###############################################################
#  Generated by:      Cadence Innovus 22.16-s082_1
#  OS:                Linux x86_64(Host ID localhost.localdomain)
#  Generated on:      Fri Apr 10 17:59:03 2026
#  Design:            veer_wrapper
#  Command:           write_lef_abstract -extractBlockObs -cutObsMinSpacing -specifyTopLayer TopMetal2 -5.8 -extractBlockPGPinLayers {TopMetal1 TopMetal2} output/06_postRoute/veer_wrapper.lef
###############################################################

VERSION 5.8 ;

BUSBITCHARS "[]" ;
DIVIDERCHAR "/" ;

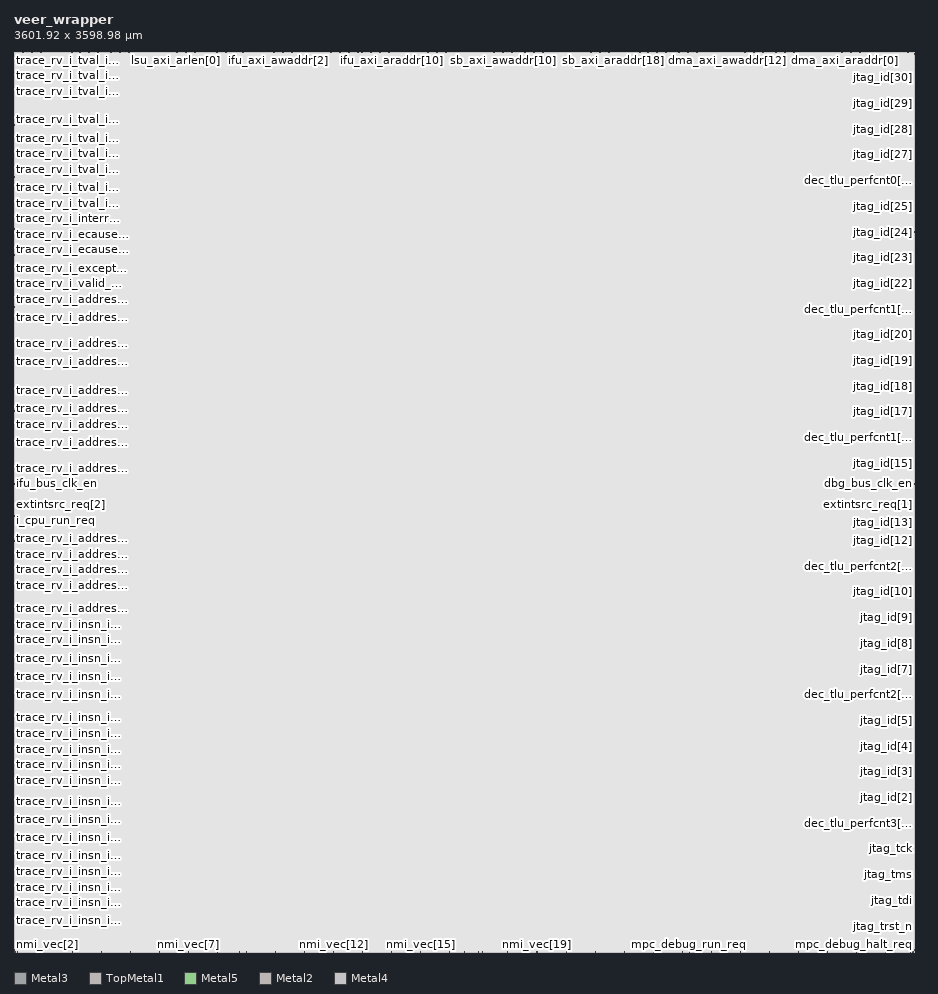
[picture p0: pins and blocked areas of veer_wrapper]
MACRO veer_wrapper
  CLASS BLOCK ;
  SIZE 3601.920000 BY 3598.980000 ;
  FOREIGN veer_wrapper 0.000000 0.000000 ;
  ORIGIN 0 0 ;
  SYMMETRY X Y R90 ;
  PIN clk
    DIRECTION INPUT ;
    USE SIGNAL ;
    PORT
      LAYER Metal3 ;
        RECT 3103.580000 3598.260000 3103.780000 3598.980000 ;
    END
  END clk
  PIN rst_l
    DIRECTION INPUT ;
    USE SIGNAL ;
    PORT
      LAYER Metal3 ;
        RECT 3591.740000 0.000000 3591.940000 0.720000 ;
    END
  END rst_l
  PIN dbg_rst_l
    DIRECTION INPUT ;
    USE SIGNAL ;
    PORT
      LAYER TopMetal1 ;
        RECT 0.000000 1742.600000 1.640000 1744.240000 ;
    END
  END dbg_rst_l
  PIN rst_vec[31]
    DIRECTION INPUT ;
    USE SIGNAL ;
    PORT
      LAYER Metal3 ;
        RECT 3485.180000 0.000000 3485.380000 0.720000 ;
    END
  END rst_vec[31]
  PIN rst_vec[30]
    DIRECTION INPUT ;
    USE SIGNAL ;
    PORT
      LAYER Metal3 ;
        RECT 3369.020000 0.000000 3369.220000 0.720000 ;
    END
  END rst_vec[30]
  PIN rst_vec[29]
    DIRECTION INPUT ;
    USE SIGNAL ;
    PORT
      LAYER Metal3 ;
        RECT 3252.860000 0.000000 3253.060000 0.720000 ;
    END
  END rst_vec[29]
  PIN rst_vec[28]
    DIRECTION INPUT ;
    USE SIGNAL ;
    PORT
      LAYER Metal3 ;
        RECT 3136.700000 0.000000 3136.900000 0.720000 ;
    END
  END rst_vec[28]
  PIN rst_vec[27]
    DIRECTION INPUT ;
    USE SIGNAL ;
    PORT
      LAYER Metal3 ;
        RECT 3020.540000 0.000000 3020.740000 0.720000 ;
    END
  END rst_vec[27]
  PIN rst_vec[26]
    DIRECTION INPUT ;
    USE SIGNAL ;
    PORT
      LAYER Metal3 ;
        RECT 2904.380000 0.000000 2904.580000 0.720000 ;
    END
  END rst_vec[26]
  PIN rst_vec[25]
    DIRECTION INPUT ;
    USE SIGNAL ;
    PORT
      LAYER Metal3 ;
        RECT 2788.220000 0.000000 2788.420000 0.720000 ;
    END
  END rst_vec[25]
  PIN rst_vec[24]
    DIRECTION INPUT ;
    USE SIGNAL ;
    PORT
      LAYER Metal3 ;
        RECT 2672.060000 0.000000 2672.260000 0.720000 ;
    END
  END rst_vec[24]
  PIN rst_vec[23]
    DIRECTION INPUT ;
    USE SIGNAL ;
    PORT
      LAYER Metal3 ;
        RECT 2555.900000 0.000000 2556.100000 0.720000 ;
    END
  END rst_vec[23]
  PIN rst_vec[22]
    DIRECTION INPUT ;
    USE SIGNAL ;
    PORT
      LAYER Metal3 ;
        RECT 2439.740000 0.000000 2439.940000 0.720000 ;
    END
  END rst_vec[22]
  PIN rst_vec[21]
    DIRECTION INPUT ;
    USE SIGNAL ;
    PORT
      LAYER Metal3 ;
        RECT 2323.580000 0.000000 2323.780000 0.720000 ;
    END
  END rst_vec[21]
  PIN rst_vec[20]
    DIRECTION INPUT ;
    USE SIGNAL ;
    PORT
      LAYER Metal3 ;
        RECT 2207.420000 0.000000 2207.620000 0.720000 ;
    END
  END rst_vec[20]
  PIN rst_vec[19]
    DIRECTION INPUT ;
    USE SIGNAL ;
    PORT
      LAYER Metal3 ;
        RECT 2091.260000 0.000000 2091.460000 0.720000 ;
    END
  END rst_vec[19]
  PIN rst_vec[18]
    DIRECTION INPUT ;
    USE SIGNAL ;
    PORT
      LAYER Metal3 ;
        RECT 1975.100000 0.000000 1975.300000 0.720000 ;
    END
  END rst_vec[18]
  PIN rst_vec[17]
    DIRECTION INPUT ;
    USE SIGNAL ;
    PORT
      LAYER Metal3 ;
        RECT 1858.940000 0.000000 1859.140000 0.720000 ;
    END
  END rst_vec[17]
  PIN rst_vec[16]
    DIRECTION INPUT ;
    USE SIGNAL ;
    PORT
      LAYER Metal3 ;
        RECT 1742.780000 0.000000 1742.980000 0.720000 ;
    END
  END rst_vec[16]
  PIN rst_vec[15]
    DIRECTION INPUT ;
    USE SIGNAL ;
    PORT
      LAYER Metal3 ;
        RECT 1626.620000 0.000000 1626.820000 0.720000 ;
    END
  END rst_vec[15]
  PIN rst_vec[14]
    DIRECTION INPUT ;
    USE SIGNAL ;
    PORT
      LAYER Metal3 ;
        RECT 1510.460000 0.000000 1510.660000 0.720000 ;
    END
  END rst_vec[14]
  PIN rst_vec[13]
    DIRECTION INPUT ;
    USE SIGNAL ;
    PORT
      LAYER Metal3 ;
        RECT 1394.300000 0.000000 1394.500000 0.720000 ;
    END
  END rst_vec[13]
  PIN rst_vec[12]
    DIRECTION INPUT ;
    USE SIGNAL ;
    PORT
      LAYER Metal3 ;
        RECT 1278.140000 0.000000 1278.340000 0.720000 ;
    END
  END rst_vec[12]
  PIN rst_vec[11]
    DIRECTION INPUT ;
    USE SIGNAL ;
    PORT
      LAYER Metal3 ;
        RECT 1161.980000 0.000000 1162.180000 0.720000 ;
    END
  END rst_vec[11]
  PIN rst_vec[10]
    DIRECTION INPUT ;
    USE SIGNAL ;
    PORT
      LAYER Metal3 ;
        RECT 1045.820000 0.000000 1046.020000 0.720000 ;
    END
  END rst_vec[10]
  PIN rst_vec[9]
    DIRECTION INPUT ;
    USE SIGNAL ;
    PORT
      LAYER Metal3 ;
        RECT 929.660000 0.000000 929.860000 0.720000 ;
    END
  END rst_vec[9]
  PIN rst_vec[8]
    DIRECTION INPUT ;
    USE SIGNAL ;
    PORT
      LAYER Metal3 ;
        RECT 813.500000 0.000000 813.700000 0.720000 ;
    END
  END rst_vec[8]
  PIN rst_vec[7]
    DIRECTION INPUT ;
    USE SIGNAL ;
    PORT
      LAYER Metal3 ;
        RECT 697.340000 0.000000 697.540000 0.720000 ;
    END
  END rst_vec[7]
  PIN rst_vec[6]
    DIRECTION INPUT ;
    USE SIGNAL ;
    PORT
      LAYER Metal3 ;
        RECT 581.180000 0.000000 581.380000 0.720000 ;
    END
  END rst_vec[6]
  PIN rst_vec[5]
    DIRECTION INPUT ;
    USE SIGNAL ;
    PORT
      LAYER Metal3 ;
        RECT 465.020000 0.000000 465.220000 0.720000 ;
    END
  END rst_vec[5]
  PIN rst_vec[4]
    DIRECTION INPUT ;
    USE SIGNAL ;
    PORT
      LAYER Metal3 ;
        RECT 348.860000 0.000000 349.060000 0.720000 ;
    END
  END rst_vec[4]
  PIN rst_vec[3]
    DIRECTION INPUT ;
    USE SIGNAL ;
    PORT
      LAYER Metal3 ;
        RECT 232.700000 0.000000 232.900000 0.720000 ;
    END
  END rst_vec[3]
  PIN rst_vec[2]
    DIRECTION INPUT ;
    USE SIGNAL ;
    PORT
      LAYER Metal3 ;
        RECT 116.540000 0.000000 116.740000 0.720000 ;
    END
  END rst_vec[2]
  PIN rst_vec[1]
    DIRECTION INPUT ;
    USE SIGNAL ;
    PORT
      LAYER Metal3 ;
        RECT 7.100000 0.000000 7.300000 0.720000 ;
    END
  END rst_vec[1]
  PIN nmi_int
    DIRECTION INPUT ;
    USE SIGNAL ;
    PORT
      LAYER Metal5 ;
        RECT 3597.500000 0.000000 3597.700000 0.720000 ;
    END
  END nmi_int
  PIN nmi_vec[31]
    DIRECTION INPUT ;
    USE SIGNAL ;
    PORT
      LAYER Metal5 ;
        RECT 3485.180000 0.000000 3485.380000 0.720000 ;
    END
  END nmi_vec[31]
  PIN nmi_vec[30]
    DIRECTION INPUT ;
    USE SIGNAL ;
    PORT
      LAYER Metal5 ;
        RECT 3369.020000 0.000000 3369.220000 0.720000 ;
    END
  END nmi_vec[30]
  PIN nmi_vec[29]
    DIRECTION INPUT ;
    USE SIGNAL ;
    PORT
      LAYER Metal5 ;
        RECT 3252.860000 0.000000 3253.060000 0.720000 ;
    END
  END nmi_vec[29]
  PIN nmi_vec[28]
    DIRECTION INPUT ;
    USE SIGNAL ;
    PORT
      LAYER Metal5 ;
        RECT 3136.700000 0.000000 3136.900000 0.720000 ;
    END
  END nmi_vec[28]
  PIN nmi_vec[27]
    DIRECTION INPUT ;
    USE SIGNAL ;
    PORT
      LAYER Metal5 ;
        RECT 3020.540000 0.000000 3020.740000 0.720000 ;
    END
  END nmi_vec[27]
  PIN nmi_vec[26]
    DIRECTION INPUT ;
    USE SIGNAL ;
    PORT
      LAYER Metal5 ;
        RECT 2904.380000 0.000000 2904.580000 0.720000 ;
    END
  END nmi_vec[26]
  PIN nmi_vec[25]
    DIRECTION INPUT ;
    USE SIGNAL ;
    PORT
      LAYER Metal5 ;
        RECT 2788.220000 0.000000 2788.420000 0.720000 ;
    END
  END nmi_vec[25]
  PIN nmi_vec[24]
    DIRECTION INPUT ;
    USE SIGNAL ;
    PORT
      LAYER Metal5 ;
        RECT 2672.060000 0.000000 2672.260000 0.720000 ;
    END
  END nmi_vec[24]
  PIN nmi_vec[23]
    DIRECTION INPUT ;
    USE SIGNAL ;
    PORT
      LAYER Metal5 ;
        RECT 2555.900000 0.000000 2556.100000 0.720000 ;
    END
  END nmi_vec[23]
  PIN nmi_vec[22]
    DIRECTION INPUT ;
    USE SIGNAL ;
    PORT
      LAYER Metal5 ;
        RECT 2439.740000 0.000000 2439.940000 0.720000 ;
    END
  END nmi_vec[22]
  PIN nmi_vec[21]
    DIRECTION INPUT ;
    USE SIGNAL ;
    PORT
      LAYER Metal5 ;
        RECT 2323.580000 0.000000 2323.780000 0.720000 ;
    END
  END nmi_vec[21]
  PIN nmi_vec[20]
    DIRECTION INPUT ;
    USE SIGNAL ;
    PORT
      LAYER Metal5 ;
        RECT 2207.420000 0.000000 2207.620000 0.720000 ;
    END
  END nmi_vec[20]
  PIN nmi_vec[19]
    DIRECTION INPUT ;
    USE SIGNAL ;
    PORT
      LAYER Metal5 ;
        RECT 2091.260000 0.000000 2091.460000 0.720000 ;
    END
  END nmi_vec[19]
  PIN nmi_vec[18]
    DIRECTION INPUT ;
    USE SIGNAL ;
    PORT
      LAYER Metal5 ;
        RECT 1975.100000 0.000000 1975.300000 0.720000 ;
    END
  END nmi_vec[18]
  PIN nmi_vec[17]
    DIRECTION INPUT ;
    USE SIGNAL ;
    PORT
      LAYER Metal5 ;
        RECT 1858.940000 0.000000 1859.140000 0.720000 ;
    END
  END nmi_vec[17]
  PIN nmi_vec[16]
    DIRECTION INPUT ;
    USE SIGNAL ;
    PORT
      LAYER Metal5 ;
        RECT 1742.780000 0.000000 1742.980000 0.720000 ;
    END
  END nmi_vec[16]
  PIN nmi_vec[15]
    DIRECTION INPUT ;
    USE SIGNAL ;
    PORT
      LAYER Metal5 ;
        RECT 1626.620000 0.000000 1626.820000 0.720000 ;
    END
  END nmi_vec[15]
  PIN nmi_vec[14]
    DIRECTION INPUT ;
    USE SIGNAL ;
    PORT
      LAYER Metal5 ;
        RECT 1510.460000 0.000000 1510.660000 0.720000 ;
    END
  END nmi_vec[14]
  PIN nmi_vec[13]
    DIRECTION INPUT ;
    USE SIGNAL ;
    PORT
      LAYER Metal5 ;
        RECT 1394.300000 0.000000 1394.500000 0.720000 ;
    END
  END nmi_vec[13]
  PIN nmi_vec[12]
    DIRECTION INPUT ;
    USE SIGNAL ;
    PORT
      LAYER Metal5 ;
        RECT 1278.140000 0.000000 1278.340000 0.720000 ;
    END
  END nmi_vec[12]
  PIN nmi_vec[11]
    DIRECTION INPUT ;
    USE SIGNAL ;
    PORT
      LAYER Metal5 ;
        RECT 1161.980000 0.000000 1162.180000 0.720000 ;
    END
  END nmi_vec[11]
  PIN nmi_vec[10]
    DIRECTION INPUT ;
    USE SIGNAL ;
    PORT
      LAYER Metal5 ;
        RECT 1045.820000 0.000000 1046.020000 0.720000 ;
    END
  END nmi_vec[10]
  PIN nmi_vec[9]
    DIRECTION INPUT ;
    USE SIGNAL ;
    PORT
      LAYER Metal5 ;
        RECT 929.660000 0.000000 929.860000 0.720000 ;
    END
  END nmi_vec[9]
  PIN nmi_vec[8]
    DIRECTION INPUT ;
    USE SIGNAL ;
    PORT
      LAYER Metal5 ;
        RECT 813.500000 0.000000 813.700000 0.720000 ;
    END
  END nmi_vec[8]
  PIN nmi_vec[7]
    DIRECTION INPUT ;
    USE SIGNAL ;
    PORT
      LAYER Metal5 ;
        RECT 697.340000 0.000000 697.540000 0.720000 ;
    END
  END nmi_vec[7]
  PIN nmi_vec[6]
    DIRECTION INPUT ;
    USE SIGNAL ;
    PORT
      LAYER Metal5 ;
        RECT 581.180000 0.000000 581.380000 0.720000 ;
    END
  END nmi_vec[6]
  PIN nmi_vec[5]
    DIRECTION INPUT ;
    USE SIGNAL ;
    PORT
      LAYER Metal5 ;
        RECT 465.020000 0.000000 465.220000 0.720000 ;
    END
  END nmi_vec[5]
  PIN nmi_vec[4]
    DIRECTION INPUT ;
    USE SIGNAL ;
    PORT
      LAYER Metal5 ;
        RECT 348.860000 0.000000 349.060000 0.720000 ;
    END
  END nmi_vec[4]
  PIN nmi_vec[3]
    DIRECTION INPUT ;
    USE SIGNAL ;
    PORT
      LAYER Metal5 ;
        RECT 232.700000 0.000000 232.900000 0.720000 ;
    END
  END nmi_vec[3]
  PIN nmi_vec[2]
    DIRECTION INPUT ;
    USE SIGNAL ;
    PORT
      LAYER Metal5 ;
        RECT 116.540000 0.000000 116.740000 0.720000 ;
    END
  END nmi_vec[2]
  PIN nmi_vec[1]
    DIRECTION INPUT ;
    USE SIGNAL ;
    PORT
      LAYER Metal5 ;
        RECT 3.740000 0.000000 3.940000 0.720000 ;
    END
  END nmi_vec[1]
  PIN jtag_id[31]
    DIRECTION INPUT ;
    USE SIGNAL ;
    PORT
      LAYER Metal2 ;
        RECT 3601.200000 3590.900000 3601.920000 3591.100000 ;
    END
  END jtag_id[31]
  PIN jtag_id[30]
    DIRECTION INPUT ;
    USE SIGNAL ;
    PORT
      LAYER Metal2 ;
        RECT 3601.200000 3495.980000 3601.920000 3496.180000 ;
    END
  END jtag_id[30]
  PIN jtag_id[29]
    DIRECTION INPUT ;
    USE SIGNAL ;
    PORT
      LAYER Metal2 ;
        RECT 3601.200000 3393.080000 3601.920000 3393.280000 ;
    END
  END jtag_id[29]
  PIN jtag_id[28]
    DIRECTION INPUT ;
    USE SIGNAL ;
    PORT
      LAYER Metal2 ;
        RECT 3601.200000 3290.180000 3601.920000 3290.380000 ;
    END
  END jtag_id[28]
  PIN jtag_id[27]
    DIRECTION INPUT ;
    USE SIGNAL ;
    PORT
      LAYER Metal2 ;
        RECT 3601.200000 3187.280000 3601.920000 3187.480000 ;
    END
  END jtag_id[27]
  PIN jtag_id[26]
    DIRECTION INPUT ;
    USE SIGNAL ;
    PORT
      LAYER Metal2 ;
        RECT 3601.200000 3084.800000 3601.920000 3085.000000 ;
    END
  END jtag_id[26]
  PIN jtag_id[25]
    DIRECTION INPUT ;
    USE SIGNAL ;
    PORT
      LAYER Metal2 ;
        RECT 3601.200000 2981.900000 3601.920000 2982.100000 ;
    END
  END jtag_id[25]
  PIN jtag_id[24]
    DIRECTION INPUT ;
    USE SIGNAL ;
    PORT
      LAYER Metal2 ;
        RECT 3601.200000 2879.000000 3601.920000 2879.200000 ;
    END
  END jtag_id[24]
  PIN jtag_id[23]
    DIRECTION INPUT ;
    USE SIGNAL ;
    PORT
      LAYER Metal2 ;
        RECT 3601.200000 2776.100000 3601.920000 2776.300000 ;
    END
  END jtag_id[23]
  PIN jtag_id[22]
    DIRECTION INPUT ;
    USE SIGNAL ;
    PORT
      LAYER Metal2 ;
        RECT 3601.200000 2673.620000 3601.920000 2673.820000 ;
    END
  END jtag_id[22]
  PIN jtag_id[21]
    DIRECTION INPUT ;
    USE SIGNAL ;
    PORT
      LAYER Metal2 ;
        RECT 3601.200000 2570.720000 3601.920000 2570.920000 ;
    END
  END jtag_id[21]
  PIN jtag_id[20]
    DIRECTION INPUT ;
    USE SIGNAL ;
    PORT
      LAYER Metal2 ;
        RECT 3601.200000 2467.820000 3601.920000 2468.020000 ;
    END
  END jtag_id[20]
  PIN jtag_id[19]
    DIRECTION INPUT ;
    USE SIGNAL ;
    PORT
      LAYER Metal2 ;
        RECT 3601.200000 2364.920000 3601.920000 2365.120000 ;
    END
  END jtag_id[19]
  PIN jtag_id[18]
    DIRECTION INPUT ;
    USE SIGNAL ;
    PORT
      LAYER Metal2 ;
        RECT 3601.200000 2262.020000 3601.920000 2262.220000 ;
    END
  END jtag_id[18]
  PIN jtag_id[17]
    DIRECTION INPUT ;
    USE SIGNAL ;
    PORT
      LAYER Metal2 ;
        RECT 3601.200000 2159.540000 3601.920000 2159.740000 ;
    END
  END jtag_id[17]
  PIN jtag_id[16]
    DIRECTION INPUT ;
    USE SIGNAL ;
    PORT
      LAYER Metal2 ;
        RECT 3601.200000 2056.640000 3601.920000 2056.840000 ;
    END
  END jtag_id[16]
  PIN jtag_id[15]
    DIRECTION INPUT ;
    USE SIGNAL ;
    PORT
      LAYER Metal2 ;
        RECT 3601.200000 1953.740000 3601.920000 1953.940000 ;
    END
  END jtag_id[15]
  PIN jtag_id[14]
    DIRECTION INPUT ;
    USE SIGNAL ;
    PORT
      LAYER Metal2 ;
        RECT 3601.200000 1850.840000 3601.920000 1851.040000 ;
    END
  END jtag_id[14]
  PIN jtag_id[13]
    DIRECTION INPUT ;
    USE SIGNAL ;
    PORT
      LAYER Metal2 ;
        RECT 3601.200000 1748.360000 3601.920000 1748.560000 ;
    END
  END jtag_id[13]
  PIN jtag_id[12]
    DIRECTION INPUT ;
    USE SIGNAL ;
    PORT
      LAYER Metal2 ;
        RECT 3601.200000 1645.460000 3601.920000 1645.660000 ;
    END
  END jtag_id[12]
  PIN jtag_id[11]
    DIRECTION INPUT ;
    USE SIGNAL ;
    PORT
      LAYER Metal2 ;
        RECT 3601.200000 1542.560000 3601.920000 1542.760000 ;
    END
  END jtag_id[11]
  PIN jtag_id[10]
    DIRECTION INPUT ;
    USE SIGNAL ;
    PORT
      LAYER Metal2 ;
        RECT 3601.200000 1439.660000 3601.920000 1439.860000 ;
    END
  END jtag_id[10]
  PIN jtag_id[9]
    DIRECTION INPUT ;
    USE SIGNAL ;
    PORT
      LAYER Metal2 ;
        RECT 3601.200000 1337.180000 3601.920000 1337.380000 ;
    END
  END jtag_id[9]
  PIN jtag_id[8]
    DIRECTION INPUT ;
    USE SIGNAL ;
    PORT
      LAYER Metal2 ;
        RECT 3601.200000 1234.280000 3601.920000 1234.480000 ;
    END
  END jtag_id[8]
  PIN jtag_id[7]
    DIRECTION INPUT ;
    USE SIGNAL ;
    PORT
      LAYER Metal2 ;
        RECT 3601.200000 1131.380000 3601.920000 1131.580000 ;
    END
  END jtag_id[7]
  PIN jtag_id[6]
    DIRECTION INPUT ;
    USE SIGNAL ;
    PORT
      LAYER Metal2 ;
        RECT 3601.200000 1028.480000 3601.920000 1028.680000 ;
    END
  END jtag_id[6]
  PIN jtag_id[5]
    DIRECTION INPUT ;
    USE SIGNAL ;
    PORT
      LAYER Metal2 ;
        RECT 3601.200000 925.580000 3601.920000 925.780000 ;
    END
  END jtag_id[5]
  PIN jtag_id[4]
    DIRECTION INPUT ;
    USE SIGNAL ;
    PORT
      LAYER Metal2 ;
        RECT 3601.200000 823.100000 3601.920000 823.300000 ;
    END
  END jtag_id[4]
  PIN jtag_id[3]
    DIRECTION INPUT ;
    USE SIGNAL ;
    PORT
      LAYER Metal2 ;
        RECT 3601.200000 720.200000 3601.920000 720.400000 ;
    END
  END jtag_id[3]
  PIN jtag_id[2]
    DIRECTION INPUT ;
    USE SIGNAL ;
    PORT
      LAYER Metal2 ;
        RECT 3601.200000 617.300000 3601.920000 617.500000 ;
    END
  END jtag_id[2]
  PIN jtag_id[1]
    DIRECTION INPUT ;
    USE SIGNAL ;
    PORT
      LAYER Metal2 ;
        RECT 3601.200000 514.400000 3601.920000 514.600000 ;
    END
  END jtag_id[1]
  PIN trace_rv_i_insn_ip[63]
    DIRECTION OUTPUT ;
    USE SIGNAL ;
    PORT
      LAYER Metal4 ;
        RECT 0.000000 7.880000 0.720000 8.080000 ;
    END
  END trace_rv_i_insn_ip[63]
  PIN trace_rv_i_insn_ip[62]
    DIRECTION OUTPUT ;
    USE SIGNAL ;
    PORT
      LAYER Metal4 ;
        RECT 0.000000 20.900000 0.720000 21.100000 ;
    END
  END trace_rv_i_insn_ip[62]
  PIN trace_rv_i_insn_ip[61]
    DIRECTION OUTPUT ;
    USE SIGNAL ;
    PORT
      LAYER Metal4 ;
        RECT 0.000000 41.900000 0.720000 42.100000 ;
    END
  END trace_rv_i_insn_ip[61]
  PIN trace_rv_i_insn_ip[60]
    DIRECTION OUTPUT ;
    USE SIGNAL ;
    PORT
      LAYER Metal4 ;
        RECT 0.000000 62.480000 0.720000 62.680000 ;
    END
  END trace_rv_i_insn_ip[60]
  PIN trace_rv_i_insn_ip[59]
    DIRECTION OUTPUT ;
    USE SIGNAL ;
    PORT
      LAYER Metal4 ;
        RECT 0.000000 83.480000 0.720000 83.680000 ;
    END
  END trace_rv_i_insn_ip[59]
  PIN trace_rv_i_insn_ip[58]
    DIRECTION OUTPUT ;
    USE SIGNAL ;
    PORT
      LAYER Metal4 ;
        RECT 0.000000 104.060000 0.720000 104.260000 ;
    END
  END trace_rv_i_insn_ip[58]
  PIN trace_rv_i_insn_ip[57]
    DIRECTION OUTPUT ;
    USE SIGNAL ;
    PORT
      LAYER Metal4 ;
        RECT 0.000000 125.060000 0.720000 125.260000 ;
    END
  END trace_rv_i_insn_ip[57]
  PIN trace_rv_i_insn_ip[56]
    DIRECTION OUTPUT ;
    USE SIGNAL ;
    PORT
      LAYER Metal4 ;
        RECT 0.000000 145.640000 0.720000 145.840000 ;
    END
  END trace_rv_i_insn_ip[56]
  PIN trace_rv_i_insn_ip[55]
    DIRECTION OUTPUT ;
    USE SIGNAL ;
    PORT
      LAYER Metal4 ;
        RECT 0.000000 166.640000 0.720000 166.840000 ;
    END
  END trace_rv_i_insn_ip[55]
  PIN trace_rv_i_insn_ip[54]
    DIRECTION OUTPUT ;
    USE SIGNAL ;
    PORT
      LAYER Metal4 ;
        RECT 0.000000 187.220000 0.720000 187.420000 ;
    END
  END trace_rv_i_insn_ip[54]
  PIN trace_rv_i_insn_ip[53]
    DIRECTION OUTPUT ;
    USE SIGNAL ;
    PORT
      LAYER Metal4 ;
        RECT 0.000000 208.220000 0.720000 208.420000 ;
    END
  END trace_rv_i_insn_ip[53]
  PIN trace_rv_i_insn_ip[52]
    DIRECTION OUTPUT ;
    USE SIGNAL ;
    PORT
      LAYER Metal4 ;
        RECT 0.000000 228.800000 0.720000 229.000000 ;
    END
  END trace_rv_i_insn_ip[52]
  PIN trace_rv_i_insn_ip[51]
    DIRECTION OUTPUT ;
    USE SIGNAL ;
    PORT
      LAYER Metal4 ;
        RECT 0.000000 249.800000 0.720000 250.000000 ;
    END
  END trace_rv_i_insn_ip[51]
  PIN trace_rv_i_insn_ip[50]
    DIRECTION OUTPUT ;
    USE SIGNAL ;
    PORT
      LAYER Metal4 ;
        RECT 0.000000 270.380000 0.720000 270.580000 ;
    END
  END trace_rv_i_insn_ip[50]
  PIN trace_rv_i_insn_ip[49]
    DIRECTION OUTPUT ;
    USE SIGNAL ;
    PORT
      LAYER Metal4 ;
        RECT 0.000000 291.380000 0.720000 291.580000 ;
    END
  END trace_rv_i_insn_ip[49]
  PIN trace_rv_i_insn_ip[48]
    DIRECTION OUTPUT ;
    USE SIGNAL ;
    PORT
      LAYER Metal4 ;
        RECT 0.000000 311.960000 0.720000 312.160000 ;
    END
  END trace_rv_i_insn_ip[48]
  PIN trace_rv_i_insn_ip[47]
    DIRECTION OUTPUT ;
    USE SIGNAL ;
    PORT
      LAYER Metal4 ;
        RECT 0.000000 332.960000 0.720000 333.160000 ;
    END
  END trace_rv_i_insn_ip[47]
  PIN trace_rv_i_insn_ip[46]
    DIRECTION OUTPUT ;
    USE SIGNAL ;
    PORT
      LAYER Metal4 ;
        RECT 0.000000 353.540000 0.720000 353.740000 ;
    END
  END trace_rv_i_insn_ip[46]
  PIN trace_rv_i_insn_ip[45]
    DIRECTION OUTPUT ;
    USE SIGNAL ;
    PORT
      LAYER Metal4 ;
        RECT 0.000000 374.540000 0.720000 374.740000 ;
    END
  END trace_rv_i_insn_ip[45]
  PIN trace_rv_i_insn_ip[44]
    DIRECTION OUTPUT ;
    USE SIGNAL ;
    PORT
      LAYER Metal4 ;
        RECT 0.000000 395.120000 0.720000 395.320000 ;
    END
  END trace_rv_i_insn_ip[44]
  PIN trace_rv_i_insn_ip[43]
    DIRECTION OUTPUT ;
    USE SIGNAL ;
    PORT
      LAYER Metal4 ;
        RECT 0.000000 416.120000 0.720000 416.320000 ;
    END
  END trace_rv_i_insn_ip[43]
  PIN trace_rv_i_insn_ip[42]
    DIRECTION OUTPUT ;
    USE SIGNAL ;
    PORT
      LAYER Metal4 ;
        RECT 0.000000 436.700000 0.720000 436.900000 ;
    END
  END trace_rv_i_insn_ip[42]
  PIN trace_rv_i_insn_ip[41]
    DIRECTION OUTPUT ;
    USE SIGNAL ;
    PORT
      LAYER Metal4 ;
        RECT 0.000000 457.700000 0.720000 457.900000 ;
    END
  END trace_rv_i_insn_ip[41]
  PIN trace_rv_i_insn_ip[40]
    DIRECTION OUTPUT ;
    USE SIGNAL ;
    PORT
      LAYER Metal4 ;
        RECT 0.000000 478.280000 0.720000 478.480000 ;
    END
  END trace_rv_i_insn_ip[40]
  PIN trace_rv_i_insn_ip[39]
    DIRECTION OUTPUT ;
    USE SIGNAL ;
    PORT
      LAYER Metal4 ;
        RECT 0.000000 499.280000 0.720000 499.480000 ;
    END
  END trace_rv_i_insn_ip[39]
  PIN trace_rv_i_insn_ip[38]
    DIRECTION OUTPUT ;
    USE SIGNAL ;
    PORT
      LAYER Metal4 ;
        RECT 0.000000 520.280000 0.720000 520.480000 ;
    END
  END trace_rv_i_insn_ip[38]
  PIN trace_rv_i_insn_ip[37]
    DIRECTION OUTPUT ;
    USE SIGNAL ;
    PORT
      LAYER Metal4 ;
        RECT 0.000000 540.860000 0.720000 541.060000 ;
    END
  END trace_rv_i_insn_ip[37]
  PIN trace_rv_i_insn_ip[36]
    DIRECTION OUTPUT ;
    USE SIGNAL ;
    PORT
      LAYER Metal4 ;
        RECT 0.000000 561.860000 0.720000 562.060000 ;
    END
  END trace_rv_i_insn_ip[36]
  PIN trace_rv_i_insn_ip[35]
    DIRECTION OUTPUT ;
    USE SIGNAL ;
    PORT
      LAYER Metal4 ;
        RECT 0.000000 582.440000 0.720000 582.640000 ;
    END
  END trace_rv_i_insn_ip[35]
  PIN trace_rv_i_insn_ip[34]
    DIRECTION OUTPUT ;
    USE SIGNAL ;
    PORT
      LAYER Metal4 ;
        RECT 0.000000 603.440000 0.720000 603.640000 ;
    END
  END trace_rv_i_insn_ip[34]
  PIN trace_rv_i_insn_ip[33]
    DIRECTION OUTPUT ;
    USE SIGNAL ;
    PORT
      LAYER Metal4 ;
        RECT 0.000000 624.020000 0.720000 624.220000 ;
    END
  END trace_rv_i_insn_ip[33]
  PIN trace_rv_i_insn_ip[32]
    DIRECTION OUTPUT ;
    USE SIGNAL ;
    PORT
      LAYER Metal4 ;
        RECT 0.000000 645.020000 0.720000 645.220000 ;
    END
  END trace_rv_i_insn_ip[32]
  PIN trace_rv_i_insn_ip[31]
    DIRECTION OUTPUT ;
    USE SIGNAL ;
    PORT
      LAYER Metal4 ;
        RECT 0.000000 665.600000 0.720000 665.800000 ;
    END
  END trace_rv_i_insn_ip[31]
  PIN trace_rv_i_insn_ip[30]
    DIRECTION OUTPUT ;
    USE SIGNAL ;
    PORT
      LAYER Metal4 ;
        RECT 0.000000 686.600000 0.720000 686.800000 ;
    END
  END trace_rv_i_insn_ip[30]
  PIN trace_rv_i_insn_ip[29]
    DIRECTION OUTPUT ;
    USE SIGNAL ;
    PORT
      LAYER Metal4 ;
        RECT 0.000000 707.180000 0.720000 707.380000 ;
    END
  END trace_rv_i_insn_ip[29]
  PIN trace_rv_i_insn_ip[28]
    DIRECTION OUTPUT ;
    USE SIGNAL ;
    PORT
      LAYER Metal4 ;
        RECT 0.000000 728.180000 0.720000 728.380000 ;
    END
  END trace_rv_i_insn_ip[28]
  PIN trace_rv_i_insn_ip[27]
    DIRECTION OUTPUT ;
    USE SIGNAL ;
    PORT
      LAYER Metal4 ;
        RECT 0.000000 748.760000 0.720000 748.960000 ;
    END
  END trace_rv_i_insn_ip[27]
  PIN trace_rv_i_insn_ip[26]
    DIRECTION OUTPUT ;
    USE SIGNAL ;
    PORT
      LAYER Metal4 ;
        RECT 0.000000 769.760000 0.720000 769.960000 ;
    END
  END trace_rv_i_insn_ip[26]
  PIN trace_rv_i_insn_ip[25]
    DIRECTION OUTPUT ;
    USE SIGNAL ;
    PORT
      LAYER Metal4 ;
        RECT 0.000000 790.340000 0.720000 790.540000 ;
    END
  END trace_rv_i_insn_ip[25]
  PIN trace_rv_i_insn_ip[24]
    DIRECTION OUTPUT ;
    USE SIGNAL ;
    PORT
      LAYER Metal4 ;
        RECT 0.000000 811.340000 0.720000 811.540000 ;
    END
  END trace_rv_i_insn_ip[24]
  PIN trace_rv_i_insn_ip[23]
    DIRECTION OUTPUT ;
    USE SIGNAL ;
    PORT
      LAYER Metal4 ;
        RECT 0.000000 831.920000 0.720000 832.120000 ;
    END
  END trace_rv_i_insn_ip[23]
  PIN trace_rv_i_insn_ip[22]
    DIRECTION OUTPUT ;
    USE SIGNAL ;
    PORT
      LAYER Metal4 ;
        RECT 0.000000 852.920000 0.720000 853.120000 ;
    END
  END trace_rv_i_insn_ip[22]
  PIN trace_rv_i_insn_ip[21]
    DIRECTION OUTPUT ;
    USE SIGNAL ;
    PORT
      LAYER Metal4 ;
        RECT 0.000000 873.500000 0.720000 873.700000 ;
    END
  END trace_rv_i_insn_ip[21]
  PIN trace_rv_i_insn_ip[20]
    DIRECTION OUTPUT ;
    USE SIGNAL ;
    PORT
      LAYER Metal4 ;
        RECT 0.000000 894.500000 0.720000 894.700000 ;
    END
  END trace_rv_i_insn_ip[20]
  PIN trace_rv_i_insn_ip[19]
    DIRECTION OUTPUT ;
    USE SIGNAL ;
    PORT
      LAYER Metal4 ;
        RECT 0.000000 915.080000 0.720000 915.280000 ;
    END
  END trace_rv_i_insn_ip[19]
  PIN trace_rv_i_insn_ip[18]
    DIRECTION OUTPUT ;
    USE SIGNAL ;
    PORT
      LAYER Metal4 ;
        RECT 0.000000 936.080000 0.720000 936.280000 ;
    END
  END trace_rv_i_insn_ip[18]
  PIN trace_rv_i_insn_ip[17]
    DIRECTION OUTPUT ;
    USE SIGNAL ;
    PORT
      LAYER Metal4 ;
        RECT 0.000000 956.660000 0.720000 956.860000 ;
    END
  END trace_rv_i_insn_ip[17]
  PIN trace_rv_i_insn_ip[16]
    DIRECTION OUTPUT ;
    USE SIGNAL ;
    PORT
      LAYER Metal4 ;
        RECT 0.000000 977.660000 0.720000 977.860000 ;
    END
  END trace_rv_i_insn_ip[16]
  PIN trace_rv_i_insn_ip[15]
    DIRECTION OUTPUT ;
    USE SIGNAL ;
    PORT
      LAYER Metal4 ;
        RECT 0.000000 998.240000 0.720000 998.440000 ;
    END
  END trace_rv_i_insn_ip[15]
  PIN trace_rv_i_insn_ip[14]
    DIRECTION OUTPUT ;
    USE SIGNAL ;
    PORT
      LAYER Metal4 ;
        RECT 0.000000 1019.240000 0.720000 1019.440000 ;
    END
  END trace_rv_i_insn_ip[14]
  PIN trace_rv_i_insn_ip[13]
    DIRECTION OUTPUT ;
    USE SIGNAL ;
    PORT
      LAYER Metal4 ;
        RECT 0.000000 1040.240000 0.720000 1040.440000 ;
    END
  END trace_rv_i_insn_ip[13]
  PIN trace_rv_i_insn_ip[12]
    DIRECTION OUTPUT ;
    USE SIGNAL ;
    PORT
      LAYER Metal4 ;
        RECT 0.000000 1060.820000 0.720000 1061.020000 ;
    END
  END trace_rv_i_insn_ip[12]
  PIN trace_rv_i_insn_ip[11]
    DIRECTION OUTPUT ;
    USE SIGNAL ;
    PORT
      LAYER Metal4 ;
        RECT 0.000000 1081.820000 0.720000 1082.020000 ;
    END
  END trace_rv_i_insn_ip[11]
  PIN trace_rv_i_insn_ip[10]
    DIRECTION OUTPUT ;
    USE SIGNAL ;
    PORT
      LAYER Metal4 ;
        RECT 0.000000 1102.400000 0.720000 1102.600000 ;
    END
  END trace_rv_i_insn_ip[10]
  PIN trace_rv_i_insn_ip[9]
    DIRECTION OUTPUT ;
    USE SIGNAL ;
    PORT
      LAYER Metal4 ;
        RECT 0.000000 1123.400000 0.720000 1123.600000 ;
    END
  END trace_rv_i_insn_ip[9]
  PIN trace_rv_i_insn_ip[8]
    DIRECTION OUTPUT ;
    USE SIGNAL ;
    PORT
      LAYER Metal4 ;
        RECT 0.000000 1143.980000 0.720000 1144.180000 ;
    END
  END trace_rv_i_insn_ip[8]
  PIN trace_rv_i_insn_ip[7]
    DIRECTION OUTPUT ;
    USE SIGNAL ;
    PORT
      LAYER Metal4 ;
        RECT 0.000000 1164.980000 0.720000 1165.180000 ;
    END
  END trace_rv_i_insn_ip[7]
  PIN trace_rv_i_insn_ip[6]
    DIRECTION OUTPUT ;
    USE SIGNAL ;
    PORT
      LAYER Metal4 ;
        RECT 0.000000 1185.560000 0.720000 1185.760000 ;
    END
  END trace_rv_i_insn_ip[6]
  PIN trace_rv_i_insn_ip[5]
    DIRECTION OUTPUT ;
    USE SIGNAL ;
    PORT
      LAYER Metal4 ;
        RECT 0.000000 1206.560000 0.720000 1206.760000 ;
    END
  END trace_rv_i_insn_ip[5]
  PIN trace_rv_i_insn_ip[4]
    DIRECTION OUTPUT ;
    USE SIGNAL ;
    PORT
      LAYER Metal4 ;
        RECT 0.000000 1227.140000 0.720000 1227.340000 ;
    END
  END trace_rv_i_insn_ip[4]
  PIN trace_rv_i_insn_ip[3]
    DIRECTION OUTPUT ;
    USE SIGNAL ;
    PORT
      LAYER Metal4 ;
        RECT 0.000000 1248.140000 0.720000 1248.340000 ;
    END
  END trace_rv_i_insn_ip[3]
  PIN trace_rv_i_insn_ip[2]
    DIRECTION OUTPUT ;
    USE SIGNAL ;
    PORT
      LAYER Metal4 ;
        RECT 0.000000 1268.720000 0.720000 1268.920000 ;
    END
  END trace_rv_i_insn_ip[2]
  PIN trace_rv_i_insn_ip[1]
    DIRECTION OUTPUT ;
    USE SIGNAL ;
    PORT
      LAYER Metal4 ;
        RECT 0.000000 1289.720000 0.720000 1289.920000 ;
    END
  END trace_rv_i_insn_ip[1]
  PIN trace_rv_i_insn_ip[0]
    DIRECTION OUTPUT ;
    USE SIGNAL ;
    PORT
      LAYER Metal4 ;
        RECT 0.000000 1310.300000 0.720000 1310.500000 ;
    END
  END trace_rv_i_insn_ip[0]
  PIN trace_rv_i_address_ip[63]
    DIRECTION OUTPUT ;
    USE SIGNAL ;
    PORT
      LAYER Metal4 ;
        RECT 0.000000 1331.300000 0.720000 1331.500000 ;
    END
  END trace_rv_i_address_ip[63]
  PIN trace_rv_i_address_ip[62]
    DIRECTION OUTPUT ;
    USE SIGNAL ;
    PORT
      LAYER Metal4 ;
        RECT 0.000000 1351.880000 0.720000 1352.080000 ;
    END
  END trace_rv_i_address_ip[62]
  PIN trace_rv_i_address_ip[61]
    DIRECTION OUTPUT ;
    USE SIGNAL ;
    PORT
      LAYER Metal4 ;
        RECT 0.000000 1372.880000 0.720000 1373.080000 ;
    END
  END trace_rv_i_address_ip[61]
  PIN trace_rv_i_address_ip[60]
    DIRECTION OUTPUT ;
    USE SIGNAL ;
    PORT
      LAYER Metal4 ;
        RECT 0.000000 1393.460000 0.720000 1393.660000 ;
    END
  END trace_rv_i_address_ip[60]
  PIN trace_rv_i_address_ip[59]
    DIRECTION OUTPUT ;
    USE SIGNAL ;
    PORT
      LAYER Metal4 ;
        RECT 0.000000 1414.460000 0.720000 1414.660000 ;
    END
  END trace_rv_i_address_ip[59]
  PIN trace_rv_i_address_ip[58]
    DIRECTION OUTPUT ;
    USE SIGNAL ;
    PORT
      LAYER Metal4 ;
        RECT 0.000000 1435.040000 0.720000 1435.240000 ;
    END
  END trace_rv_i_address_ip[58]
  PIN trace_rv_i_address_ip[57]
    DIRECTION OUTPUT ;
    USE SIGNAL ;
    PORT
      LAYER Metal4 ;
        RECT 0.000000 1456.040000 0.720000 1456.240000 ;
    END
  END trace_rv_i_address_ip[57]
  PIN trace_rv_i_address_ip[56]
    DIRECTION OUTPUT ;
    USE SIGNAL ;
    PORT
      LAYER Metal4 ;
        RECT 0.000000 1476.620000 0.720000 1476.820000 ;
    END
  END trace_rv_i_address_ip[56]
  PIN trace_rv_i_address_ip[55]
    DIRECTION OUTPUT ;
    USE SIGNAL ;
    PORT
      LAYER Metal4 ;
        RECT 0.000000 1497.620000 0.720000 1497.820000 ;
    END
  END trace_rv_i_address_ip[55]
  PIN trace_rv_i_address_ip[54]
    DIRECTION OUTPUT ;
    USE SIGNAL ;
    PORT
      LAYER Metal4 ;
        RECT 0.000000 1518.200000 0.720000 1518.400000 ;
    END
  END trace_rv_i_address_ip[54]
  PIN trace_rv_i_address_ip[53]
    DIRECTION OUTPUT ;
    USE SIGNAL ;
    PORT
      LAYER Metal4 ;
        RECT 0.000000 1539.200000 0.720000 1539.400000 ;
    END
  END trace_rv_i_address_ip[53]
  PIN trace_rv_i_address_ip[52]
    DIRECTION OUTPUT ;
    USE SIGNAL ;
    PORT
      LAYER Metal4 ;
        RECT 0.000000 1560.200000 0.720000 1560.400000 ;
    END
  END trace_rv_i_address_ip[52]
  PIN trace_rv_i_address_ip[51]
    DIRECTION OUTPUT ;
    USE SIGNAL ;
    PORT
      LAYER Metal4 ;
        RECT 0.000000 1580.780000 0.720000 1580.980000 ;
    END
  END trace_rv_i_address_ip[51]
  PIN trace_rv_i_address_ip[50]
    DIRECTION OUTPUT ;
    USE SIGNAL ;
    PORT
      LAYER Metal4 ;
        RECT 0.000000 1601.780000 0.720000 1601.980000 ;
    END
  END trace_rv_i_address_ip[50]
  PIN trace_rv_i_address_ip[49]
    DIRECTION OUTPUT ;
    USE SIGNAL ;
    PORT
      LAYER Metal4 ;
        RECT 0.000000 1622.360000 0.720000 1622.560000 ;
    END
  END trace_rv_i_address_ip[49]
  PIN trace_rv_i_address_ip[48]
    DIRECTION OUTPUT ;
    USE SIGNAL ;
    PORT
      LAYER Metal4 ;
        RECT 0.000000 1643.360000 0.720000 1643.560000 ;
    END
  END trace_rv_i_address_ip[48]
  PIN trace_rv_i_address_ip[47]
    DIRECTION OUTPUT ;
    USE SIGNAL ;
    PORT
      LAYER Metal4 ;
        RECT 0.000000 1663.940000 0.720000 1664.140000 ;
    END
  END trace_rv_i_address_ip[47]
  PIN trace_rv_i_address_ip[46]
    DIRECTION OUTPUT ;
    USE SIGNAL ;
    PORT
      LAYER Metal4 ;
        RECT 0.000000 1684.940000 0.720000 1685.140000 ;
    END
  END trace_rv_i_address_ip[46]
  PIN trace_rv_i_address_ip[45]
    DIRECTION OUTPUT ;
    USE SIGNAL ;
    PORT
      LAYER Metal4 ;
        RECT 0.000000 1705.520000 0.720000 1705.720000 ;
    END
  END trace_rv_i_address_ip[45]
  PIN trace_rv_i_address_ip[44]
    DIRECTION OUTPUT ;
    USE SIGNAL ;
    PORT
      LAYER Metal4 ;
        RECT 0.000000 1727.780000 0.720000 1727.980000 ;
    END
  END trace_rv_i_address_ip[44]
  PIN trace_rv_i_address_ip[43]
    DIRECTION OUTPUT ;
    USE SIGNAL ;
    PORT
      LAYER Metal4 ;
        RECT 0.000000 1747.100000 0.720000 1747.300000 ;
    END
  END trace_rv_i_address_ip[43]
  PIN trace_rv_i_address_ip[42]
    DIRECTION OUTPUT ;
    USE SIGNAL ;
    PORT
      LAYER Metal4 ;
        RECT 0.000000 1768.100000 0.720000 1768.300000 ;
    END
  END trace_rv_i_address_ip[42]
  PIN trace_rv_i_address_ip[41]
    DIRECTION OUTPUT ;
    USE SIGNAL ;
    PORT
      LAYER Metal4 ;
        RECT 0.000000 1788.680000 0.720000 1788.880000 ;
    END
  END trace_rv_i_address_ip[41]
  PIN trace_rv_i_address_ip[40]
    DIRECTION OUTPUT ;
    USE SIGNAL ;
    PORT
      LAYER Metal4 ;
        RECT 0.000000 1809.680000 0.720000 1809.880000 ;
    END
  END trace_rv_i_address_ip[40]
  PIN trace_rv_i_address_ip[39]
    DIRECTION OUTPUT ;
    USE SIGNAL ;
    PORT
      LAYER Metal4 ;
        RECT 0.000000 1830.260000 0.720000 1830.460000 ;
    END
  END trace_rv_i_address_ip[39]
  PIN trace_rv_i_address_ip[38]
    DIRECTION OUTPUT ;
    USE SIGNAL ;
    PORT
      LAYER Metal4 ;
        RECT 0.000000 1851.260000 0.720000 1851.460000 ;
    END
  END trace_rv_i_address_ip[38]
  PIN trace_rv_i_address_ip[37]
    DIRECTION OUTPUT ;
    USE SIGNAL ;
    PORT
      LAYER Metal4 ;
        RECT 0.000000 1870.580000 0.720000 1870.780000 ;
    END
  END trace_rv_i_address_ip[37]
  PIN trace_rv_i_address_ip[36]
    DIRECTION OUTPUT ;
    USE SIGNAL ;
    PORT
      LAYER Metal4 ;
        RECT 0.000000 1892.840000 0.720000 1893.040000 ;
    END
  END trace_rv_i_address_ip[36]
  PIN trace_rv_i_address_ip[35]
    DIRECTION OUTPUT ;
    USE SIGNAL ;
    PORT
      LAYER Metal4 ;
        RECT 0.000000 1913.420000 0.720000 1913.620000 ;
    END
  END trace_rv_i_address_ip[35]
  PIN trace_rv_i_address_ip[34]
    DIRECTION OUTPUT ;
    USE SIGNAL ;
    PORT
      LAYER Metal4 ;
        RECT 0.000000 1934.420000 0.720000 1934.620000 ;
    END
  END trace_rv_i_address_ip[34]
  PIN trace_rv_i_address_ip[33]
    DIRECTION OUTPUT ;
    USE SIGNAL ;
    PORT
      LAYER Metal4 ;
        RECT 0.000000 1955.000000 0.720000 1955.200000 ;
    END
  END trace_rv_i_address_ip[33]
  PIN trace_rv_i_address_ip[32]
    DIRECTION OUTPUT ;
    USE SIGNAL ;
    PORT
      LAYER Metal4 ;
        RECT 0.000000 1976.000000 0.720000 1976.200000 ;
    END
  END trace_rv_i_address_ip[32]
  PIN trace_rv_i_address_ip[31]
    DIRECTION OUTPUT ;
    USE SIGNAL ;
    PORT
      LAYER Metal4 ;
        RECT 0.000000 1996.580000 0.720000 1996.780000 ;
    END
  END trace_rv_i_address_ip[31]
  PIN trace_rv_i_address_ip[30]
    DIRECTION OUTPUT ;
    USE SIGNAL ;
    PORT
      LAYER Metal4 ;
        RECT 0.000000 2017.580000 0.720000 2017.780000 ;
    END
  END trace_rv_i_address_ip[30]
  PIN trace_rv_i_address_ip[29]
    DIRECTION OUTPUT ;
    USE SIGNAL ;
    PORT
      LAYER Metal4 ;
        RECT 0.000000 2038.160000 0.720000 2038.360000 ;
    END
  END trace_rv_i_address_ip[29]
  PIN trace_rv_i_address_ip[28]
    DIRECTION OUTPUT ;
    USE SIGNAL ;
    PORT
      LAYER Metal4 ;
        RECT 0.000000 2059.160000 0.720000 2059.360000 ;
    END
  END trace_rv_i_address_ip[28]
  PIN trace_rv_i_address_ip[27]
    DIRECTION OUTPUT ;
    USE SIGNAL ;
    PORT
      LAYER Metal4 ;
        RECT 0.000000 2080.160000 0.720000 2080.360000 ;
    END
  END trace_rv_i_address_ip[27]
  PIN trace_rv_i_address_ip[26]
    DIRECTION OUTPUT ;
    USE SIGNAL ;
    PORT
      LAYER Metal4 ;
        RECT 0.000000 2100.740000 0.720000 2100.940000 ;
    END
  END trace_rv_i_address_ip[26]
  PIN trace_rv_i_address_ip[25]
    DIRECTION OUTPUT ;
    USE SIGNAL ;
    PORT
      LAYER Metal4 ;
        RECT 0.000000 2121.740000 0.720000 2121.940000 ;
    END
  END trace_rv_i_address_ip[25]
  PIN trace_rv_i_address_ip[24]
    DIRECTION OUTPUT ;
    USE SIGNAL ;
    PORT
      LAYER Metal4 ;
        RECT 0.000000 2142.320000 0.720000 2142.520000 ;
    END
  END trace_rv_i_address_ip[24]
  PIN trace_rv_i_address_ip[23]
    DIRECTION OUTPUT ;
    USE SIGNAL ;
    PORT
      LAYER Metal4 ;
        RECT 0.000000 2163.320000 0.720000 2163.520000 ;
    END
  END trace_rv_i_address_ip[23]
  PIN trace_rv_i_address_ip[22]
    DIRECTION OUTPUT ;
    USE SIGNAL ;
    PORT
      LAYER Metal4 ;
        RECT 0.000000 2183.900000 0.720000 2184.100000 ;
    END
  END trace_rv_i_address_ip[22]
  PIN trace_rv_i_address_ip[21]
    DIRECTION OUTPUT ;
    USE SIGNAL ;
    PORT
      LAYER Metal4 ;
        RECT 0.000000 2204.900000 0.720000 2205.100000 ;
    END
  END trace_rv_i_address_ip[21]
  PIN trace_rv_i_address_ip[20]
    DIRECTION OUTPUT ;
    USE SIGNAL ;
    PORT
      LAYER Metal4 ;
        RECT 0.000000 2225.480000 0.720000 2225.680000 ;
    END
  END trace_rv_i_address_ip[20]
  PIN trace_rv_i_address_ip[19]
    DIRECTION OUTPUT ;
    USE SIGNAL ;
    PORT
      LAYER Metal4 ;
        RECT 0.000000 2246.480000 0.720000 2246.680000 ;
    END
  END trace_rv_i_address_ip[19]
  PIN trace_rv_i_address_ip[18]
    DIRECTION OUTPUT ;
    USE SIGNAL ;
    PORT
      LAYER Metal4 ;
        RECT 0.000000 2267.060000 0.720000 2267.260000 ;
    END
  END trace_rv_i_address_ip[18]
  PIN trace_rv_i_address_ip[17]
    DIRECTION OUTPUT ;
    USE SIGNAL ;
    PORT
      LAYER Metal4 ;
        RECT 0.000000 2288.060000 0.720000 2288.260000 ;
    END
  END trace_rv_i_address_ip[17]
  PIN trace_rv_i_address_ip[16]
    DIRECTION OUTPUT ;
    USE SIGNAL ;
    PORT
      LAYER Metal4 ;
        RECT 0.000000 2308.640000 0.720000 2308.840000 ;
    END
  END trace_rv_i_address_ip[16]
  PIN trace_rv_i_address_ip[15]
    DIRECTION OUTPUT ;
    USE SIGNAL ;
    PORT
      LAYER Metal4 ;
        RECT 0.000000 2329.640000 0.720000 2329.840000 ;
    END
  END trace_rv_i_address_ip[15]
  PIN trace_rv_i_address_ip[14]
    DIRECTION OUTPUT ;
    USE SIGNAL ;
    PORT
      LAYER Metal4 ;
        RECT 0.000000 2350.220000 0.720000 2350.420000 ;
    END
  END trace_rv_i_address_ip[14]
  PIN trace_rv_i_address_ip[13]
    DIRECTION OUTPUT ;
    USE SIGNAL ;
    PORT
      LAYER Metal4 ;
        RECT 0.000000 2371.220000 0.720000 2371.420000 ;
    END
  END trace_rv_i_address_ip[13]
  PIN trace_rv_i_address_ip[12]
    DIRECTION OUTPUT ;
    USE SIGNAL ;
    PORT
      LAYER Metal4 ;
        RECT 0.000000 2391.800000 0.720000 2392.000000 ;
    END
  END trace_rv_i_address_ip[12]
  PIN trace_rv_i_address_ip[11]
    DIRECTION OUTPUT ;
    USE SIGNAL ;
    PORT
      LAYER Metal4 ;
        RECT 0.000000 2412.800000 0.720000 2413.000000 ;
    END
  END trace_rv_i_address_ip[11]
  PIN trace_rv_i_address_ip[10]
    DIRECTION OUTPUT ;
    USE SIGNAL ;
    PORT
      LAYER Metal4 ;
        RECT 0.000000 2433.380000 0.720000 2433.580000 ;
    END
  END trace_rv_i_address_ip[10]
  PIN trace_rv_i_address_ip[9]
    DIRECTION OUTPUT ;
    USE SIGNAL ;
    PORT
      LAYER Metal4 ;
        RECT 0.000000 2454.380000 0.720000 2454.580000 ;
    END
  END trace_rv_i_address_ip[9]
  PIN trace_rv_i_address_ip[8]
    DIRECTION OUTPUT ;
    USE SIGNAL ;
    PORT
      LAYER Metal4 ;
        RECT 0.000000 2474.960000 0.720000 2475.160000 ;
    END
  END trace_rv_i_address_ip[8]
  PIN trace_rv_i_address_ip[7]
    DIRECTION OUTPUT ;
    USE SIGNAL ;
    PORT
      LAYER Metal4 ;
        RECT 0.000000 2495.960000 0.720000 2496.160000 ;
    END
  END trace_rv_i_address_ip[7]
  PIN trace_rv_i_address_ip[6]
    DIRECTION OUTPUT ;
    USE SIGNAL ;
    PORT
      LAYER Metal4 ;
        RECT 0.000000 2516.540000 0.720000 2516.740000 ;
    END
  END trace_rv_i_address_ip[6]
  PIN trace_rv_i_address_ip[5]
    DIRECTION OUTPUT ;
    USE SIGNAL ;
    PORT
      LAYER Metal4 ;
        RECT 0.000000 2537.540000 0.720000 2537.740000 ;
    END
  END trace_rv_i_address_ip[5]
  PIN trace_rv_i_address_ip[4]
    DIRECTION OUTPUT ;
    USE SIGNAL ;
    PORT
      LAYER Metal4 ;
        RECT 0.000000 2558.120000 0.720000 2558.320000 ;
    END
  END trace_rv_i_address_ip[4]
  PIN trace_rv_i_address_ip[3]
    DIRECTION OUTPUT ;
    USE SIGNAL ;
    PORT
      LAYER Metal4 ;
        RECT 0.000000 2579.120000 0.720000 2579.320000 ;
    END
  END trace_rv_i_address_ip[3]
  PIN trace_rv_i_address_ip[2]
    DIRECTION OUTPUT ;
    USE SIGNAL ;
    PORT
      LAYER Metal4 ;
        RECT 0.000000 2600.120000 0.720000 2600.320000 ;
    END
  END trace_rv_i_address_ip[2]
  PIN trace_rv_i_address_ip[1]
    DIRECTION OUTPUT ;
    USE SIGNAL ;
    PORT
      LAYER Metal4 ;
        RECT 0.000000 2620.700000 0.720000 2620.900000 ;
    END
  END trace_rv_i_address_ip[1]
  PIN trace_rv_i_address_ip[0]
    DIRECTION OUTPUT ;
    USE SIGNAL ;
    PORT
      LAYER Metal4 ;
        RECT 0.000000 2641.700000 0.720000 2641.900000 ;
    END
  END trace_rv_i_address_ip[0]
  PIN trace_rv_i_valid_ip[2]
    DIRECTION OUTPUT ;
    USE SIGNAL ;
    PORT
      LAYER Metal4 ;
        RECT 0.000000 2662.280000 0.720000 2662.480000 ;
    END
  END trace_rv_i_valid_ip[2]
  PIN trace_rv_i_valid_ip[1]
    DIRECTION OUTPUT ;
    USE SIGNAL ;
    PORT
      LAYER Metal4 ;
        RECT 0.000000 2683.280000 0.720000 2683.480000 ;
    END
  END trace_rv_i_valid_ip[1]
  PIN trace_rv_i_valid_ip[0]
    DIRECTION OUTPUT ;
    USE SIGNAL ;
    PORT
      LAYER Metal4 ;
        RECT 0.000000 2703.860000 0.720000 2704.060000 ;
    END
  END trace_rv_i_valid_ip[0]
  PIN trace_rv_i_exception_ip[2]
    DIRECTION OUTPUT ;
    USE SIGNAL ;
    PORT
      LAYER Metal4 ;
        RECT 0.000000 2724.860000 0.720000 2725.060000 ;
    END
  END trace_rv_i_exception_ip[2]
  PIN trace_rv_i_exception_ip[1]
    DIRECTION OUTPUT ;
    USE SIGNAL ;
    PORT
      LAYER Metal4 ;
        RECT 0.000000 2745.440000 0.720000 2745.640000 ;
    END
  END trace_rv_i_exception_ip[1]
  PIN trace_rv_i_exception_ip[0]
    DIRECTION OUTPUT ;
    USE SIGNAL ;
    PORT
      LAYER Metal4 ;
        RECT 0.000000 2766.440000 0.720000 2766.640000 ;
    END
  END trace_rv_i_exception_ip[0]
  PIN trace_rv_i_ecause_ip[4]
    DIRECTION OUTPUT ;
    USE SIGNAL ;
    PORT
      LAYER Metal4 ;
        RECT 0.000000 2787.020000 0.720000 2787.220000 ;
    END
  END trace_rv_i_ecause_ip[4]
  PIN trace_rv_i_ecause_ip[3]
    DIRECTION OUTPUT ;
    USE SIGNAL ;
    PORT
      LAYER Metal4 ;
        RECT 0.000000 2808.020000 0.720000 2808.220000 ;
    END
  END trace_rv_i_ecause_ip[3]
  PIN trace_rv_i_ecause_ip[2]
    DIRECTION OUTPUT ;
    USE SIGNAL ;
    PORT
      LAYER Metal4 ;
        RECT 0.000000 2828.600000 0.720000 2828.800000 ;
    END
  END trace_rv_i_ecause_ip[2]
  PIN trace_rv_i_ecause_ip[1]
    DIRECTION OUTPUT ;
    USE SIGNAL ;
    PORT
      LAYER Metal4 ;
        RECT 0.000000 2849.600000 0.720000 2849.800000 ;
    END
  END trace_rv_i_ecause_ip[1]
  PIN trace_rv_i_ecause_ip[0]
    DIRECTION OUTPUT ;
    USE SIGNAL ;
    PORT
      LAYER Metal4 ;
        RECT 0.000000 2870.180000 0.720000 2870.380000 ;
    END
  END trace_rv_i_ecause_ip[0]
  PIN trace_rv_i_interrupt_ip[2]
    DIRECTION OUTPUT ;
    USE SIGNAL ;
    PORT
      LAYER Metal4 ;
        RECT 0.000000 2891.180000 0.720000 2891.380000 ;
    END
  END trace_rv_i_interrupt_ip[2]
  PIN trace_rv_i_interrupt_ip[1]
    DIRECTION OUTPUT ;
    USE SIGNAL ;
    PORT
      LAYER Metal4 ;
        RECT 0.000000 2911.760000 0.720000 2911.960000 ;
    END
  END trace_rv_i_interrupt_ip[1]
  PIN trace_rv_i_interrupt_ip[0]
    DIRECTION OUTPUT ;
    USE SIGNAL ;
    PORT
      LAYER Metal4 ;
        RECT 0.000000 2932.760000 0.720000 2932.960000 ;
    END
  END trace_rv_i_interrupt_ip[0]
  PIN trace_rv_i_tval_ip[31]
    DIRECTION OUTPUT ;
    USE SIGNAL ;
    PORT
      LAYER Metal4 ;
        RECT 0.000000 2953.340000 0.720000 2953.540000 ;
    END
  END trace_rv_i_tval_ip[31]
  PIN trace_rv_i_tval_ip[30]
    DIRECTION OUTPUT ;
    USE SIGNAL ;
    PORT
      LAYER Metal4 ;
        RECT 0.000000 2974.340000 0.720000 2974.540000 ;
    END
  END trace_rv_i_tval_ip[30]
  PIN trace_rv_i_tval_ip[29]
    DIRECTION OUTPUT ;
    USE SIGNAL ;
    PORT
      LAYER Metal4 ;
        RECT 0.000000 2994.920000 0.720000 2995.120000 ;
    END
  END trace_rv_i_tval_ip[29]
  PIN trace_rv_i_tval_ip[28]
    DIRECTION OUTPUT ;
    USE SIGNAL ;
    PORT
      LAYER Metal4 ;
        RECT 0.000000 3015.920000 0.720000 3016.120000 ;
    END
  END trace_rv_i_tval_ip[28]
  PIN trace_rv_i_tval_ip[27]
    DIRECTION OUTPUT ;
    USE SIGNAL ;
    PORT
      LAYER Metal4 ;
        RECT 0.000000 3036.500000 0.720000 3036.700000 ;
    END
  END trace_rv_i_tval_ip[27]
  PIN trace_rv_i_tval_ip[26]
    DIRECTION OUTPUT ;
    USE SIGNAL ;
    PORT
      LAYER Metal4 ;
        RECT 0.000000 3057.500000 0.720000 3057.700000 ;
    END
  END trace_rv_i_tval_ip[26]
  PIN trace_rv_i_tval_ip[25]
    DIRECTION OUTPUT ;
    USE SIGNAL ;
    PORT
      LAYER Metal4 ;
        RECT 0.000000 3078.080000 0.720000 3078.280000 ;
    END
  END trace_rv_i_tval_ip[25]
  PIN trace_rv_i_tval_ip[24]
    DIRECTION OUTPUT ;
    USE SIGNAL ;
    PORT
      LAYER Metal4 ;
        RECT 0.000000 3099.080000 0.720000 3099.280000 ;
    END
  END trace_rv_i_tval_ip[24]
  PIN trace_rv_i_tval_ip[23]
    DIRECTION OUTPUT ;
    USE SIGNAL ;
    PORT
      LAYER Metal4 ;
        RECT 0.000000 3120.080000 0.720000 3120.280000 ;
    END
  END trace_rv_i_tval_ip[23]
  PIN trace_rv_i_tval_ip[22]
    DIRECTION OUTPUT ;
    USE SIGNAL ;
    PORT
      LAYER Metal4 ;
        RECT 0.000000 3140.660000 0.720000 3140.860000 ;
    END
  END trace_rv_i_tval_ip[22]
  PIN trace_rv_i_tval_ip[21]
    DIRECTION OUTPUT ;
    USE SIGNAL ;
    PORT
      LAYER Metal4 ;
        RECT 0.000000 3161.660000 0.720000 3161.860000 ;
    END
  END trace_rv_i_tval_ip[21]
  PIN trace_rv_i_tval_ip[20]
    DIRECTION OUTPUT ;
    USE SIGNAL ;
    PORT
      LAYER Metal4 ;
        RECT 0.000000 3182.240000 0.720000 3182.440000 ;
    END
  END trace_rv_i_tval_ip[20]
  PIN trace_rv_i_tval_ip[19]
    DIRECTION OUTPUT ;
    USE SIGNAL ;
    PORT
      LAYER Metal4 ;
        RECT 0.000000 3203.240000 0.720000 3203.440000 ;
    END
  END trace_rv_i_tval_ip[19]
  PIN trace_rv_i_tval_ip[18]
    DIRECTION OUTPUT ;
    USE SIGNAL ;
    PORT
      LAYER Metal4 ;
        RECT 0.000000 3223.820000 0.720000 3224.020000 ;
    END
  END trace_rv_i_tval_ip[18]
  PIN trace_rv_i_tval_ip[17]
    DIRECTION OUTPUT ;
    USE SIGNAL ;
    PORT
      LAYER Metal4 ;
        RECT 0.000000 3244.820000 0.720000 3245.020000 ;
    END
  END trace_rv_i_tval_ip[17]
  PIN trace_rv_i_tval_ip[16]
    DIRECTION OUTPUT ;
    USE SIGNAL ;
    PORT
      LAYER Metal4 ;
        RECT 0.000000 3265.400000 0.720000 3265.600000 ;
    END
  END trace_rv_i_tval_ip[16]
  PIN trace_rv_i_tval_ip[15]
    DIRECTION OUTPUT ;
    USE SIGNAL ;
    PORT
      LAYER Metal4 ;
        RECT 0.000000 3286.400000 0.720000 3286.600000 ;
    END
  END trace_rv_i_tval_ip[15]
  PIN trace_rv_i_tval_ip[14]
    DIRECTION OUTPUT ;
    USE SIGNAL ;
    PORT
      LAYER Metal4 ;
        RECT 0.000000 3306.980000 0.720000 3307.180000 ;
    END
  END trace_rv_i_tval_ip[14]
  PIN trace_rv_i_tval_ip[13]
    DIRECTION OUTPUT ;
    USE SIGNAL ;
    PORT
      LAYER Metal4 ;
        RECT 0.000000 3327.980000 0.720000 3328.180000 ;
    END
  END trace_rv_i_tval_ip[13]
  PIN trace_rv_i_tval_ip[12]
    DIRECTION OUTPUT ;
    USE SIGNAL ;
    PORT
      LAYER Metal4 ;
        RECT 0.000000 3348.560000 0.720000 3348.760000 ;
    END
  END trace_rv_i_tval_ip[12]
  PIN trace_rv_i_tval_ip[11]
    DIRECTION OUTPUT ;
    USE SIGNAL ;
    PORT
      LAYER Metal4 ;
        RECT 0.000000 3369.560000 0.720000 3369.760000 ;
    END
  END trace_rv_i_tval_ip[11]
  PIN trace_rv_i_tval_ip[10]
    DIRECTION OUTPUT ;
    USE SIGNAL ;
    PORT
      LAYER Metal4 ;
        RECT 0.000000 3390.140000 0.720000 3390.340000 ;
    END
  END trace_rv_i_tval_ip[10]
  PIN trace_rv_i_tval_ip[9]
    DIRECTION OUTPUT ;
    USE SIGNAL ;
    PORT
      LAYER Metal4 ;
        RECT 0.000000 3411.140000 0.720000 3411.340000 ;
    END
  END trace_rv_i_tval_ip[9]
  PIN trace_rv_i_tval_ip[8]
    DIRECTION OUTPUT ;
    USE SIGNAL ;
    PORT
      LAYER Metal4 ;
        RECT 0.000000 3431.720000 0.720000 3431.920000 ;
    END
  END trace_rv_i_tval_ip[8]
  PIN trace_rv_i_tval_ip[7]
    DIRECTION OUTPUT ;
    USE SIGNAL ;
    PORT
      LAYER Metal4 ;
        RECT 0.000000 3452.720000 0.720000 3452.920000 ;
    END
  END trace_rv_i_tval_ip[7]
  PIN trace_rv_i_tval_ip[6]
    DIRECTION OUTPUT ;
    USE SIGNAL ;
    PORT
      LAYER Metal4 ;
        RECT 0.000000 3473.300000 0.720000 3473.500000 ;
    END
  END trace_rv_i_tval_ip[6]
  PIN trace_rv_i_tval_ip[5]
    DIRECTION OUTPUT ;
    USE SIGNAL ;
    PORT
      LAYER Metal4 ;
        RECT 0.000000 3494.300000 0.720000 3494.500000 ;
    END
  END trace_rv_i_tval_ip[5]
  PIN trace_rv_i_tval_ip[4]
    DIRECTION OUTPUT ;
    USE SIGNAL ;
    PORT
      LAYER Metal4 ;
        RECT 0.000000 3514.880000 0.720000 3515.080000 ;
    END
  END trace_rv_i_tval_ip[4]
  PIN trace_rv_i_tval_ip[3]
    DIRECTION OUTPUT ;
    USE SIGNAL ;
    PORT
      LAYER Metal4 ;
        RECT 0.000000 3535.880000 0.720000 3536.080000 ;
    END
  END trace_rv_i_tval_ip[3]
  PIN trace_rv_i_tval_ip[2]
    DIRECTION OUTPUT ;
    USE SIGNAL ;
    PORT
      LAYER Metal4 ;
        RECT 0.000000 3556.460000 0.720000 3556.660000 ;
    END
  END trace_rv_i_tval_ip[2]
  PIN trace_rv_i_tval_ip[1]
    DIRECTION OUTPUT ;
    USE SIGNAL ;
    PORT
      LAYER Metal4 ;
        RECT 0.000000 3577.460000 0.720000 3577.660000 ;
    END
  END trace_rv_i_tval_ip[1]
  PIN trace_rv_i_tval_ip[0]
    DIRECTION OUTPUT ;
    USE SIGNAL ;
    PORT
      LAYER Metal4 ;
        RECT 0.000000 3591.740000 0.720000 3591.940000 ;
    END
  END trace_rv_i_tval_ip[0]
  PIN lsu_axi_awvalid
    DIRECTION OUTPUT ;
    USE SIGNAL ;
    PORT
      LAYER Metal3 ;
        RECT 3.740000 3598.260000 3.940000 3598.980000 ;
    END
  END lsu_axi_awvalid
  PIN lsu_axi_awready
    DIRECTION INPUT ;
    USE SIGNAL ;
    PORT
      LAYER Metal3 ;
        RECT 6.620000 3598.260000 6.820000 3598.980000 ;
    END
  END lsu_axi_awready
  PIN lsu_axi_awid[3]
    DIRECTION OUTPUT ;
    USE SIGNAL ;
    PORT
      LAYER Metal3 ;
        RECT 9.500000 3598.260000 9.700000 3598.980000 ;
    END
  END lsu_axi_awid[3]
  PIN lsu_axi_awid[2]
    DIRECTION OUTPUT ;
    USE SIGNAL ;
    PORT
      LAYER Metal3 ;
        RECT 12.380000 3598.260000 12.580000 3598.980000 ;
    END
  END lsu_axi_awid[2]
  PIN lsu_axi_awid[1]
    DIRECTION OUTPUT ;
    USE SIGNAL ;
    PORT
      LAYER Metal3 ;
        RECT 14.300000 3598.260000 14.500000 3598.980000 ;
    END
  END lsu_axi_awid[1]
  PIN lsu_axi_awid[0]
    DIRECTION OUTPUT ;
    USE SIGNAL ;
    PORT
      LAYER Metal3 ;
        RECT 17.660000 3598.260000 17.860000 3598.980000 ;
    END
  END lsu_axi_awid[0]
  PIN lsu_axi_awaddr[31]
    DIRECTION OUTPUT ;
    USE SIGNAL ;
    PORT
      LAYER Metal3 ;
        RECT 19.580000 3598.260000 19.780000 3598.980000 ;
    END
  END lsu_axi_awaddr[31]
  PIN lsu_axi_awaddr[30]
    DIRECTION OUTPUT ;
    USE SIGNAL ;
    PORT
      LAYER Metal3 ;
        RECT 22.940000 3598.260000 23.140000 3598.980000 ;
    END
  END lsu_axi_awaddr[30]
  PIN lsu_axi_awaddr[29]
    DIRECTION OUTPUT ;
    USE SIGNAL ;
    PORT
      LAYER Metal3 ;
        RECT 26.300000 3598.260000 26.500000 3598.980000 ;
    END
  END lsu_axi_awaddr[29]
  PIN lsu_axi_awaddr[28]
    DIRECTION OUTPUT ;
    USE SIGNAL ;
    PORT
      LAYER Metal3 ;
        RECT 29.660000 3598.260000 29.860000 3598.980000 ;
    END
  END lsu_axi_awaddr[28]
  PIN lsu_axi_awaddr[27]
    DIRECTION OUTPUT ;
    USE SIGNAL ;
    PORT
      LAYER Metal3 ;
        RECT 32.540000 3598.260000 32.740000 3598.980000 ;
    END
  END lsu_axi_awaddr[27]
  PIN lsu_axi_awaddr[26]
    DIRECTION OUTPUT ;
    USE SIGNAL ;
    PORT
      LAYER Metal3 ;
        RECT 35.900000 3598.260000 36.100000 3598.980000 ;
    END
  END lsu_axi_awaddr[26]
  PIN lsu_axi_awaddr[25]
    DIRECTION OUTPUT ;
    USE SIGNAL ;
    PORT
      LAYER Metal3 ;
        RECT 39.260000 3598.260000 39.460000 3598.980000 ;
    END
  END lsu_axi_awaddr[25]
  PIN lsu_axi_awaddr[24]
    DIRECTION OUTPUT ;
    USE SIGNAL ;
    PORT
      LAYER Metal3 ;
        RECT 42.620000 3598.260000 42.820000 3598.980000 ;
    END
  END lsu_axi_awaddr[24]
  PIN lsu_axi_awaddr[23]
    DIRECTION OUTPUT ;
    USE SIGNAL ;
    PORT
      LAYER Metal3 ;
        RECT 45.980000 3598.260000 46.180000 3598.980000 ;
    END
  END lsu_axi_awaddr[23]
  PIN lsu_axi_awaddr[22]
    DIRECTION OUTPUT ;
    USE SIGNAL ;
    PORT
      LAYER Metal3 ;
        RECT 48.860000 3598.260000 49.060000 3598.980000 ;
    END
  END lsu_axi_awaddr[22]
  PIN lsu_axi_awaddr[21]
    DIRECTION OUTPUT ;
    USE SIGNAL ;
    PORT
      LAYER Metal3 ;
        RECT 52.220000 3598.260000 52.420000 3598.980000 ;
    END
  END lsu_axi_awaddr[21]
  PIN lsu_axi_awaddr[20]
    DIRECTION OUTPUT ;
    USE SIGNAL ;
    PORT
      LAYER Metal3 ;
        RECT 55.580000 3598.260000 55.780000 3598.980000 ;
    END
  END lsu_axi_awaddr[20]
  PIN lsu_axi_awaddr[19]
    DIRECTION OUTPUT ;
    USE SIGNAL ;
    PORT
      LAYER Metal3 ;
        RECT 58.940000 3598.260000 59.140000 3598.980000 ;
    END
  END lsu_axi_awaddr[19]
  PIN lsu_axi_awaddr[18]
    DIRECTION OUTPUT ;
    USE SIGNAL ;
    PORT
      LAYER Metal3 ;
        RECT 61.820000 3598.260000 62.020000 3598.980000 ;
    END
  END lsu_axi_awaddr[18]
  PIN lsu_axi_awaddr[17]
    DIRECTION OUTPUT ;
    USE SIGNAL ;
    PORT
      LAYER Metal3 ;
        RECT 65.180000 3598.260000 65.380000 3598.980000 ;
    END
  END lsu_axi_awaddr[17]
  PIN lsu_axi_awaddr[16]
    DIRECTION OUTPUT ;
    USE SIGNAL ;
    PORT
      LAYER Metal3 ;
        RECT 68.540000 3598.260000 68.740000 3598.980000 ;
    END
  END lsu_axi_awaddr[16]
  PIN lsu_axi_awaddr[15]
    DIRECTION OUTPUT ;
    USE SIGNAL ;
    PORT
      LAYER Metal3 ;
        RECT 71.900000 3598.260000 72.100000 3598.980000 ;
    END
  END lsu_axi_awaddr[15]
  PIN lsu_axi_awaddr[14]
    DIRECTION OUTPUT ;
    USE SIGNAL ;
    PORT
      LAYER Metal3 ;
        RECT 75.260000 3598.260000 75.460000 3598.980000 ;
    END
  END lsu_axi_awaddr[14]
  PIN lsu_axi_awaddr[13]
    DIRECTION OUTPUT ;
    USE SIGNAL ;
    PORT
      LAYER Metal3 ;
        RECT 78.140000 3598.260000 78.340000 3598.980000 ;
    END
  END lsu_axi_awaddr[13]
  PIN lsu_axi_awaddr[12]
    DIRECTION OUTPUT ;
    USE SIGNAL ;
    PORT
      LAYER Metal3 ;
        RECT 81.500000 3598.260000 81.700000 3598.980000 ;
    END
  END lsu_axi_awaddr[12]
  PIN lsu_axi_awaddr[11]
    DIRECTION OUTPUT ;
    USE SIGNAL ;
    PORT
      LAYER Metal3 ;
        RECT 84.860000 3598.260000 85.060000 3598.980000 ;
    END
  END lsu_axi_awaddr[11]
  PIN lsu_axi_awaddr[10]
    DIRECTION OUTPUT ;
    USE SIGNAL ;
    PORT
      LAYER Metal3 ;
        RECT 88.220000 3598.260000 88.420000 3598.980000 ;
    END
  END lsu_axi_awaddr[10]
  PIN lsu_axi_awaddr[9]
    DIRECTION OUTPUT ;
    USE SIGNAL ;
    PORT
      LAYER Metal3 ;
        RECT 91.580000 3598.260000 91.780000 3598.980000 ;
    END
  END lsu_axi_awaddr[9]
  PIN lsu_axi_awaddr[8]
    DIRECTION OUTPUT ;
    USE SIGNAL ;
    PORT
      LAYER Metal3 ;
        RECT 94.460000 3598.260000 94.660000 3598.980000 ;
    END
  END lsu_axi_awaddr[8]
  PIN lsu_axi_awaddr[7]
    DIRECTION OUTPUT ;
    USE SIGNAL ;
    PORT
      LAYER Metal3 ;
        RECT 97.820000 3598.260000 98.020000 3598.980000 ;
    END
  END lsu_axi_awaddr[7]
  PIN lsu_axi_awaddr[6]
    DIRECTION OUTPUT ;
    USE SIGNAL ;
    PORT
      LAYER Metal3 ;
        RECT 101.180000 3598.260000 101.380000 3598.980000 ;
    END
  END lsu_axi_awaddr[6]
  PIN lsu_axi_awaddr[5]
    DIRECTION OUTPUT ;
    USE SIGNAL ;
    PORT
      LAYER Metal3 ;
        RECT 104.540000 3598.260000 104.740000 3598.980000 ;
    END
  END lsu_axi_awaddr[5]
  PIN lsu_axi_awaddr[4]
    DIRECTION OUTPUT ;
    USE SIGNAL ;
    PORT
      LAYER Metal3 ;
        RECT 107.900000 3598.260000 108.100000 3598.980000 ;
    END
  END lsu_axi_awaddr[4]
  PIN lsu_axi_awaddr[3]
    DIRECTION OUTPUT ;
    USE SIGNAL ;
    PORT
      LAYER Metal3 ;
        RECT 110.780000 3598.260000 110.980000 3598.980000 ;
    END
  END lsu_axi_awaddr[3]
  PIN lsu_axi_awaddr[2]
    DIRECTION OUTPUT ;
    USE SIGNAL ;
    PORT
      LAYER Metal3 ;
        RECT 114.140000 3598.260000 114.340000 3598.980000 ;
    END
  END lsu_axi_awaddr[2]
  PIN lsu_axi_awaddr[1]
    DIRECTION OUTPUT ;
    USE SIGNAL ;
    PORT
      LAYER Metal3 ;
        RECT 117.500000 3598.260000 117.700000 3598.980000 ;
    END
  END lsu_axi_awaddr[1]
  PIN lsu_axi_awaddr[0]
    DIRECTION OUTPUT ;
    USE SIGNAL ;
    PORT
      LAYER Metal3 ;
        RECT 120.860000 3598.260000 121.060000 3598.980000 ;
    END
  END lsu_axi_awaddr[0]
  PIN lsu_axi_awregion[3]
    DIRECTION OUTPUT ;
    USE SIGNAL ;
    PORT
      LAYER Metal3 ;
        RECT 123.740000 3598.260000 123.940000 3598.980000 ;
    END
  END lsu_axi_awregion[3]
  PIN lsu_axi_awregion[2]
    DIRECTION OUTPUT ;
    USE SIGNAL ;
    PORT
      LAYER Metal3 ;
        RECT 127.100000 3598.260000 127.300000 3598.980000 ;
    END
  END lsu_axi_awregion[2]
  PIN lsu_axi_awregion[1]
    DIRECTION OUTPUT ;
    USE SIGNAL ;
    PORT
      LAYER Metal3 ;
        RECT 130.460000 3598.260000 130.660000 3598.980000 ;
    END
  END lsu_axi_awregion[1]
  PIN lsu_axi_awregion[0]
    DIRECTION OUTPUT ;
    USE SIGNAL ;
    PORT
      LAYER Metal3 ;
        RECT 133.820000 3598.260000 134.020000 3598.980000 ;
    END
  END lsu_axi_awregion[0]
  PIN lsu_axi_awlen[7]
    DIRECTION OUTPUT ;
    USE SIGNAL ;
    PORT
      LAYER Metal3 ;
        RECT 137.180000 3598.260000 137.380000 3598.980000 ;
    END
  END lsu_axi_awlen[7]
  PIN lsu_axi_awlen[6]
    DIRECTION OUTPUT ;
    USE SIGNAL ;
    PORT
      LAYER Metal3 ;
        RECT 140.060000 3598.260000 140.260000 3598.980000 ;
    END
  END lsu_axi_awlen[6]
  PIN lsu_axi_awlen[5]
    DIRECTION OUTPUT ;
    USE SIGNAL ;
    PORT
      LAYER Metal3 ;
        RECT 143.420000 3598.260000 143.620000 3598.980000 ;
    END
  END lsu_axi_awlen[5]
  PIN lsu_axi_awlen[4]
    DIRECTION OUTPUT ;
    USE SIGNAL ;
    PORT
      LAYER Metal3 ;
        RECT 146.780000 3598.260000 146.980000 3598.980000 ;
    END
  END lsu_axi_awlen[4]
  PIN lsu_axi_awlen[3]
    DIRECTION OUTPUT ;
    USE SIGNAL ;
    PORT
      LAYER Metal3 ;
        RECT 150.140000 3598.260000 150.340000 3598.980000 ;
    END
  END lsu_axi_awlen[3]
  PIN lsu_axi_awlen[2]
    DIRECTION OUTPUT ;
    USE SIGNAL ;
    PORT
      LAYER Metal3 ;
        RECT 153.500000 3598.260000 153.700000 3598.980000 ;
    END
  END lsu_axi_awlen[2]
  PIN lsu_axi_awlen[1]
    DIRECTION OUTPUT ;
    USE SIGNAL ;
    PORT
      LAYER Metal3 ;
        RECT 156.380000 3598.260000 156.580000 3598.980000 ;
    END
  END lsu_axi_awlen[1]
  PIN lsu_axi_awlen[0]
    DIRECTION OUTPUT ;
    USE SIGNAL ;
    PORT
      LAYER Metal3 ;
        RECT 159.740000 3598.260000 159.940000 3598.980000 ;
    END
  END lsu_axi_awlen[0]
  PIN lsu_axi_awsize[2]
    DIRECTION OUTPUT ;
    USE SIGNAL ;
    PORT
      LAYER Metal3 ;
        RECT 163.100000 3598.260000 163.300000 3598.980000 ;
    END
  END lsu_axi_awsize[2]
  PIN lsu_axi_awsize[1]
    DIRECTION OUTPUT ;
    USE SIGNAL ;
    PORT
      LAYER Metal3 ;
        RECT 166.460000 3598.260000 166.660000 3598.980000 ;
    END
  END lsu_axi_awsize[1]
  PIN lsu_axi_awsize[0]
    DIRECTION OUTPUT ;
    USE SIGNAL ;
    PORT
      LAYER Metal3 ;
        RECT 169.820000 3598.260000 170.020000 3598.980000 ;
    END
  END lsu_axi_awsize[0]
  PIN lsu_axi_awburst[1]
    DIRECTION OUTPUT ;
    USE SIGNAL ;
    PORT
      LAYER Metal3 ;
        RECT 172.700000 3598.260000 172.900000 3598.980000 ;
    END
  END lsu_axi_awburst[1]
  PIN lsu_axi_awburst[0]
    DIRECTION OUTPUT ;
    USE SIGNAL ;
    PORT
      LAYER Metal3 ;
        RECT 176.060000 3598.260000 176.260000 3598.980000 ;
    END
  END lsu_axi_awburst[0]
  PIN lsu_axi_awlock
    DIRECTION OUTPUT ;
    USE SIGNAL ;
    PORT
      LAYER Metal3 ;
        RECT 179.420000 3598.260000 179.620000 3598.980000 ;
    END
  END lsu_axi_awlock
  PIN lsu_axi_awcache[3]
    DIRECTION OUTPUT ;
    USE SIGNAL ;
    PORT
      LAYER Metal3 ;
        RECT 182.780000 3598.260000 182.980000 3598.980000 ;
    END
  END lsu_axi_awcache[3]
  PIN lsu_axi_awcache[2]
    DIRECTION OUTPUT ;
    USE SIGNAL ;
    PORT
      LAYER Metal3 ;
        RECT 185.660000 3598.260000 185.860000 3598.980000 ;
    END
  END lsu_axi_awcache[2]
  PIN lsu_axi_awcache[1]
    DIRECTION OUTPUT ;
    USE SIGNAL ;
    PORT
      LAYER Metal3 ;
        RECT 189.020000 3598.260000 189.220000 3598.980000 ;
    END
  END lsu_axi_awcache[1]
  PIN lsu_axi_awcache[0]
    DIRECTION OUTPUT ;
    USE SIGNAL ;
    PORT
      LAYER Metal3 ;
        RECT 192.380000 3598.260000 192.580000 3598.980000 ;
    END
  END lsu_axi_awcache[0]
  PIN lsu_axi_awprot[2]
    DIRECTION OUTPUT ;
    USE SIGNAL ;
    PORT
      LAYER Metal3 ;
        RECT 195.740000 3598.260000 195.940000 3598.980000 ;
    END
  END lsu_axi_awprot[2]
  PIN lsu_axi_awprot[1]
    DIRECTION OUTPUT ;
    USE SIGNAL ;
    PORT
      LAYER Metal3 ;
        RECT 199.100000 3598.260000 199.300000 3598.980000 ;
    END
  END lsu_axi_awprot[1]
  PIN lsu_axi_awprot[0]
    DIRECTION OUTPUT ;
    USE SIGNAL ;
    PORT
      LAYER Metal3 ;
        RECT 201.980000 3598.260000 202.180000 3598.980000 ;
    END
  END lsu_axi_awprot[0]
  PIN lsu_axi_awqos[3]
    DIRECTION OUTPUT ;
    USE SIGNAL ;
    PORT
      LAYER Metal3 ;
        RECT 205.340000 3598.260000 205.540000 3598.980000 ;
    END
  END lsu_axi_awqos[3]
  PIN lsu_axi_awqos[2]
    DIRECTION OUTPUT ;
    USE SIGNAL ;
    PORT
      LAYER Metal3 ;
        RECT 208.700000 3598.260000 208.900000 3598.980000 ;
    END
  END lsu_axi_awqos[2]
  PIN lsu_axi_awqos[1]
    DIRECTION OUTPUT ;
    USE SIGNAL ;
    PORT
      LAYER Metal3 ;
        RECT 212.060000 3598.260000 212.260000 3598.980000 ;
    END
  END lsu_axi_awqos[1]
  PIN lsu_axi_awqos[0]
    DIRECTION OUTPUT ;
    USE SIGNAL ;
    PORT
      LAYER Metal3 ;
        RECT 215.420000 3598.260000 215.620000 3598.980000 ;
    END
  END lsu_axi_awqos[0]
  PIN lsu_axi_wvalid
    DIRECTION OUTPUT ;
    USE SIGNAL ;
    PORT
      LAYER Metal3 ;
        RECT 218.300000 3598.260000 218.500000 3598.980000 ;
    END
  END lsu_axi_wvalid
  PIN lsu_axi_wready
    DIRECTION INPUT ;
    USE SIGNAL ;
    PORT
      LAYER Metal3 ;
        RECT 221.660000 3598.260000 221.860000 3598.980000 ;
    END
  END lsu_axi_wready
  PIN lsu_axi_wdata[63]
    DIRECTION OUTPUT ;
    USE SIGNAL ;
    PORT
      LAYER Metal3 ;
        RECT 225.020000 3598.260000 225.220000 3598.980000 ;
    END
  END lsu_axi_wdata[63]
  PIN lsu_axi_wdata[62]
    DIRECTION OUTPUT ;
    USE SIGNAL ;
    PORT
      LAYER Metal3 ;
        RECT 228.380000 3598.260000 228.580000 3598.980000 ;
    END
  END lsu_axi_wdata[62]
  PIN lsu_axi_wdata[61]
    DIRECTION OUTPUT ;
    USE SIGNAL ;
    PORT
      LAYER Metal3 ;
        RECT 231.740000 3598.260000 231.940000 3598.980000 ;
    END
  END lsu_axi_wdata[61]
  PIN lsu_axi_wdata[60]
    DIRECTION OUTPUT ;
    USE SIGNAL ;
    PORT
      LAYER Metal3 ;
        RECT 234.620000 3598.260000 234.820000 3598.980000 ;
    END
  END lsu_axi_wdata[60]
  PIN lsu_axi_wdata[59]
    DIRECTION OUTPUT ;
    USE SIGNAL ;
    PORT
      LAYER Metal3 ;
        RECT 237.980000 3598.260000 238.180000 3598.980000 ;
    END
  END lsu_axi_wdata[59]
  PIN lsu_axi_wdata[58]
    DIRECTION OUTPUT ;
    USE SIGNAL ;
    PORT
      LAYER Metal3 ;
        RECT 241.340000 3598.260000 241.540000 3598.980000 ;
    END
  END lsu_axi_wdata[58]
  PIN lsu_axi_wdata[57]
    DIRECTION OUTPUT ;
    USE SIGNAL ;
    PORT
      LAYER Metal3 ;
        RECT 244.700000 3598.260000 244.900000 3598.980000 ;
    END
  END lsu_axi_wdata[57]
  PIN lsu_axi_wdata[56]
    DIRECTION OUTPUT ;
    USE SIGNAL ;
    PORT
      LAYER Metal3 ;
        RECT 247.580000 3598.260000 247.780000 3598.980000 ;
    END
  END lsu_axi_wdata[56]
  PIN lsu_axi_wdata[55]
    DIRECTION OUTPUT ;
    USE SIGNAL ;
    PORT
      LAYER Metal3 ;
        RECT 250.940000 3598.260000 251.140000 3598.980000 ;
    END
  END lsu_axi_wdata[55]
  PIN lsu_axi_wdata[54]
    DIRECTION OUTPUT ;
    USE SIGNAL ;
    PORT
      LAYER Metal3 ;
        RECT 254.300000 3598.260000 254.500000 3598.980000 ;
    END
  END lsu_axi_wdata[54]
  PIN lsu_axi_wdata[53]
    DIRECTION OUTPUT ;
    USE SIGNAL ;
    PORT
      LAYER Metal3 ;
        RECT 257.660000 3598.260000 257.860000 3598.980000 ;
    END
  END lsu_axi_wdata[53]
  PIN lsu_axi_wdata[52]
    DIRECTION OUTPUT ;
    USE SIGNAL ;
    PORT
      LAYER Metal3 ;
        RECT 261.020000 3598.260000 261.220000 3598.980000 ;
    END
  END lsu_axi_wdata[52]
  PIN lsu_axi_wdata[51]
    DIRECTION OUTPUT ;
    USE SIGNAL ;
    PORT
      LAYER Metal3 ;
        RECT 263.900000 3598.260000 264.100000 3598.980000 ;
    END
  END lsu_axi_wdata[51]
  PIN lsu_axi_wdata[50]
    DIRECTION OUTPUT ;
    USE SIGNAL ;
    PORT
      LAYER Metal3 ;
        RECT 267.260000 3598.260000 267.460000 3598.980000 ;
    END
  END lsu_axi_wdata[50]
  PIN lsu_axi_wdata[49]
    DIRECTION OUTPUT ;
    USE SIGNAL ;
    PORT
      LAYER Metal3 ;
        RECT 270.620000 3598.260000 270.820000 3598.980000 ;
    END
  END lsu_axi_wdata[49]
  PIN lsu_axi_wdata[48]
    DIRECTION OUTPUT ;
    USE SIGNAL ;
    PORT
      LAYER Metal3 ;
        RECT 273.980000 3598.260000 274.180000 3598.980000 ;
    END
  END lsu_axi_wdata[48]
  PIN lsu_axi_wdata[47]
    DIRECTION OUTPUT ;
    USE SIGNAL ;
    PORT
      LAYER Metal3 ;
        RECT 277.340000 3598.260000 277.540000 3598.980000 ;
    END
  END lsu_axi_wdata[47]
  PIN lsu_axi_wdata[46]
    DIRECTION OUTPUT ;
    USE SIGNAL ;
    PORT
      LAYER Metal3 ;
        RECT 280.220000 3598.260000 280.420000 3598.980000 ;
    END
  END lsu_axi_wdata[46]
  PIN lsu_axi_wdata[45]
    DIRECTION OUTPUT ;
    USE SIGNAL ;
    PORT
      LAYER Metal3 ;
        RECT 283.580000 3598.260000 283.780000 3598.980000 ;
    END
  END lsu_axi_wdata[45]
  PIN lsu_axi_wdata[44]
    DIRECTION OUTPUT ;
    USE SIGNAL ;
    PORT
      LAYER Metal3 ;
        RECT 286.940000 3598.260000 287.140000 3598.980000 ;
    END
  END lsu_axi_wdata[44]
  PIN lsu_axi_wdata[43]
    DIRECTION OUTPUT ;
    USE SIGNAL ;
    PORT
      LAYER Metal3 ;
        RECT 290.300000 3598.260000 290.500000 3598.980000 ;
    END
  END lsu_axi_wdata[43]
  PIN lsu_axi_wdata[42]
    DIRECTION OUTPUT ;
    USE SIGNAL ;
    PORT
      LAYER Metal3 ;
        RECT 293.660000 3598.260000 293.860000 3598.980000 ;
    END
  END lsu_axi_wdata[42]
  PIN lsu_axi_wdata[41]
    DIRECTION OUTPUT ;
    USE SIGNAL ;
    PORT
      LAYER Metal3 ;
        RECT 296.540000 3598.260000 296.740000 3598.980000 ;
    END
  END lsu_axi_wdata[41]
  PIN lsu_axi_wdata[40]
    DIRECTION OUTPUT ;
    USE SIGNAL ;
    PORT
      LAYER Metal3 ;
        RECT 299.900000 3598.260000 300.100000 3598.980000 ;
    END
  END lsu_axi_wdata[40]
  PIN lsu_axi_wdata[39]
    DIRECTION OUTPUT ;
    USE SIGNAL ;
    PORT
      LAYER Metal3 ;
        RECT 303.260000 3598.260000 303.460000 3598.980000 ;
    END
  END lsu_axi_wdata[39]
  PIN lsu_axi_wdata[38]
    DIRECTION OUTPUT ;
    USE SIGNAL ;
    PORT
      LAYER Metal3 ;
        RECT 306.620000 3598.260000 306.820000 3598.980000 ;
    END
  END lsu_axi_wdata[38]
  PIN lsu_axi_wdata[37]
    DIRECTION OUTPUT ;
    USE SIGNAL ;
    PORT
      LAYER Metal3 ;
        RECT 309.500000 3598.260000 309.700000 3598.980000 ;
    END
  END lsu_axi_wdata[37]
  PIN lsu_axi_wdata[36]
    DIRECTION OUTPUT ;
    USE SIGNAL ;
    PORT
      LAYER Metal3 ;
        RECT 312.860000 3598.260000 313.060000 3598.980000 ;
    END
  END lsu_axi_wdata[36]
  PIN lsu_axi_wdata[35]
    DIRECTION OUTPUT ;
    USE SIGNAL ;
    PORT
      LAYER Metal3 ;
        RECT 316.220000 3598.260000 316.420000 3598.980000 ;
    END
  END lsu_axi_wdata[35]
  PIN lsu_axi_wdata[34]
    DIRECTION OUTPUT ;
    USE SIGNAL ;
    PORT
      LAYER Metal3 ;
        RECT 319.580000 3598.260000 319.780000 3598.980000 ;
    END
  END lsu_axi_wdata[34]
  PIN lsu_axi_wdata[33]
    DIRECTION OUTPUT ;
    USE SIGNAL ;
    PORT
      LAYER Metal3 ;
        RECT 322.940000 3598.260000 323.140000 3598.980000 ;
    END
  END lsu_axi_wdata[33]
  PIN lsu_axi_wdata[32]
    DIRECTION OUTPUT ;
    USE SIGNAL ;
    PORT
      LAYER Metal3 ;
        RECT 325.820000 3598.260000 326.020000 3598.980000 ;
    END
  END lsu_axi_wdata[32]
  PIN lsu_axi_wdata[31]
    DIRECTION OUTPUT ;
    USE SIGNAL ;
    PORT
      LAYER Metal3 ;
        RECT 329.180000 3598.260000 329.380000 3598.980000 ;
    END
  END lsu_axi_wdata[31]
  PIN lsu_axi_wdata[30]
    DIRECTION OUTPUT ;
    USE SIGNAL ;
    PORT
      LAYER Metal3 ;
        RECT 332.540000 3598.260000 332.740000 3598.980000 ;
    END
  END lsu_axi_wdata[30]
  PIN lsu_axi_wdata[29]
    DIRECTION OUTPUT ;
    USE SIGNAL ;
    PORT
      LAYER Metal3 ;
        RECT 335.900000 3598.260000 336.100000 3598.980000 ;
    END
  END lsu_axi_wdata[29]
  PIN lsu_axi_wdata[28]
    DIRECTION OUTPUT ;
    USE SIGNAL ;
    PORT
      LAYER Metal3 ;
        RECT 339.260000 3598.260000 339.460000 3598.980000 ;
    END
  END lsu_axi_wdata[28]
  PIN lsu_axi_wdata[27]
    DIRECTION OUTPUT ;
    USE SIGNAL ;
    PORT
      LAYER Metal3 ;
        RECT 342.140000 3598.260000 342.340000 3598.980000 ;
    END
  END lsu_axi_wdata[27]
  PIN lsu_axi_wdata[26]
    DIRECTION OUTPUT ;
    USE SIGNAL ;
    PORT
      LAYER Metal3 ;
        RECT 345.500000 3598.260000 345.700000 3598.980000 ;
    END
  END lsu_axi_wdata[26]
  PIN lsu_axi_wdata[25]
    DIRECTION OUTPUT ;
    USE SIGNAL ;
    PORT
      LAYER Metal3 ;
        RECT 348.860000 3598.260000 349.060000 3598.980000 ;
    END
  END lsu_axi_wdata[25]
  PIN lsu_axi_wdata[24]
    DIRECTION OUTPUT ;
    USE SIGNAL ;
    PORT
      LAYER Metal3 ;
        RECT 352.220000 3598.260000 352.420000 3598.980000 ;
    END
  END lsu_axi_wdata[24]
  PIN lsu_axi_wdata[23]
    DIRECTION OUTPUT ;
    USE SIGNAL ;
    PORT
      LAYER Metal3 ;
        RECT 355.580000 3598.260000 355.780000 3598.980000 ;
    END
  END lsu_axi_wdata[23]
  PIN lsu_axi_wdata[22]
    DIRECTION OUTPUT ;
    USE SIGNAL ;
    PORT
      LAYER Metal3 ;
        RECT 358.460000 3598.260000 358.660000 3598.980000 ;
    END
  END lsu_axi_wdata[22]
  PIN lsu_axi_wdata[21]
    DIRECTION OUTPUT ;
    USE SIGNAL ;
    PORT
      LAYER Metal3 ;
        RECT 361.820000 3598.260000 362.020000 3598.980000 ;
    END
  END lsu_axi_wdata[21]
  PIN lsu_axi_wdata[20]
    DIRECTION OUTPUT ;
    USE SIGNAL ;
    PORT
      LAYER Metal3 ;
        RECT 365.180000 3598.260000 365.380000 3598.980000 ;
    END
  END lsu_axi_wdata[20]
  PIN lsu_axi_wdata[19]
    DIRECTION OUTPUT ;
    USE SIGNAL ;
    PORT
      LAYER Metal3 ;
        RECT 368.540000 3598.260000 368.740000 3598.980000 ;
    END
  END lsu_axi_wdata[19]
  PIN lsu_axi_wdata[18]
    DIRECTION OUTPUT ;
    USE SIGNAL ;
    PORT
      LAYER Metal3 ;
        RECT 371.420000 3598.260000 371.620000 3598.980000 ;
    END
  END lsu_axi_wdata[18]
  PIN lsu_axi_wdata[17]
    DIRECTION OUTPUT ;
    USE SIGNAL ;
    PORT
      LAYER Metal3 ;
        RECT 374.780000 3598.260000 374.980000 3598.980000 ;
    END
  END lsu_axi_wdata[17]
  PIN lsu_axi_wdata[16]
    DIRECTION OUTPUT ;
    USE SIGNAL ;
    PORT
      LAYER Metal3 ;
        RECT 378.140000 3598.260000 378.340000 3598.980000 ;
    END
  END lsu_axi_wdata[16]
  PIN lsu_axi_wdata[15]
    DIRECTION OUTPUT ;
    USE SIGNAL ;
    PORT
      LAYER Metal3 ;
        RECT 381.500000 3598.260000 381.700000 3598.980000 ;
    END
  END lsu_axi_wdata[15]
  PIN lsu_axi_wdata[14]
    DIRECTION OUTPUT ;
    USE SIGNAL ;
    PORT
      LAYER Metal3 ;
        RECT 384.860000 3598.260000 385.060000 3598.980000 ;
    END
  END lsu_axi_wdata[14]
  PIN lsu_axi_wdata[13]
    DIRECTION OUTPUT ;
    USE SIGNAL ;
    PORT
      LAYER Metal3 ;
        RECT 387.740000 3598.260000 387.940000 3598.980000 ;
    END
  END lsu_axi_wdata[13]
  PIN lsu_axi_wdata[12]
    DIRECTION OUTPUT ;
    USE SIGNAL ;
    PORT
      LAYER Metal3 ;
        RECT 391.100000 3598.260000 391.300000 3598.980000 ;
    END
  END lsu_axi_wdata[12]
  PIN lsu_axi_wdata[11]
    DIRECTION OUTPUT ;
    USE SIGNAL ;
    PORT
      LAYER Metal3 ;
        RECT 394.460000 3598.260000 394.660000 3598.980000 ;
    END
  END lsu_axi_wdata[11]
  PIN lsu_axi_wdata[10]
    DIRECTION OUTPUT ;
    USE SIGNAL ;
    PORT
      LAYER Metal3 ;
        RECT 397.820000 3598.260000 398.020000 3598.980000 ;
    END
  END lsu_axi_wdata[10]
  PIN lsu_axi_wdata[9]
    DIRECTION OUTPUT ;
    USE SIGNAL ;
    PORT
      LAYER Metal3 ;
        RECT 401.180000 3598.260000 401.380000 3598.980000 ;
    END
  END lsu_axi_wdata[9]
  PIN lsu_axi_wdata[8]
    DIRECTION OUTPUT ;
    USE SIGNAL ;
    PORT
      LAYER Metal3 ;
        RECT 404.060000 3598.260000 404.260000 3598.980000 ;
    END
  END lsu_axi_wdata[8]
  PIN lsu_axi_wdata[7]
    DIRECTION OUTPUT ;
    USE SIGNAL ;
    PORT
      LAYER Metal3 ;
        RECT 407.420000 3598.260000 407.620000 3598.980000 ;
    END
  END lsu_axi_wdata[7]
  PIN lsu_axi_wdata[6]
    DIRECTION OUTPUT ;
    USE SIGNAL ;
    PORT
      LAYER Metal3 ;
        RECT 410.780000 3598.260000 410.980000 3598.980000 ;
    END
  END lsu_axi_wdata[6]
  PIN lsu_axi_wdata[5]
    DIRECTION OUTPUT ;
    USE SIGNAL ;
    PORT
      LAYER Metal3 ;
        RECT 414.140000 3598.260000 414.340000 3598.980000 ;
    END
  END lsu_axi_wdata[5]
  PIN lsu_axi_wdata[4]
    DIRECTION OUTPUT ;
    USE SIGNAL ;
    PORT
      LAYER Metal3 ;
        RECT 417.500000 3598.260000 417.700000 3598.980000 ;
    END
  END lsu_axi_wdata[4]
  PIN lsu_axi_wdata[3]
    DIRECTION OUTPUT ;
    USE SIGNAL ;
    PORT
      LAYER Metal3 ;
        RECT 420.380000 3598.260000 420.580000 3598.980000 ;
    END
  END lsu_axi_wdata[3]
  PIN lsu_axi_wdata[2]
    DIRECTION OUTPUT ;
    USE SIGNAL ;
    PORT
      LAYER Metal3 ;
        RECT 423.740000 3598.260000 423.940000 3598.980000 ;
    END
  END lsu_axi_wdata[2]
  PIN lsu_axi_wdata[1]
    DIRECTION OUTPUT ;
    USE SIGNAL ;
    PORT
      LAYER Metal3 ;
        RECT 427.100000 3598.260000 427.300000 3598.980000 ;
    END
  END lsu_axi_wdata[1]
  PIN lsu_axi_wdata[0]
    DIRECTION OUTPUT ;
    USE SIGNAL ;
    PORT
      LAYER Metal3 ;
        RECT 430.460000 3598.260000 430.660000 3598.980000 ;
    END
  END lsu_axi_wdata[0]
  PIN lsu_axi_wstrb[7]
    DIRECTION OUTPUT ;
    USE SIGNAL ;
    PORT
      LAYER Metal3 ;
        RECT 433.340000 3598.260000 433.540000 3598.980000 ;
    END
  END lsu_axi_wstrb[7]
  PIN lsu_axi_wstrb[6]
    DIRECTION OUTPUT ;
    USE SIGNAL ;
    PORT
      LAYER Metal3 ;
        RECT 436.700000 3598.260000 436.900000 3598.980000 ;
    END
  END lsu_axi_wstrb[6]
  PIN lsu_axi_wstrb[5]
    DIRECTION OUTPUT ;
    USE SIGNAL ;
    PORT
      LAYER Metal3 ;
        RECT 440.060000 3598.260000 440.260000 3598.980000 ;
    END
  END lsu_axi_wstrb[5]
  PIN lsu_axi_wstrb[4]
    DIRECTION OUTPUT ;
    USE SIGNAL ;
    PORT
      LAYER Metal3 ;
        RECT 443.420000 3598.260000 443.620000 3598.980000 ;
    END
  END lsu_axi_wstrb[4]
  PIN lsu_axi_wstrb[3]
    DIRECTION OUTPUT ;
    USE SIGNAL ;
    PORT
      LAYER Metal3 ;
        RECT 446.780000 3598.260000 446.980000 3598.980000 ;
    END
  END lsu_axi_wstrb[3]
  PIN lsu_axi_wstrb[2]
    DIRECTION OUTPUT ;
    USE SIGNAL ;
    PORT
      LAYER Metal3 ;
        RECT 449.660000 3598.260000 449.860000 3598.980000 ;
    END
  END lsu_axi_wstrb[2]
  PIN lsu_axi_wstrb[1]
    DIRECTION OUTPUT ;
    USE SIGNAL ;
    PORT
      LAYER Metal3 ;
        RECT 453.020000 3598.260000 453.220000 3598.980000 ;
    END
  END lsu_axi_wstrb[1]
  PIN lsu_axi_wstrb[0]
    DIRECTION OUTPUT ;
    USE SIGNAL ;
    PORT
      LAYER Metal3 ;
        RECT 456.380000 3598.260000 456.580000 3598.980000 ;
    END
  END lsu_axi_wstrb[0]
  PIN lsu_axi_wlast
    DIRECTION OUTPUT ;
    USE SIGNAL ;
    PORT
      LAYER Metal3 ;
        RECT 459.740000 3598.260000 459.940000 3598.980000 ;
    END
  END lsu_axi_wlast
  PIN lsu_axi_bvalid
    DIRECTION INPUT ;
    USE SIGNAL ;
    PORT
      LAYER Metal3 ;
        RECT 463.100000 3598.260000 463.300000 3598.980000 ;
    END
  END lsu_axi_bvalid
  PIN lsu_axi_bready
    DIRECTION OUTPUT ;
    USE SIGNAL ;
    PORT
      LAYER Metal3 ;
        RECT 465.980000 3598.260000 466.180000 3598.980000 ;
    END
  END lsu_axi_bready
  PIN lsu_axi_bresp[1]
    DIRECTION INPUT ;
    USE SIGNAL ;
    PORT
      LAYER Metal3 ;
        RECT 469.340000 3598.260000 469.540000 3598.980000 ;
    END
  END lsu_axi_bresp[1]
  PIN lsu_axi_bresp[0]
    DIRECTION INPUT ;
    USE SIGNAL ;
    PORT
      LAYER Metal3 ;
        RECT 472.700000 3598.260000 472.900000 3598.980000 ;
    END
  END lsu_axi_bresp[0]
  PIN lsu_axi_bid[3]
    DIRECTION INPUT ;
    USE SIGNAL ;
    PORT
      LAYER Metal3 ;
        RECT 476.060000 3598.260000 476.260000 3598.980000 ;
    END
  END lsu_axi_bid[3]
  PIN lsu_axi_bid[2]
    DIRECTION INPUT ;
    USE SIGNAL ;
    PORT
      LAYER Metal3 ;
        RECT 479.420000 3598.260000 479.620000 3598.980000 ;
    END
  END lsu_axi_bid[2]
  PIN lsu_axi_bid[1]
    DIRECTION INPUT ;
    USE SIGNAL ;
    PORT
      LAYER Metal3 ;
        RECT 482.300000 3598.260000 482.500000 3598.980000 ;
    END
  END lsu_axi_bid[1]
  PIN lsu_axi_bid[0]
    DIRECTION INPUT ;
    USE SIGNAL ;
    PORT
      LAYER Metal3 ;
        RECT 485.660000 3598.260000 485.860000 3598.980000 ;
    END
  END lsu_axi_bid[0]
  PIN lsu_axi_arvalid
    DIRECTION OUTPUT ;
    USE SIGNAL ;
    PORT
      LAYER Metal3 ;
        RECT 489.020000 3598.260000 489.220000 3598.980000 ;
    END
  END lsu_axi_arvalid
  PIN lsu_axi_arready
    DIRECTION INPUT ;
    USE SIGNAL ;
    PORT
      LAYER Metal3 ;
        RECT 492.380000 3598.260000 492.580000 3598.980000 ;
    END
  END lsu_axi_arready
  PIN lsu_axi_arid[3]
    DIRECTION OUTPUT ;
    USE SIGNAL ;
    PORT
      LAYER Metal3 ;
        RECT 495.260000 3598.260000 495.460000 3598.980000 ;
    END
  END lsu_axi_arid[3]
  PIN lsu_axi_arid[2]
    DIRECTION OUTPUT ;
    USE SIGNAL ;
    PORT
      LAYER Metal3 ;
        RECT 498.620000 3598.260000 498.820000 3598.980000 ;
    END
  END lsu_axi_arid[2]
  PIN lsu_axi_arid[1]
    DIRECTION OUTPUT ;
    USE SIGNAL ;
    PORT
      LAYER Metal3 ;
        RECT 501.980000 3598.260000 502.180000 3598.980000 ;
    END
  END lsu_axi_arid[1]
  PIN lsu_axi_arid[0]
    DIRECTION OUTPUT ;
    USE SIGNAL ;
    PORT
      LAYER Metal3 ;
        RECT 505.340000 3598.260000 505.540000 3598.980000 ;
    END
  END lsu_axi_arid[0]
  PIN lsu_axi_araddr[31]
    DIRECTION OUTPUT ;
    USE SIGNAL ;
    PORT
      LAYER Metal3 ;
        RECT 508.700000 3598.260000 508.900000 3598.980000 ;
    END
  END lsu_axi_araddr[31]
  PIN lsu_axi_araddr[30]
    DIRECTION OUTPUT ;
    USE SIGNAL ;
    PORT
      LAYER Metal3 ;
        RECT 511.580000 3598.260000 511.780000 3598.980000 ;
    END
  END lsu_axi_araddr[30]
  PIN lsu_axi_araddr[29]
    DIRECTION OUTPUT ;
    USE SIGNAL ;
    PORT
      LAYER Metal3 ;
        RECT 514.940000 3598.260000 515.140000 3598.980000 ;
    END
  END lsu_axi_araddr[29]
  PIN lsu_axi_araddr[28]
    DIRECTION OUTPUT ;
    USE SIGNAL ;
    PORT
      LAYER Metal3 ;
        RECT 518.300000 3598.260000 518.500000 3598.980000 ;
    END
  END lsu_axi_araddr[28]
  PIN lsu_axi_araddr[27]
    DIRECTION OUTPUT ;
    USE SIGNAL ;
    PORT
      LAYER Metal3 ;
        RECT 521.660000 3598.260000 521.860000 3598.980000 ;
    END
  END lsu_axi_araddr[27]
  PIN lsu_axi_araddr[26]
    DIRECTION OUTPUT ;
    USE SIGNAL ;
    PORT
      LAYER Metal3 ;
        RECT 525.020000 3598.260000 525.220000 3598.980000 ;
    END
  END lsu_axi_araddr[26]
  PIN lsu_axi_araddr[25]
    DIRECTION OUTPUT ;
    USE SIGNAL ;
    PORT
      LAYER Metal3 ;
        RECT 527.900000 3598.260000 528.100000 3598.980000 ;
    END
  END lsu_axi_araddr[25]
  PIN lsu_axi_araddr[24]
    DIRECTION OUTPUT ;
    USE SIGNAL ;
    PORT
      LAYER Metal3 ;
        RECT 531.260000 3598.260000 531.460000 3598.980000 ;
    END
  END lsu_axi_araddr[24]
  PIN lsu_axi_araddr[23]
    DIRECTION OUTPUT ;
    USE SIGNAL ;
    PORT
      LAYER Metal3 ;
        RECT 534.620000 3598.260000 534.820000 3598.980000 ;
    END
  END lsu_axi_araddr[23]
  PIN lsu_axi_araddr[22]
    DIRECTION OUTPUT ;
    USE SIGNAL ;
    PORT
      LAYER Metal3 ;
        RECT 537.980000 3598.260000 538.180000 3598.980000 ;
    END
  END lsu_axi_araddr[22]
  PIN lsu_axi_araddr[21]
    DIRECTION OUTPUT ;
    USE SIGNAL ;
    PORT
      LAYER Metal3 ;
        RECT 540.860000 3598.260000 541.060000 3598.980000 ;
    END
  END lsu_axi_araddr[21]
  PIN lsu_axi_araddr[20]
    DIRECTION OUTPUT ;
    USE SIGNAL ;
    PORT
      LAYER Metal3 ;
        RECT 544.220000 3598.260000 544.420000 3598.980000 ;
    END
  END lsu_axi_araddr[20]
  PIN lsu_axi_araddr[19]
    DIRECTION OUTPUT ;
    USE SIGNAL ;
    PORT
      LAYER Metal3 ;
        RECT 547.580000 3598.260000 547.780000 3598.980000 ;
    END
  END lsu_axi_araddr[19]
  PIN lsu_axi_araddr[18]
    DIRECTION OUTPUT ;
    USE SIGNAL ;
    PORT
      LAYER Metal3 ;
        RECT 550.940000 3598.260000 551.140000 3598.980000 ;
    END
  END lsu_axi_araddr[18]
  PIN lsu_axi_araddr[17]
    DIRECTION OUTPUT ;
    USE SIGNAL ;
    PORT
      LAYER Metal3 ;
        RECT 554.300000 3598.260000 554.500000 3598.980000 ;
    END
  END lsu_axi_araddr[17]
  PIN lsu_axi_araddr[16]
    DIRECTION OUTPUT ;
    USE SIGNAL ;
    PORT
      LAYER Metal3 ;
        RECT 557.180000 3598.260000 557.380000 3598.980000 ;
    END
  END lsu_axi_araddr[16]
  PIN lsu_axi_araddr[15]
    DIRECTION OUTPUT ;
    USE SIGNAL ;
    PORT
      LAYER Metal3 ;
        RECT 560.540000 3598.260000 560.740000 3598.980000 ;
    END
  END lsu_axi_araddr[15]
  PIN lsu_axi_araddr[14]
    DIRECTION OUTPUT ;
    USE SIGNAL ;
    PORT
      LAYER Metal3 ;
        RECT 563.900000 3598.260000 564.100000 3598.980000 ;
    END
  END lsu_axi_araddr[14]
  PIN lsu_axi_araddr[13]
    DIRECTION OUTPUT ;
    USE SIGNAL ;
    PORT
      LAYER Metal3 ;
        RECT 567.260000 3598.260000 567.460000 3598.980000 ;
    END
  END lsu_axi_araddr[13]
  PIN lsu_axi_araddr[12]
    DIRECTION OUTPUT ;
    USE SIGNAL ;
    PORT
      LAYER Metal3 ;
        RECT 570.620000 3598.260000 570.820000 3598.980000 ;
    END
  END lsu_axi_araddr[12]
  PIN lsu_axi_araddr[11]
    DIRECTION OUTPUT ;
    USE SIGNAL ;
    PORT
      LAYER Metal3 ;
        RECT 573.500000 3598.260000 573.700000 3598.980000 ;
    END
  END lsu_axi_araddr[11]
  PIN lsu_axi_araddr[10]
    DIRECTION OUTPUT ;
    USE SIGNAL ;
    PORT
      LAYER Metal3 ;
        RECT 576.860000 3598.260000 577.060000 3598.980000 ;
    END
  END lsu_axi_araddr[10]
  PIN lsu_axi_araddr[9]
    DIRECTION OUTPUT ;
    USE SIGNAL ;
    PORT
      LAYER Metal3 ;
        RECT 580.220000 3598.260000 580.420000 3598.980000 ;
    END
  END lsu_axi_araddr[9]
  PIN lsu_axi_araddr[8]
    DIRECTION OUTPUT ;
    USE SIGNAL ;
    PORT
      LAYER Metal3 ;
        RECT 583.580000 3598.260000 583.780000 3598.980000 ;
    END
  END lsu_axi_araddr[8]
  PIN lsu_axi_araddr[7]
    DIRECTION OUTPUT ;
    USE SIGNAL ;
    PORT
      LAYER Metal3 ;
        RECT 586.940000 3598.260000 587.140000 3598.980000 ;
    END
  END lsu_axi_araddr[7]
  PIN lsu_axi_araddr[6]
    DIRECTION OUTPUT ;
    USE SIGNAL ;
    PORT
      LAYER Metal3 ;
        RECT 589.820000 3598.260000 590.020000 3598.980000 ;
    END
  END lsu_axi_araddr[6]
  PIN lsu_axi_araddr[5]
    DIRECTION OUTPUT ;
    USE SIGNAL ;
    PORT
      LAYER Metal3 ;
        RECT 593.180000 3598.260000 593.380000 3598.980000 ;
    END
  END lsu_axi_araddr[5]
  PIN lsu_axi_araddr[4]
    DIRECTION OUTPUT ;
    USE SIGNAL ;
    PORT
      LAYER Metal3 ;
        RECT 596.540000 3598.260000 596.740000 3598.980000 ;
    END
  END lsu_axi_araddr[4]
  PIN lsu_axi_araddr[3]
    DIRECTION OUTPUT ;
    USE SIGNAL ;
    PORT
      LAYER Metal3 ;
        RECT 599.900000 3598.260000 600.100000 3598.980000 ;
    END
  END lsu_axi_araddr[3]
  PIN lsu_axi_araddr[2]
    DIRECTION OUTPUT ;
    USE SIGNAL ;
    PORT
      LAYER Metal3 ;
        RECT 602.780000 3598.260000 602.980000 3598.980000 ;
    END
  END lsu_axi_araddr[2]
  PIN lsu_axi_araddr[1]
    DIRECTION OUTPUT ;
    USE SIGNAL ;
    PORT
      LAYER Metal3 ;
        RECT 606.140000 3598.260000 606.340000 3598.980000 ;
    END
  END lsu_axi_araddr[1]
  PIN lsu_axi_araddr[0]
    DIRECTION OUTPUT ;
    USE SIGNAL ;
    PORT
      LAYER Metal3 ;
        RECT 609.500000 3598.260000 609.700000 3598.980000 ;
    END
  END lsu_axi_araddr[0]
  PIN lsu_axi_arregion[3]
    DIRECTION OUTPUT ;
    USE SIGNAL ;
    PORT
      LAYER Metal3 ;
        RECT 612.860000 3598.260000 613.060000 3598.980000 ;
    END
  END lsu_axi_arregion[3]
  PIN lsu_axi_arregion[2]
    DIRECTION OUTPUT ;
    USE SIGNAL ;
    PORT
      LAYER Metal3 ;
        RECT 616.220000 3598.260000 616.420000 3598.980000 ;
    END
  END lsu_axi_arregion[2]
  PIN lsu_axi_arregion[1]
    DIRECTION OUTPUT ;
    USE SIGNAL ;
    PORT
      LAYER Metal3 ;
        RECT 619.100000 3598.260000 619.300000 3598.980000 ;
    END
  END lsu_axi_arregion[1]
  PIN lsu_axi_arregion[0]
    DIRECTION OUTPUT ;
    USE SIGNAL ;
    PORT
      LAYER Metal3 ;
        RECT 622.460000 3598.260000 622.660000 3598.980000 ;
    END
  END lsu_axi_arregion[0]
  PIN lsu_axi_arlen[7]
    DIRECTION OUTPUT ;
    USE SIGNAL ;
    PORT
      LAYER Metal3 ;
        RECT 625.820000 3598.260000 626.020000 3598.980000 ;
    END
  END lsu_axi_arlen[7]
  PIN lsu_axi_arlen[6]
    DIRECTION OUTPUT ;
    USE SIGNAL ;
    PORT
      LAYER Metal3 ;
        RECT 629.180000 3598.260000 629.380000 3598.980000 ;
    END
  END lsu_axi_arlen[6]
  PIN lsu_axi_arlen[5]
    DIRECTION OUTPUT ;
    USE SIGNAL ;
    PORT
      LAYER Metal3 ;
        RECT 632.540000 3598.260000 632.740000 3598.980000 ;
    END
  END lsu_axi_arlen[5]
  PIN lsu_axi_arlen[4]
    DIRECTION OUTPUT ;
    USE SIGNAL ;
    PORT
      LAYER Metal3 ;
        RECT 635.420000 3598.260000 635.620000 3598.980000 ;
    END
  END lsu_axi_arlen[4]
  PIN lsu_axi_arlen[3]
    DIRECTION OUTPUT ;
    USE SIGNAL ;
    PORT
      LAYER Metal3 ;
        RECT 638.780000 3598.260000 638.980000 3598.980000 ;
    END
  END lsu_axi_arlen[3]
  PIN lsu_axi_arlen[2]
    DIRECTION OUTPUT ;
    USE SIGNAL ;
    PORT
      LAYER Metal3 ;
        RECT 642.140000 3598.260000 642.340000 3598.980000 ;
    END
  END lsu_axi_arlen[2]
  PIN lsu_axi_arlen[1]
    DIRECTION OUTPUT ;
    USE SIGNAL ;
    PORT
      LAYER Metal3 ;
        RECT 645.500000 3598.260000 645.700000 3598.980000 ;
    END
  END lsu_axi_arlen[1]
  PIN lsu_axi_arlen[0]
    DIRECTION OUTPUT ;
    USE SIGNAL ;
    PORT
      LAYER Metal3 ;
        RECT 648.860000 3598.260000 649.060000 3598.980000 ;
    END
  END lsu_axi_arlen[0]
  PIN lsu_axi_arsize[2]
    DIRECTION OUTPUT ;
    USE SIGNAL ;
    PORT
      LAYER Metal3 ;
        RECT 651.740000 3598.260000 651.940000 3598.980000 ;
    END
  END lsu_axi_arsize[2]
  PIN lsu_axi_arsize[1]
    DIRECTION OUTPUT ;
    USE SIGNAL ;
    PORT
      LAYER Metal3 ;
        RECT 655.100000 3598.260000 655.300000 3598.980000 ;
    END
  END lsu_axi_arsize[1]
  PIN lsu_axi_arsize[0]
    DIRECTION OUTPUT ;
    USE SIGNAL ;
    PORT
      LAYER Metal3 ;
        RECT 658.460000 3598.260000 658.660000 3598.980000 ;
    END
  END lsu_axi_arsize[0]
  PIN lsu_axi_arburst[1]
    DIRECTION OUTPUT ;
    USE SIGNAL ;
    PORT
      LAYER Metal3 ;
        RECT 661.820000 3598.260000 662.020000 3598.980000 ;
    END
  END lsu_axi_arburst[1]
  PIN lsu_axi_arburst[0]
    DIRECTION OUTPUT ;
    USE SIGNAL ;
    PORT
      LAYER Metal3 ;
        RECT 664.700000 3598.260000 664.900000 3598.980000 ;
    END
  END lsu_axi_arburst[0]
  PIN lsu_axi_arlock
    DIRECTION OUTPUT ;
    USE SIGNAL ;
    PORT
      LAYER Metal3 ;
        RECT 668.060000 3598.260000 668.260000 3598.980000 ;
    END
  END lsu_axi_arlock
  PIN lsu_axi_arcache[3]
    DIRECTION OUTPUT ;
    USE SIGNAL ;
    PORT
      LAYER Metal3 ;
        RECT 671.420000 3598.260000 671.620000 3598.980000 ;
    END
  END lsu_axi_arcache[3]
  PIN lsu_axi_arcache[2]
    DIRECTION OUTPUT ;
    USE SIGNAL ;
    PORT
      LAYER Metal3 ;
        RECT 674.780000 3598.260000 674.980000 3598.980000 ;
    END
  END lsu_axi_arcache[2]
  PIN lsu_axi_arcache[1]
    DIRECTION OUTPUT ;
    USE SIGNAL ;
    PORT
      LAYER Metal3 ;
        RECT 678.140000 3598.260000 678.340000 3598.980000 ;
    END
  END lsu_axi_arcache[1]
  PIN lsu_axi_arcache[0]
    DIRECTION OUTPUT ;
    USE SIGNAL ;
    PORT
      LAYER Metal3 ;
        RECT 681.020000 3598.260000 681.220000 3598.980000 ;
    END
  END lsu_axi_arcache[0]
  PIN lsu_axi_arprot[2]
    DIRECTION OUTPUT ;
    USE SIGNAL ;
    PORT
      LAYER Metal3 ;
        RECT 684.380000 3598.260000 684.580000 3598.980000 ;
    END
  END lsu_axi_arprot[2]
  PIN lsu_axi_arprot[1]
    DIRECTION OUTPUT ;
    USE SIGNAL ;
    PORT
      LAYER Metal3 ;
        RECT 687.740000 3598.260000 687.940000 3598.980000 ;
    END
  END lsu_axi_arprot[1]
  PIN lsu_axi_arprot[0]
    DIRECTION OUTPUT ;
    USE SIGNAL ;
    PORT
      LAYER Metal3 ;
        RECT 691.100000 3598.260000 691.300000 3598.980000 ;
    END
  END lsu_axi_arprot[0]
  PIN lsu_axi_arqos[3]
    DIRECTION OUTPUT ;
    USE SIGNAL ;
    PORT
      LAYER Metal3 ;
        RECT 694.460000 3598.260000 694.660000 3598.980000 ;
    END
  END lsu_axi_arqos[3]
  PIN lsu_axi_arqos[2]
    DIRECTION OUTPUT ;
    USE SIGNAL ;
    PORT
      LAYER Metal3 ;
        RECT 697.340000 3598.260000 697.540000 3598.980000 ;
    END
  END lsu_axi_arqos[2]
  PIN lsu_axi_arqos[1]
    DIRECTION OUTPUT ;
    USE SIGNAL ;
    PORT
      LAYER Metal3 ;
        RECT 700.700000 3598.260000 700.900000 3598.980000 ;
    END
  END lsu_axi_arqos[1]
  PIN lsu_axi_arqos[0]
    DIRECTION OUTPUT ;
    USE SIGNAL ;
    PORT
      LAYER Metal3 ;
        RECT 704.060000 3598.260000 704.260000 3598.980000 ;
    END
  END lsu_axi_arqos[0]
  PIN lsu_axi_rvalid
    DIRECTION INPUT ;
    USE SIGNAL ;
    PORT
      LAYER Metal3 ;
        RECT 707.420000 3598.260000 707.620000 3598.980000 ;
    END
  END lsu_axi_rvalid
  PIN lsu_axi_rready
    DIRECTION OUTPUT ;
    USE SIGNAL ;
    PORT
      LAYER Metal3 ;
        RECT 710.780000 3598.260000 710.980000 3598.980000 ;
    END
  END lsu_axi_rready
  PIN lsu_axi_rid[3]
    DIRECTION INPUT ;
    USE SIGNAL ;
    PORT
      LAYER Metal3 ;
        RECT 713.660000 3598.260000 713.860000 3598.980000 ;
    END
  END lsu_axi_rid[3]
  PIN lsu_axi_rid[2]
    DIRECTION INPUT ;
    USE SIGNAL ;
    PORT
      LAYER Metal3 ;
        RECT 717.020000 3598.260000 717.220000 3598.980000 ;
    END
  END lsu_axi_rid[2]
  PIN lsu_axi_rid[1]
    DIRECTION INPUT ;
    USE SIGNAL ;
    PORT
      LAYER Metal3 ;
        RECT 720.380000 3598.260000 720.580000 3598.980000 ;
    END
  END lsu_axi_rid[1]
  PIN lsu_axi_rid[0]
    DIRECTION INPUT ;
    USE SIGNAL ;
    PORT
      LAYER Metal3 ;
        RECT 723.740000 3598.260000 723.940000 3598.980000 ;
    END
  END lsu_axi_rid[0]
  PIN lsu_axi_rdata[63]
    DIRECTION INPUT ;
    USE SIGNAL ;
    PORT
      LAYER Metal3 ;
        RECT 726.620000 3598.260000 726.820000 3598.980000 ;
    END
  END lsu_axi_rdata[63]
  PIN lsu_axi_rdata[62]
    DIRECTION INPUT ;
    USE SIGNAL ;
    PORT
      LAYER Metal3 ;
        RECT 729.980000 3598.260000 730.180000 3598.980000 ;
    END
  END lsu_axi_rdata[62]
  PIN lsu_axi_rdata[61]
    DIRECTION INPUT ;
    USE SIGNAL ;
    PORT
      LAYER Metal3 ;
        RECT 733.340000 3598.260000 733.540000 3598.980000 ;
    END
  END lsu_axi_rdata[61]
  PIN lsu_axi_rdata[60]
    DIRECTION INPUT ;
    USE SIGNAL ;
    PORT
      LAYER Metal3 ;
        RECT 736.700000 3598.260000 736.900000 3598.980000 ;
    END
  END lsu_axi_rdata[60]
  PIN lsu_axi_rdata[59]
    DIRECTION INPUT ;
    USE SIGNAL ;
    PORT
      LAYER Metal3 ;
        RECT 740.060000 3598.260000 740.260000 3598.980000 ;
    END
  END lsu_axi_rdata[59]
  PIN lsu_axi_rdata[58]
    DIRECTION INPUT ;
    USE SIGNAL ;
    PORT
      LAYER Metal3 ;
        RECT 742.940000 3598.260000 743.140000 3598.980000 ;
    END
  END lsu_axi_rdata[58]
  PIN lsu_axi_rdata[57]
    DIRECTION INPUT ;
    USE SIGNAL ;
    PORT
      LAYER Metal3 ;
        RECT 746.300000 3598.260000 746.500000 3598.980000 ;
    END
  END lsu_axi_rdata[57]
  PIN lsu_axi_rdata[56]
    DIRECTION INPUT ;
    USE SIGNAL ;
    PORT
      LAYER Metal3 ;
        RECT 749.660000 3598.260000 749.860000 3598.980000 ;
    END
  END lsu_axi_rdata[56]
  PIN lsu_axi_rdata[55]
    DIRECTION INPUT ;
    USE SIGNAL ;
    PORT
      LAYER Metal3 ;
        RECT 753.020000 3598.260000 753.220000 3598.980000 ;
    END
  END lsu_axi_rdata[55]
  PIN lsu_axi_rdata[54]
    DIRECTION INPUT ;
    USE SIGNAL ;
    PORT
      LAYER Metal3 ;
        RECT 756.380000 3598.260000 756.580000 3598.980000 ;
    END
  END lsu_axi_rdata[54]
  PIN lsu_axi_rdata[53]
    DIRECTION INPUT ;
    USE SIGNAL ;
    PORT
      LAYER Metal3 ;
        RECT 759.260000 3598.260000 759.460000 3598.980000 ;
    END
  END lsu_axi_rdata[53]
  PIN lsu_axi_rdata[52]
    DIRECTION INPUT ;
    USE SIGNAL ;
    PORT
      LAYER Metal3 ;
        RECT 762.620000 3598.260000 762.820000 3598.980000 ;
    END
  END lsu_axi_rdata[52]
  PIN lsu_axi_rdata[51]
    DIRECTION INPUT ;
    USE SIGNAL ;
    PORT
      LAYER Metal3 ;
        RECT 765.980000 3598.260000 766.180000 3598.980000 ;
    END
  END lsu_axi_rdata[51]
  PIN lsu_axi_rdata[50]
    DIRECTION INPUT ;
    USE SIGNAL ;
    PORT
      LAYER Metal3 ;
        RECT 769.340000 3598.260000 769.540000 3598.980000 ;
    END
  END lsu_axi_rdata[50]
  PIN lsu_axi_rdata[49]
    DIRECTION INPUT ;
    USE SIGNAL ;
    PORT
      LAYER Metal3 ;
        RECT 772.700000 3598.260000 772.900000 3598.980000 ;
    END
  END lsu_axi_rdata[49]
  PIN lsu_axi_rdata[48]
    DIRECTION INPUT ;
    USE SIGNAL ;
    PORT
      LAYER Metal3 ;
        RECT 775.580000 3598.260000 775.780000 3598.980000 ;
    END
  END lsu_axi_rdata[48]
  PIN lsu_axi_rdata[47]
    DIRECTION INPUT ;
    USE SIGNAL ;
    PORT
      LAYER Metal3 ;
        RECT 778.940000 3598.260000 779.140000 3598.980000 ;
    END
  END lsu_axi_rdata[47]
  PIN lsu_axi_rdata[46]
    DIRECTION INPUT ;
    USE SIGNAL ;
    PORT
      LAYER Metal3 ;
        RECT 782.300000 3598.260000 782.500000 3598.980000 ;
    END
  END lsu_axi_rdata[46]
  PIN lsu_axi_rdata[45]
    DIRECTION INPUT ;
    USE SIGNAL ;
    PORT
      LAYER Metal3 ;
        RECT 785.660000 3598.260000 785.860000 3598.980000 ;
    END
  END lsu_axi_rdata[45]
  PIN lsu_axi_rdata[44]
    DIRECTION INPUT ;
    USE SIGNAL ;
    PORT
      LAYER Metal3 ;
        RECT 788.540000 3598.260000 788.740000 3598.980000 ;
    END
  END lsu_axi_rdata[44]
  PIN lsu_axi_rdata[43]
    DIRECTION INPUT ;
    USE SIGNAL ;
    PORT
      LAYER Metal3 ;
        RECT 791.900000 3598.260000 792.100000 3598.980000 ;
    END
  END lsu_axi_rdata[43]
  PIN lsu_axi_rdata[42]
    DIRECTION INPUT ;
    USE SIGNAL ;
    PORT
      LAYER Metal3 ;
        RECT 795.260000 3598.260000 795.460000 3598.980000 ;
    END
  END lsu_axi_rdata[42]
  PIN lsu_axi_rdata[41]
    DIRECTION INPUT ;
    USE SIGNAL ;
    PORT
      LAYER Metal3 ;
        RECT 798.620000 3598.260000 798.820000 3598.980000 ;
    END
  END lsu_axi_rdata[41]
  PIN lsu_axi_rdata[40]
    DIRECTION INPUT ;
    USE SIGNAL ;
    PORT
      LAYER Metal3 ;
        RECT 801.980000 3598.260000 802.180000 3598.980000 ;
    END
  END lsu_axi_rdata[40]
  PIN lsu_axi_rdata[39]
    DIRECTION INPUT ;
    USE SIGNAL ;
    PORT
      LAYER Metal3 ;
        RECT 804.860000 3598.260000 805.060000 3598.980000 ;
    END
  END lsu_axi_rdata[39]
  PIN lsu_axi_rdata[38]
    DIRECTION INPUT ;
    USE SIGNAL ;
    PORT
      LAYER Metal3 ;
        RECT 808.220000 3598.260000 808.420000 3598.980000 ;
    END
  END lsu_axi_rdata[38]
  PIN lsu_axi_rdata[37]
    DIRECTION INPUT ;
    USE SIGNAL ;
    PORT
      LAYER Metal3 ;
        RECT 811.580000 3598.260000 811.780000 3598.980000 ;
    END
  END lsu_axi_rdata[37]
  PIN lsu_axi_rdata[36]
    DIRECTION INPUT ;
    USE SIGNAL ;
    PORT
      LAYER Metal3 ;
        RECT 814.940000 3598.260000 815.140000 3598.980000 ;
    END
  END lsu_axi_rdata[36]
  PIN lsu_axi_rdata[35]
    DIRECTION INPUT ;
    USE SIGNAL ;
    PORT
      LAYER Metal3 ;
        RECT 818.300000 3598.260000 818.500000 3598.980000 ;
    END
  END lsu_axi_rdata[35]
  PIN lsu_axi_rdata[34]
    DIRECTION INPUT ;
    USE SIGNAL ;
    PORT
      LAYER Metal3 ;
        RECT 821.180000 3598.260000 821.380000 3598.980000 ;
    END
  END lsu_axi_rdata[34]
  PIN lsu_axi_rdata[33]
    DIRECTION INPUT ;
    USE SIGNAL ;
    PORT
      LAYER Metal3 ;
        RECT 824.540000 3598.260000 824.740000 3598.980000 ;
    END
  END lsu_axi_rdata[33]
  PIN lsu_axi_rdata[32]
    DIRECTION INPUT ;
    USE SIGNAL ;
    PORT
      LAYER Metal3 ;
        RECT 827.900000 3598.260000 828.100000 3598.980000 ;
    END
  END lsu_axi_rdata[32]
  PIN lsu_axi_rdata[31]
    DIRECTION INPUT ;
    USE SIGNAL ;
    PORT
      LAYER Metal3 ;
        RECT 831.260000 3598.260000 831.460000 3598.980000 ;
    END
  END lsu_axi_rdata[31]
  PIN lsu_axi_rdata[30]
    DIRECTION INPUT ;
    USE SIGNAL ;
    PORT
      LAYER Metal3 ;
        RECT 834.620000 3598.260000 834.820000 3598.980000 ;
    END
  END lsu_axi_rdata[30]
  PIN lsu_axi_rdata[29]
    DIRECTION INPUT ;
    USE SIGNAL ;
    PORT
      LAYER Metal3 ;
        RECT 837.500000 3598.260000 837.700000 3598.980000 ;
    END
  END lsu_axi_rdata[29]
  PIN lsu_axi_rdata[28]
    DIRECTION INPUT ;
    USE SIGNAL ;
    PORT
      LAYER Metal3 ;
        RECT 840.860000 3598.260000 841.060000 3598.980000 ;
    END
  END lsu_axi_rdata[28]
  PIN lsu_axi_rdata[27]
    DIRECTION INPUT ;
    USE SIGNAL ;
    PORT
      LAYER Metal3 ;
        RECT 844.220000 3598.260000 844.420000 3598.980000 ;
    END
  END lsu_axi_rdata[27]
  PIN lsu_axi_rdata[26]
    DIRECTION INPUT ;
    USE SIGNAL ;
    PORT
      LAYER Metal3 ;
        RECT 847.580000 3598.260000 847.780000 3598.980000 ;
    END
  END lsu_axi_rdata[26]
  PIN lsu_axi_rdata[25]
    DIRECTION INPUT ;
    USE SIGNAL ;
    PORT
      LAYER Metal3 ;
        RECT 850.460000 3598.260000 850.660000 3598.980000 ;
    END
  END lsu_axi_rdata[25]
  PIN lsu_axi_rdata[24]
    DIRECTION INPUT ;
    USE SIGNAL ;
    PORT
      LAYER Metal3 ;
        RECT 853.820000 3598.260000 854.020000 3598.980000 ;
    END
  END lsu_axi_rdata[24]
  PIN lsu_axi_rdata[23]
    DIRECTION INPUT ;
    USE SIGNAL ;
    PORT
      LAYER Metal3 ;
        RECT 857.180000 3598.260000 857.380000 3598.980000 ;
    END
  END lsu_axi_rdata[23]
  PIN lsu_axi_rdata[22]
    DIRECTION INPUT ;
    USE SIGNAL ;
    PORT
      LAYER Metal3 ;
        RECT 860.540000 3598.260000 860.740000 3598.980000 ;
    END
  END lsu_axi_rdata[22]
  PIN lsu_axi_rdata[21]
    DIRECTION INPUT ;
    USE SIGNAL ;
    PORT
      LAYER Metal3 ;
        RECT 863.900000 3598.260000 864.100000 3598.980000 ;
    END
  END lsu_axi_rdata[21]
  PIN lsu_axi_rdata[20]
    DIRECTION INPUT ;
    USE SIGNAL ;
    PORT
      LAYER Metal3 ;
        RECT 866.780000 3598.260000 866.980000 3598.980000 ;
    END
  END lsu_axi_rdata[20]
  PIN lsu_axi_rdata[19]
    DIRECTION INPUT ;
    USE SIGNAL ;
    PORT
      LAYER Metal3 ;
        RECT 870.140000 3598.260000 870.340000 3598.980000 ;
    END
  END lsu_axi_rdata[19]
  PIN lsu_axi_rdata[18]
    DIRECTION INPUT ;
    USE SIGNAL ;
    PORT
      LAYER Metal3 ;
        RECT 873.500000 3598.260000 873.700000 3598.980000 ;
    END
  END lsu_axi_rdata[18]
  PIN lsu_axi_rdata[17]
    DIRECTION INPUT ;
    USE SIGNAL ;
    PORT
      LAYER Metal3 ;
        RECT 876.860000 3598.260000 877.060000 3598.980000 ;
    END
  END lsu_axi_rdata[17]
  PIN lsu_axi_rdata[16]
    DIRECTION INPUT ;
    USE SIGNAL ;
    PORT
      LAYER Metal3 ;
        RECT 880.220000 3598.260000 880.420000 3598.980000 ;
    END
  END lsu_axi_rdata[16]
  PIN lsu_axi_rdata[15]
    DIRECTION INPUT ;
    USE SIGNAL ;
    PORT
      LAYER Metal3 ;
        RECT 883.100000 3598.260000 883.300000 3598.980000 ;
    END
  END lsu_axi_rdata[15]
  PIN lsu_axi_rdata[14]
    DIRECTION INPUT ;
    USE SIGNAL ;
    PORT
      LAYER Metal3 ;
        RECT 886.460000 3598.260000 886.660000 3598.980000 ;
    END
  END lsu_axi_rdata[14]
  PIN lsu_axi_rdata[13]
    DIRECTION INPUT ;
    USE SIGNAL ;
    PORT
      LAYER Metal3 ;
        RECT 889.820000 3598.260000 890.020000 3598.980000 ;
    END
  END lsu_axi_rdata[13]
  PIN lsu_axi_rdata[12]
    DIRECTION INPUT ;
    USE SIGNAL ;
    PORT
      LAYER Metal3 ;
        RECT 893.180000 3598.260000 893.380000 3598.980000 ;
    END
  END lsu_axi_rdata[12]
  PIN lsu_axi_rdata[11]
    DIRECTION INPUT ;
    USE SIGNAL ;
    PORT
      LAYER Metal3 ;
        RECT 896.540000 3598.260000 896.740000 3598.980000 ;
    END
  END lsu_axi_rdata[11]
  PIN lsu_axi_rdata[10]
    DIRECTION INPUT ;
    USE SIGNAL ;
    PORT
      LAYER Metal3 ;
        RECT 899.420000 3598.260000 899.620000 3598.980000 ;
    END
  END lsu_axi_rdata[10]
  PIN lsu_axi_rdata[9]
    DIRECTION INPUT ;
    USE SIGNAL ;
    PORT
      LAYER Metal3 ;
        RECT 902.780000 3598.260000 902.980000 3598.980000 ;
    END
  END lsu_axi_rdata[9]
  PIN lsu_axi_rdata[8]
    DIRECTION INPUT ;
    USE SIGNAL ;
    PORT
      LAYER Metal3 ;
        RECT 906.140000 3598.260000 906.340000 3598.980000 ;
    END
  END lsu_axi_rdata[8]
  PIN lsu_axi_rdata[7]
    DIRECTION INPUT ;
    USE SIGNAL ;
    PORT
      LAYER Metal3 ;
        RECT 909.500000 3598.260000 909.700000 3598.980000 ;
    END
  END lsu_axi_rdata[7]
  PIN lsu_axi_rdata[6]
    DIRECTION INPUT ;
    USE SIGNAL ;
    PORT
      LAYER Metal3 ;
        RECT 912.380000 3598.260000 912.580000 3598.980000 ;
    END
  END lsu_axi_rdata[6]
  PIN lsu_axi_rdata[5]
    DIRECTION INPUT ;
    USE SIGNAL ;
    PORT
      LAYER Metal3 ;
        RECT 915.740000 3598.260000 915.940000 3598.980000 ;
    END
  END lsu_axi_rdata[5]
  PIN lsu_axi_rdata[4]
    DIRECTION INPUT ;
    USE SIGNAL ;
    PORT
      LAYER Metal3 ;
        RECT 919.100000 3598.260000 919.300000 3598.980000 ;
    END
  END lsu_axi_rdata[4]
  PIN lsu_axi_rdata[3]
    DIRECTION INPUT ;
    USE SIGNAL ;
    PORT
      LAYER Metal3 ;
        RECT 922.460000 3598.260000 922.660000 3598.980000 ;
    END
  END lsu_axi_rdata[3]
  PIN lsu_axi_rdata[2]
    DIRECTION INPUT ;
    USE SIGNAL ;
    PORT
      LAYER Metal3 ;
        RECT 925.820000 3598.260000 926.020000 3598.980000 ;
    END
  END lsu_axi_rdata[2]
  PIN lsu_axi_rdata[1]
    DIRECTION INPUT ;
    USE SIGNAL ;
    PORT
      LAYER Metal3 ;
        RECT 928.700000 3598.260000 928.900000 3598.980000 ;
    END
  END lsu_axi_rdata[1]
  PIN lsu_axi_rdata[0]
    DIRECTION INPUT ;
    USE SIGNAL ;
    PORT
      LAYER Metal3 ;
        RECT 932.060000 3598.260000 932.260000 3598.980000 ;
    END
  END lsu_axi_rdata[0]
  PIN lsu_axi_rresp[1]
    DIRECTION INPUT ;
    USE SIGNAL ;
    PORT
      LAYER Metal3 ;
        RECT 935.420000 3598.260000 935.620000 3598.980000 ;
    END
  END lsu_axi_rresp[1]
  PIN lsu_axi_rresp[0]
    DIRECTION INPUT ;
    USE SIGNAL ;
    PORT
      LAYER Metal3 ;
        RECT 938.780000 3598.260000 938.980000 3598.980000 ;
    END
  END lsu_axi_rresp[0]
  PIN lsu_axi_rlast
    DIRECTION INPUT ;
    USE SIGNAL ;
    PORT
      LAYER Metal3 ;
        RECT 942.140000 3598.260000 942.340000 3598.980000 ;
    END
  END lsu_axi_rlast
  PIN ifu_axi_awvalid
    DIRECTION OUTPUT ;
    USE SIGNAL ;
    PORT
      LAYER Metal3 ;
        RECT 945.020000 3598.260000 945.220000 3598.980000 ;
    END
  END ifu_axi_awvalid
  PIN ifu_axi_awready
    DIRECTION INPUT ;
    USE SIGNAL ;
    PORT
      LAYER Metal3 ;
        RECT 948.380000 3598.260000 948.580000 3598.980000 ;
    END
  END ifu_axi_awready
  PIN ifu_axi_awid[2]
    DIRECTION OUTPUT ;
    USE SIGNAL ;
    PORT
      LAYER Metal3 ;
        RECT 951.740000 3598.260000 951.940000 3598.980000 ;
    END
  END ifu_axi_awid[2]
  PIN ifu_axi_awid[1]
    DIRECTION OUTPUT ;
    USE SIGNAL ;
    PORT
      LAYER Metal3 ;
        RECT 955.100000 3598.260000 955.300000 3598.980000 ;
    END
  END ifu_axi_awid[1]
  PIN ifu_axi_awid[0]
    DIRECTION OUTPUT ;
    USE SIGNAL ;
    PORT
      LAYER Metal3 ;
        RECT 958.460000 3598.260000 958.660000 3598.980000 ;
    END
  END ifu_axi_awid[0]
  PIN ifu_axi_awaddr[31]
    DIRECTION OUTPUT ;
    USE SIGNAL ;
    PORT
      LAYER Metal3 ;
        RECT 961.340000 3598.260000 961.540000 3598.980000 ;
    END
  END ifu_axi_awaddr[31]
  PIN ifu_axi_awaddr[30]
    DIRECTION OUTPUT ;
    USE SIGNAL ;
    PORT
      LAYER Metal3 ;
        RECT 964.700000 3598.260000 964.900000 3598.980000 ;
    END
  END ifu_axi_awaddr[30]
  PIN ifu_axi_awaddr[29]
    DIRECTION OUTPUT ;
    USE SIGNAL ;
    PORT
      LAYER Metal3 ;
        RECT 968.060000 3598.260000 968.260000 3598.980000 ;
    END
  END ifu_axi_awaddr[29]
  PIN ifu_axi_awaddr[28]
    DIRECTION OUTPUT ;
    USE SIGNAL ;
    PORT
      LAYER Metal3 ;
        RECT 971.420000 3598.260000 971.620000 3598.980000 ;
    END
  END ifu_axi_awaddr[28]
  PIN ifu_axi_awaddr[27]
    DIRECTION OUTPUT ;
    USE SIGNAL ;
    PORT
      LAYER Metal3 ;
        RECT 974.300000 3598.260000 974.500000 3598.980000 ;
    END
  END ifu_axi_awaddr[27]
  PIN ifu_axi_awaddr[26]
    DIRECTION OUTPUT ;
    USE SIGNAL ;
    PORT
      LAYER Metal3 ;
        RECT 977.660000 3598.260000 977.860000 3598.980000 ;
    END
  END ifu_axi_awaddr[26]
  PIN ifu_axi_awaddr[25]
    DIRECTION OUTPUT ;
    USE SIGNAL ;
    PORT
      LAYER Metal3 ;
        RECT 981.020000 3598.260000 981.220000 3598.980000 ;
    END
  END ifu_axi_awaddr[25]
  PIN ifu_axi_awaddr[24]
    DIRECTION OUTPUT ;
    USE SIGNAL ;
    PORT
      LAYER Metal3 ;
        RECT 984.380000 3598.260000 984.580000 3598.980000 ;
    END
  END ifu_axi_awaddr[24]
  PIN ifu_axi_awaddr[23]
    DIRECTION OUTPUT ;
    USE SIGNAL ;
    PORT
      LAYER Metal3 ;
        RECT 987.740000 3598.260000 987.940000 3598.980000 ;
    END
  END ifu_axi_awaddr[23]
  PIN ifu_axi_awaddr[22]
    DIRECTION OUTPUT ;
    USE SIGNAL ;
    PORT
      LAYER Metal3 ;
        RECT 990.620000 3598.260000 990.820000 3598.980000 ;
    END
  END ifu_axi_awaddr[22]
  PIN ifu_axi_awaddr[21]
    DIRECTION OUTPUT ;
    USE SIGNAL ;
    PORT
      LAYER Metal3 ;
        RECT 993.980000 3598.260000 994.180000 3598.980000 ;
    END
  END ifu_axi_awaddr[21]
  PIN ifu_axi_awaddr[20]
    DIRECTION OUTPUT ;
    USE SIGNAL ;
    PORT
      LAYER Metal3 ;
        RECT 997.340000 3598.260000 997.540000 3598.980000 ;
    END
  END ifu_axi_awaddr[20]
  PIN ifu_axi_awaddr[19]
    DIRECTION OUTPUT ;
    USE SIGNAL ;
    PORT
      LAYER Metal3 ;
        RECT 1000.700000 3598.260000 1000.900000 3598.980000 ;
    END
  END ifu_axi_awaddr[19]
  PIN ifu_axi_awaddr[18]
    DIRECTION OUTPUT ;
    USE SIGNAL ;
    PORT
      LAYER Metal3 ;
        RECT 1004.060000 3598.260000 1004.260000 3598.980000 ;
    END
  END ifu_axi_awaddr[18]
  PIN ifu_axi_awaddr[17]
    DIRECTION OUTPUT ;
    USE SIGNAL ;
    PORT
      LAYER Metal3 ;
        RECT 1006.940000 3598.260000 1007.140000 3598.980000 ;
    END
  END ifu_axi_awaddr[17]
  PIN ifu_axi_awaddr[16]
    DIRECTION OUTPUT ;
    USE SIGNAL ;
    PORT
      LAYER Metal3 ;
        RECT 1010.300000 3598.260000 1010.500000 3598.980000 ;
    END
  END ifu_axi_awaddr[16]
  PIN ifu_axi_awaddr[15]
    DIRECTION OUTPUT ;
    USE SIGNAL ;
    PORT
      LAYER Metal3 ;
        RECT 1013.660000 3598.260000 1013.860000 3598.980000 ;
    END
  END ifu_axi_awaddr[15]
  PIN ifu_axi_awaddr[14]
    DIRECTION OUTPUT ;
    USE SIGNAL ;
    PORT
      LAYER Metal3 ;
        RECT 1017.020000 3598.260000 1017.220000 3598.980000 ;
    END
  END ifu_axi_awaddr[14]
  PIN ifu_axi_awaddr[13]
    DIRECTION OUTPUT ;
    USE SIGNAL ;
    PORT
      LAYER Metal3 ;
        RECT 1020.380000 3598.260000 1020.580000 3598.980000 ;
    END
  END ifu_axi_awaddr[13]
  PIN ifu_axi_awaddr[12]
    DIRECTION OUTPUT ;
    USE SIGNAL ;
    PORT
      LAYER Metal3 ;
        RECT 1023.260000 3598.260000 1023.460000 3598.980000 ;
    END
  END ifu_axi_awaddr[12]
  PIN ifu_axi_awaddr[11]
    DIRECTION OUTPUT ;
    USE SIGNAL ;
    PORT
      LAYER Metal3 ;
        RECT 1026.620000 3598.260000 1026.820000 3598.980000 ;
    END
  END ifu_axi_awaddr[11]
  PIN ifu_axi_awaddr[10]
    DIRECTION OUTPUT ;
    USE SIGNAL ;
    PORT
      LAYER Metal3 ;
        RECT 1029.980000 3598.260000 1030.180000 3598.980000 ;
    END
  END ifu_axi_awaddr[10]
  PIN ifu_axi_awaddr[9]
    DIRECTION OUTPUT ;
    USE SIGNAL ;
    PORT
      LAYER Metal3 ;
        RECT 1033.340000 3598.260000 1033.540000 3598.980000 ;
    END
  END ifu_axi_awaddr[9]
  PIN ifu_axi_awaddr[8]
    DIRECTION OUTPUT ;
    USE SIGNAL ;
    PORT
      LAYER Metal3 ;
        RECT 1036.220000 3598.260000 1036.420000 3598.980000 ;
    END
  END ifu_axi_awaddr[8]
  PIN ifu_axi_awaddr[7]
    DIRECTION OUTPUT ;
    USE SIGNAL ;
    PORT
      LAYER Metal3 ;
        RECT 1039.580000 3598.260000 1039.780000 3598.980000 ;
    END
  END ifu_axi_awaddr[7]
  PIN ifu_axi_awaddr[6]
    DIRECTION OUTPUT ;
    USE SIGNAL ;
    PORT
      LAYER Metal3 ;
        RECT 1042.940000 3598.260000 1043.140000 3598.980000 ;
    END
  END ifu_axi_awaddr[6]
  PIN ifu_axi_awaddr[5]
    DIRECTION OUTPUT ;
    USE SIGNAL ;
    PORT
      LAYER Metal3 ;
        RECT 1046.300000 3598.260000 1046.500000 3598.980000 ;
    END
  END ifu_axi_awaddr[5]
  PIN ifu_axi_awaddr[4]
    DIRECTION OUTPUT ;
    USE SIGNAL ;
    PORT
      LAYER Metal3 ;
        RECT 1049.660000 3598.260000 1049.860000 3598.980000 ;
    END
  END ifu_axi_awaddr[4]
  PIN ifu_axi_awaddr[3]
    DIRECTION OUTPUT ;
    USE SIGNAL ;
    PORT
      LAYER Metal3 ;
        RECT 1052.540000 3598.260000 1052.740000 3598.980000 ;
    END
  END ifu_axi_awaddr[3]
  PIN ifu_axi_awaddr[2]
    DIRECTION OUTPUT ;
    USE SIGNAL ;
    PORT
      LAYER Metal3 ;
        RECT 1055.900000 3598.260000 1056.100000 3598.980000 ;
    END
  END ifu_axi_awaddr[2]
  PIN ifu_axi_awaddr[1]
    DIRECTION OUTPUT ;
    USE SIGNAL ;
    PORT
      LAYER Metal3 ;
        RECT 1059.260000 3598.260000 1059.460000 3598.980000 ;
    END
  END ifu_axi_awaddr[1]
  PIN ifu_axi_awaddr[0]
    DIRECTION OUTPUT ;
    USE SIGNAL ;
    PORT
      LAYER Metal3 ;
        RECT 1062.620000 3598.260000 1062.820000 3598.980000 ;
    END
  END ifu_axi_awaddr[0]
  PIN ifu_axi_awregion[3]
    DIRECTION OUTPUT ;
    USE SIGNAL ;
    PORT
      LAYER Metal3 ;
        RECT 1065.980000 3598.260000 1066.180000 3598.980000 ;
    END
  END ifu_axi_awregion[3]
  PIN ifu_axi_awregion[2]
    DIRECTION OUTPUT ;
    USE SIGNAL ;
    PORT
      LAYER Metal3 ;
        RECT 1068.860000 3598.260000 1069.060000 3598.980000 ;
    END
  END ifu_axi_awregion[2]
  PIN ifu_axi_awregion[1]
    DIRECTION OUTPUT ;
    USE SIGNAL ;
    PORT
      LAYER Metal3 ;
        RECT 1072.220000 3598.260000 1072.420000 3598.980000 ;
    END
  END ifu_axi_awregion[1]
  PIN ifu_axi_awregion[0]
    DIRECTION OUTPUT ;
    USE SIGNAL ;
    PORT
      LAYER Metal3 ;
        RECT 1075.580000 3598.260000 1075.780000 3598.980000 ;
    END
  END ifu_axi_awregion[0]
  PIN ifu_axi_awlen[7]
    DIRECTION OUTPUT ;
    USE SIGNAL ;
    PORT
      LAYER Metal3 ;
        RECT 1078.940000 3598.260000 1079.140000 3598.980000 ;
    END
  END ifu_axi_awlen[7]
  PIN ifu_axi_awlen[6]
    DIRECTION OUTPUT ;
    USE SIGNAL ;
    PORT
      LAYER Metal3 ;
        RECT 1081.820000 3598.260000 1082.020000 3598.980000 ;
    END
  END ifu_axi_awlen[6]
  PIN ifu_axi_awlen[5]
    DIRECTION OUTPUT ;
    USE SIGNAL ;
    PORT
      LAYER Metal3 ;
        RECT 1085.180000 3598.260000 1085.380000 3598.980000 ;
    END
  END ifu_axi_awlen[5]
  PIN ifu_axi_awlen[4]
    DIRECTION OUTPUT ;
    USE SIGNAL ;
    PORT
      LAYER Metal3 ;
        RECT 1088.540000 3598.260000 1088.740000 3598.980000 ;
    END
  END ifu_axi_awlen[4]
  PIN ifu_axi_awlen[3]
    DIRECTION OUTPUT ;
    USE SIGNAL ;
    PORT
      LAYER Metal3 ;
        RECT 1091.900000 3598.260000 1092.100000 3598.980000 ;
    END
  END ifu_axi_awlen[3]
  PIN ifu_axi_awlen[2]
    DIRECTION OUTPUT ;
    USE SIGNAL ;
    PORT
      LAYER Metal3 ;
        RECT 1095.260000 3598.260000 1095.460000 3598.980000 ;
    END
  END ifu_axi_awlen[2]
  PIN ifu_axi_awlen[1]
    DIRECTION OUTPUT ;
    USE SIGNAL ;
    PORT
      LAYER Metal3 ;
        RECT 1098.140000 3598.260000 1098.340000 3598.980000 ;
    END
  END ifu_axi_awlen[1]
  PIN ifu_axi_awlen[0]
    DIRECTION OUTPUT ;
    USE SIGNAL ;
    PORT
      LAYER Metal3 ;
        RECT 1101.500000 3598.260000 1101.700000 3598.980000 ;
    END
  END ifu_axi_awlen[0]
  PIN ifu_axi_awsize[2]
    DIRECTION OUTPUT ;
    USE SIGNAL ;
    PORT
      LAYER Metal3 ;
        RECT 1104.860000 3598.260000 1105.060000 3598.980000 ;
    END
  END ifu_axi_awsize[2]
  PIN ifu_axi_awsize[1]
    DIRECTION OUTPUT ;
    USE SIGNAL ;
    PORT
      LAYER Metal3 ;
        RECT 1108.220000 3598.260000 1108.420000 3598.980000 ;
    END
  END ifu_axi_awsize[1]
  PIN ifu_axi_awsize[0]
    DIRECTION OUTPUT ;
    USE SIGNAL ;
    PORT
      LAYER Metal3 ;
        RECT 1111.580000 3598.260000 1111.780000 3598.980000 ;
    END
  END ifu_axi_awsize[0]
  PIN ifu_axi_awburst[1]
    DIRECTION OUTPUT ;
    USE SIGNAL ;
    PORT
      LAYER Metal3 ;
        RECT 1114.460000 3598.260000 1114.660000 3598.980000 ;
    END
  END ifu_axi_awburst[1]
  PIN ifu_axi_awburst[0]
    DIRECTION OUTPUT ;
    USE SIGNAL ;
    PORT
      LAYER Metal3 ;
        RECT 1117.820000 3598.260000 1118.020000 3598.980000 ;
    END
  END ifu_axi_awburst[0]
  PIN ifu_axi_awlock
    DIRECTION OUTPUT ;
    USE SIGNAL ;
    PORT
      LAYER Metal3 ;
        RECT 1121.180000 3598.260000 1121.380000 3598.980000 ;
    END
  END ifu_axi_awlock
  PIN ifu_axi_awcache[3]
    DIRECTION OUTPUT ;
    USE SIGNAL ;
    PORT
      LAYER Metal3 ;
        RECT 1124.540000 3598.260000 1124.740000 3598.980000 ;
    END
  END ifu_axi_awcache[3]
  PIN ifu_axi_awcache[2]
    DIRECTION OUTPUT ;
    USE SIGNAL ;
    PORT
      LAYER Metal3 ;
        RECT 1127.900000 3598.260000 1128.100000 3598.980000 ;
    END
  END ifu_axi_awcache[2]
  PIN ifu_axi_awcache[1]
    DIRECTION OUTPUT ;
    USE SIGNAL ;
    PORT
      LAYER Metal3 ;
        RECT 1130.780000 3598.260000 1130.980000 3598.980000 ;
    END
  END ifu_axi_awcache[1]
  PIN ifu_axi_awcache[0]
    DIRECTION OUTPUT ;
    USE SIGNAL ;
    PORT
      LAYER Metal3 ;
        RECT 1134.140000 3598.260000 1134.340000 3598.980000 ;
    END
  END ifu_axi_awcache[0]
  PIN ifu_axi_awprot[2]
    DIRECTION OUTPUT ;
    USE SIGNAL ;
    PORT
      LAYER Metal3 ;
        RECT 1137.500000 3598.260000 1137.700000 3598.980000 ;
    END
  END ifu_axi_awprot[2]
  PIN ifu_axi_awprot[1]
    DIRECTION OUTPUT ;
    USE SIGNAL ;
    PORT
      LAYER Metal3 ;
        RECT 1140.860000 3598.260000 1141.060000 3598.980000 ;
    END
  END ifu_axi_awprot[1]
  PIN ifu_axi_awprot[0]
    DIRECTION OUTPUT ;
    USE SIGNAL ;
    PORT
      LAYER Metal3 ;
        RECT 1143.740000 3598.260000 1143.940000 3598.980000 ;
    END
  END ifu_axi_awprot[0]
  PIN ifu_axi_awqos[3]
    DIRECTION OUTPUT ;
    USE SIGNAL ;
    PORT
      LAYER Metal3 ;
        RECT 1147.100000 3598.260000 1147.300000 3598.980000 ;
    END
  END ifu_axi_awqos[3]
  PIN ifu_axi_awqos[2]
    DIRECTION OUTPUT ;
    USE SIGNAL ;
    PORT
      LAYER Metal3 ;
        RECT 1150.460000 3598.260000 1150.660000 3598.980000 ;
    END
  END ifu_axi_awqos[2]
  PIN ifu_axi_awqos[1]
    DIRECTION OUTPUT ;
    USE SIGNAL ;
    PORT
      LAYER Metal3 ;
        RECT 1153.820000 3598.260000 1154.020000 3598.980000 ;
    END
  END ifu_axi_awqos[1]
  PIN ifu_axi_awqos[0]
    DIRECTION OUTPUT ;
    USE SIGNAL ;
    PORT
      LAYER Metal3 ;
        RECT 1157.180000 3598.260000 1157.380000 3598.980000 ;
    END
  END ifu_axi_awqos[0]
  PIN ifu_axi_wvalid
    DIRECTION OUTPUT ;
    USE SIGNAL ;
    PORT
      LAYER Metal3 ;
        RECT 1160.060000 3598.260000 1160.260000 3598.980000 ;
    END
  END ifu_axi_wvalid
  PIN ifu_axi_wready
    DIRECTION INPUT ;
    USE SIGNAL ;
    PORT
      LAYER Metal3 ;
        RECT 1163.420000 3598.260000 1163.620000 3598.980000 ;
    END
  END ifu_axi_wready
  PIN ifu_axi_wdata[63]
    DIRECTION OUTPUT ;
    USE SIGNAL ;
    PORT
      LAYER Metal3 ;
        RECT 1166.780000 3598.260000 1166.980000 3598.980000 ;
    END
  END ifu_axi_wdata[63]
  PIN ifu_axi_wdata[62]
    DIRECTION OUTPUT ;
    USE SIGNAL ;
    PORT
      LAYER Metal3 ;
        RECT 1170.140000 3598.260000 1170.340000 3598.980000 ;
    END
  END ifu_axi_wdata[62]
  PIN ifu_axi_wdata[61]
    DIRECTION OUTPUT ;
    USE SIGNAL ;
    PORT
      LAYER Metal3 ;
        RECT 1173.500000 3598.260000 1173.700000 3598.980000 ;
    END
  END ifu_axi_wdata[61]
  PIN ifu_axi_wdata[60]
    DIRECTION OUTPUT ;
    USE SIGNAL ;
    PORT
      LAYER Metal3 ;
        RECT 1176.380000 3598.260000 1176.580000 3598.980000 ;
    END
  END ifu_axi_wdata[60]
  PIN ifu_axi_wdata[59]
    DIRECTION OUTPUT ;
    USE SIGNAL ;
    PORT
      LAYER Metal3 ;
        RECT 1179.740000 3598.260000 1179.940000 3598.980000 ;
    END
  END ifu_axi_wdata[59]
  PIN ifu_axi_wdata[58]
    DIRECTION OUTPUT ;
    USE SIGNAL ;
    PORT
      LAYER Metal3 ;
        RECT 1183.100000 3598.260000 1183.300000 3598.980000 ;
    END
  END ifu_axi_wdata[58]
  PIN ifu_axi_wdata[57]
    DIRECTION OUTPUT ;
    USE SIGNAL ;
    PORT
      LAYER Metal3 ;
        RECT 1186.460000 3598.260000 1186.660000 3598.980000 ;
    END
  END ifu_axi_wdata[57]
  PIN ifu_axi_wdata[56]
    DIRECTION OUTPUT ;
    USE SIGNAL ;
    PORT
      LAYER Metal3 ;
        RECT 1189.820000 3598.260000 1190.020000 3598.980000 ;
    END
  END ifu_axi_wdata[56]
  PIN ifu_axi_wdata[55]
    DIRECTION OUTPUT ;
    USE SIGNAL ;
    PORT
      LAYER Metal3 ;
        RECT 1192.700000 3598.260000 1192.900000 3598.980000 ;
    END
  END ifu_axi_wdata[55]
  PIN ifu_axi_wdata[54]
    DIRECTION OUTPUT ;
    USE SIGNAL ;
    PORT
      LAYER Metal3 ;
        RECT 1196.060000 3598.260000 1196.260000 3598.980000 ;
    END
  END ifu_axi_wdata[54]
  PIN ifu_axi_wdata[53]
    DIRECTION OUTPUT ;
    USE SIGNAL ;
    PORT
      LAYER Metal3 ;
        RECT 1199.420000 3598.260000 1199.620000 3598.980000 ;
    END
  END ifu_axi_wdata[53]
  PIN ifu_axi_wdata[52]
    DIRECTION OUTPUT ;
    USE SIGNAL ;
    PORT
      LAYER Metal3 ;
        RECT 1202.780000 3598.260000 1202.980000 3598.980000 ;
    END
  END ifu_axi_wdata[52]
  PIN ifu_axi_wdata[51]
    DIRECTION OUTPUT ;
    USE SIGNAL ;
    PORT
      LAYER Metal3 ;
        RECT 1205.660000 3598.260000 1205.860000 3598.980000 ;
    END
  END ifu_axi_wdata[51]
  PIN ifu_axi_wdata[50]
    DIRECTION OUTPUT ;
    USE SIGNAL ;
    PORT
      LAYER Metal3 ;
        RECT 1209.020000 3598.260000 1209.220000 3598.980000 ;
    END
  END ifu_axi_wdata[50]
  PIN ifu_axi_wdata[49]
    DIRECTION OUTPUT ;
    USE SIGNAL ;
    PORT
      LAYER Metal3 ;
        RECT 1212.380000 3598.260000 1212.580000 3598.980000 ;
    END
  END ifu_axi_wdata[49]
  PIN ifu_axi_wdata[48]
    DIRECTION OUTPUT ;
    USE SIGNAL ;
    PORT
      LAYER Metal3 ;
        RECT 1215.740000 3598.260000 1215.940000 3598.980000 ;
    END
  END ifu_axi_wdata[48]
  PIN ifu_axi_wdata[47]
    DIRECTION OUTPUT ;
    USE SIGNAL ;
    PORT
      LAYER Metal3 ;
        RECT 1219.100000 3598.260000 1219.300000 3598.980000 ;
    END
  END ifu_axi_wdata[47]
  PIN ifu_axi_wdata[46]
    DIRECTION OUTPUT ;
    USE SIGNAL ;
    PORT
      LAYER Metal3 ;
        RECT 1221.980000 3598.260000 1222.180000 3598.980000 ;
    END
  END ifu_axi_wdata[46]
  PIN ifu_axi_wdata[45]
    DIRECTION OUTPUT ;
    USE SIGNAL ;
    PORT
      LAYER Metal3 ;
        RECT 1225.340000 3598.260000 1225.540000 3598.980000 ;
    END
  END ifu_axi_wdata[45]
  PIN ifu_axi_wdata[44]
    DIRECTION OUTPUT ;
    USE SIGNAL ;
    PORT
      LAYER Metal3 ;
        RECT 1228.700000 3598.260000 1228.900000 3598.980000 ;
    END
  END ifu_axi_wdata[44]
  PIN ifu_axi_wdata[43]
    DIRECTION OUTPUT ;
    USE SIGNAL ;
    PORT
      LAYER Metal3 ;
        RECT 1232.060000 3598.260000 1232.260000 3598.980000 ;
    END
  END ifu_axi_wdata[43]
  PIN ifu_axi_wdata[42]
    DIRECTION OUTPUT ;
    USE SIGNAL ;
    PORT
      LAYER Metal3 ;
        RECT 1235.420000 3598.260000 1235.620000 3598.980000 ;
    END
  END ifu_axi_wdata[42]
  PIN ifu_axi_wdata[41]
    DIRECTION OUTPUT ;
    USE SIGNAL ;
    PORT
      LAYER Metal3 ;
        RECT 1238.300000 3598.260000 1238.500000 3598.980000 ;
    END
  END ifu_axi_wdata[41]
  PIN ifu_axi_wdata[40]
    DIRECTION OUTPUT ;
    USE SIGNAL ;
    PORT
      LAYER Metal3 ;
        RECT 1241.660000 3598.260000 1241.860000 3598.980000 ;
    END
  END ifu_axi_wdata[40]
  PIN ifu_axi_wdata[39]
    DIRECTION OUTPUT ;
    USE SIGNAL ;
    PORT
      LAYER Metal3 ;
        RECT 1245.020000 3598.260000 1245.220000 3598.980000 ;
    END
  END ifu_axi_wdata[39]
  PIN ifu_axi_wdata[38]
    DIRECTION OUTPUT ;
    USE SIGNAL ;
    PORT
      LAYER Metal3 ;
        RECT 1248.380000 3598.260000 1248.580000 3598.980000 ;
    END
  END ifu_axi_wdata[38]
  PIN ifu_axi_wdata[37]
    DIRECTION OUTPUT ;
    USE SIGNAL ;
    PORT
      LAYER Metal3 ;
        RECT 1251.740000 3598.260000 1251.940000 3598.980000 ;
    END
  END ifu_axi_wdata[37]
  PIN ifu_axi_wdata[36]
    DIRECTION OUTPUT ;
    USE SIGNAL ;
    PORT
      LAYER Metal3 ;
        RECT 1254.620000 3598.260000 1254.820000 3598.980000 ;
    END
  END ifu_axi_wdata[36]
  PIN ifu_axi_wdata[35]
    DIRECTION OUTPUT ;
    USE SIGNAL ;
    PORT
      LAYER Metal3 ;
        RECT 1257.980000 3598.260000 1258.180000 3598.980000 ;
    END
  END ifu_axi_wdata[35]
  PIN ifu_axi_wdata[34]
    DIRECTION OUTPUT ;
    USE SIGNAL ;
    PORT
      LAYER Metal3 ;
        RECT 1261.340000 3598.260000 1261.540000 3598.980000 ;
    END
  END ifu_axi_wdata[34]
  PIN ifu_axi_wdata[33]
    DIRECTION OUTPUT ;
    USE SIGNAL ;
    PORT
      LAYER Metal3 ;
        RECT 1264.700000 3598.260000 1264.900000 3598.980000 ;
    END
  END ifu_axi_wdata[33]
  PIN ifu_axi_wdata[32]
    DIRECTION OUTPUT ;
    USE SIGNAL ;
    PORT
      LAYER Metal3 ;
        RECT 1267.580000 3598.260000 1267.780000 3598.980000 ;
    END
  END ifu_axi_wdata[32]
  PIN ifu_axi_wdata[31]
    DIRECTION OUTPUT ;
    USE SIGNAL ;
    PORT
      LAYER Metal3 ;
        RECT 1270.940000 3598.260000 1271.140000 3598.980000 ;
    END
  END ifu_axi_wdata[31]
  PIN ifu_axi_wdata[30]
    DIRECTION OUTPUT ;
    USE SIGNAL ;
    PORT
      LAYER Metal3 ;
        RECT 1274.300000 3598.260000 1274.500000 3598.980000 ;
    END
  END ifu_axi_wdata[30]
  PIN ifu_axi_wdata[29]
    DIRECTION OUTPUT ;
    USE SIGNAL ;
    PORT
      LAYER Metal3 ;
        RECT 1277.660000 3598.260000 1277.860000 3598.980000 ;
    END
  END ifu_axi_wdata[29]
  PIN ifu_axi_wdata[28]
    DIRECTION OUTPUT ;
    USE SIGNAL ;
    PORT
      LAYER Metal3 ;
        RECT 1281.020000 3598.260000 1281.220000 3598.980000 ;
    END
  END ifu_axi_wdata[28]
  PIN ifu_axi_wdata[27]
    DIRECTION OUTPUT ;
    USE SIGNAL ;
    PORT
      LAYER Metal3 ;
        RECT 1283.900000 3598.260000 1284.100000 3598.980000 ;
    END
  END ifu_axi_wdata[27]
  PIN ifu_axi_wdata[26]
    DIRECTION OUTPUT ;
    USE SIGNAL ;
    PORT
      LAYER Metal3 ;
        RECT 1287.260000 3598.260000 1287.460000 3598.980000 ;
    END
  END ifu_axi_wdata[26]
  PIN ifu_axi_wdata[25]
    DIRECTION OUTPUT ;
    USE SIGNAL ;
    PORT
      LAYER Metal3 ;
        RECT 1290.620000 3598.260000 1290.820000 3598.980000 ;
    END
  END ifu_axi_wdata[25]
  PIN ifu_axi_wdata[24]
    DIRECTION OUTPUT ;
    USE SIGNAL ;
    PORT
      LAYER Metal3 ;
        RECT 1293.980000 3598.260000 1294.180000 3598.980000 ;
    END
  END ifu_axi_wdata[24]
  PIN ifu_axi_wdata[23]
    DIRECTION OUTPUT ;
    USE SIGNAL ;
    PORT
      LAYER Metal3 ;
        RECT 1297.340000 3598.260000 1297.540000 3598.980000 ;
    END
  END ifu_axi_wdata[23]
  PIN ifu_axi_wdata[22]
    DIRECTION OUTPUT ;
    USE SIGNAL ;
    PORT
      LAYER Metal3 ;
        RECT 1300.220000 3598.260000 1300.420000 3598.980000 ;
    END
  END ifu_axi_wdata[22]
  PIN ifu_axi_wdata[21]
    DIRECTION OUTPUT ;
    USE SIGNAL ;
    PORT
      LAYER Metal3 ;
        RECT 1303.580000 3598.260000 1303.780000 3598.980000 ;
    END
  END ifu_axi_wdata[21]
  PIN ifu_axi_wdata[20]
    DIRECTION OUTPUT ;
    USE SIGNAL ;
    PORT
      LAYER Metal3 ;
        RECT 1306.940000 3598.260000 1307.140000 3598.980000 ;
    END
  END ifu_axi_wdata[20]
  PIN ifu_axi_wdata[19]
    DIRECTION OUTPUT ;
    USE SIGNAL ;
    PORT
      LAYER Metal3 ;
        RECT 1310.300000 3598.260000 1310.500000 3598.980000 ;
    END
  END ifu_axi_wdata[19]
  PIN ifu_axi_wdata[18]
    DIRECTION OUTPUT ;
    USE SIGNAL ;
    PORT
      LAYER Metal3 ;
        RECT 1313.660000 3598.260000 1313.860000 3598.980000 ;
    END
  END ifu_axi_wdata[18]
  PIN ifu_axi_wdata[17]
    DIRECTION OUTPUT ;
    USE SIGNAL ;
    PORT
      LAYER Metal3 ;
        RECT 1316.540000 3598.260000 1316.740000 3598.980000 ;
    END
  END ifu_axi_wdata[17]
  PIN ifu_axi_wdata[16]
    DIRECTION OUTPUT ;
    USE SIGNAL ;
    PORT
      LAYER Metal3 ;
        RECT 1319.900000 3598.260000 1320.100000 3598.980000 ;
    END
  END ifu_axi_wdata[16]
  PIN ifu_axi_wdata[15]
    DIRECTION OUTPUT ;
    USE SIGNAL ;
    PORT
      LAYER Metal3 ;
        RECT 1323.260000 3598.260000 1323.460000 3598.980000 ;
    END
  END ifu_axi_wdata[15]
  PIN ifu_axi_wdata[14]
    DIRECTION OUTPUT ;
    USE SIGNAL ;
    PORT
      LAYER Metal3 ;
        RECT 1326.620000 3598.260000 1326.820000 3598.980000 ;
    END
  END ifu_axi_wdata[14]
  PIN ifu_axi_wdata[13]
    DIRECTION OUTPUT ;
    USE SIGNAL ;
    PORT
      LAYER Metal3 ;
        RECT 1329.500000 3598.260000 1329.700000 3598.980000 ;
    END
  END ifu_axi_wdata[13]
  PIN ifu_axi_wdata[12]
    DIRECTION OUTPUT ;
    USE SIGNAL ;
    PORT
      LAYER Metal3 ;
        RECT 1332.860000 3598.260000 1333.060000 3598.980000 ;
    END
  END ifu_axi_wdata[12]
  PIN ifu_axi_wdata[11]
    DIRECTION OUTPUT ;
    USE SIGNAL ;
    PORT
      LAYER Metal3 ;
        RECT 1336.220000 3598.260000 1336.420000 3598.980000 ;
    END
  END ifu_axi_wdata[11]
  PIN ifu_axi_wdata[10]
    DIRECTION OUTPUT ;
    USE SIGNAL ;
    PORT
      LAYER Metal3 ;
        RECT 1339.580000 3598.260000 1339.780000 3598.980000 ;
    END
  END ifu_axi_wdata[10]
  PIN ifu_axi_wdata[9]
    DIRECTION OUTPUT ;
    USE SIGNAL ;
    PORT
      LAYER Metal3 ;
        RECT 1342.940000 3598.260000 1343.140000 3598.980000 ;
    END
  END ifu_axi_wdata[9]
  PIN ifu_axi_wdata[8]
    DIRECTION OUTPUT ;
    USE SIGNAL ;
    PORT
      LAYER Metal3 ;
        RECT 1345.820000 3598.260000 1346.020000 3598.980000 ;
    END
  END ifu_axi_wdata[8]
  PIN ifu_axi_wdata[7]
    DIRECTION OUTPUT ;
    USE SIGNAL ;
    PORT
      LAYER Metal3 ;
        RECT 1349.180000 3598.260000 1349.380000 3598.980000 ;
    END
  END ifu_axi_wdata[7]
  PIN ifu_axi_wdata[6]
    DIRECTION OUTPUT ;
    USE SIGNAL ;
    PORT
      LAYER Metal3 ;
        RECT 1352.540000 3598.260000 1352.740000 3598.980000 ;
    END
  END ifu_axi_wdata[6]
  PIN ifu_axi_wdata[5]
    DIRECTION OUTPUT ;
    USE SIGNAL ;
    PORT
      LAYER Metal3 ;
        RECT 1355.900000 3598.260000 1356.100000 3598.980000 ;
    END
  END ifu_axi_wdata[5]
  PIN ifu_axi_wdata[4]
    DIRECTION OUTPUT ;
    USE SIGNAL ;
    PORT
      LAYER Metal3 ;
        RECT 1359.260000 3598.260000 1359.460000 3598.980000 ;
    END
  END ifu_axi_wdata[4]
  PIN ifu_axi_wdata[3]
    DIRECTION OUTPUT ;
    USE SIGNAL ;
    PORT
      LAYER Metal3 ;
        RECT 1362.140000 3598.260000 1362.340000 3598.980000 ;
    END
  END ifu_axi_wdata[3]
  PIN ifu_axi_wdata[2]
    DIRECTION OUTPUT ;
    USE SIGNAL ;
    PORT
      LAYER Metal3 ;
        RECT 1365.500000 3598.260000 1365.700000 3598.980000 ;
    END
  END ifu_axi_wdata[2]
  PIN ifu_axi_wdata[1]
    DIRECTION OUTPUT ;
    USE SIGNAL ;
    PORT
      LAYER Metal3 ;
        RECT 1368.860000 3598.260000 1369.060000 3598.980000 ;
    END
  END ifu_axi_wdata[1]
  PIN ifu_axi_wdata[0]
    DIRECTION OUTPUT ;
    USE SIGNAL ;
    PORT
      LAYER Metal3 ;
        RECT 1372.220000 3598.260000 1372.420000 3598.980000 ;
    END
  END ifu_axi_wdata[0]
  PIN ifu_axi_wstrb[7]
    DIRECTION OUTPUT ;
    USE SIGNAL ;
    PORT
      LAYER Metal3 ;
        RECT 1375.580000 3598.260000 1375.780000 3598.980000 ;
    END
  END ifu_axi_wstrb[7]
  PIN ifu_axi_wstrb[6]
    DIRECTION OUTPUT ;
    USE SIGNAL ;
    PORT
      LAYER Metal3 ;
        RECT 1378.460000 3598.260000 1378.660000 3598.980000 ;
    END
  END ifu_axi_wstrb[6]
  PIN ifu_axi_wstrb[5]
    DIRECTION OUTPUT ;
    USE SIGNAL ;
    PORT
      LAYER Metal3 ;
        RECT 1381.820000 3598.260000 1382.020000 3598.980000 ;
    END
  END ifu_axi_wstrb[5]
  PIN ifu_axi_wstrb[4]
    DIRECTION OUTPUT ;
    USE SIGNAL ;
    PORT
      LAYER Metal3 ;
        RECT 1385.180000 3598.260000 1385.380000 3598.980000 ;
    END
  END ifu_axi_wstrb[4]
  PIN ifu_axi_wstrb[3]
    DIRECTION OUTPUT ;
    USE SIGNAL ;
    PORT
      LAYER Metal3 ;
        RECT 1388.540000 3598.260000 1388.740000 3598.980000 ;
    END
  END ifu_axi_wstrb[3]
  PIN ifu_axi_wstrb[2]
    DIRECTION OUTPUT ;
    USE SIGNAL ;
    PORT
      LAYER Metal3 ;
        RECT 1391.420000 3598.260000 1391.620000 3598.980000 ;
    END
  END ifu_axi_wstrb[2]
  PIN ifu_axi_wstrb[1]
    DIRECTION OUTPUT ;
    USE SIGNAL ;
    PORT
      LAYER Metal3 ;
        RECT 1394.780000 3598.260000 1394.980000 3598.980000 ;
    END
  END ifu_axi_wstrb[1]
  PIN ifu_axi_wstrb[0]
    DIRECTION OUTPUT ;
    USE SIGNAL ;
    PORT
      LAYER Metal3 ;
        RECT 1398.140000 3598.260000 1398.340000 3598.980000 ;
    END
  END ifu_axi_wstrb[0]
  PIN ifu_axi_wlast
    DIRECTION OUTPUT ;
    USE SIGNAL ;
    PORT
      LAYER Metal3 ;
        RECT 1401.500000 3598.260000 1401.700000 3598.980000 ;
    END
  END ifu_axi_wlast
  PIN ifu_axi_bvalid
    DIRECTION INPUT ;
    USE SIGNAL ;
    PORT
      LAYER Metal3 ;
        RECT 1404.860000 3598.260000 1405.060000 3598.980000 ;
    END
  END ifu_axi_bvalid
  PIN ifu_axi_bready
    DIRECTION OUTPUT ;
    USE SIGNAL ;
    PORT
      LAYER Metal3 ;
        RECT 1407.740000 3598.260000 1407.940000 3598.980000 ;
    END
  END ifu_axi_bready
  PIN ifu_axi_bresp[1]
    DIRECTION INPUT ;
    USE SIGNAL ;
    PORT
      LAYER Metal3 ;
        RECT 1411.100000 3598.260000 1411.300000 3598.980000 ;
    END
  END ifu_axi_bresp[1]
  PIN ifu_axi_bresp[0]
    DIRECTION INPUT ;
    USE SIGNAL ;
    PORT
      LAYER Metal3 ;
        RECT 1414.460000 3598.260000 1414.660000 3598.980000 ;
    END
  END ifu_axi_bresp[0]
  PIN ifu_axi_bid[2]
    DIRECTION INPUT ;
    USE SIGNAL ;
    PORT
      LAYER Metal3 ;
        RECT 1417.820000 3598.260000 1418.020000 3598.980000 ;
    END
  END ifu_axi_bid[2]
  PIN ifu_axi_bid[1]
    DIRECTION INPUT ;
    USE SIGNAL ;
    PORT
      LAYER Metal3 ;
        RECT 1421.180000 3598.260000 1421.380000 3598.980000 ;
    END
  END ifu_axi_bid[1]
  PIN ifu_axi_bid[0]
    DIRECTION INPUT ;
    USE SIGNAL ;
    PORT
      LAYER Metal3 ;
        RECT 1424.060000 3598.260000 1424.260000 3598.980000 ;
    END
  END ifu_axi_bid[0]
  PIN ifu_axi_arvalid
    DIRECTION OUTPUT ;
    USE SIGNAL ;
    PORT
      LAYER Metal3 ;
        RECT 1427.420000 3598.260000 1427.620000 3598.980000 ;
    END
  END ifu_axi_arvalid
  PIN ifu_axi_arready
    DIRECTION INPUT ;
    USE SIGNAL ;
    PORT
      LAYER Metal3 ;
        RECT 1430.780000 3598.260000 1430.980000 3598.980000 ;
    END
  END ifu_axi_arready
  PIN ifu_axi_arid[2]
    DIRECTION OUTPUT ;
    USE SIGNAL ;
    PORT
      LAYER Metal3 ;
        RECT 1434.140000 3598.260000 1434.340000 3598.980000 ;
    END
  END ifu_axi_arid[2]
  PIN ifu_axi_arid[1]
    DIRECTION OUTPUT ;
    USE SIGNAL ;
    PORT
      LAYER Metal3 ;
        RECT 1437.500000 3598.260000 1437.700000 3598.980000 ;
    END
  END ifu_axi_arid[1]
  PIN ifu_axi_arid[0]
    DIRECTION OUTPUT ;
    USE SIGNAL ;
    PORT
      LAYER Metal3 ;
        RECT 1440.380000 3598.260000 1440.580000 3598.980000 ;
    END
  END ifu_axi_arid[0]
  PIN ifu_axi_araddr[31]
    DIRECTION OUTPUT ;
    USE SIGNAL ;
    PORT
      LAYER Metal3 ;
        RECT 1443.740000 3598.260000 1443.940000 3598.980000 ;
    END
  END ifu_axi_araddr[31]
  PIN ifu_axi_araddr[30]
    DIRECTION OUTPUT ;
    USE SIGNAL ;
    PORT
      LAYER Metal3 ;
        RECT 1447.100000 3598.260000 1447.300000 3598.980000 ;
    END
  END ifu_axi_araddr[30]
  PIN ifu_axi_araddr[29]
    DIRECTION OUTPUT ;
    USE SIGNAL ;
    PORT
      LAYER Metal3 ;
        RECT 1450.460000 3598.260000 1450.660000 3598.980000 ;
    END
  END ifu_axi_araddr[29]
  PIN ifu_axi_araddr[28]
    DIRECTION OUTPUT ;
    USE SIGNAL ;
    PORT
      LAYER Metal3 ;
        RECT 1453.340000 3598.260000 1453.540000 3598.980000 ;
    END
  END ifu_axi_araddr[28]
  PIN ifu_axi_araddr[27]
    DIRECTION OUTPUT ;
    USE SIGNAL ;
    PORT
      LAYER Metal3 ;
        RECT 1456.700000 3598.260000 1456.900000 3598.980000 ;
    END
  END ifu_axi_araddr[27]
  PIN ifu_axi_araddr[26]
    DIRECTION OUTPUT ;
    USE SIGNAL ;
    PORT
      LAYER Metal3 ;
        RECT 1460.060000 3598.260000 1460.260000 3598.980000 ;
    END
  END ifu_axi_araddr[26]
  PIN ifu_axi_araddr[25]
    DIRECTION OUTPUT ;
    USE SIGNAL ;
    PORT
      LAYER Metal3 ;
        RECT 1463.420000 3598.260000 1463.620000 3598.980000 ;
    END
  END ifu_axi_araddr[25]
  PIN ifu_axi_araddr[24]
    DIRECTION OUTPUT ;
    USE SIGNAL ;
    PORT
      LAYER Metal3 ;
        RECT 1466.780000 3598.260000 1466.980000 3598.980000 ;
    END
  END ifu_axi_araddr[24]
  PIN ifu_axi_araddr[23]
    DIRECTION OUTPUT ;
    USE SIGNAL ;
    PORT
      LAYER Metal3 ;
        RECT 1469.660000 3598.260000 1469.860000 3598.980000 ;
    END
  END ifu_axi_araddr[23]
  PIN ifu_axi_araddr[22]
    DIRECTION OUTPUT ;
    USE SIGNAL ;
    PORT
      LAYER Metal3 ;
        RECT 1473.020000 3598.260000 1473.220000 3598.980000 ;
    END
  END ifu_axi_araddr[22]
  PIN ifu_axi_araddr[21]
    DIRECTION OUTPUT ;
    USE SIGNAL ;
    PORT
      LAYER Metal3 ;
        RECT 1476.380000 3598.260000 1476.580000 3598.980000 ;
    END
  END ifu_axi_araddr[21]
  PIN ifu_axi_araddr[20]
    DIRECTION OUTPUT ;
    USE SIGNAL ;
    PORT
      LAYER Metal3 ;
        RECT 1479.740000 3598.260000 1479.940000 3598.980000 ;
    END
  END ifu_axi_araddr[20]
  PIN ifu_axi_araddr[19]
    DIRECTION OUTPUT ;
    USE SIGNAL ;
    PORT
      LAYER Metal3 ;
        RECT 1483.100000 3598.260000 1483.300000 3598.980000 ;
    END
  END ifu_axi_araddr[19]
  PIN ifu_axi_araddr[18]
    DIRECTION OUTPUT ;
    USE SIGNAL ;
    PORT
      LAYER Metal3 ;
        RECT 1485.980000 3598.260000 1486.180000 3598.980000 ;
    END
  END ifu_axi_araddr[18]
  PIN ifu_axi_araddr[17]
    DIRECTION OUTPUT ;
    USE SIGNAL ;
    PORT
      LAYER Metal3 ;
        RECT 1489.340000 3598.260000 1489.540000 3598.980000 ;
    END
  END ifu_axi_araddr[17]
  PIN ifu_axi_araddr[16]
    DIRECTION OUTPUT ;
    USE SIGNAL ;
    PORT
      LAYER Metal3 ;
        RECT 1492.700000 3598.260000 1492.900000 3598.980000 ;
    END
  END ifu_axi_araddr[16]
  PIN ifu_axi_araddr[15]
    DIRECTION OUTPUT ;
    USE SIGNAL ;
    PORT
      LAYER Metal3 ;
        RECT 1496.060000 3598.260000 1496.260000 3598.980000 ;
    END
  END ifu_axi_araddr[15]
  PIN ifu_axi_araddr[14]
    DIRECTION OUTPUT ;
    USE SIGNAL ;
    PORT
      LAYER Metal3 ;
        RECT 1499.420000 3598.260000 1499.620000 3598.980000 ;
    END
  END ifu_axi_araddr[14]
  PIN ifu_axi_araddr[13]
    DIRECTION OUTPUT ;
    USE SIGNAL ;
    PORT
      LAYER Metal3 ;
        RECT 1502.300000 3598.260000 1502.500000 3598.980000 ;
    END
  END ifu_axi_araddr[13]
  PIN ifu_axi_araddr[12]
    DIRECTION OUTPUT ;
    USE SIGNAL ;
    PORT
      LAYER Metal3 ;
        RECT 1505.660000 3598.260000 1505.860000 3598.980000 ;
    END
  END ifu_axi_araddr[12]
  PIN ifu_axi_araddr[11]
    DIRECTION OUTPUT ;
    USE SIGNAL ;
    PORT
      LAYER Metal3 ;
        RECT 1509.020000 3598.260000 1509.220000 3598.980000 ;
    END
  END ifu_axi_araddr[11]
  PIN ifu_axi_araddr[10]
    DIRECTION OUTPUT ;
    USE SIGNAL ;
    PORT
      LAYER Metal3 ;
        RECT 1512.380000 3598.260000 1512.580000 3598.980000 ;
    END
  END ifu_axi_araddr[10]
  PIN ifu_axi_araddr[9]
    DIRECTION OUTPUT ;
    USE SIGNAL ;
    PORT
      LAYER Metal3 ;
        RECT 1515.260000 3598.260000 1515.460000 3598.980000 ;
    END
  END ifu_axi_araddr[9]
  PIN ifu_axi_araddr[8]
    DIRECTION OUTPUT ;
    USE SIGNAL ;
    PORT
      LAYER Metal3 ;
        RECT 1518.620000 3598.260000 1518.820000 3598.980000 ;
    END
  END ifu_axi_araddr[8]
  PIN ifu_axi_araddr[7]
    DIRECTION OUTPUT ;
    USE SIGNAL ;
    PORT
      LAYER Metal3 ;
        RECT 1521.980000 3598.260000 1522.180000 3598.980000 ;
    END
  END ifu_axi_araddr[7]
  PIN ifu_axi_araddr[6]
    DIRECTION OUTPUT ;
    USE SIGNAL ;
    PORT
      LAYER Metal3 ;
        RECT 1525.340000 3598.260000 1525.540000 3598.980000 ;
    END
  END ifu_axi_araddr[6]
  PIN ifu_axi_araddr[5]
    DIRECTION OUTPUT ;
    USE SIGNAL ;
    PORT
      LAYER Metal3 ;
        RECT 1528.700000 3598.260000 1528.900000 3598.980000 ;
    END
  END ifu_axi_araddr[5]
  PIN ifu_axi_araddr[4]
    DIRECTION OUTPUT ;
    USE SIGNAL ;
    PORT
      LAYER Metal3 ;
        RECT 1531.580000 3598.260000 1531.780000 3598.980000 ;
    END
  END ifu_axi_araddr[4]
  PIN ifu_axi_araddr[3]
    DIRECTION OUTPUT ;
    USE SIGNAL ;
    PORT
      LAYER Metal3 ;
        RECT 1534.940000 3598.260000 1535.140000 3598.980000 ;
    END
  END ifu_axi_araddr[3]
  PIN ifu_axi_araddr[2]
    DIRECTION OUTPUT ;
    USE SIGNAL ;
    PORT
      LAYER Metal3 ;
        RECT 1538.300000 3598.260000 1538.500000 3598.980000 ;
    END
  END ifu_axi_araddr[2]
  PIN ifu_axi_araddr[1]
    DIRECTION OUTPUT ;
    USE SIGNAL ;
    PORT
      LAYER Metal3 ;
        RECT 1541.660000 3598.260000 1541.860000 3598.980000 ;
    END
  END ifu_axi_araddr[1]
  PIN ifu_axi_araddr[0]
    DIRECTION OUTPUT ;
    USE SIGNAL ;
    PORT
      LAYER Metal3 ;
        RECT 1545.020000 3598.260000 1545.220000 3598.980000 ;
    END
  END ifu_axi_araddr[0]
  PIN ifu_axi_arregion[3]
    DIRECTION OUTPUT ;
    USE SIGNAL ;
    PORT
      LAYER Metal3 ;
        RECT 1547.900000 3598.260000 1548.100000 3598.980000 ;
    END
  END ifu_axi_arregion[3]
  PIN ifu_axi_arregion[2]
    DIRECTION OUTPUT ;
    USE SIGNAL ;
    PORT
      LAYER Metal3 ;
        RECT 1551.260000 3598.260000 1551.460000 3598.980000 ;
    END
  END ifu_axi_arregion[2]
  PIN ifu_axi_arregion[1]
    DIRECTION OUTPUT ;
    USE SIGNAL ;
    PORT
      LAYER Metal3 ;
        RECT 1554.620000 3598.260000 1554.820000 3598.980000 ;
    END
  END ifu_axi_arregion[1]
  PIN ifu_axi_arregion[0]
    DIRECTION OUTPUT ;
    USE SIGNAL ;
    PORT
      LAYER Metal3 ;
        RECT 1557.980000 3598.260000 1558.180000 3598.980000 ;
    END
  END ifu_axi_arregion[0]
  PIN ifu_axi_arlen[7]
    DIRECTION OUTPUT ;
    USE SIGNAL ;
    PORT
      LAYER Metal3 ;
        RECT 1560.860000 3598.260000 1561.060000 3598.980000 ;
    END
  END ifu_axi_arlen[7]
  PIN ifu_axi_arlen[6]
    DIRECTION OUTPUT ;
    USE SIGNAL ;
    PORT
      LAYER Metal3 ;
        RECT 1564.220000 3598.260000 1564.420000 3598.980000 ;
    END
  END ifu_axi_arlen[6]
  PIN ifu_axi_arlen[5]
    DIRECTION OUTPUT ;
    USE SIGNAL ;
    PORT
      LAYER Metal3 ;
        RECT 1567.580000 3598.260000 1567.780000 3598.980000 ;
    END
  END ifu_axi_arlen[5]
  PIN ifu_axi_arlen[4]
    DIRECTION OUTPUT ;
    USE SIGNAL ;
    PORT
      LAYER Metal3 ;
        RECT 1570.940000 3598.260000 1571.140000 3598.980000 ;
    END
  END ifu_axi_arlen[4]
  PIN ifu_axi_arlen[3]
    DIRECTION OUTPUT ;
    USE SIGNAL ;
    PORT
      LAYER Metal3 ;
        RECT 1574.300000 3598.260000 1574.500000 3598.980000 ;
    END
  END ifu_axi_arlen[3]
  PIN ifu_axi_arlen[2]
    DIRECTION OUTPUT ;
    USE SIGNAL ;
    PORT
      LAYER Metal3 ;
        RECT 1577.180000 3598.260000 1577.380000 3598.980000 ;
    END
  END ifu_axi_arlen[2]
  PIN ifu_axi_arlen[1]
    DIRECTION OUTPUT ;
    USE SIGNAL ;
    PORT
      LAYER Metal3 ;
        RECT 1580.540000 3598.260000 1580.740000 3598.980000 ;
    END
  END ifu_axi_arlen[1]
  PIN ifu_axi_arlen[0]
    DIRECTION OUTPUT ;
    USE SIGNAL ;
    PORT
      LAYER Metal3 ;
        RECT 1583.900000 3598.260000 1584.100000 3598.980000 ;
    END
  END ifu_axi_arlen[0]
  PIN ifu_axi_arsize[2]
    DIRECTION OUTPUT ;
    USE SIGNAL ;
    PORT
      LAYER Metal3 ;
        RECT 1587.260000 3598.260000 1587.460000 3598.980000 ;
    END
  END ifu_axi_arsize[2]
  PIN ifu_axi_arsize[1]
    DIRECTION OUTPUT ;
    USE SIGNAL ;
    PORT
      LAYER Metal3 ;
        RECT 1590.620000 3598.260000 1590.820000 3598.980000 ;
    END
  END ifu_axi_arsize[1]
  PIN ifu_axi_arsize[0]
    DIRECTION OUTPUT ;
    USE SIGNAL ;
    PORT
      LAYER Metal3 ;
        RECT 1593.500000 3598.260000 1593.700000 3598.980000 ;
    END
  END ifu_axi_arsize[0]
  PIN ifu_axi_arburst[1]
    DIRECTION OUTPUT ;
    USE SIGNAL ;
    PORT
      LAYER Metal3 ;
        RECT 1596.860000 3598.260000 1597.060000 3598.980000 ;
    END
  END ifu_axi_arburst[1]
  PIN ifu_axi_arburst[0]
    DIRECTION OUTPUT ;
    USE SIGNAL ;
    PORT
      LAYER Metal3 ;
        RECT 1600.220000 3598.260000 1600.420000 3598.980000 ;
    END
  END ifu_axi_arburst[0]
  PIN ifu_axi_arlock
    DIRECTION OUTPUT ;
    USE SIGNAL ;
    PORT
      LAYER Metal3 ;
        RECT 1603.580000 3598.260000 1603.780000 3598.980000 ;
    END
  END ifu_axi_arlock
  PIN ifu_axi_arcache[3]
    DIRECTION OUTPUT ;
    USE SIGNAL ;
    PORT
      LAYER Metal3 ;
        RECT 1606.940000 3598.260000 1607.140000 3598.980000 ;
    END
  END ifu_axi_arcache[3]
  PIN ifu_axi_arcache[2]
    DIRECTION OUTPUT ;
    USE SIGNAL ;
    PORT
      LAYER Metal3 ;
        RECT 1609.820000 3598.260000 1610.020000 3598.980000 ;
    END
  END ifu_axi_arcache[2]
  PIN ifu_axi_arcache[1]
    DIRECTION OUTPUT ;
    USE SIGNAL ;
    PORT
      LAYER Metal3 ;
        RECT 1613.180000 3598.260000 1613.380000 3598.980000 ;
    END
  END ifu_axi_arcache[1]
  PIN ifu_axi_arcache[0]
    DIRECTION OUTPUT ;
    USE SIGNAL ;
    PORT
      LAYER Metal3 ;
        RECT 1616.540000 3598.260000 1616.740000 3598.980000 ;
    END
  END ifu_axi_arcache[0]
  PIN ifu_axi_arprot[2]
    DIRECTION OUTPUT ;
    USE SIGNAL ;
    PORT
      LAYER Metal3 ;
        RECT 1619.900000 3598.260000 1620.100000 3598.980000 ;
    END
  END ifu_axi_arprot[2]
  PIN ifu_axi_arprot[1]
    DIRECTION OUTPUT ;
    USE SIGNAL ;
    PORT
      LAYER Metal3 ;
        RECT 1622.780000 3598.260000 1622.980000 3598.980000 ;
    END
  END ifu_axi_arprot[1]
  PIN ifu_axi_arprot[0]
    DIRECTION OUTPUT ;
    USE SIGNAL ;
    PORT
      LAYER Metal3 ;
        RECT 1626.140000 3598.260000 1626.340000 3598.980000 ;
    END
  END ifu_axi_arprot[0]
  PIN ifu_axi_arqos[3]
    DIRECTION OUTPUT ;
    USE SIGNAL ;
    PORT
      LAYER Metal3 ;
        RECT 1629.500000 3598.260000 1629.700000 3598.980000 ;
    END
  END ifu_axi_arqos[3]
  PIN ifu_axi_arqos[2]
    DIRECTION OUTPUT ;
    USE SIGNAL ;
    PORT
      LAYER Metal3 ;
        RECT 1632.860000 3598.260000 1633.060000 3598.980000 ;
    END
  END ifu_axi_arqos[2]
  PIN ifu_axi_arqos[1]
    DIRECTION OUTPUT ;
    USE SIGNAL ;
    PORT
      LAYER Metal3 ;
        RECT 1636.220000 3598.260000 1636.420000 3598.980000 ;
    END
  END ifu_axi_arqos[1]
  PIN ifu_axi_arqos[0]
    DIRECTION OUTPUT ;
    USE SIGNAL ;
    PORT
      LAYER Metal3 ;
        RECT 1639.100000 3598.260000 1639.300000 3598.980000 ;
    END
  END ifu_axi_arqos[0]
  PIN ifu_axi_rvalid
    DIRECTION INPUT ;
    USE SIGNAL ;
    PORT
      LAYER Metal3 ;
        RECT 1642.460000 3598.260000 1642.660000 3598.980000 ;
    END
  END ifu_axi_rvalid
  PIN ifu_axi_rready
    DIRECTION OUTPUT ;
    USE SIGNAL ;
    PORT
      LAYER Metal3 ;
        RECT 1645.820000 3598.260000 1646.020000 3598.980000 ;
    END
  END ifu_axi_rready
  PIN ifu_axi_rid[2]
    DIRECTION INPUT ;
    USE SIGNAL ;
    PORT
      LAYER Metal3 ;
        RECT 1649.180000 3598.260000 1649.380000 3598.980000 ;
    END
  END ifu_axi_rid[2]
  PIN ifu_axi_rid[1]
    DIRECTION INPUT ;
    USE SIGNAL ;
    PORT
      LAYER Metal3 ;
        RECT 1652.540000 3598.260000 1652.740000 3598.980000 ;
    END
  END ifu_axi_rid[1]
  PIN ifu_axi_rid[0]
    DIRECTION INPUT ;
    USE SIGNAL ;
    PORT
      LAYER Metal3 ;
        RECT 1655.420000 3598.260000 1655.620000 3598.980000 ;
    END
  END ifu_axi_rid[0]
  PIN ifu_axi_rdata[63]
    DIRECTION INPUT ;
    USE SIGNAL ;
    PORT
      LAYER Metal3 ;
        RECT 1658.780000 3598.260000 1658.980000 3598.980000 ;
    END
  END ifu_axi_rdata[63]
  PIN ifu_axi_rdata[62]
    DIRECTION INPUT ;
    USE SIGNAL ;
    PORT
      LAYER Metal3 ;
        RECT 1662.140000 3598.260000 1662.340000 3598.980000 ;
    END
  END ifu_axi_rdata[62]
  PIN ifu_axi_rdata[61]
    DIRECTION INPUT ;
    USE SIGNAL ;
    PORT
      LAYER Metal3 ;
        RECT 1665.500000 3598.260000 1665.700000 3598.980000 ;
    END
  END ifu_axi_rdata[61]
  PIN ifu_axi_rdata[60]
    DIRECTION INPUT ;
    USE SIGNAL ;
    PORT
      LAYER Metal3 ;
        RECT 1668.860000 3598.260000 1669.060000 3598.980000 ;
    END
  END ifu_axi_rdata[60]
  PIN ifu_axi_rdata[59]
    DIRECTION INPUT ;
    USE SIGNAL ;
    PORT
      LAYER Metal3 ;
        RECT 1671.740000 3598.260000 1671.940000 3598.980000 ;
    END
  END ifu_axi_rdata[59]
  PIN ifu_axi_rdata[58]
    DIRECTION INPUT ;
    USE SIGNAL ;
    PORT
      LAYER Metal3 ;
        RECT 1675.100000 3598.260000 1675.300000 3598.980000 ;
    END
  END ifu_axi_rdata[58]
  PIN ifu_axi_rdata[57]
    DIRECTION INPUT ;
    USE SIGNAL ;
    PORT
      LAYER Metal3 ;
        RECT 1678.460000 3598.260000 1678.660000 3598.980000 ;
    END
  END ifu_axi_rdata[57]
  PIN ifu_axi_rdata[56]
    DIRECTION INPUT ;
    USE SIGNAL ;
    PORT
      LAYER Metal3 ;
        RECT 1681.820000 3598.260000 1682.020000 3598.980000 ;
    END
  END ifu_axi_rdata[56]
  PIN ifu_axi_rdata[55]
    DIRECTION INPUT ;
    USE SIGNAL ;
    PORT
      LAYER Metal3 ;
        RECT 1684.700000 3598.260000 1684.900000 3598.980000 ;
    END
  END ifu_axi_rdata[55]
  PIN ifu_axi_rdata[54]
    DIRECTION INPUT ;
    USE SIGNAL ;
    PORT
      LAYER Metal3 ;
        RECT 1688.060000 3598.260000 1688.260000 3598.980000 ;
    END
  END ifu_axi_rdata[54]
  PIN ifu_axi_rdata[53]
    DIRECTION INPUT ;
    USE SIGNAL ;
    PORT
      LAYER Metal3 ;
        RECT 1691.420000 3598.260000 1691.620000 3598.980000 ;
    END
  END ifu_axi_rdata[53]
  PIN ifu_axi_rdata[52]
    DIRECTION INPUT ;
    USE SIGNAL ;
    PORT
      LAYER Metal3 ;
        RECT 1694.780000 3598.260000 1694.980000 3598.980000 ;
    END
  END ifu_axi_rdata[52]
  PIN ifu_axi_rdata[51]
    DIRECTION INPUT ;
    USE SIGNAL ;
    PORT
      LAYER Metal3 ;
        RECT 1698.140000 3598.260000 1698.340000 3598.980000 ;
    END
  END ifu_axi_rdata[51]
  PIN ifu_axi_rdata[50]
    DIRECTION INPUT ;
    USE SIGNAL ;
    PORT
      LAYER Metal3 ;
        RECT 1701.020000 3598.260000 1701.220000 3598.980000 ;
    END
  END ifu_axi_rdata[50]
  PIN ifu_axi_rdata[49]
    DIRECTION INPUT ;
    USE SIGNAL ;
    PORT
      LAYER Metal3 ;
        RECT 1704.380000 3598.260000 1704.580000 3598.980000 ;
    END
  END ifu_axi_rdata[49]
  PIN ifu_axi_rdata[48]
    DIRECTION INPUT ;
    USE SIGNAL ;
    PORT
      LAYER Metal3 ;
        RECT 1707.740000 3598.260000 1707.940000 3598.980000 ;
    END
  END ifu_axi_rdata[48]
  PIN ifu_axi_rdata[47]
    DIRECTION INPUT ;
    USE SIGNAL ;
    PORT
      LAYER Metal3 ;
        RECT 1711.100000 3598.260000 1711.300000 3598.980000 ;
    END
  END ifu_axi_rdata[47]
  PIN ifu_axi_rdata[46]
    DIRECTION INPUT ;
    USE SIGNAL ;
    PORT
      LAYER Metal3 ;
        RECT 1714.460000 3598.260000 1714.660000 3598.980000 ;
    END
  END ifu_axi_rdata[46]
  PIN ifu_axi_rdata[45]
    DIRECTION INPUT ;
    USE SIGNAL ;
    PORT
      LAYER Metal3 ;
        RECT 1717.340000 3598.260000 1717.540000 3598.980000 ;
    END
  END ifu_axi_rdata[45]
  PIN ifu_axi_rdata[44]
    DIRECTION INPUT ;
    USE SIGNAL ;
    PORT
      LAYER Metal3 ;
        RECT 1720.700000 3598.260000 1720.900000 3598.980000 ;
    END
  END ifu_axi_rdata[44]
  PIN ifu_axi_rdata[43]
    DIRECTION INPUT ;
    USE SIGNAL ;
    PORT
      LAYER Metal3 ;
        RECT 1724.060000 3598.260000 1724.260000 3598.980000 ;
    END
  END ifu_axi_rdata[43]
  PIN ifu_axi_rdata[42]
    DIRECTION INPUT ;
    USE SIGNAL ;
    PORT
      LAYER Metal3 ;
        RECT 1727.420000 3598.260000 1727.620000 3598.980000 ;
    END
  END ifu_axi_rdata[42]
  PIN ifu_axi_rdata[41]
    DIRECTION INPUT ;
    USE SIGNAL ;
    PORT
      LAYER Metal3 ;
        RECT 1730.780000 3598.260000 1730.980000 3598.980000 ;
    END
  END ifu_axi_rdata[41]
  PIN ifu_axi_rdata[40]
    DIRECTION INPUT ;
    USE SIGNAL ;
    PORT
      LAYER Metal3 ;
        RECT 1733.660000 3598.260000 1733.860000 3598.980000 ;
    END
  END ifu_axi_rdata[40]
  PIN ifu_axi_rdata[39]
    DIRECTION INPUT ;
    USE SIGNAL ;
    PORT
      LAYER Metal3 ;
        RECT 1737.020000 3598.260000 1737.220000 3598.980000 ;
    END
  END ifu_axi_rdata[39]
  PIN ifu_axi_rdata[38]
    DIRECTION INPUT ;
    USE SIGNAL ;
    PORT
      LAYER Metal3 ;
        RECT 1740.380000 3598.260000 1740.580000 3598.980000 ;
    END
  END ifu_axi_rdata[38]
  PIN ifu_axi_rdata[37]
    DIRECTION INPUT ;
    USE SIGNAL ;
    PORT
      LAYER Metal3 ;
        RECT 1743.740000 3598.260000 1743.940000 3598.980000 ;
    END
  END ifu_axi_rdata[37]
  PIN ifu_axi_rdata[36]
    DIRECTION INPUT ;
    USE SIGNAL ;
    PORT
      LAYER Metal3 ;
        RECT 1746.620000 3598.260000 1746.820000 3598.980000 ;
    END
  END ifu_axi_rdata[36]
  PIN ifu_axi_rdata[35]
    DIRECTION INPUT ;
    USE SIGNAL ;
    PORT
      LAYER Metal3 ;
        RECT 1749.500000 3598.260000 1749.700000 3598.980000 ;
    END
  END ifu_axi_rdata[35]
  PIN ifu_axi_rdata[34]
    DIRECTION INPUT ;
    USE SIGNAL ;
    PORT
      LAYER Metal3 ;
        RECT 1753.340000 3598.260000 1753.540000 3598.980000 ;
    END
  END ifu_axi_rdata[34]
  PIN ifu_axi_rdata[33]
    DIRECTION INPUT ;
    USE SIGNAL ;
    PORT
      LAYER Metal3 ;
        RECT 1756.700000 3598.260000 1756.900000 3598.980000 ;
    END
  END ifu_axi_rdata[33]
  PIN ifu_axi_rdata[32]
    DIRECTION INPUT ;
    USE SIGNAL ;
    PORT
      LAYER Metal3 ;
        RECT 1760.060000 3598.260000 1760.260000 3598.980000 ;
    END
  END ifu_axi_rdata[32]
  PIN ifu_axi_rdata[31]
    DIRECTION INPUT ;
    USE SIGNAL ;
    PORT
      LAYER Metal3 ;
        RECT 1762.940000 3598.260000 1763.140000 3598.980000 ;
    END
  END ifu_axi_rdata[31]
  PIN ifu_axi_rdata[30]
    DIRECTION INPUT ;
    USE SIGNAL ;
    PORT
      LAYER Metal3 ;
        RECT 1766.300000 3598.260000 1766.500000 3598.980000 ;
    END
  END ifu_axi_rdata[30]
  PIN ifu_axi_rdata[29]
    DIRECTION INPUT ;
    USE SIGNAL ;
    PORT
      LAYER Metal3 ;
        RECT 1769.660000 3598.260000 1769.860000 3598.980000 ;
    END
  END ifu_axi_rdata[29]
  PIN ifu_axi_rdata[28]
    DIRECTION INPUT ;
    USE SIGNAL ;
    PORT
      LAYER Metal3 ;
        RECT 1773.020000 3598.260000 1773.220000 3598.980000 ;
    END
  END ifu_axi_rdata[28]
  PIN ifu_axi_rdata[27]
    DIRECTION INPUT ;
    USE SIGNAL ;
    PORT
      LAYER Metal3 ;
        RECT 1776.380000 3598.260000 1776.580000 3598.980000 ;
    END
  END ifu_axi_rdata[27]
  PIN ifu_axi_rdata[26]
    DIRECTION INPUT ;
    USE SIGNAL ;
    PORT
      LAYER Metal3 ;
        RECT 1779.260000 3598.260000 1779.460000 3598.980000 ;
    END
  END ifu_axi_rdata[26]
  PIN ifu_axi_rdata[25]
    DIRECTION INPUT ;
    USE SIGNAL ;
    PORT
      LAYER Metal3 ;
        RECT 1782.620000 3598.260000 1782.820000 3598.980000 ;
    END
  END ifu_axi_rdata[25]
  PIN ifu_axi_rdata[24]
    DIRECTION INPUT ;
    USE SIGNAL ;
    PORT
      LAYER Metal3 ;
        RECT 1785.980000 3598.260000 1786.180000 3598.980000 ;
    END
  END ifu_axi_rdata[24]
  PIN ifu_axi_rdata[23]
    DIRECTION INPUT ;
    USE SIGNAL ;
    PORT
      LAYER Metal3 ;
        RECT 1789.340000 3598.260000 1789.540000 3598.980000 ;
    END
  END ifu_axi_rdata[23]
  PIN ifu_axi_rdata[22]
    DIRECTION INPUT ;
    USE SIGNAL ;
    PORT
      LAYER Metal3 ;
        RECT 1792.700000 3598.260000 1792.900000 3598.980000 ;
    END
  END ifu_axi_rdata[22]
  PIN ifu_axi_rdata[21]
    DIRECTION INPUT ;
    USE SIGNAL ;
    PORT
      LAYER Metal3 ;
        RECT 1795.580000 3598.260000 1795.780000 3598.980000 ;
    END
  END ifu_axi_rdata[21]
  PIN ifu_axi_rdata[20]
    DIRECTION INPUT ;
    USE SIGNAL ;
    PORT
      LAYER Metal3 ;
        RECT 1798.940000 3598.260000 1799.140000 3598.980000 ;
    END
  END ifu_axi_rdata[20]
  PIN ifu_axi_rdata[19]
    DIRECTION INPUT ;
    USE SIGNAL ;
    PORT
      LAYER Metal3 ;
        RECT 1802.300000 3598.260000 1802.500000 3598.980000 ;
    END
  END ifu_axi_rdata[19]
  PIN ifu_axi_rdata[18]
    DIRECTION INPUT ;
    USE SIGNAL ;
    PORT
      LAYER Metal3 ;
        RECT 1805.660000 3598.260000 1805.860000 3598.980000 ;
    END
  END ifu_axi_rdata[18]
  PIN ifu_axi_rdata[17]
    DIRECTION INPUT ;
    USE SIGNAL ;
    PORT
      LAYER Metal3 ;
        RECT 1808.540000 3598.260000 1808.740000 3598.980000 ;
    END
  END ifu_axi_rdata[17]
  PIN ifu_axi_rdata[16]
    DIRECTION INPUT ;
    USE SIGNAL ;
    PORT
      LAYER Metal3 ;
        RECT 1811.900000 3598.260000 1812.100000 3598.980000 ;
    END
  END ifu_axi_rdata[16]
  PIN ifu_axi_rdata[15]
    DIRECTION INPUT ;
    USE SIGNAL ;
    PORT
      LAYER Metal3 ;
        RECT 1815.260000 3598.260000 1815.460000 3598.980000 ;
    END
  END ifu_axi_rdata[15]
  PIN ifu_axi_rdata[14]
    DIRECTION INPUT ;
    USE SIGNAL ;
    PORT
      LAYER Metal3 ;
        RECT 1818.620000 3598.260000 1818.820000 3598.980000 ;
    END
  END ifu_axi_rdata[14]
  PIN ifu_axi_rdata[13]
    DIRECTION INPUT ;
    USE SIGNAL ;
    PORT
      LAYER Metal3 ;
        RECT 1821.980000 3598.260000 1822.180000 3598.980000 ;
    END
  END ifu_axi_rdata[13]
  PIN ifu_axi_rdata[12]
    DIRECTION INPUT ;
    USE SIGNAL ;
    PORT
      LAYER Metal3 ;
        RECT 1824.860000 3598.260000 1825.060000 3598.980000 ;
    END
  END ifu_axi_rdata[12]
  PIN ifu_axi_rdata[11]
    DIRECTION INPUT ;
    USE SIGNAL ;
    PORT
      LAYER Metal3 ;
        RECT 1828.220000 3598.260000 1828.420000 3598.980000 ;
    END
  END ifu_axi_rdata[11]
  PIN ifu_axi_rdata[10]
    DIRECTION INPUT ;
    USE SIGNAL ;
    PORT
      LAYER Metal3 ;
        RECT 1831.580000 3598.260000 1831.780000 3598.980000 ;
    END
  END ifu_axi_rdata[10]
  PIN ifu_axi_rdata[9]
    DIRECTION INPUT ;
    USE SIGNAL ;
    PORT
      LAYER Metal3 ;
        RECT 1834.940000 3598.260000 1835.140000 3598.980000 ;
    END
  END ifu_axi_rdata[9]
  PIN ifu_axi_rdata[8]
    DIRECTION INPUT ;
    USE SIGNAL ;
    PORT
      LAYER Metal3 ;
        RECT 1838.300000 3598.260000 1838.500000 3598.980000 ;
    END
  END ifu_axi_rdata[8]
  PIN ifu_axi_rdata[7]
    DIRECTION INPUT ;
    USE SIGNAL ;
    PORT
      LAYER Metal3 ;
        RECT 1840.700000 3598.260000 1840.900000 3598.980000 ;
    END
  END ifu_axi_rdata[7]
  PIN ifu_axi_rdata[6]
    DIRECTION INPUT ;
    USE SIGNAL ;
    PORT
      LAYER Metal3 ;
        RECT 1844.540000 3598.260000 1844.740000 3598.980000 ;
    END
  END ifu_axi_rdata[6]
  PIN ifu_axi_rdata[5]
    DIRECTION INPUT ;
    USE SIGNAL ;
    PORT
      LAYER Metal3 ;
        RECT 1847.900000 3598.260000 1848.100000 3598.980000 ;
    END
  END ifu_axi_rdata[5]
  PIN ifu_axi_rdata[4]
    DIRECTION INPUT ;
    USE SIGNAL ;
    PORT
      LAYER Metal3 ;
        RECT 1851.260000 3598.260000 1851.460000 3598.980000 ;
    END
  END ifu_axi_rdata[4]
  PIN ifu_axi_rdata[3]
    DIRECTION INPUT ;
    USE SIGNAL ;
    PORT
      LAYER Metal3 ;
        RECT 1854.140000 3598.260000 1854.340000 3598.980000 ;
    END
  END ifu_axi_rdata[3]
  PIN ifu_axi_rdata[2]
    DIRECTION INPUT ;
    USE SIGNAL ;
    PORT
      LAYER Metal3 ;
        RECT 1857.020000 3598.260000 1857.220000 3598.980000 ;
    END
  END ifu_axi_rdata[2]
  PIN ifu_axi_rdata[1]
    DIRECTION INPUT ;
    USE SIGNAL ;
    PORT
      LAYER Metal3 ;
        RECT 1860.860000 3598.260000 1861.060000 3598.980000 ;
    END
  END ifu_axi_rdata[1]
  PIN ifu_axi_rdata[0]
    DIRECTION INPUT ;
    USE SIGNAL ;
    PORT
      LAYER Metal3 ;
        RECT 1864.220000 3598.260000 1864.420000 3598.980000 ;
    END
  END ifu_axi_rdata[0]
  PIN ifu_axi_rresp[1]
    DIRECTION INPUT ;
    USE SIGNAL ;
    PORT
      LAYER Metal3 ;
        RECT 1867.580000 3598.260000 1867.780000 3598.980000 ;
    END
  END ifu_axi_rresp[1]
  PIN ifu_axi_rresp[0]
    DIRECTION INPUT ;
    USE SIGNAL ;
    PORT
      LAYER Metal3 ;
        RECT 1870.460000 3598.260000 1870.660000 3598.980000 ;
    END
  END ifu_axi_rresp[0]
  PIN ifu_axi_rlast
    DIRECTION INPUT ;
    USE SIGNAL ;
    PORT
      LAYER Metal3 ;
        RECT 1873.820000 3598.260000 1874.020000 3598.980000 ;
    END
  END ifu_axi_rlast
  PIN sb_axi_awvalid
    DIRECTION OUTPUT ;
    USE SIGNAL ;
    PORT
      LAYER Metal3 ;
        RECT 1877.180000 3598.260000 1877.380000 3598.980000 ;
    END
  END sb_axi_awvalid
  PIN sb_axi_awready
    DIRECTION INPUT ;
    USE SIGNAL ;
    PORT
      LAYER Metal3 ;
        RECT 1880.540000 3598.260000 1880.740000 3598.980000 ;
    END
  END sb_axi_awready
  PIN sb_axi_awid[0]
    DIRECTION OUTPUT ;
    USE SIGNAL ;
    PORT
      LAYER Metal3 ;
        RECT 1883.900000 3598.260000 1884.100000 3598.980000 ;
    END
  END sb_axi_awid[0]
  PIN sb_axi_awaddr[31]
    DIRECTION OUTPUT ;
    USE SIGNAL ;
    PORT
      LAYER Metal3 ;
        RECT 1886.780000 3598.260000 1886.980000 3598.980000 ;
    END
  END sb_axi_awaddr[31]
  PIN sb_axi_awaddr[30]
    DIRECTION OUTPUT ;
    USE SIGNAL ;
    PORT
      LAYER Metal3 ;
        RECT 1890.140000 3598.260000 1890.340000 3598.980000 ;
    END
  END sb_axi_awaddr[30]
  PIN sb_axi_awaddr[29]
    DIRECTION OUTPUT ;
    USE SIGNAL ;
    PORT
      LAYER Metal3 ;
        RECT 1893.500000 3598.260000 1893.700000 3598.980000 ;
    END
  END sb_axi_awaddr[29]
  PIN sb_axi_awaddr[28]
    DIRECTION OUTPUT ;
    USE SIGNAL ;
    PORT
      LAYER Metal3 ;
        RECT 1896.860000 3598.260000 1897.060000 3598.980000 ;
    END
  END sb_axi_awaddr[28]
  PIN sb_axi_awaddr[27]
    DIRECTION OUTPUT ;
    USE SIGNAL ;
    PORT
      LAYER Metal3 ;
        RECT 1900.220000 3598.260000 1900.420000 3598.980000 ;
    END
  END sb_axi_awaddr[27]
  PIN sb_axi_awaddr[26]
    DIRECTION OUTPUT ;
    USE SIGNAL ;
    PORT
      LAYER Metal3 ;
        RECT 1903.100000 3598.260000 1903.300000 3598.980000 ;
    END
  END sb_axi_awaddr[26]
  PIN sb_axi_awaddr[25]
    DIRECTION OUTPUT ;
    USE SIGNAL ;
    PORT
      LAYER Metal3 ;
        RECT 1906.460000 3598.260000 1906.660000 3598.980000 ;
    END
  END sb_axi_awaddr[25]
  PIN sb_axi_awaddr[24]
    DIRECTION OUTPUT ;
    USE SIGNAL ;
    PORT
      LAYER Metal3 ;
        RECT 1909.820000 3598.260000 1910.020000 3598.980000 ;
    END
  END sb_axi_awaddr[24]
  PIN sb_axi_awaddr[23]
    DIRECTION OUTPUT ;
    USE SIGNAL ;
    PORT
      LAYER Metal3 ;
        RECT 1913.180000 3598.260000 1913.380000 3598.980000 ;
    END
  END sb_axi_awaddr[23]
  PIN sb_axi_awaddr[22]
    DIRECTION OUTPUT ;
    USE SIGNAL ;
    PORT
      LAYER Metal3 ;
        RECT 1916.540000 3598.260000 1916.740000 3598.980000 ;
    END
  END sb_axi_awaddr[22]
  PIN sb_axi_awaddr[21]
    DIRECTION OUTPUT ;
    USE SIGNAL ;
    PORT
      LAYER Metal3 ;
        RECT 1919.420000 3598.260000 1919.620000 3598.980000 ;
    END
  END sb_axi_awaddr[21]
  PIN sb_axi_awaddr[20]
    DIRECTION OUTPUT ;
    USE SIGNAL ;
    PORT
      LAYER Metal3 ;
        RECT 1922.780000 3598.260000 1922.980000 3598.980000 ;
    END
  END sb_axi_awaddr[20]
  PIN sb_axi_awaddr[19]
    DIRECTION OUTPUT ;
    USE SIGNAL ;
    PORT
      LAYER Metal3 ;
        RECT 1926.140000 3598.260000 1926.340000 3598.980000 ;
    END
  END sb_axi_awaddr[19]
  PIN sb_axi_awaddr[18]
    DIRECTION OUTPUT ;
    USE SIGNAL ;
    PORT
      LAYER Metal3 ;
        RECT 1929.500000 3598.260000 1929.700000 3598.980000 ;
    END
  END sb_axi_awaddr[18]
  PIN sb_axi_awaddr[17]
    DIRECTION OUTPUT ;
    USE SIGNAL ;
    PORT
      LAYER Metal3 ;
        RECT 1932.380000 3598.260000 1932.580000 3598.980000 ;
    END
  END sb_axi_awaddr[17]
  PIN sb_axi_awaddr[16]
    DIRECTION OUTPUT ;
    USE SIGNAL ;
    PORT
      LAYER Metal3 ;
        RECT 1935.740000 3598.260000 1935.940000 3598.980000 ;
    END
  END sb_axi_awaddr[16]
  PIN sb_axi_awaddr[15]
    DIRECTION OUTPUT ;
    USE SIGNAL ;
    PORT
      LAYER Metal3 ;
        RECT 1939.100000 3598.260000 1939.300000 3598.980000 ;
    END
  END sb_axi_awaddr[15]
  PIN sb_axi_awaddr[14]
    DIRECTION OUTPUT ;
    USE SIGNAL ;
    PORT
      LAYER Metal3 ;
        RECT 1942.460000 3598.260000 1942.660000 3598.980000 ;
    END
  END sb_axi_awaddr[14]
  PIN sb_axi_awaddr[13]
    DIRECTION OUTPUT ;
    USE SIGNAL ;
    PORT
      LAYER Metal3 ;
        RECT 1945.820000 3598.260000 1946.020000 3598.980000 ;
    END
  END sb_axi_awaddr[13]
  PIN sb_axi_awaddr[12]
    DIRECTION OUTPUT ;
    USE SIGNAL ;
    PORT
      LAYER Metal3 ;
        RECT 1948.700000 3598.260000 1948.900000 3598.980000 ;
    END
  END sb_axi_awaddr[12]
  PIN sb_axi_awaddr[11]
    DIRECTION OUTPUT ;
    USE SIGNAL ;
    PORT
      LAYER Metal3 ;
        RECT 1952.060000 3598.260000 1952.260000 3598.980000 ;
    END
  END sb_axi_awaddr[11]
  PIN sb_axi_awaddr[10]
    DIRECTION OUTPUT ;
    USE SIGNAL ;
    PORT
      LAYER Metal3 ;
        RECT 1955.420000 3598.260000 1955.620000 3598.980000 ;
    END
  END sb_axi_awaddr[10]
  PIN sb_axi_awaddr[9]
    DIRECTION OUTPUT ;
    USE SIGNAL ;
    PORT
      LAYER Metal3 ;
        RECT 1958.780000 3598.260000 1958.980000 3598.980000 ;
    END
  END sb_axi_awaddr[9]
  PIN sb_axi_awaddr[8]
    DIRECTION OUTPUT ;
    USE SIGNAL ;
    PORT
      LAYER Metal3 ;
        RECT 1962.140000 3598.260000 1962.340000 3598.980000 ;
    END
  END sb_axi_awaddr[8]
  PIN sb_axi_awaddr[7]
    DIRECTION OUTPUT ;
    USE SIGNAL ;
    PORT
      LAYER Metal3 ;
        RECT 1965.020000 3598.260000 1965.220000 3598.980000 ;
    END
  END sb_axi_awaddr[7]
  PIN sb_axi_awaddr[6]
    DIRECTION OUTPUT ;
    USE SIGNAL ;
    PORT
      LAYER Metal3 ;
        RECT 1968.380000 3598.260000 1968.580000 3598.980000 ;
    END
  END sb_axi_awaddr[6]
  PIN sb_axi_awaddr[5]
    DIRECTION OUTPUT ;
    USE SIGNAL ;
    PORT
      LAYER Metal3 ;
        RECT 1971.740000 3598.260000 1971.940000 3598.980000 ;
    END
  END sb_axi_awaddr[5]
  PIN sb_axi_awaddr[4]
    DIRECTION OUTPUT ;
    USE SIGNAL ;
    PORT
      LAYER Metal3 ;
        RECT 1975.100000 3598.260000 1975.300000 3598.980000 ;
    END
  END sb_axi_awaddr[4]
  PIN sb_axi_awaddr[3]
    DIRECTION OUTPUT ;
    USE SIGNAL ;
    PORT
      LAYER Metal3 ;
        RECT 1978.460000 3598.260000 1978.660000 3598.980000 ;
    END
  END sb_axi_awaddr[3]
  PIN sb_axi_awaddr[2]
    DIRECTION OUTPUT ;
    USE SIGNAL ;
    PORT
      LAYER Metal3 ;
        RECT 1981.340000 3598.260000 1981.540000 3598.980000 ;
    END
  END sb_axi_awaddr[2]
  PIN sb_axi_awaddr[1]
    DIRECTION OUTPUT ;
    USE SIGNAL ;
    PORT
      LAYER Metal3 ;
        RECT 1984.700000 3598.260000 1984.900000 3598.980000 ;
    END
  END sb_axi_awaddr[1]
  PIN sb_axi_awaddr[0]
    DIRECTION OUTPUT ;
    USE SIGNAL ;
    PORT
      LAYER Metal3 ;
        RECT 1988.060000 3598.260000 1988.260000 3598.980000 ;
    END
  END sb_axi_awaddr[0]
  PIN sb_axi_awregion[3]
    DIRECTION OUTPUT ;
    USE SIGNAL ;
    PORT
      LAYER Metal3 ;
        RECT 1991.420000 3598.260000 1991.620000 3598.980000 ;
    END
  END sb_axi_awregion[3]
  PIN sb_axi_awregion[2]
    DIRECTION OUTPUT ;
    USE SIGNAL ;
    PORT
      LAYER Metal3 ;
        RECT 1994.300000 3598.260000 1994.500000 3598.980000 ;
    END
  END sb_axi_awregion[2]
  PIN sb_axi_awregion[1]
    DIRECTION OUTPUT ;
    USE SIGNAL ;
    PORT
      LAYER Metal3 ;
        RECT 1997.660000 3598.260000 1997.860000 3598.980000 ;
    END
  END sb_axi_awregion[1]
  PIN sb_axi_awregion[0]
    DIRECTION OUTPUT ;
    USE SIGNAL ;
    PORT
      LAYER Metal3 ;
        RECT 2001.020000 3598.260000 2001.220000 3598.980000 ;
    END
  END sb_axi_awregion[0]
  PIN sb_axi_awlen[7]
    DIRECTION OUTPUT ;
    USE SIGNAL ;
    PORT
      LAYER Metal3 ;
        RECT 2004.380000 3598.260000 2004.580000 3598.980000 ;
    END
  END sb_axi_awlen[7]
  PIN sb_axi_awlen[6]
    DIRECTION OUTPUT ;
    USE SIGNAL ;
    PORT
      LAYER Metal3 ;
        RECT 2007.740000 3598.260000 2007.940000 3598.980000 ;
    END
  END sb_axi_awlen[6]
  PIN sb_axi_awlen[5]
    DIRECTION OUTPUT ;
    USE SIGNAL ;
    PORT
      LAYER Metal3 ;
        RECT 2010.620000 3598.260000 2010.820000 3598.980000 ;
    END
  END sb_axi_awlen[5]
  PIN sb_axi_awlen[4]
    DIRECTION OUTPUT ;
    USE SIGNAL ;
    PORT
      LAYER Metal3 ;
        RECT 2013.980000 3598.260000 2014.180000 3598.980000 ;
    END
  END sb_axi_awlen[4]
  PIN sb_axi_awlen[3]
    DIRECTION OUTPUT ;
    USE SIGNAL ;
    PORT
      LAYER Metal3 ;
        RECT 2017.340000 3598.260000 2017.540000 3598.980000 ;
    END
  END sb_axi_awlen[3]
  PIN sb_axi_awlen[2]
    DIRECTION OUTPUT ;
    USE SIGNAL ;
    PORT
      LAYER Metal3 ;
        RECT 2020.700000 3598.260000 2020.900000 3598.980000 ;
    END
  END sb_axi_awlen[2]
  PIN sb_axi_awlen[1]
    DIRECTION OUTPUT ;
    USE SIGNAL ;
    PORT
      LAYER Metal3 ;
        RECT 2024.060000 3598.260000 2024.260000 3598.980000 ;
    END
  END sb_axi_awlen[1]
  PIN sb_axi_awlen[0]
    DIRECTION OUTPUT ;
    USE SIGNAL ;
    PORT
      LAYER Metal3 ;
        RECT 2026.940000 3598.260000 2027.140000 3598.980000 ;
    END
  END sb_axi_awlen[0]
  PIN sb_axi_awsize[2]
    DIRECTION OUTPUT ;
    USE SIGNAL ;
    PORT
      LAYER Metal3 ;
        RECT 2030.300000 3598.260000 2030.500000 3598.980000 ;
    END
  END sb_axi_awsize[2]
  PIN sb_axi_awsize[1]
    DIRECTION OUTPUT ;
    USE SIGNAL ;
    PORT
      LAYER Metal3 ;
        RECT 2033.660000 3598.260000 2033.860000 3598.980000 ;
    END
  END sb_axi_awsize[1]
  PIN sb_axi_awsize[0]
    DIRECTION OUTPUT ;
    USE SIGNAL ;
    PORT
      LAYER Metal3 ;
        RECT 2037.020000 3598.260000 2037.220000 3598.980000 ;
    END
  END sb_axi_awsize[0]
  PIN sb_axi_awburst[1]
    DIRECTION OUTPUT ;
    USE SIGNAL ;
    PORT
      LAYER Metal3 ;
        RECT 2040.380000 3598.260000 2040.580000 3598.980000 ;
    END
  END sb_axi_awburst[1]
  PIN sb_axi_awburst[0]
    DIRECTION OUTPUT ;
    USE SIGNAL ;
    PORT
      LAYER Metal3 ;
        RECT 2043.260000 3598.260000 2043.460000 3598.980000 ;
    END
  END sb_axi_awburst[0]
  PIN sb_axi_awlock
    DIRECTION OUTPUT ;
    USE SIGNAL ;
    PORT
      LAYER Metal3 ;
        RECT 2046.620000 3598.260000 2046.820000 3598.980000 ;
    END
  END sb_axi_awlock
  PIN sb_axi_awcache[3]
    DIRECTION OUTPUT ;
    USE SIGNAL ;
    PORT
      LAYER Metal3 ;
        RECT 2049.980000 3598.260000 2050.180000 3598.980000 ;
    END
  END sb_axi_awcache[3]
  PIN sb_axi_awcache[2]
    DIRECTION OUTPUT ;
    USE SIGNAL ;
    PORT
      LAYER Metal3 ;
        RECT 2053.340000 3598.260000 2053.540000 3598.980000 ;
    END
  END sb_axi_awcache[2]
  PIN sb_axi_awcache[1]
    DIRECTION OUTPUT ;
    USE SIGNAL ;
    PORT
      LAYER Metal3 ;
        RECT 2056.220000 3598.260000 2056.420000 3598.980000 ;
    END
  END sb_axi_awcache[1]
  PIN sb_axi_awcache[0]
    DIRECTION OUTPUT ;
    USE SIGNAL ;
    PORT
      LAYER Metal3 ;
        RECT 2059.580000 3598.260000 2059.780000 3598.980000 ;
    END
  END sb_axi_awcache[0]
  PIN sb_axi_awprot[2]
    DIRECTION OUTPUT ;
    USE SIGNAL ;
    PORT
      LAYER Metal3 ;
        RECT 2062.940000 3598.260000 2063.140000 3598.980000 ;
    END
  END sb_axi_awprot[2]
  PIN sb_axi_awprot[1]
    DIRECTION OUTPUT ;
    USE SIGNAL ;
    PORT
      LAYER Metal3 ;
        RECT 2066.300000 3598.260000 2066.500000 3598.980000 ;
    END
  END sb_axi_awprot[1]
  PIN sb_axi_awprot[0]
    DIRECTION OUTPUT ;
    USE SIGNAL ;
    PORT
      LAYER Metal3 ;
        RECT 2069.660000 3598.260000 2069.860000 3598.980000 ;
    END
  END sb_axi_awprot[0]
  PIN sb_axi_awqos[3]
    DIRECTION OUTPUT ;
    USE SIGNAL ;
    PORT
      LAYER Metal3 ;
        RECT 2072.540000 3598.260000 2072.740000 3598.980000 ;
    END
  END sb_axi_awqos[3]
  PIN sb_axi_awqos[2]
    DIRECTION OUTPUT ;
    USE SIGNAL ;
    PORT
      LAYER Metal3 ;
        RECT 2075.900000 3598.260000 2076.100000 3598.980000 ;
    END
  END sb_axi_awqos[2]
  PIN sb_axi_awqos[1]
    DIRECTION OUTPUT ;
    USE SIGNAL ;
    PORT
      LAYER Metal3 ;
        RECT 2079.260000 3598.260000 2079.460000 3598.980000 ;
    END
  END sb_axi_awqos[1]
  PIN sb_axi_awqos[0]
    DIRECTION OUTPUT ;
    USE SIGNAL ;
    PORT
      LAYER Metal3 ;
        RECT 2082.620000 3598.260000 2082.820000 3598.980000 ;
    END
  END sb_axi_awqos[0]
  PIN sb_axi_wvalid
    DIRECTION OUTPUT ;
    USE SIGNAL ;
    PORT
      LAYER Metal3 ;
        RECT 2085.980000 3598.260000 2086.180000 3598.980000 ;
    END
  END sb_axi_wvalid
  PIN sb_axi_wready
    DIRECTION INPUT ;
    USE SIGNAL ;
    PORT
      LAYER Metal3 ;
        RECT 2088.860000 3598.260000 2089.060000 3598.980000 ;
    END
  END sb_axi_wready
  PIN sb_axi_wdata[63]
    DIRECTION OUTPUT ;
    USE SIGNAL ;
    PORT
      LAYER Metal3 ;
        RECT 2092.220000 3598.260000 2092.420000 3598.980000 ;
    END
  END sb_axi_wdata[63]
  PIN sb_axi_wdata[62]
    DIRECTION OUTPUT ;
    USE SIGNAL ;
    PORT
      LAYER Metal3 ;
        RECT 2095.580000 3598.260000 2095.780000 3598.980000 ;
    END
  END sb_axi_wdata[62]
  PIN sb_axi_wdata[61]
    DIRECTION OUTPUT ;
    USE SIGNAL ;
    PORT
      LAYER Metal3 ;
        RECT 2098.940000 3598.260000 2099.140000 3598.980000 ;
    END
  END sb_axi_wdata[61]
  PIN sb_axi_wdata[60]
    DIRECTION OUTPUT ;
    USE SIGNAL ;
    PORT
      LAYER Metal3 ;
        RECT 2101.820000 3598.260000 2102.020000 3598.980000 ;
    END
  END sb_axi_wdata[60]
  PIN sb_axi_wdata[59]
    DIRECTION OUTPUT ;
    USE SIGNAL ;
    PORT
      LAYER Metal3 ;
        RECT 2105.180000 3598.260000 2105.380000 3598.980000 ;
    END
  END sb_axi_wdata[59]
  PIN sb_axi_wdata[58]
    DIRECTION OUTPUT ;
    USE SIGNAL ;
    PORT
      LAYER Metal3 ;
        RECT 2108.540000 3598.260000 2108.740000 3598.980000 ;
    END
  END sb_axi_wdata[58]
  PIN sb_axi_wdata[57]
    DIRECTION OUTPUT ;
    USE SIGNAL ;
    PORT
      LAYER Metal3 ;
        RECT 2111.900000 3598.260000 2112.100000 3598.980000 ;
    END
  END sb_axi_wdata[57]
  PIN sb_axi_wdata[56]
    DIRECTION OUTPUT ;
    USE SIGNAL ;
    PORT
      LAYER Metal3 ;
        RECT 2115.260000 3598.260000 2115.460000 3598.980000 ;
    END
  END sb_axi_wdata[56]
  PIN sb_axi_wdata[55]
    DIRECTION OUTPUT ;
    USE SIGNAL ;
    PORT
      LAYER Metal3 ;
        RECT 2118.140000 3598.260000 2118.340000 3598.980000 ;
    END
  END sb_axi_wdata[55]
  PIN sb_axi_wdata[54]
    DIRECTION OUTPUT ;
    USE SIGNAL ;
    PORT
      LAYER Metal3 ;
        RECT 2121.500000 3598.260000 2121.700000 3598.980000 ;
    END
  END sb_axi_wdata[54]
  PIN sb_axi_wdata[53]
    DIRECTION OUTPUT ;
    USE SIGNAL ;
    PORT
      LAYER Metal3 ;
        RECT 2124.860000 3598.260000 2125.060000 3598.980000 ;
    END
  END sb_axi_wdata[53]
  PIN sb_axi_wdata[52]
    DIRECTION OUTPUT ;
    USE SIGNAL ;
    PORT
      LAYER Metal3 ;
        RECT 2128.220000 3598.260000 2128.420000 3598.980000 ;
    END
  END sb_axi_wdata[52]
  PIN sb_axi_wdata[51]
    DIRECTION OUTPUT ;
    USE SIGNAL ;
    PORT
      LAYER Metal3 ;
        RECT 2131.580000 3598.260000 2131.780000 3598.980000 ;
    END
  END sb_axi_wdata[51]
  PIN sb_axi_wdata[50]
    DIRECTION OUTPUT ;
    USE SIGNAL ;
    PORT
      LAYER Metal3 ;
        RECT 2134.460000 3598.260000 2134.660000 3598.980000 ;
    END
  END sb_axi_wdata[50]
  PIN sb_axi_wdata[49]
    DIRECTION OUTPUT ;
    USE SIGNAL ;
    PORT
      LAYER Metal3 ;
        RECT 2137.820000 3598.260000 2138.020000 3598.980000 ;
    END
  END sb_axi_wdata[49]
  PIN sb_axi_wdata[48]
    DIRECTION OUTPUT ;
    USE SIGNAL ;
    PORT
      LAYER Metal3 ;
        RECT 2141.180000 3598.260000 2141.380000 3598.980000 ;
    END
  END sb_axi_wdata[48]
  PIN sb_axi_wdata[47]
    DIRECTION OUTPUT ;
    USE SIGNAL ;
    PORT
      LAYER Metal3 ;
        RECT 2144.540000 3598.260000 2144.740000 3598.980000 ;
    END
  END sb_axi_wdata[47]
  PIN sb_axi_wdata[46]
    DIRECTION OUTPUT ;
    USE SIGNAL ;
    PORT
      LAYER Metal3 ;
        RECT 2147.900000 3598.260000 2148.100000 3598.980000 ;
    END
  END sb_axi_wdata[46]
  PIN sb_axi_wdata[45]
    DIRECTION OUTPUT ;
    USE SIGNAL ;
    PORT
      LAYER Metal3 ;
        RECT 2150.780000 3598.260000 2150.980000 3598.980000 ;
    END
  END sb_axi_wdata[45]
  PIN sb_axi_wdata[44]
    DIRECTION OUTPUT ;
    USE SIGNAL ;
    PORT
      LAYER Metal3 ;
        RECT 2154.140000 3598.260000 2154.340000 3598.980000 ;
    END
  END sb_axi_wdata[44]
  PIN sb_axi_wdata[43]
    DIRECTION OUTPUT ;
    USE SIGNAL ;
    PORT
      LAYER Metal3 ;
        RECT 2157.500000 3598.260000 2157.700000 3598.980000 ;
    END
  END sb_axi_wdata[43]
  PIN sb_axi_wdata[42]
    DIRECTION OUTPUT ;
    USE SIGNAL ;
    PORT
      LAYER Metal3 ;
        RECT 2160.860000 3598.260000 2161.060000 3598.980000 ;
    END
  END sb_axi_wdata[42]
  PIN sb_axi_wdata[41]
    DIRECTION OUTPUT ;
    USE SIGNAL ;
    PORT
      LAYER Metal3 ;
        RECT 2163.740000 3598.260000 2163.940000 3598.980000 ;
    END
  END sb_axi_wdata[41]
  PIN sb_axi_wdata[40]
    DIRECTION OUTPUT ;
    USE SIGNAL ;
    PORT
      LAYER Metal3 ;
        RECT 2167.100000 3598.260000 2167.300000 3598.980000 ;
    END
  END sb_axi_wdata[40]
  PIN sb_axi_wdata[39]
    DIRECTION OUTPUT ;
    USE SIGNAL ;
    PORT
      LAYER Metal3 ;
        RECT 2170.460000 3598.260000 2170.660000 3598.980000 ;
    END
  END sb_axi_wdata[39]
  PIN sb_axi_wdata[38]
    DIRECTION OUTPUT ;
    USE SIGNAL ;
    PORT
      LAYER Metal3 ;
        RECT 2173.820000 3598.260000 2174.020000 3598.980000 ;
    END
  END sb_axi_wdata[38]
  PIN sb_axi_wdata[37]
    DIRECTION OUTPUT ;
    USE SIGNAL ;
    PORT
      LAYER Metal3 ;
        RECT 2177.180000 3598.260000 2177.380000 3598.980000 ;
    END
  END sb_axi_wdata[37]
  PIN sb_axi_wdata[36]
    DIRECTION OUTPUT ;
    USE SIGNAL ;
    PORT
      LAYER Metal3 ;
        RECT 2180.060000 3598.260000 2180.260000 3598.980000 ;
    END
  END sb_axi_wdata[36]
  PIN sb_axi_wdata[35]
    DIRECTION OUTPUT ;
    USE SIGNAL ;
    PORT
      LAYER Metal3 ;
        RECT 2183.420000 3598.260000 2183.620000 3598.980000 ;
    END
  END sb_axi_wdata[35]
  PIN sb_axi_wdata[34]
    DIRECTION OUTPUT ;
    USE SIGNAL ;
    PORT
      LAYER Metal3 ;
        RECT 2186.780000 3598.260000 2186.980000 3598.980000 ;
    END
  END sb_axi_wdata[34]
  PIN sb_axi_wdata[33]
    DIRECTION OUTPUT ;
    USE SIGNAL ;
    PORT
      LAYER Metal3 ;
        RECT 2190.140000 3598.260000 2190.340000 3598.980000 ;
    END
  END sb_axi_wdata[33]
  PIN sb_axi_wdata[32]
    DIRECTION OUTPUT ;
    USE SIGNAL ;
    PORT
      LAYER Metal3 ;
        RECT 2193.500000 3598.260000 2193.700000 3598.980000 ;
    END
  END sb_axi_wdata[32]
  PIN sb_axi_wdata[31]
    DIRECTION OUTPUT ;
    USE SIGNAL ;
    PORT
      LAYER Metal3 ;
        RECT 2196.380000 3598.260000 2196.580000 3598.980000 ;
    END
  END sb_axi_wdata[31]
  PIN sb_axi_wdata[30]
    DIRECTION OUTPUT ;
    USE SIGNAL ;
    PORT
      LAYER Metal3 ;
        RECT 2199.740000 3598.260000 2199.940000 3598.980000 ;
    END
  END sb_axi_wdata[30]
  PIN sb_axi_wdata[29]
    DIRECTION OUTPUT ;
    USE SIGNAL ;
    PORT
      LAYER Metal3 ;
        RECT 2203.100000 3598.260000 2203.300000 3598.980000 ;
    END
  END sb_axi_wdata[29]
  PIN sb_axi_wdata[28]
    DIRECTION OUTPUT ;
    USE SIGNAL ;
    PORT
      LAYER Metal3 ;
        RECT 2206.460000 3598.260000 2206.660000 3598.980000 ;
    END
  END sb_axi_wdata[28]
  PIN sb_axi_wdata[27]
    DIRECTION OUTPUT ;
    USE SIGNAL ;
    PORT
      LAYER Metal3 ;
        RECT 2209.820000 3598.260000 2210.020000 3598.980000 ;
    END
  END sb_axi_wdata[27]
  PIN sb_axi_wdata[26]
    DIRECTION OUTPUT ;
    USE SIGNAL ;
    PORT
      LAYER Metal3 ;
        RECT 2212.700000 3598.260000 2212.900000 3598.980000 ;
    END
  END sb_axi_wdata[26]
  PIN sb_axi_wdata[25]
    DIRECTION OUTPUT ;
    USE SIGNAL ;
    PORT
      LAYER Metal3 ;
        RECT 2216.060000 3598.260000 2216.260000 3598.980000 ;
    END
  END sb_axi_wdata[25]
  PIN sb_axi_wdata[24]
    DIRECTION OUTPUT ;
    USE SIGNAL ;
    PORT
      LAYER Metal3 ;
        RECT 2219.420000 3598.260000 2219.620000 3598.980000 ;
    END
  END sb_axi_wdata[24]
  PIN sb_axi_wdata[23]
    DIRECTION OUTPUT ;
    USE SIGNAL ;
    PORT
      LAYER Metal3 ;
        RECT 2222.780000 3598.260000 2222.980000 3598.980000 ;
    END
  END sb_axi_wdata[23]
  PIN sb_axi_wdata[22]
    DIRECTION OUTPUT ;
    USE SIGNAL ;
    PORT
      LAYER Metal3 ;
        RECT 2225.660000 3598.260000 2225.860000 3598.980000 ;
    END
  END sb_axi_wdata[22]
  PIN sb_axi_wdata[21]
    DIRECTION OUTPUT ;
    USE SIGNAL ;
    PORT
      LAYER Metal3 ;
        RECT 2229.020000 3598.260000 2229.220000 3598.980000 ;
    END
  END sb_axi_wdata[21]
  PIN sb_axi_wdata[20]
    DIRECTION OUTPUT ;
    USE SIGNAL ;
    PORT
      LAYER Metal3 ;
        RECT 2232.380000 3598.260000 2232.580000 3598.980000 ;
    END
  END sb_axi_wdata[20]
  PIN sb_axi_wdata[19]
    DIRECTION OUTPUT ;
    USE SIGNAL ;
    PORT
      LAYER Metal3 ;
        RECT 2235.740000 3598.260000 2235.940000 3598.980000 ;
    END
  END sb_axi_wdata[19]
  PIN sb_axi_wdata[18]
    DIRECTION OUTPUT ;
    USE SIGNAL ;
    PORT
      LAYER Metal3 ;
        RECT 2239.100000 3598.260000 2239.300000 3598.980000 ;
    END
  END sb_axi_wdata[18]
  PIN sb_axi_wdata[17]
    DIRECTION OUTPUT ;
    USE SIGNAL ;
    PORT
      LAYER Metal3 ;
        RECT 2241.980000 3598.260000 2242.180000 3598.980000 ;
    END
  END sb_axi_wdata[17]
  PIN sb_axi_wdata[16]
    DIRECTION OUTPUT ;
    USE SIGNAL ;
    PORT
      LAYER Metal3 ;
        RECT 2245.340000 3598.260000 2245.540000 3598.980000 ;
    END
  END sb_axi_wdata[16]
  PIN sb_axi_wdata[15]
    DIRECTION OUTPUT ;
    USE SIGNAL ;
    PORT
      LAYER Metal3 ;
        RECT 2248.700000 3598.260000 2248.900000 3598.980000 ;
    END
  END sb_axi_wdata[15]
  PIN sb_axi_wdata[14]
    DIRECTION OUTPUT ;
    USE SIGNAL ;
    PORT
      LAYER Metal3 ;
        RECT 2252.060000 3598.260000 2252.260000 3598.980000 ;
    END
  END sb_axi_wdata[14]
  PIN sb_axi_wdata[13]
    DIRECTION OUTPUT ;
    USE SIGNAL ;
    PORT
      LAYER Metal3 ;
        RECT 2255.420000 3598.260000 2255.620000 3598.980000 ;
    END
  END sb_axi_wdata[13]
  PIN sb_axi_wdata[12]
    DIRECTION OUTPUT ;
    USE SIGNAL ;
    PORT
      LAYER Metal3 ;
        RECT 2258.300000 3598.260000 2258.500000 3598.980000 ;
    END
  END sb_axi_wdata[12]
  PIN sb_axi_wdata[11]
    DIRECTION OUTPUT ;
    USE SIGNAL ;
    PORT
      LAYER Metal3 ;
        RECT 2261.660000 3598.260000 2261.860000 3598.980000 ;
    END
  END sb_axi_wdata[11]
  PIN sb_axi_wdata[10]
    DIRECTION OUTPUT ;
    USE SIGNAL ;
    PORT
      LAYER Metal3 ;
        RECT 2265.020000 3598.260000 2265.220000 3598.980000 ;
    END
  END sb_axi_wdata[10]
  PIN sb_axi_wdata[9]
    DIRECTION OUTPUT ;
    USE SIGNAL ;
    PORT
      LAYER Metal3 ;
        RECT 2268.380000 3598.260000 2268.580000 3598.980000 ;
    END
  END sb_axi_wdata[9]
  PIN sb_axi_wdata[8]
    DIRECTION OUTPUT ;
    USE SIGNAL ;
    PORT
      LAYER Metal3 ;
        RECT 2271.740000 3598.260000 2271.940000 3598.980000 ;
    END
  END sb_axi_wdata[8]
  PIN sb_axi_wdata[7]
    DIRECTION OUTPUT ;
    USE SIGNAL ;
    PORT
      LAYER Metal3 ;
        RECT 2274.620000 3598.260000 2274.820000 3598.980000 ;
    END
  END sb_axi_wdata[7]
  PIN sb_axi_wdata[6]
    DIRECTION OUTPUT ;
    USE SIGNAL ;
    PORT
      LAYER Metal3 ;
        RECT 2277.980000 3598.260000 2278.180000 3598.980000 ;
    END
  END sb_axi_wdata[6]
  PIN sb_axi_wdata[5]
    DIRECTION OUTPUT ;
    USE SIGNAL ;
    PORT
      LAYER Metal3 ;
        RECT 2281.340000 3598.260000 2281.540000 3598.980000 ;
    END
  END sb_axi_wdata[5]
  PIN sb_axi_wdata[4]
    DIRECTION OUTPUT ;
    USE SIGNAL ;
    PORT
      LAYER Metal3 ;
        RECT 2284.700000 3598.260000 2284.900000 3598.980000 ;
    END
  END sb_axi_wdata[4]
  PIN sb_axi_wdata[3]
    DIRECTION OUTPUT ;
    USE SIGNAL ;
    PORT
      LAYER Metal3 ;
        RECT 2287.580000 3598.260000 2287.780000 3598.980000 ;
    END
  END sb_axi_wdata[3]
  PIN sb_axi_wdata[2]
    DIRECTION OUTPUT ;
    USE SIGNAL ;
    PORT
      LAYER Metal3 ;
        RECT 2290.940000 3598.260000 2291.140000 3598.980000 ;
    END
  END sb_axi_wdata[2]
  PIN sb_axi_wdata[1]
    DIRECTION OUTPUT ;
    USE SIGNAL ;
    PORT
      LAYER Metal3 ;
        RECT 2294.300000 3598.260000 2294.500000 3598.980000 ;
    END
  END sb_axi_wdata[1]
  PIN sb_axi_wdata[0]
    DIRECTION OUTPUT ;
    USE SIGNAL ;
    PORT
      LAYER Metal3 ;
        RECT 2297.660000 3598.260000 2297.860000 3598.980000 ;
    END
  END sb_axi_wdata[0]
  PIN sb_axi_wstrb[7]
    DIRECTION OUTPUT ;
    USE SIGNAL ;
    PORT
      LAYER Metal3 ;
        RECT 2301.020000 3598.260000 2301.220000 3598.980000 ;
    END
  END sb_axi_wstrb[7]
  PIN sb_axi_wstrb[6]
    DIRECTION OUTPUT ;
    USE SIGNAL ;
    PORT
      LAYER Metal3 ;
        RECT 2303.900000 3598.260000 2304.100000 3598.980000 ;
    END
  END sb_axi_wstrb[6]
  PIN sb_axi_wstrb[5]
    DIRECTION OUTPUT ;
    USE SIGNAL ;
    PORT
      LAYER Metal3 ;
        RECT 2307.260000 3598.260000 2307.460000 3598.980000 ;
    END
  END sb_axi_wstrb[5]
  PIN sb_axi_wstrb[4]
    DIRECTION OUTPUT ;
    USE SIGNAL ;
    PORT
      LAYER Metal3 ;
        RECT 2310.620000 3598.260000 2310.820000 3598.980000 ;
    END
  END sb_axi_wstrb[4]
  PIN sb_axi_wstrb[3]
    DIRECTION OUTPUT ;
    USE SIGNAL ;
    PORT
      LAYER Metal3 ;
        RECT 2313.980000 3598.260000 2314.180000 3598.980000 ;
    END
  END sb_axi_wstrb[3]
  PIN sb_axi_wstrb[2]
    DIRECTION OUTPUT ;
    USE SIGNAL ;
    PORT
      LAYER Metal3 ;
        RECT 2317.340000 3598.260000 2317.540000 3598.980000 ;
    END
  END sb_axi_wstrb[2]
  PIN sb_axi_wstrb[1]
    DIRECTION OUTPUT ;
    USE SIGNAL ;
    PORT
      LAYER Metal3 ;
        RECT 2320.220000 3598.260000 2320.420000 3598.980000 ;
    END
  END sb_axi_wstrb[1]
  PIN sb_axi_wstrb[0]
    DIRECTION OUTPUT ;
    USE SIGNAL ;
    PORT
      LAYER Metal3 ;
        RECT 2323.580000 3598.260000 2323.780000 3598.980000 ;
    END
  END sb_axi_wstrb[0]
  PIN sb_axi_wlast
    DIRECTION OUTPUT ;
    USE SIGNAL ;
    PORT
      LAYER Metal3 ;
        RECT 2326.940000 3598.260000 2327.140000 3598.980000 ;
    END
  END sb_axi_wlast
  PIN sb_axi_bvalid
    DIRECTION INPUT ;
    USE SIGNAL ;
    PORT
      LAYER Metal3 ;
        RECT 2330.300000 3598.260000 2330.500000 3598.980000 ;
    END
  END sb_axi_bvalid
  PIN sb_axi_bready
    DIRECTION OUTPUT ;
    USE SIGNAL ;
    PORT
      LAYER Metal3 ;
        RECT 2333.660000 3598.260000 2333.860000 3598.980000 ;
    END
  END sb_axi_bready
  PIN sb_axi_bresp[1]
    DIRECTION INPUT ;
    USE SIGNAL ;
    PORT
      LAYER Metal3 ;
        RECT 2336.540000 3598.260000 2336.740000 3598.980000 ;
    END
  END sb_axi_bresp[1]
  PIN sb_axi_bresp[0]
    DIRECTION INPUT ;
    USE SIGNAL ;
    PORT
      LAYER Metal3 ;
        RECT 2339.900000 3598.260000 2340.100000 3598.980000 ;
    END
  END sb_axi_bresp[0]
  PIN sb_axi_bid[0]
    DIRECTION INPUT ;
    USE SIGNAL ;
    PORT
      LAYER Metal3 ;
        RECT 2343.260000 3598.260000 2343.460000 3598.980000 ;
    END
  END sb_axi_bid[0]
  PIN sb_axi_arvalid
    DIRECTION OUTPUT ;
    USE SIGNAL ;
    PORT
      LAYER Metal3 ;
        RECT 2346.620000 3598.260000 2346.820000 3598.980000 ;
    END
  END sb_axi_arvalid
  PIN sb_axi_arready
    DIRECTION INPUT ;
    USE SIGNAL ;
    PORT
      LAYER Metal3 ;
        RECT 2349.500000 3598.260000 2349.700000 3598.980000 ;
    END
  END sb_axi_arready
  PIN sb_axi_arid[0]
    DIRECTION OUTPUT ;
    USE SIGNAL ;
    PORT
      LAYER Metal3 ;
        RECT 2352.860000 3598.260000 2353.060000 3598.980000 ;
    END
  END sb_axi_arid[0]
  PIN sb_axi_araddr[31]
    DIRECTION OUTPUT ;
    USE SIGNAL ;
    PORT
      LAYER Metal3 ;
        RECT 2356.220000 3598.260000 2356.420000 3598.980000 ;
    END
  END sb_axi_araddr[31]
  PIN sb_axi_araddr[30]
    DIRECTION OUTPUT ;
    USE SIGNAL ;
    PORT
      LAYER Metal3 ;
        RECT 2359.580000 3598.260000 2359.780000 3598.980000 ;
    END
  END sb_axi_araddr[30]
  PIN sb_axi_araddr[29]
    DIRECTION OUTPUT ;
    USE SIGNAL ;
    PORT
      LAYER Metal3 ;
        RECT 2362.940000 3598.260000 2363.140000 3598.980000 ;
    END
  END sb_axi_araddr[29]
  PIN sb_axi_araddr[28]
    DIRECTION OUTPUT ;
    USE SIGNAL ;
    PORT
      LAYER Metal3 ;
        RECT 2365.820000 3598.260000 2366.020000 3598.980000 ;
    END
  END sb_axi_araddr[28]
  PIN sb_axi_araddr[27]
    DIRECTION OUTPUT ;
    USE SIGNAL ;
    PORT
      LAYER Metal3 ;
        RECT 2369.180000 3598.260000 2369.380000 3598.980000 ;
    END
  END sb_axi_araddr[27]
  PIN sb_axi_araddr[26]
    DIRECTION OUTPUT ;
    USE SIGNAL ;
    PORT
      LAYER Metal3 ;
        RECT 2372.540000 3598.260000 2372.740000 3598.980000 ;
    END
  END sb_axi_araddr[26]
  PIN sb_axi_araddr[25]
    DIRECTION OUTPUT ;
    USE SIGNAL ;
    PORT
      LAYER Metal3 ;
        RECT 2375.900000 3598.260000 2376.100000 3598.980000 ;
    END
  END sb_axi_araddr[25]
  PIN sb_axi_araddr[24]
    DIRECTION OUTPUT ;
    USE SIGNAL ;
    PORT
      LAYER Metal3 ;
        RECT 2379.260000 3598.260000 2379.460000 3598.980000 ;
    END
  END sb_axi_araddr[24]
  PIN sb_axi_araddr[23]
    DIRECTION OUTPUT ;
    USE SIGNAL ;
    PORT
      LAYER Metal3 ;
        RECT 2382.140000 3598.260000 2382.340000 3598.980000 ;
    END
  END sb_axi_araddr[23]
  PIN sb_axi_araddr[22]
    DIRECTION OUTPUT ;
    USE SIGNAL ;
    PORT
      LAYER Metal3 ;
        RECT 2385.500000 3598.260000 2385.700000 3598.980000 ;
    END
  END sb_axi_araddr[22]
  PIN sb_axi_araddr[21]
    DIRECTION OUTPUT ;
    USE SIGNAL ;
    PORT
      LAYER Metal3 ;
        RECT 2388.860000 3598.260000 2389.060000 3598.980000 ;
    END
  END sb_axi_araddr[21]
  PIN sb_axi_araddr[20]
    DIRECTION OUTPUT ;
    USE SIGNAL ;
    PORT
      LAYER Metal3 ;
        RECT 2392.220000 3598.260000 2392.420000 3598.980000 ;
    END
  END sb_axi_araddr[20]
  PIN sb_axi_araddr[19]
    DIRECTION OUTPUT ;
    USE SIGNAL ;
    PORT
      LAYER Metal3 ;
        RECT 2395.580000 3598.260000 2395.780000 3598.980000 ;
    END
  END sb_axi_araddr[19]
  PIN sb_axi_araddr[18]
    DIRECTION OUTPUT ;
    USE SIGNAL ;
    PORT
      LAYER Metal3 ;
        RECT 2398.460000 3598.260000 2398.660000 3598.980000 ;
    END
  END sb_axi_araddr[18]
  PIN sb_axi_araddr[17]
    DIRECTION OUTPUT ;
    USE SIGNAL ;
    PORT
      LAYER Metal3 ;
        RECT 2401.820000 3598.260000 2402.020000 3598.980000 ;
    END
  END sb_axi_araddr[17]
  PIN sb_axi_araddr[16]
    DIRECTION OUTPUT ;
    USE SIGNAL ;
    PORT
      LAYER Metal3 ;
        RECT 2405.180000 3598.260000 2405.380000 3598.980000 ;
    END
  END sb_axi_araddr[16]
  PIN sb_axi_araddr[15]
    DIRECTION OUTPUT ;
    USE SIGNAL ;
    PORT
      LAYER Metal3 ;
        RECT 2408.540000 3598.260000 2408.740000 3598.980000 ;
    END
  END sb_axi_araddr[15]
  PIN sb_axi_araddr[14]
    DIRECTION OUTPUT ;
    USE SIGNAL ;
    PORT
      LAYER Metal3 ;
        RECT 2411.420000 3598.260000 2411.620000 3598.980000 ;
    END
  END sb_axi_araddr[14]
  PIN sb_axi_araddr[13]
    DIRECTION OUTPUT ;
    USE SIGNAL ;
    PORT
      LAYER Metal3 ;
        RECT 2414.780000 3598.260000 2414.980000 3598.980000 ;
    END
  END sb_axi_araddr[13]
  PIN sb_axi_araddr[12]
    DIRECTION OUTPUT ;
    USE SIGNAL ;
    PORT
      LAYER Metal3 ;
        RECT 2418.140000 3598.260000 2418.340000 3598.980000 ;
    END
  END sb_axi_araddr[12]
  PIN sb_axi_araddr[11]
    DIRECTION OUTPUT ;
    USE SIGNAL ;
    PORT
      LAYER Metal3 ;
        RECT 2421.500000 3598.260000 2421.700000 3598.980000 ;
    END
  END sb_axi_araddr[11]
  PIN sb_axi_araddr[10]
    DIRECTION OUTPUT ;
    USE SIGNAL ;
    PORT
      LAYER Metal3 ;
        RECT 2424.860000 3598.260000 2425.060000 3598.980000 ;
    END
  END sb_axi_araddr[10]
  PIN sb_axi_araddr[9]
    DIRECTION OUTPUT ;
    USE SIGNAL ;
    PORT
      LAYER Metal3 ;
        RECT 2427.740000 3598.260000 2427.940000 3598.980000 ;
    END
  END sb_axi_araddr[9]
  PIN sb_axi_araddr[8]
    DIRECTION OUTPUT ;
    USE SIGNAL ;
    PORT
      LAYER Metal3 ;
        RECT 2431.100000 3598.260000 2431.300000 3598.980000 ;
    END
  END sb_axi_araddr[8]
  PIN sb_axi_araddr[7]
    DIRECTION OUTPUT ;
    USE SIGNAL ;
    PORT
      LAYER Metal3 ;
        RECT 2434.460000 3598.260000 2434.660000 3598.980000 ;
    END
  END sb_axi_araddr[7]
  PIN sb_axi_araddr[6]
    DIRECTION OUTPUT ;
    USE SIGNAL ;
    PORT
      LAYER Metal3 ;
        RECT 2437.820000 3598.260000 2438.020000 3598.980000 ;
    END
  END sb_axi_araddr[6]
  PIN sb_axi_araddr[5]
    DIRECTION OUTPUT ;
    USE SIGNAL ;
    PORT
      LAYER Metal3 ;
        RECT 2441.180000 3598.260000 2441.380000 3598.980000 ;
    END
  END sb_axi_araddr[5]
  PIN sb_axi_araddr[4]
    DIRECTION OUTPUT ;
    USE SIGNAL ;
    PORT
      LAYER Metal3 ;
        RECT 2444.060000 3598.260000 2444.260000 3598.980000 ;
    END
  END sb_axi_araddr[4]
  PIN sb_axi_araddr[3]
    DIRECTION OUTPUT ;
    USE SIGNAL ;
    PORT
      LAYER Metal3 ;
        RECT 2447.420000 3598.260000 2447.620000 3598.980000 ;
    END
  END sb_axi_araddr[3]
  PIN sb_axi_araddr[2]
    DIRECTION OUTPUT ;
    USE SIGNAL ;
    PORT
      LAYER Metal3 ;
        RECT 2450.780000 3598.260000 2450.980000 3598.980000 ;
    END
  END sb_axi_araddr[2]
  PIN sb_axi_araddr[1]
    DIRECTION OUTPUT ;
    USE SIGNAL ;
    PORT
      LAYER Metal3 ;
        RECT 2454.140000 3598.260000 2454.340000 3598.980000 ;
    END
  END sb_axi_araddr[1]
  PIN sb_axi_araddr[0]
    DIRECTION OUTPUT ;
    USE SIGNAL ;
    PORT
      LAYER Metal3 ;
        RECT 2457.500000 3598.260000 2457.700000 3598.980000 ;
    END
  END sb_axi_araddr[0]
  PIN sb_axi_arregion[3]
    DIRECTION OUTPUT ;
    USE SIGNAL ;
    PORT
      LAYER Metal3 ;
        RECT 2460.380000 3598.260000 2460.580000 3598.980000 ;
    END
  END sb_axi_arregion[3]
  PIN sb_axi_arregion[2]
    DIRECTION OUTPUT ;
    USE SIGNAL ;
    PORT
      LAYER Metal3 ;
        RECT 2463.740000 3598.260000 2463.940000 3598.980000 ;
    END
  END sb_axi_arregion[2]
  PIN sb_axi_arregion[1]
    DIRECTION OUTPUT ;
    USE SIGNAL ;
    PORT
      LAYER Metal3 ;
        RECT 2467.100000 3598.260000 2467.300000 3598.980000 ;
    END
  END sb_axi_arregion[1]
  PIN sb_axi_arregion[0]
    DIRECTION OUTPUT ;
    USE SIGNAL ;
    PORT
      LAYER Metal3 ;
        RECT 2470.460000 3598.260000 2470.660000 3598.980000 ;
    END
  END sb_axi_arregion[0]
  PIN sb_axi_arlen[7]
    DIRECTION OUTPUT ;
    USE SIGNAL ;
    PORT
      LAYER Metal3 ;
        RECT 2473.340000 3598.260000 2473.540000 3598.980000 ;
    END
  END sb_axi_arlen[7]
  PIN sb_axi_arlen[6]
    DIRECTION OUTPUT ;
    USE SIGNAL ;
    PORT
      LAYER Metal3 ;
        RECT 2476.700000 3598.260000 2476.900000 3598.980000 ;
    END
  END sb_axi_arlen[6]
  PIN sb_axi_arlen[5]
    DIRECTION OUTPUT ;
    USE SIGNAL ;
    PORT
      LAYER Metal3 ;
        RECT 2480.060000 3598.260000 2480.260000 3598.980000 ;
    END
  END sb_axi_arlen[5]
  PIN sb_axi_arlen[4]
    DIRECTION OUTPUT ;
    USE SIGNAL ;
    PORT
      LAYER Metal3 ;
        RECT 2483.420000 3598.260000 2483.620000 3598.980000 ;
    END
  END sb_axi_arlen[4]
  PIN sb_axi_arlen[3]
    DIRECTION OUTPUT ;
    USE SIGNAL ;
    PORT
      LAYER Metal3 ;
        RECT 2486.780000 3598.260000 2486.980000 3598.980000 ;
    END
  END sb_axi_arlen[3]
  PIN sb_axi_arlen[2]
    DIRECTION OUTPUT ;
    USE SIGNAL ;
    PORT
      LAYER Metal3 ;
        RECT 2489.660000 3598.260000 2489.860000 3598.980000 ;
    END
  END sb_axi_arlen[2]
  PIN sb_axi_arlen[1]
    DIRECTION OUTPUT ;
    USE SIGNAL ;
    PORT
      LAYER Metal3 ;
        RECT 2493.020000 3598.260000 2493.220000 3598.980000 ;
    END
  END sb_axi_arlen[1]
  PIN sb_axi_arlen[0]
    DIRECTION OUTPUT ;
    USE SIGNAL ;
    PORT
      LAYER Metal3 ;
        RECT 2496.380000 3598.260000 2496.580000 3598.980000 ;
    END
  END sb_axi_arlen[0]
  PIN sb_axi_arsize[2]
    DIRECTION OUTPUT ;
    USE SIGNAL ;
    PORT
      LAYER Metal3 ;
        RECT 2499.740000 3598.260000 2499.940000 3598.980000 ;
    END
  END sb_axi_arsize[2]
  PIN sb_axi_arsize[1]
    DIRECTION OUTPUT ;
    USE SIGNAL ;
    PORT
      LAYER Metal3 ;
        RECT 2503.100000 3598.260000 2503.300000 3598.980000 ;
    END
  END sb_axi_arsize[1]
  PIN sb_axi_arsize[0]
    DIRECTION OUTPUT ;
    USE SIGNAL ;
    PORT
      LAYER Metal3 ;
        RECT 2505.980000 3598.260000 2506.180000 3598.980000 ;
    END
  END sb_axi_arsize[0]
  PIN sb_axi_arburst[1]
    DIRECTION OUTPUT ;
    USE SIGNAL ;
    PORT
      LAYER Metal3 ;
        RECT 2509.340000 3598.260000 2509.540000 3598.980000 ;
    END
  END sb_axi_arburst[1]
  PIN sb_axi_arburst[0]
    DIRECTION OUTPUT ;
    USE SIGNAL ;
    PORT
      LAYER Metal3 ;
        RECT 2512.700000 3598.260000 2512.900000 3598.980000 ;
    END
  END sb_axi_arburst[0]
  PIN sb_axi_arlock
    DIRECTION OUTPUT ;
    USE SIGNAL ;
    PORT
      LAYER Metal3 ;
        RECT 2516.060000 3598.260000 2516.260000 3598.980000 ;
    END
  END sb_axi_arlock
  PIN sb_axi_arcache[3]
    DIRECTION OUTPUT ;
    USE SIGNAL ;
    PORT
      LAYER Metal3 ;
        RECT 2519.420000 3598.260000 2519.620000 3598.980000 ;
    END
  END sb_axi_arcache[3]
  PIN sb_axi_arcache[2]
    DIRECTION OUTPUT ;
    USE SIGNAL ;
    PORT
      LAYER Metal3 ;
        RECT 2522.300000 3598.260000 2522.500000 3598.980000 ;
    END
  END sb_axi_arcache[2]
  PIN sb_axi_arcache[1]
    DIRECTION OUTPUT ;
    USE SIGNAL ;
    PORT
      LAYER Metal3 ;
        RECT 2525.660000 3598.260000 2525.860000 3598.980000 ;
    END
  END sb_axi_arcache[1]
  PIN sb_axi_arcache[0]
    DIRECTION OUTPUT ;
    USE SIGNAL ;
    PORT
      LAYER Metal3 ;
        RECT 2529.020000 3598.260000 2529.220000 3598.980000 ;
    END
  END sb_axi_arcache[0]
  PIN sb_axi_arprot[2]
    DIRECTION OUTPUT ;
    USE SIGNAL ;
    PORT
      LAYER Metal3 ;
        RECT 2532.380000 3598.260000 2532.580000 3598.980000 ;
    END
  END sb_axi_arprot[2]
  PIN sb_axi_arprot[1]
    DIRECTION OUTPUT ;
    USE SIGNAL ;
    PORT
      LAYER Metal3 ;
        RECT 2535.260000 3598.260000 2535.460000 3598.980000 ;
    END
  END sb_axi_arprot[1]
  PIN sb_axi_arprot[0]
    DIRECTION OUTPUT ;
    USE SIGNAL ;
    PORT
      LAYER Metal3 ;
        RECT 2538.620000 3598.260000 2538.820000 3598.980000 ;
    END
  END sb_axi_arprot[0]
  PIN sb_axi_arqos[3]
    DIRECTION OUTPUT ;
    USE SIGNAL ;
    PORT
      LAYER Metal3 ;
        RECT 2541.980000 3598.260000 2542.180000 3598.980000 ;
    END
  END sb_axi_arqos[3]
  PIN sb_axi_arqos[2]
    DIRECTION OUTPUT ;
    USE SIGNAL ;
    PORT
      LAYER Metal3 ;
        RECT 2545.340000 3598.260000 2545.540000 3598.980000 ;
    END
  END sb_axi_arqos[2]
  PIN sb_axi_arqos[1]
    DIRECTION OUTPUT ;
    USE SIGNAL ;
    PORT
      LAYER Metal3 ;
        RECT 2548.700000 3598.260000 2548.900000 3598.980000 ;
    END
  END sb_axi_arqos[1]
  PIN sb_axi_arqos[0]
    DIRECTION OUTPUT ;
    USE SIGNAL ;
    PORT
      LAYER Metal3 ;
        RECT 2551.580000 3598.260000 2551.780000 3598.980000 ;
    END
  END sb_axi_arqos[0]
  PIN sb_axi_rvalid
    DIRECTION INPUT ;
    USE SIGNAL ;
    PORT
      LAYER Metal3 ;
        RECT 2554.940000 3598.260000 2555.140000 3598.980000 ;
    END
  END sb_axi_rvalid
  PIN sb_axi_rready
    DIRECTION OUTPUT ;
    USE SIGNAL ;
    PORT
      LAYER Metal3 ;
        RECT 2558.300000 3598.260000 2558.500000 3598.980000 ;
    END
  END sb_axi_rready
  PIN sb_axi_rid[0]
    DIRECTION INPUT ;
    USE SIGNAL ;
    PORT
      LAYER Metal3 ;
        RECT 2561.660000 3598.260000 2561.860000 3598.980000 ;
    END
  END sb_axi_rid[0]
  PIN sb_axi_rdata[63]
    DIRECTION INPUT ;
    USE SIGNAL ;
    PORT
      LAYER Metal3 ;
        RECT 2565.020000 3598.260000 2565.220000 3598.980000 ;
    END
  END sb_axi_rdata[63]
  PIN sb_axi_rdata[62]
    DIRECTION INPUT ;
    USE SIGNAL ;
    PORT
      LAYER Metal3 ;
        RECT 2567.900000 3598.260000 2568.100000 3598.980000 ;
    END
  END sb_axi_rdata[62]
  PIN sb_axi_rdata[61]
    DIRECTION INPUT ;
    USE SIGNAL ;
    PORT
      LAYER Metal3 ;
        RECT 2571.260000 3598.260000 2571.460000 3598.980000 ;
    END
  END sb_axi_rdata[61]
  PIN sb_axi_rdata[60]
    DIRECTION INPUT ;
    USE SIGNAL ;
    PORT
      LAYER Metal3 ;
        RECT 2574.620000 3598.260000 2574.820000 3598.980000 ;
    END
  END sb_axi_rdata[60]
  PIN sb_axi_rdata[59]
    DIRECTION INPUT ;
    USE SIGNAL ;
    PORT
      LAYER Metal3 ;
        RECT 2577.980000 3598.260000 2578.180000 3598.980000 ;
    END
  END sb_axi_rdata[59]
  PIN sb_axi_rdata[58]
    DIRECTION INPUT ;
    USE SIGNAL ;
    PORT
      LAYER Metal3 ;
        RECT 2580.860000 3598.260000 2581.060000 3598.980000 ;
    END
  END sb_axi_rdata[58]
  PIN sb_axi_rdata[57]
    DIRECTION INPUT ;
    USE SIGNAL ;
    PORT
      LAYER Metal3 ;
        RECT 2584.220000 3598.260000 2584.420000 3598.980000 ;
    END
  END sb_axi_rdata[57]
  PIN sb_axi_rdata[56]
    DIRECTION INPUT ;
    USE SIGNAL ;
    PORT
      LAYER Metal3 ;
        RECT 2587.580000 3598.260000 2587.780000 3598.980000 ;
    END
  END sb_axi_rdata[56]
  PIN sb_axi_rdata[55]
    DIRECTION INPUT ;
    USE SIGNAL ;
    PORT
      LAYER Metal3 ;
        RECT 2590.940000 3598.260000 2591.140000 3598.980000 ;
    END
  END sb_axi_rdata[55]
  PIN sb_axi_rdata[54]
    DIRECTION INPUT ;
    USE SIGNAL ;
    PORT
      LAYER Metal3 ;
        RECT 2594.300000 3598.260000 2594.500000 3598.980000 ;
    END
  END sb_axi_rdata[54]
  PIN sb_axi_rdata[53]
    DIRECTION INPUT ;
    USE SIGNAL ;
    PORT
      LAYER Metal3 ;
        RECT 2597.180000 3598.260000 2597.380000 3598.980000 ;
    END
  END sb_axi_rdata[53]
  PIN sb_axi_rdata[52]
    DIRECTION INPUT ;
    USE SIGNAL ;
    PORT
      LAYER Metal3 ;
        RECT 2600.540000 3598.260000 2600.740000 3598.980000 ;
    END
  END sb_axi_rdata[52]
  PIN sb_axi_rdata[51]
    DIRECTION INPUT ;
    USE SIGNAL ;
    PORT
      LAYER Metal3 ;
        RECT 2603.900000 3598.260000 2604.100000 3598.980000 ;
    END
  END sb_axi_rdata[51]
  PIN sb_axi_rdata[50]
    DIRECTION INPUT ;
    USE SIGNAL ;
    PORT
      LAYER Metal3 ;
        RECT 2607.260000 3598.260000 2607.460000 3598.980000 ;
    END
  END sb_axi_rdata[50]
  PIN sb_axi_rdata[49]
    DIRECTION INPUT ;
    USE SIGNAL ;
    PORT
      LAYER Metal3 ;
        RECT 2610.620000 3598.260000 2610.820000 3598.980000 ;
    END
  END sb_axi_rdata[49]
  PIN sb_axi_rdata[48]
    DIRECTION INPUT ;
    USE SIGNAL ;
    PORT
      LAYER Metal3 ;
        RECT 2613.500000 3598.260000 2613.700000 3598.980000 ;
    END
  END sb_axi_rdata[48]
  PIN sb_axi_rdata[47]
    DIRECTION INPUT ;
    USE SIGNAL ;
    PORT
      LAYER Metal3 ;
        RECT 2616.860000 3598.260000 2617.060000 3598.980000 ;
    END
  END sb_axi_rdata[47]
  PIN sb_axi_rdata[46]
    DIRECTION INPUT ;
    USE SIGNAL ;
    PORT
      LAYER Metal3 ;
        RECT 2620.220000 3598.260000 2620.420000 3598.980000 ;
    END
  END sb_axi_rdata[46]
  PIN sb_axi_rdata[45]
    DIRECTION INPUT ;
    USE SIGNAL ;
    PORT
      LAYER Metal3 ;
        RECT 2623.580000 3598.260000 2623.780000 3598.980000 ;
    END
  END sb_axi_rdata[45]
  PIN sb_axi_rdata[44]
    DIRECTION INPUT ;
    USE SIGNAL ;
    PORT
      LAYER Metal3 ;
        RECT 2626.940000 3598.260000 2627.140000 3598.980000 ;
    END
  END sb_axi_rdata[44]
  PIN sb_axi_rdata[43]
    DIRECTION INPUT ;
    USE SIGNAL ;
    PORT
      LAYER Metal3 ;
        RECT 2629.820000 3598.260000 2630.020000 3598.980000 ;
    END
  END sb_axi_rdata[43]
  PIN sb_axi_rdata[42]
    DIRECTION INPUT ;
    USE SIGNAL ;
    PORT
      LAYER Metal3 ;
        RECT 2633.180000 3598.260000 2633.380000 3598.980000 ;
    END
  END sb_axi_rdata[42]
  PIN sb_axi_rdata[41]
    DIRECTION INPUT ;
    USE SIGNAL ;
    PORT
      LAYER Metal3 ;
        RECT 2636.540000 3598.260000 2636.740000 3598.980000 ;
    END
  END sb_axi_rdata[41]
  PIN sb_axi_rdata[40]
    DIRECTION INPUT ;
    USE SIGNAL ;
    PORT
      LAYER Metal3 ;
        RECT 2639.900000 3598.260000 2640.100000 3598.980000 ;
    END
  END sb_axi_rdata[40]
  PIN sb_axi_rdata[39]
    DIRECTION INPUT ;
    USE SIGNAL ;
    PORT
      LAYER Metal3 ;
        RECT 2642.780000 3598.260000 2642.980000 3598.980000 ;
    END
  END sb_axi_rdata[39]
  PIN sb_axi_rdata[38]
    DIRECTION INPUT ;
    USE SIGNAL ;
    PORT
      LAYER Metal3 ;
        RECT 2646.140000 3598.260000 2646.340000 3598.980000 ;
    END
  END sb_axi_rdata[38]
  PIN sb_axi_rdata[37]
    DIRECTION INPUT ;
    USE SIGNAL ;
    PORT
      LAYER Metal3 ;
        RECT 2649.500000 3598.260000 2649.700000 3598.980000 ;
    END
  END sb_axi_rdata[37]
  PIN sb_axi_rdata[36]
    DIRECTION INPUT ;
    USE SIGNAL ;
    PORT
      LAYER Metal3 ;
        RECT 2652.860000 3598.260000 2653.060000 3598.980000 ;
    END
  END sb_axi_rdata[36]
  PIN sb_axi_rdata[35]
    DIRECTION INPUT ;
    USE SIGNAL ;
    PORT
      LAYER Metal3 ;
        RECT 2656.220000 3598.260000 2656.420000 3598.980000 ;
    END
  END sb_axi_rdata[35]
  PIN sb_axi_rdata[34]
    DIRECTION INPUT ;
    USE SIGNAL ;
    PORT
      LAYER Metal3 ;
        RECT 2659.100000 3598.260000 2659.300000 3598.980000 ;
    END
  END sb_axi_rdata[34]
  PIN sb_axi_rdata[33]
    DIRECTION INPUT ;
    USE SIGNAL ;
    PORT
      LAYER Metal3 ;
        RECT 2662.460000 3598.260000 2662.660000 3598.980000 ;
    END
  END sb_axi_rdata[33]
  PIN sb_axi_rdata[32]
    DIRECTION INPUT ;
    USE SIGNAL ;
    PORT
      LAYER Metal3 ;
        RECT 2665.820000 3598.260000 2666.020000 3598.980000 ;
    END
  END sb_axi_rdata[32]
  PIN sb_axi_rdata[31]
    DIRECTION INPUT ;
    USE SIGNAL ;
    PORT
      LAYER Metal3 ;
        RECT 2669.180000 3598.260000 2669.380000 3598.980000 ;
    END
  END sb_axi_rdata[31]
  PIN sb_axi_rdata[30]
    DIRECTION INPUT ;
    USE SIGNAL ;
    PORT
      LAYER Metal3 ;
        RECT 2672.540000 3598.260000 2672.740000 3598.980000 ;
    END
  END sb_axi_rdata[30]
  PIN sb_axi_rdata[29]
    DIRECTION INPUT ;
    USE SIGNAL ;
    PORT
      LAYER Metal3 ;
        RECT 2675.420000 3598.260000 2675.620000 3598.980000 ;
    END
  END sb_axi_rdata[29]
  PIN sb_axi_rdata[28]
    DIRECTION INPUT ;
    USE SIGNAL ;
    PORT
      LAYER Metal3 ;
        RECT 2678.780000 3598.260000 2678.980000 3598.980000 ;
    END
  END sb_axi_rdata[28]
  PIN sb_axi_rdata[27]
    DIRECTION INPUT ;
    USE SIGNAL ;
    PORT
      LAYER Metal3 ;
        RECT 2682.140000 3598.260000 2682.340000 3598.980000 ;
    END
  END sb_axi_rdata[27]
  PIN sb_axi_rdata[26]
    DIRECTION INPUT ;
    USE SIGNAL ;
    PORT
      LAYER Metal3 ;
        RECT 2685.500000 3598.260000 2685.700000 3598.980000 ;
    END
  END sb_axi_rdata[26]
  PIN sb_axi_rdata[25]
    DIRECTION INPUT ;
    USE SIGNAL ;
    PORT
      LAYER Metal3 ;
        RECT 2688.860000 3598.260000 2689.060000 3598.980000 ;
    END
  END sb_axi_rdata[25]
  PIN sb_axi_rdata[24]
    DIRECTION INPUT ;
    USE SIGNAL ;
    PORT
      LAYER Metal3 ;
        RECT 2691.740000 3598.260000 2691.940000 3598.980000 ;
    END
  END sb_axi_rdata[24]
  PIN sb_axi_rdata[23]
    DIRECTION INPUT ;
    USE SIGNAL ;
    PORT
      LAYER Metal3 ;
        RECT 2695.100000 3598.260000 2695.300000 3598.980000 ;
    END
  END sb_axi_rdata[23]
  PIN sb_axi_rdata[22]
    DIRECTION INPUT ;
    USE SIGNAL ;
    PORT
      LAYER Metal3 ;
        RECT 2698.460000 3598.260000 2698.660000 3598.980000 ;
    END
  END sb_axi_rdata[22]
  PIN sb_axi_rdata[21]
    DIRECTION INPUT ;
    USE SIGNAL ;
    PORT
      LAYER Metal3 ;
        RECT 2701.820000 3598.260000 2702.020000 3598.980000 ;
    END
  END sb_axi_rdata[21]
  PIN sb_axi_rdata[20]
    DIRECTION INPUT ;
    USE SIGNAL ;
    PORT
      LAYER Metal3 ;
        RECT 2704.700000 3598.260000 2704.900000 3598.980000 ;
    END
  END sb_axi_rdata[20]
  PIN sb_axi_rdata[19]
    DIRECTION INPUT ;
    USE SIGNAL ;
    PORT
      LAYER Metal3 ;
        RECT 2708.060000 3598.260000 2708.260000 3598.980000 ;
    END
  END sb_axi_rdata[19]
  PIN sb_axi_rdata[18]
    DIRECTION INPUT ;
    USE SIGNAL ;
    PORT
      LAYER Metal3 ;
        RECT 2711.420000 3598.260000 2711.620000 3598.980000 ;
    END
  END sb_axi_rdata[18]
  PIN sb_axi_rdata[17]
    DIRECTION INPUT ;
    USE SIGNAL ;
    PORT
      LAYER Metal3 ;
        RECT 2714.780000 3598.260000 2714.980000 3598.980000 ;
    END
  END sb_axi_rdata[17]
  PIN sb_axi_rdata[16]
    DIRECTION INPUT ;
    USE SIGNAL ;
    PORT
      LAYER Metal3 ;
        RECT 2718.140000 3598.260000 2718.340000 3598.980000 ;
    END
  END sb_axi_rdata[16]
  PIN sb_axi_rdata[15]
    DIRECTION INPUT ;
    USE SIGNAL ;
    PORT
      LAYER Metal3 ;
        RECT 2721.020000 3598.260000 2721.220000 3598.980000 ;
    END
  END sb_axi_rdata[15]
  PIN sb_axi_rdata[14]
    DIRECTION INPUT ;
    USE SIGNAL ;
    PORT
      LAYER Metal3 ;
        RECT 2724.380000 3598.260000 2724.580000 3598.980000 ;
    END
  END sb_axi_rdata[14]
  PIN sb_axi_rdata[13]
    DIRECTION INPUT ;
    USE SIGNAL ;
    PORT
      LAYER Metal3 ;
        RECT 2727.740000 3598.260000 2727.940000 3598.980000 ;
    END
  END sb_axi_rdata[13]
  PIN sb_axi_rdata[12]
    DIRECTION INPUT ;
    USE SIGNAL ;
    PORT
      LAYER Metal3 ;
        RECT 2731.100000 3598.260000 2731.300000 3598.980000 ;
    END
  END sb_axi_rdata[12]
  PIN sb_axi_rdata[11]
    DIRECTION INPUT ;
    USE SIGNAL ;
    PORT
      LAYER Metal3 ;
        RECT 2734.460000 3598.260000 2734.660000 3598.980000 ;
    END
  END sb_axi_rdata[11]
  PIN sb_axi_rdata[10]
    DIRECTION INPUT ;
    USE SIGNAL ;
    PORT
      LAYER Metal3 ;
        RECT 2737.340000 3598.260000 2737.540000 3598.980000 ;
    END
  END sb_axi_rdata[10]
  PIN sb_axi_rdata[9]
    DIRECTION INPUT ;
    USE SIGNAL ;
    PORT
      LAYER Metal3 ;
        RECT 2740.700000 3598.260000 2740.900000 3598.980000 ;
    END
  END sb_axi_rdata[9]
  PIN sb_axi_rdata[8]
    DIRECTION INPUT ;
    USE SIGNAL ;
    PORT
      LAYER Metal3 ;
        RECT 2744.060000 3598.260000 2744.260000 3598.980000 ;
    END
  END sb_axi_rdata[8]
  PIN sb_axi_rdata[7]
    DIRECTION INPUT ;
    USE SIGNAL ;
    PORT
      LAYER Metal3 ;
        RECT 2747.420000 3598.260000 2747.620000 3598.980000 ;
    END
  END sb_axi_rdata[7]
  PIN sb_axi_rdata[6]
    DIRECTION INPUT ;
    USE SIGNAL ;
    PORT
      LAYER Metal3 ;
        RECT 2750.780000 3598.260000 2750.980000 3598.980000 ;
    END
  END sb_axi_rdata[6]
  PIN sb_axi_rdata[5]
    DIRECTION INPUT ;
    USE SIGNAL ;
    PORT
      LAYER Metal3 ;
        RECT 2753.660000 3598.260000 2753.860000 3598.980000 ;
    END
  END sb_axi_rdata[5]
  PIN sb_axi_rdata[4]
    DIRECTION INPUT ;
    USE SIGNAL ;
    PORT
      LAYER Metal3 ;
        RECT 2757.020000 3598.260000 2757.220000 3598.980000 ;
    END
  END sb_axi_rdata[4]
  PIN sb_axi_rdata[3]
    DIRECTION INPUT ;
    USE SIGNAL ;
    PORT
      LAYER Metal3 ;
        RECT 2760.380000 3598.260000 2760.580000 3598.980000 ;
    END
  END sb_axi_rdata[3]
  PIN sb_axi_rdata[2]
    DIRECTION INPUT ;
    USE SIGNAL ;
    PORT
      LAYER Metal3 ;
        RECT 2763.740000 3598.260000 2763.940000 3598.980000 ;
    END
  END sb_axi_rdata[2]
  PIN sb_axi_rdata[1]
    DIRECTION INPUT ;
    USE SIGNAL ;
    PORT
      LAYER Metal3 ;
        RECT 2766.620000 3598.260000 2766.820000 3598.980000 ;
    END
  END sb_axi_rdata[1]
  PIN sb_axi_rdata[0]
    DIRECTION INPUT ;
    USE SIGNAL ;
    PORT
      LAYER Metal3 ;
        RECT 2769.980000 3598.260000 2770.180000 3598.980000 ;
    END
  END sb_axi_rdata[0]
  PIN sb_axi_rresp[1]
    DIRECTION INPUT ;
    USE SIGNAL ;
    PORT
      LAYER Metal3 ;
        RECT 2773.340000 3598.260000 2773.540000 3598.980000 ;
    END
  END sb_axi_rresp[1]
  PIN sb_axi_rresp[0]
    DIRECTION INPUT ;
    USE SIGNAL ;
    PORT
      LAYER Metal3 ;
        RECT 2776.700000 3598.260000 2776.900000 3598.980000 ;
    END
  END sb_axi_rresp[0]
  PIN sb_axi_rlast
    DIRECTION INPUT ;
    USE SIGNAL ;
    PORT
      LAYER Metal3 ;
        RECT 2780.060000 3598.260000 2780.260000 3598.980000 ;
    END
  END sb_axi_rlast
  PIN dma_axi_awvalid
    DIRECTION INPUT ;
    USE SIGNAL ;
    PORT
      LAYER Metal3 ;
        RECT 2782.940000 3598.260000 2783.140000 3598.980000 ;
    END
  END dma_axi_awvalid
  PIN dma_axi_awready
    DIRECTION OUTPUT ;
    USE SIGNAL ;
    PORT
      LAYER Metal3 ;
        RECT 2786.300000 3598.260000 2786.500000 3598.980000 ;
    END
  END dma_axi_awready
  PIN dma_axi_awid[0]
    DIRECTION INPUT ;
    USE SIGNAL ;
    PORT
      LAYER Metal3 ;
        RECT 2789.660000 3598.260000 2789.860000 3598.980000 ;
    END
  END dma_axi_awid[0]
  PIN dma_axi_awaddr[31]
    DIRECTION INPUT ;
    USE SIGNAL ;
    PORT
      LAYER Metal3 ;
        RECT 2793.020000 3598.260000 2793.220000 3598.980000 ;
    END
  END dma_axi_awaddr[31]
  PIN dma_axi_awaddr[30]
    DIRECTION INPUT ;
    USE SIGNAL ;
    PORT
      LAYER Metal3 ;
        RECT 2796.380000 3598.260000 2796.580000 3598.980000 ;
    END
  END dma_axi_awaddr[30]
  PIN dma_axi_awaddr[29]
    DIRECTION INPUT ;
    USE SIGNAL ;
    PORT
      LAYER Metal3 ;
        RECT 2799.260000 3598.260000 2799.460000 3598.980000 ;
    END
  END dma_axi_awaddr[29]
  PIN dma_axi_awaddr[28]
    DIRECTION INPUT ;
    USE SIGNAL ;
    PORT
      LAYER Metal3 ;
        RECT 2802.620000 3598.260000 2802.820000 3598.980000 ;
    END
  END dma_axi_awaddr[28]
  PIN dma_axi_awaddr[27]
    DIRECTION INPUT ;
    USE SIGNAL ;
    PORT
      LAYER Metal3 ;
        RECT 2805.980000 3598.260000 2806.180000 3598.980000 ;
    END
  END dma_axi_awaddr[27]
  PIN dma_axi_awaddr[26]
    DIRECTION INPUT ;
    USE SIGNAL ;
    PORT
      LAYER Metal3 ;
        RECT 2809.340000 3598.260000 2809.540000 3598.980000 ;
    END
  END dma_axi_awaddr[26]
  PIN dma_axi_awaddr[25]
    DIRECTION INPUT ;
    USE SIGNAL ;
    PORT
      LAYER Metal3 ;
        RECT 2812.700000 3598.260000 2812.900000 3598.980000 ;
    END
  END dma_axi_awaddr[25]
  PIN dma_axi_awaddr[24]
    DIRECTION INPUT ;
    USE SIGNAL ;
    PORT
      LAYER Metal3 ;
        RECT 2815.580000 3598.260000 2815.780000 3598.980000 ;
    END
  END dma_axi_awaddr[24]
  PIN dma_axi_awaddr[23]
    DIRECTION INPUT ;
    USE SIGNAL ;
    PORT
      LAYER Metal3 ;
        RECT 2818.940000 3598.260000 2819.140000 3598.980000 ;
    END
  END dma_axi_awaddr[23]
  PIN dma_axi_awaddr[22]
    DIRECTION INPUT ;
    USE SIGNAL ;
    PORT
      LAYER Metal3 ;
        RECT 2822.300000 3598.260000 2822.500000 3598.980000 ;
    END
  END dma_axi_awaddr[22]
  PIN dma_axi_awaddr[21]
    DIRECTION INPUT ;
    USE SIGNAL ;
    PORT
      LAYER Metal3 ;
        RECT 2825.660000 3598.260000 2825.860000 3598.980000 ;
    END
  END dma_axi_awaddr[21]
  PIN dma_axi_awaddr[20]
    DIRECTION INPUT ;
    USE SIGNAL ;
    PORT
      LAYER Metal3 ;
        RECT 2828.540000 3598.260000 2828.740000 3598.980000 ;
    END
  END dma_axi_awaddr[20]
  PIN dma_axi_awaddr[19]
    DIRECTION INPUT ;
    USE SIGNAL ;
    PORT
      LAYER Metal3 ;
        RECT 2831.900000 3598.260000 2832.100000 3598.980000 ;
    END
  END dma_axi_awaddr[19]
  PIN dma_axi_awaddr[18]
    DIRECTION INPUT ;
    USE SIGNAL ;
    PORT
      LAYER Metal3 ;
        RECT 2835.260000 3598.260000 2835.460000 3598.980000 ;
    END
  END dma_axi_awaddr[18]
  PIN dma_axi_awaddr[17]
    DIRECTION INPUT ;
    USE SIGNAL ;
    PORT
      LAYER Metal3 ;
        RECT 2838.620000 3598.260000 2838.820000 3598.980000 ;
    END
  END dma_axi_awaddr[17]
  PIN dma_axi_awaddr[16]
    DIRECTION INPUT ;
    USE SIGNAL ;
    PORT
      LAYER Metal3 ;
        RECT 2841.980000 3598.260000 2842.180000 3598.980000 ;
    END
  END dma_axi_awaddr[16]
  PIN dma_axi_awaddr[15]
    DIRECTION INPUT ;
    USE SIGNAL ;
    PORT
      LAYER Metal3 ;
        RECT 2844.860000 3598.260000 2845.060000 3598.980000 ;
    END
  END dma_axi_awaddr[15]
  PIN dma_axi_awaddr[14]
    DIRECTION INPUT ;
    USE SIGNAL ;
    PORT
      LAYER Metal3 ;
        RECT 2848.220000 3598.260000 2848.420000 3598.980000 ;
    END
  END dma_axi_awaddr[14]
  PIN dma_axi_awaddr[13]
    DIRECTION INPUT ;
    USE SIGNAL ;
    PORT
      LAYER Metal3 ;
        RECT 2851.580000 3598.260000 2851.780000 3598.980000 ;
    END
  END dma_axi_awaddr[13]
  PIN dma_axi_awaddr[12]
    DIRECTION INPUT ;
    USE SIGNAL ;
    PORT
      LAYER Metal3 ;
        RECT 2854.940000 3598.260000 2855.140000 3598.980000 ;
    END
  END dma_axi_awaddr[12]
  PIN dma_axi_awaddr[11]
    DIRECTION INPUT ;
    USE SIGNAL ;
    PORT
      LAYER Metal3 ;
        RECT 2858.300000 3598.260000 2858.500000 3598.980000 ;
    END
  END dma_axi_awaddr[11]
  PIN dma_axi_awaddr[10]
    DIRECTION INPUT ;
    USE SIGNAL ;
    PORT
      LAYER Metal3 ;
        RECT 2861.180000 3598.260000 2861.380000 3598.980000 ;
    END
  END dma_axi_awaddr[10]
  PIN dma_axi_awaddr[9]
    DIRECTION INPUT ;
    USE SIGNAL ;
    PORT
      LAYER Metal3 ;
        RECT 2864.540000 3598.260000 2864.740000 3598.980000 ;
    END
  END dma_axi_awaddr[9]
  PIN dma_axi_awaddr[8]
    DIRECTION INPUT ;
    USE SIGNAL ;
    PORT
      LAYER Metal3 ;
        RECT 2867.900000 3598.260000 2868.100000 3598.980000 ;
    END
  END dma_axi_awaddr[8]
  PIN dma_axi_awaddr[7]
    DIRECTION INPUT ;
    USE SIGNAL ;
    PORT
      LAYER Metal3 ;
        RECT 2871.260000 3598.260000 2871.460000 3598.980000 ;
    END
  END dma_axi_awaddr[7]
  PIN dma_axi_awaddr[6]
    DIRECTION INPUT ;
    USE SIGNAL ;
    PORT
      LAYER Metal3 ;
        RECT 2874.620000 3598.260000 2874.820000 3598.980000 ;
    END
  END dma_axi_awaddr[6]
  PIN dma_axi_awaddr[5]
    DIRECTION INPUT ;
    USE SIGNAL ;
    PORT
      LAYER Metal3 ;
        RECT 2877.500000 3598.260000 2877.700000 3598.980000 ;
    END
  END dma_axi_awaddr[5]
  PIN dma_axi_awaddr[4]
    DIRECTION INPUT ;
    USE SIGNAL ;
    PORT
      LAYER Metal3 ;
        RECT 2880.860000 3598.260000 2881.060000 3598.980000 ;
    END
  END dma_axi_awaddr[4]
  PIN dma_axi_awaddr[3]
    DIRECTION INPUT ;
    USE SIGNAL ;
    PORT
      LAYER Metal3 ;
        RECT 2884.220000 3598.260000 2884.420000 3598.980000 ;
    END
  END dma_axi_awaddr[3]
  PIN dma_axi_awaddr[2]
    DIRECTION INPUT ;
    USE SIGNAL ;
    PORT
      LAYER Metal3 ;
        RECT 2887.580000 3598.260000 2887.780000 3598.980000 ;
    END
  END dma_axi_awaddr[2]
  PIN dma_axi_awaddr[1]
    DIRECTION INPUT ;
    USE SIGNAL ;
    PORT
      LAYER Metal3 ;
        RECT 2890.460000 3598.260000 2890.660000 3598.980000 ;
    END
  END dma_axi_awaddr[1]
  PIN dma_axi_awaddr[0]
    DIRECTION INPUT ;
    USE SIGNAL ;
    PORT
      LAYER Metal3 ;
        RECT 2893.820000 3598.260000 2894.020000 3598.980000 ;
    END
  END dma_axi_awaddr[0]
  PIN dma_axi_awsize[2]
    DIRECTION INPUT ;
    USE SIGNAL ;
    PORT
      LAYER Metal3 ;
        RECT 2897.180000 3598.260000 2897.380000 3598.980000 ;
    END
  END dma_axi_awsize[2]
  PIN dma_axi_awsize[1]
    DIRECTION INPUT ;
    USE SIGNAL ;
    PORT
      LAYER Metal3 ;
        RECT 2900.540000 3598.260000 2900.740000 3598.980000 ;
    END
  END dma_axi_awsize[1]
  PIN dma_axi_awsize[0]
    DIRECTION INPUT ;
    USE SIGNAL ;
    PORT
      LAYER Metal3 ;
        RECT 2903.900000 3598.260000 2904.100000 3598.980000 ;
    END
  END dma_axi_awsize[0]
  PIN dma_axi_awprot[2]
    DIRECTION INPUT ;
    USE SIGNAL ;
    PORT
      LAYER Metal3 ;
        RECT 2906.780000 3598.260000 2906.980000 3598.980000 ;
    END
  END dma_axi_awprot[2]
  PIN dma_axi_awprot[1]
    DIRECTION INPUT ;
    USE SIGNAL ;
    PORT
      LAYER Metal3 ;
        RECT 2910.140000 3598.260000 2910.340000 3598.980000 ;
    END
  END dma_axi_awprot[1]
  PIN dma_axi_awprot[0]
    DIRECTION INPUT ;
    USE SIGNAL ;
    PORT
      LAYER Metal3 ;
        RECT 2913.500000 3598.260000 2913.700000 3598.980000 ;
    END
  END dma_axi_awprot[0]
  PIN dma_axi_awlen[7]
    DIRECTION INPUT ;
    USE SIGNAL ;
    PORT
      LAYER Metal3 ;
        RECT 2916.860000 3598.260000 2917.060000 3598.980000 ;
    END
  END dma_axi_awlen[7]
  PIN dma_axi_awlen[6]
    DIRECTION INPUT ;
    USE SIGNAL ;
    PORT
      LAYER Metal3 ;
        RECT 2920.220000 3598.260000 2920.420000 3598.980000 ;
    END
  END dma_axi_awlen[6]
  PIN dma_axi_awlen[5]
    DIRECTION INPUT ;
    USE SIGNAL ;
    PORT
      LAYER Metal3 ;
        RECT 2923.100000 3598.260000 2923.300000 3598.980000 ;
    END
  END dma_axi_awlen[5]
  PIN dma_axi_awlen[4]
    DIRECTION INPUT ;
    USE SIGNAL ;
    PORT
      LAYER Metal3 ;
        RECT 2926.460000 3598.260000 2926.660000 3598.980000 ;
    END
  END dma_axi_awlen[4]
  PIN dma_axi_awlen[3]
    DIRECTION INPUT ;
    USE SIGNAL ;
    PORT
      LAYER Metal3 ;
        RECT 2929.820000 3598.260000 2930.020000 3598.980000 ;
    END
  END dma_axi_awlen[3]
  PIN dma_axi_awlen[2]
    DIRECTION INPUT ;
    USE SIGNAL ;
    PORT
      LAYER Metal3 ;
        RECT 2933.180000 3598.260000 2933.380000 3598.980000 ;
    END
  END dma_axi_awlen[2]
  PIN dma_axi_awlen[1]
    DIRECTION INPUT ;
    USE SIGNAL ;
    PORT
      LAYER Metal3 ;
        RECT 2936.540000 3598.260000 2936.740000 3598.980000 ;
    END
  END dma_axi_awlen[1]
  PIN dma_axi_awlen[0]
    DIRECTION INPUT ;
    USE SIGNAL ;
    PORT
      LAYER Metal3 ;
        RECT 2939.420000 3598.260000 2939.620000 3598.980000 ;
    END
  END dma_axi_awlen[0]
  PIN dma_axi_awburst[1]
    DIRECTION INPUT ;
    USE SIGNAL ;
    PORT
      LAYER Metal3 ;
        RECT 2942.780000 3598.260000 2942.980000 3598.980000 ;
    END
  END dma_axi_awburst[1]
  PIN dma_axi_awburst[0]
    DIRECTION INPUT ;
    USE SIGNAL ;
    PORT
      LAYER Metal3 ;
        RECT 2946.140000 3598.260000 2946.340000 3598.980000 ;
    END
  END dma_axi_awburst[0]
  PIN dma_axi_wvalid
    DIRECTION INPUT ;
    USE SIGNAL ;
    PORT
      LAYER Metal3 ;
        RECT 2949.500000 3598.260000 2949.700000 3598.980000 ;
    END
  END dma_axi_wvalid
  PIN dma_axi_wready
    DIRECTION OUTPUT ;
    USE SIGNAL ;
    PORT
      LAYER Metal3 ;
        RECT 2952.380000 3598.260000 2952.580000 3598.980000 ;
    END
  END dma_axi_wready
  PIN dma_axi_wdata[63]
    DIRECTION INPUT ;
    USE SIGNAL ;
    PORT
      LAYER Metal3 ;
        RECT 2955.740000 3598.260000 2955.940000 3598.980000 ;
    END
  END dma_axi_wdata[63]
  PIN dma_axi_wdata[62]
    DIRECTION INPUT ;
    USE SIGNAL ;
    PORT
      LAYER Metal3 ;
        RECT 2959.100000 3598.260000 2959.300000 3598.980000 ;
    END
  END dma_axi_wdata[62]
  PIN dma_axi_wdata[61]
    DIRECTION INPUT ;
    USE SIGNAL ;
    PORT
      LAYER Metal3 ;
        RECT 2962.460000 3598.260000 2962.660000 3598.980000 ;
    END
  END dma_axi_wdata[61]
  PIN dma_axi_wdata[60]
    DIRECTION INPUT ;
    USE SIGNAL ;
    PORT
      LAYER Metal3 ;
        RECT 2965.820000 3598.260000 2966.020000 3598.980000 ;
    END
  END dma_axi_wdata[60]
  PIN dma_axi_wdata[59]
    DIRECTION INPUT ;
    USE SIGNAL ;
    PORT
      LAYER Metal3 ;
        RECT 2968.700000 3598.260000 2968.900000 3598.980000 ;
    END
  END dma_axi_wdata[59]
  PIN dma_axi_wdata[58]
    DIRECTION INPUT ;
    USE SIGNAL ;
    PORT
      LAYER Metal3 ;
        RECT 2972.060000 3598.260000 2972.260000 3598.980000 ;
    END
  END dma_axi_wdata[58]
  PIN dma_axi_wdata[57]
    DIRECTION INPUT ;
    USE SIGNAL ;
    PORT
      LAYER Metal3 ;
        RECT 2975.420000 3598.260000 2975.620000 3598.980000 ;
    END
  END dma_axi_wdata[57]
  PIN dma_axi_wdata[56]
    DIRECTION INPUT ;
    USE SIGNAL ;
    PORT
      LAYER Metal3 ;
        RECT 2978.780000 3598.260000 2978.980000 3598.980000 ;
    END
  END dma_axi_wdata[56]
  PIN dma_axi_wdata[55]
    DIRECTION INPUT ;
    USE SIGNAL ;
    PORT
      LAYER Metal3 ;
        RECT 2982.140000 3598.260000 2982.340000 3598.980000 ;
    END
  END dma_axi_wdata[55]
  PIN dma_axi_wdata[54]
    DIRECTION INPUT ;
    USE SIGNAL ;
    PORT
      LAYER Metal3 ;
        RECT 2985.020000 3598.260000 2985.220000 3598.980000 ;
    END
  END dma_axi_wdata[54]
  PIN dma_axi_wdata[53]
    DIRECTION INPUT ;
    USE SIGNAL ;
    PORT
      LAYER Metal3 ;
        RECT 2988.380000 3598.260000 2988.580000 3598.980000 ;
    END
  END dma_axi_wdata[53]
  PIN dma_axi_wdata[52]
    DIRECTION INPUT ;
    USE SIGNAL ;
    PORT
      LAYER Metal3 ;
        RECT 2991.740000 3598.260000 2991.940000 3598.980000 ;
    END
  END dma_axi_wdata[52]
  PIN dma_axi_wdata[51]
    DIRECTION INPUT ;
    USE SIGNAL ;
    PORT
      LAYER Metal3 ;
        RECT 2995.100000 3598.260000 2995.300000 3598.980000 ;
    END
  END dma_axi_wdata[51]
  PIN dma_axi_wdata[50]
    DIRECTION INPUT ;
    USE SIGNAL ;
    PORT
      LAYER Metal3 ;
        RECT 2998.460000 3598.260000 2998.660000 3598.980000 ;
    END
  END dma_axi_wdata[50]
  PIN dma_axi_wdata[49]
    DIRECTION INPUT ;
    USE SIGNAL ;
    PORT
      LAYER Metal3 ;
        RECT 3001.340000 3598.260000 3001.540000 3598.980000 ;
    END
  END dma_axi_wdata[49]
  PIN dma_axi_wdata[48]
    DIRECTION INPUT ;
    USE SIGNAL ;
    PORT
      LAYER Metal3 ;
        RECT 3004.700000 3598.260000 3004.900000 3598.980000 ;
    END
  END dma_axi_wdata[48]
  PIN dma_axi_wdata[47]
    DIRECTION INPUT ;
    USE SIGNAL ;
    PORT
      LAYER Metal3 ;
        RECT 3008.060000 3598.260000 3008.260000 3598.980000 ;
    END
  END dma_axi_wdata[47]
  PIN dma_axi_wdata[46]
    DIRECTION INPUT ;
    USE SIGNAL ;
    PORT
      LAYER Metal3 ;
        RECT 3011.420000 3598.260000 3011.620000 3598.980000 ;
    END
  END dma_axi_wdata[46]
  PIN dma_axi_wdata[45]
    DIRECTION INPUT ;
    USE SIGNAL ;
    PORT
      LAYER Metal3 ;
        RECT 3014.300000 3598.260000 3014.500000 3598.980000 ;
    END
  END dma_axi_wdata[45]
  PIN dma_axi_wdata[44]
    DIRECTION INPUT ;
    USE SIGNAL ;
    PORT
      LAYER Metal3 ;
        RECT 3017.660000 3598.260000 3017.860000 3598.980000 ;
    END
  END dma_axi_wdata[44]
  PIN dma_axi_wdata[43]
    DIRECTION INPUT ;
    USE SIGNAL ;
    PORT
      LAYER Metal3 ;
        RECT 3021.020000 3598.260000 3021.220000 3598.980000 ;
    END
  END dma_axi_wdata[43]
  PIN dma_axi_wdata[42]
    DIRECTION INPUT ;
    USE SIGNAL ;
    PORT
      LAYER Metal3 ;
        RECT 3024.380000 3598.260000 3024.580000 3598.980000 ;
    END
  END dma_axi_wdata[42]
  PIN dma_axi_wdata[41]
    DIRECTION INPUT ;
    USE SIGNAL ;
    PORT
      LAYER Metal3 ;
        RECT 3027.740000 3598.260000 3027.940000 3598.980000 ;
    END
  END dma_axi_wdata[41]
  PIN dma_axi_wdata[40]
    DIRECTION INPUT ;
    USE SIGNAL ;
    PORT
      LAYER Metal3 ;
        RECT 3030.620000 3598.260000 3030.820000 3598.980000 ;
    END
  END dma_axi_wdata[40]
  PIN dma_axi_wdata[39]
    DIRECTION INPUT ;
    USE SIGNAL ;
    PORT
      LAYER Metal3 ;
        RECT 3033.980000 3598.260000 3034.180000 3598.980000 ;
    END
  END dma_axi_wdata[39]
  PIN dma_axi_wdata[38]
    DIRECTION INPUT ;
    USE SIGNAL ;
    PORT
      LAYER Metal3 ;
        RECT 3037.340000 3598.260000 3037.540000 3598.980000 ;
    END
  END dma_axi_wdata[38]
  PIN dma_axi_wdata[37]
    DIRECTION INPUT ;
    USE SIGNAL ;
    PORT
      LAYER Metal3 ;
        RECT 3040.700000 3598.260000 3040.900000 3598.980000 ;
    END
  END dma_axi_wdata[37]
  PIN dma_axi_wdata[36]
    DIRECTION INPUT ;
    USE SIGNAL ;
    PORT
      LAYER Metal3 ;
        RECT 3044.060000 3598.260000 3044.260000 3598.980000 ;
    END
  END dma_axi_wdata[36]
  PIN dma_axi_wdata[35]
    DIRECTION INPUT ;
    USE SIGNAL ;
    PORT
      LAYER Metal3 ;
        RECT 3046.940000 3598.260000 3047.140000 3598.980000 ;
    END
  END dma_axi_wdata[35]
  PIN dma_axi_wdata[34]
    DIRECTION INPUT ;
    USE SIGNAL ;
    PORT
      LAYER Metal3 ;
        RECT 3050.300000 3598.260000 3050.500000 3598.980000 ;
    END
  END dma_axi_wdata[34]
  PIN dma_axi_wdata[33]
    DIRECTION INPUT ;
    USE SIGNAL ;
    PORT
      LAYER Metal3 ;
        RECT 3053.660000 3598.260000 3053.860000 3598.980000 ;
    END
  END dma_axi_wdata[33]
  PIN dma_axi_wdata[32]
    DIRECTION INPUT ;
    USE SIGNAL ;
    PORT
      LAYER Metal3 ;
        RECT 3057.020000 3598.260000 3057.220000 3598.980000 ;
    END
  END dma_axi_wdata[32]
  PIN dma_axi_wdata[31]
    DIRECTION INPUT ;
    USE SIGNAL ;
    PORT
      LAYER Metal3 ;
        RECT 3060.380000 3598.260000 3060.580000 3598.980000 ;
    END
  END dma_axi_wdata[31]
  PIN dma_axi_wdata[30]
    DIRECTION INPUT ;
    USE SIGNAL ;
    PORT
      LAYER Metal3 ;
        RECT 3063.260000 3598.260000 3063.460000 3598.980000 ;
    END
  END dma_axi_wdata[30]
  PIN dma_axi_wdata[29]
    DIRECTION INPUT ;
    USE SIGNAL ;
    PORT
      LAYER Metal3 ;
        RECT 3066.620000 3598.260000 3066.820000 3598.980000 ;
    END
  END dma_axi_wdata[29]
  PIN dma_axi_wdata[28]
    DIRECTION INPUT ;
    USE SIGNAL ;
    PORT
      LAYER Metal3 ;
        RECT 3069.980000 3598.260000 3070.180000 3598.980000 ;
    END
  END dma_axi_wdata[28]
  PIN dma_axi_wdata[27]
    DIRECTION INPUT ;
    USE SIGNAL ;
    PORT
      LAYER Metal3 ;
        RECT 3073.340000 3598.260000 3073.540000 3598.980000 ;
    END
  END dma_axi_wdata[27]
  PIN dma_axi_wdata[26]
    DIRECTION INPUT ;
    USE SIGNAL ;
    PORT
      LAYER Metal3 ;
        RECT 3076.220000 3598.260000 3076.420000 3598.980000 ;
    END
  END dma_axi_wdata[26]
  PIN dma_axi_wdata[25]
    DIRECTION INPUT ;
    USE SIGNAL ;
    PORT
      LAYER Metal3 ;
        RECT 3079.580000 3598.260000 3079.780000 3598.980000 ;
    END
  END dma_axi_wdata[25]
  PIN dma_axi_wdata[24]
    DIRECTION INPUT ;
    USE SIGNAL ;
    PORT
      LAYER Metal3 ;
        RECT 3082.940000 3598.260000 3083.140000 3598.980000 ;
    END
  END dma_axi_wdata[24]
  PIN dma_axi_wdata[23]
    DIRECTION INPUT ;
    USE SIGNAL ;
    PORT
      LAYER Metal3 ;
        RECT 3086.300000 3598.260000 3086.500000 3598.980000 ;
    END
  END dma_axi_wdata[23]
  PIN dma_axi_wdata[22]
    DIRECTION INPUT ;
    USE SIGNAL ;
    PORT
      LAYER Metal3 ;
        RECT 3089.660000 3598.260000 3089.860000 3598.980000 ;
    END
  END dma_axi_wdata[22]
  PIN dma_axi_wdata[21]
    DIRECTION INPUT ;
    USE SIGNAL ;
    PORT
      LAYER Metal3 ;
        RECT 3092.540000 3598.260000 3092.740000 3598.980000 ;
    END
  END dma_axi_wdata[21]
  PIN dma_axi_wdata[20]
    DIRECTION INPUT ;
    USE SIGNAL ;
    PORT
      LAYER Metal3 ;
        RECT 3095.900000 3598.260000 3096.100000 3598.980000 ;
    END
  END dma_axi_wdata[20]
  PIN dma_axi_wdata[19]
    DIRECTION INPUT ;
    USE SIGNAL ;
    PORT
      LAYER Metal3 ;
        RECT 3099.260000 3598.260000 3099.460000 3598.980000 ;
    END
  END dma_axi_wdata[19]
  PIN dma_axi_wdata[18]
    DIRECTION INPUT ;
    USE SIGNAL ;
    PORT
      LAYER Metal3 ;
        RECT 3102.620000 3598.260000 3102.820000 3598.980000 ;
    END
  END dma_axi_wdata[18]
  PIN dma_axi_wdata[17]
    DIRECTION INPUT ;
    USE SIGNAL ;
    PORT
      LAYER Metal3 ;
        RECT 3105.980000 3598.260000 3106.180000 3598.980000 ;
    END
  END dma_axi_wdata[17]
  PIN dma_axi_wdata[16]
    DIRECTION INPUT ;
    USE SIGNAL ;
    PORT
      LAYER Metal3 ;
        RECT 3108.860000 3598.260000 3109.060000 3598.980000 ;
    END
  END dma_axi_wdata[16]
  PIN dma_axi_wdata[15]
    DIRECTION INPUT ;
    USE SIGNAL ;
    PORT
      LAYER Metal3 ;
        RECT 3112.220000 3598.260000 3112.420000 3598.980000 ;
    END
  END dma_axi_wdata[15]
  PIN dma_axi_wdata[14]
    DIRECTION INPUT ;
    USE SIGNAL ;
    PORT
      LAYER Metal3 ;
        RECT 3115.580000 3598.260000 3115.780000 3598.980000 ;
    END
  END dma_axi_wdata[14]
  PIN dma_axi_wdata[13]
    DIRECTION INPUT ;
    USE SIGNAL ;
    PORT
      LAYER Metal3 ;
        RECT 3118.940000 3598.260000 3119.140000 3598.980000 ;
    END
  END dma_axi_wdata[13]
  PIN dma_axi_wdata[12]
    DIRECTION INPUT ;
    USE SIGNAL ;
    PORT
      LAYER Metal3 ;
        RECT 3121.820000 3598.260000 3122.020000 3598.980000 ;
    END
  END dma_axi_wdata[12]
  PIN dma_axi_wdata[11]
    DIRECTION INPUT ;
    USE SIGNAL ;
    PORT
      LAYER Metal3 ;
        RECT 3125.180000 3598.260000 3125.380000 3598.980000 ;
    END
  END dma_axi_wdata[11]
  PIN dma_axi_wdata[10]
    DIRECTION INPUT ;
    USE SIGNAL ;
    PORT
      LAYER Metal3 ;
        RECT 3128.540000 3598.260000 3128.740000 3598.980000 ;
    END
  END dma_axi_wdata[10]
  PIN dma_axi_wdata[9]
    DIRECTION INPUT ;
    USE SIGNAL ;
    PORT
      LAYER Metal3 ;
        RECT 3131.900000 3598.260000 3132.100000 3598.980000 ;
    END
  END dma_axi_wdata[9]
  PIN dma_axi_wdata[8]
    DIRECTION INPUT ;
    USE SIGNAL ;
    PORT
      LAYER Metal3 ;
        RECT 3135.260000 3598.260000 3135.460000 3598.980000 ;
    END
  END dma_axi_wdata[8]
  PIN dma_axi_wdata[7]
    DIRECTION INPUT ;
    USE SIGNAL ;
    PORT
      LAYER Metal3 ;
        RECT 3138.140000 3598.260000 3138.340000 3598.980000 ;
    END
  END dma_axi_wdata[7]
  PIN dma_axi_wdata[6]
    DIRECTION INPUT ;
    USE SIGNAL ;
    PORT
      LAYER Metal3 ;
        RECT 3141.500000 3598.260000 3141.700000 3598.980000 ;
    END
  END dma_axi_wdata[6]
  PIN dma_axi_wdata[5]
    DIRECTION INPUT ;
    USE SIGNAL ;
    PORT
      LAYER Metal3 ;
        RECT 3144.860000 3598.260000 3145.060000 3598.980000 ;
    END
  END dma_axi_wdata[5]
  PIN dma_axi_wdata[4]
    DIRECTION INPUT ;
    USE SIGNAL ;
    PORT
      LAYER Metal3 ;
        RECT 3148.220000 3598.260000 3148.420000 3598.980000 ;
    END
  END dma_axi_wdata[4]
  PIN dma_axi_wdata[3]
    DIRECTION INPUT ;
    USE SIGNAL ;
    PORT
      LAYER Metal3 ;
        RECT 3151.580000 3598.260000 3151.780000 3598.980000 ;
    END
  END dma_axi_wdata[3]
  PIN dma_axi_wdata[2]
    DIRECTION INPUT ;
    USE SIGNAL ;
    PORT
      LAYER Metal3 ;
        RECT 3154.460000 3598.260000 3154.660000 3598.980000 ;
    END
  END dma_axi_wdata[2]
  PIN dma_axi_wdata[1]
    DIRECTION INPUT ;
    USE SIGNAL ;
    PORT
      LAYER Metal3 ;
        RECT 3157.820000 3598.260000 3158.020000 3598.980000 ;
    END
  END dma_axi_wdata[1]
  PIN dma_axi_wdata[0]
    DIRECTION INPUT ;
    USE SIGNAL ;
    PORT
      LAYER Metal3 ;
        RECT 3161.180000 3598.260000 3161.380000 3598.980000 ;
    END
  END dma_axi_wdata[0]
  PIN dma_axi_wstrb[7]
    DIRECTION INPUT ;
    USE SIGNAL ;
    PORT
      LAYER Metal3 ;
        RECT 3164.540000 3598.260000 3164.740000 3598.980000 ;
    END
  END dma_axi_wstrb[7]
  PIN dma_axi_wstrb[6]
    DIRECTION INPUT ;
    USE SIGNAL ;
    PORT
      LAYER Metal3 ;
        RECT 3167.900000 3598.260000 3168.100000 3598.980000 ;
    END
  END dma_axi_wstrb[6]
  PIN dma_axi_wstrb[5]
    DIRECTION INPUT ;
    USE SIGNAL ;
    PORT
      LAYER Metal3 ;
        RECT 3170.780000 3598.260000 3170.980000 3598.980000 ;
    END
  END dma_axi_wstrb[5]
  PIN dma_axi_wstrb[4]
    DIRECTION INPUT ;
    USE SIGNAL ;
    PORT
      LAYER Metal3 ;
        RECT 3174.140000 3598.260000 3174.340000 3598.980000 ;
    END
  END dma_axi_wstrb[4]
  PIN dma_axi_wstrb[3]
    DIRECTION INPUT ;
    USE SIGNAL ;
    PORT
      LAYER Metal3 ;
        RECT 3177.500000 3598.260000 3177.700000 3598.980000 ;
    END
  END dma_axi_wstrb[3]
  PIN dma_axi_wstrb[2]
    DIRECTION INPUT ;
    USE SIGNAL ;
    PORT
      LAYER Metal3 ;
        RECT 3180.860000 3598.260000 3181.060000 3598.980000 ;
    END
  END dma_axi_wstrb[2]
  PIN dma_axi_wstrb[1]
    DIRECTION INPUT ;
    USE SIGNAL ;
    PORT
      LAYER Metal3 ;
        RECT 3183.740000 3598.260000 3183.940000 3598.980000 ;
    END
  END dma_axi_wstrb[1]
  PIN dma_axi_wstrb[0]
    DIRECTION INPUT ;
    USE SIGNAL ;
    PORT
      LAYER Metal3 ;
        RECT 3187.100000 3598.260000 3187.300000 3598.980000 ;
    END
  END dma_axi_wstrb[0]
  PIN dma_axi_wlast
    DIRECTION INPUT ;
    USE SIGNAL ;
    PORT
      LAYER Metal3 ;
        RECT 3190.460000 3598.260000 3190.660000 3598.980000 ;
    END
  END dma_axi_wlast
  PIN dma_axi_bvalid
    DIRECTION OUTPUT ;
    USE SIGNAL ;
    PORT
      LAYER Metal3 ;
        RECT 3193.820000 3598.260000 3194.020000 3598.980000 ;
    END
  END dma_axi_bvalid
  PIN dma_axi_bready
    DIRECTION INPUT ;
    USE SIGNAL ;
    PORT
      LAYER Metal3 ;
        RECT 3197.180000 3598.260000 3197.380000 3598.980000 ;
    END
  END dma_axi_bready
  PIN dma_axi_bresp[1]
    DIRECTION OUTPUT ;
    USE SIGNAL ;
    PORT
      LAYER Metal3 ;
        RECT 3200.060000 3598.260000 3200.260000 3598.980000 ;
    END
  END dma_axi_bresp[1]
  PIN dma_axi_bresp[0]
    DIRECTION OUTPUT ;
    USE SIGNAL ;
    PORT
      LAYER Metal3 ;
        RECT 3203.420000 3598.260000 3203.620000 3598.980000 ;
    END
  END dma_axi_bresp[0]
  PIN dma_axi_bid[0]
    DIRECTION OUTPUT ;
    USE SIGNAL ;
    PORT
      LAYER Metal3 ;
        RECT 3206.780000 3598.260000 3206.980000 3598.980000 ;
    END
  END dma_axi_bid[0]
  PIN dma_axi_arvalid
    DIRECTION INPUT ;
    USE SIGNAL ;
    PORT
      LAYER Metal3 ;
        RECT 3210.140000 3598.260000 3210.340000 3598.980000 ;
    END
  END dma_axi_arvalid
  PIN dma_axi_arready
    DIRECTION OUTPUT ;
    USE SIGNAL ;
    PORT
      LAYER Metal3 ;
        RECT 3213.500000 3598.260000 3213.700000 3598.980000 ;
    END
  END dma_axi_arready
  PIN dma_axi_arid[0]
    DIRECTION INPUT ;
    USE SIGNAL ;
    PORT
      LAYER Metal3 ;
        RECT 3216.380000 3598.260000 3216.580000 3598.980000 ;
    END
  END dma_axi_arid[0]
  PIN dma_axi_araddr[31]
    DIRECTION INPUT ;
    USE SIGNAL ;
    PORT
      LAYER Metal3 ;
        RECT 3219.740000 3598.260000 3219.940000 3598.980000 ;
    END
  END dma_axi_araddr[31]
  PIN dma_axi_araddr[30]
    DIRECTION INPUT ;
    USE SIGNAL ;
    PORT
      LAYER Metal3 ;
        RECT 3223.100000 3598.260000 3223.300000 3598.980000 ;
    END
  END dma_axi_araddr[30]
  PIN dma_axi_araddr[29]
    DIRECTION INPUT ;
    USE SIGNAL ;
    PORT
      LAYER Metal3 ;
        RECT 3226.460000 3598.260000 3226.660000 3598.980000 ;
    END
  END dma_axi_araddr[29]
  PIN dma_axi_araddr[28]
    DIRECTION INPUT ;
    USE SIGNAL ;
    PORT
      LAYER Metal3 ;
        RECT 3229.820000 3598.260000 3230.020000 3598.980000 ;
    END
  END dma_axi_araddr[28]
  PIN dma_axi_araddr[27]
    DIRECTION INPUT ;
    USE SIGNAL ;
    PORT
      LAYER Metal3 ;
        RECT 3232.700000 3598.260000 3232.900000 3598.980000 ;
    END
  END dma_axi_araddr[27]
  PIN dma_axi_araddr[26]
    DIRECTION INPUT ;
    USE SIGNAL ;
    PORT
      LAYER Metal3 ;
        RECT 3236.060000 3598.260000 3236.260000 3598.980000 ;
    END
  END dma_axi_araddr[26]
  PIN dma_axi_araddr[25]
    DIRECTION INPUT ;
    USE SIGNAL ;
    PORT
      LAYER Metal3 ;
        RECT 3239.420000 3598.260000 3239.620000 3598.980000 ;
    END
  END dma_axi_araddr[25]
  PIN dma_axi_araddr[24]
    DIRECTION INPUT ;
    USE SIGNAL ;
    PORT
      LAYER Metal3 ;
        RECT 3242.780000 3598.260000 3242.980000 3598.980000 ;
    END
  END dma_axi_araddr[24]
  PIN dma_axi_araddr[23]
    DIRECTION INPUT ;
    USE SIGNAL ;
    PORT
      LAYER Metal3 ;
        RECT 3245.660000 3598.260000 3245.860000 3598.980000 ;
    END
  END dma_axi_araddr[23]
  PIN dma_axi_araddr[22]
    DIRECTION INPUT ;
    USE SIGNAL ;
    PORT
      LAYER Metal3 ;
        RECT 3249.020000 3598.260000 3249.220000 3598.980000 ;
    END
  END dma_axi_araddr[22]
  PIN dma_axi_araddr[21]
    DIRECTION INPUT ;
    USE SIGNAL ;
    PORT
      LAYER Metal3 ;
        RECT 3252.380000 3598.260000 3252.580000 3598.980000 ;
    END
  END dma_axi_araddr[21]
  PIN dma_axi_araddr[20]
    DIRECTION INPUT ;
    USE SIGNAL ;
    PORT
      LAYER Metal3 ;
        RECT 3255.740000 3598.260000 3255.940000 3598.980000 ;
    END
  END dma_axi_araddr[20]
  PIN dma_axi_araddr[19]
    DIRECTION INPUT ;
    USE SIGNAL ;
    PORT
      LAYER Metal3 ;
        RECT 3259.100000 3598.260000 3259.300000 3598.980000 ;
    END
  END dma_axi_araddr[19]
  PIN dma_axi_araddr[18]
    DIRECTION INPUT ;
    USE SIGNAL ;
    PORT
      LAYER Metal3 ;
        RECT 3261.980000 3598.260000 3262.180000 3598.980000 ;
    END
  END dma_axi_araddr[18]
  PIN dma_axi_araddr[17]
    DIRECTION INPUT ;
    USE SIGNAL ;
    PORT
      LAYER Metal3 ;
        RECT 3265.340000 3598.260000 3265.540000 3598.980000 ;
    END
  END dma_axi_araddr[17]
  PIN dma_axi_araddr[16]
    DIRECTION INPUT ;
    USE SIGNAL ;
    PORT
      LAYER Metal3 ;
        RECT 3268.700000 3598.260000 3268.900000 3598.980000 ;
    END
  END dma_axi_araddr[16]
  PIN dma_axi_araddr[15]
    DIRECTION INPUT ;
    USE SIGNAL ;
    PORT
      LAYER Metal3 ;
        RECT 3272.060000 3598.260000 3272.260000 3598.980000 ;
    END
  END dma_axi_araddr[15]
  PIN dma_axi_araddr[14]
    DIRECTION INPUT ;
    USE SIGNAL ;
    PORT
      LAYER Metal3 ;
        RECT 3275.420000 3598.260000 3275.620000 3598.980000 ;
    END
  END dma_axi_araddr[14]
  PIN dma_axi_araddr[13]
    DIRECTION INPUT ;
    USE SIGNAL ;
    PORT
      LAYER Metal3 ;
        RECT 3278.300000 3598.260000 3278.500000 3598.980000 ;
    END
  END dma_axi_araddr[13]
  PIN dma_axi_araddr[12]
    DIRECTION INPUT ;
    USE SIGNAL ;
    PORT
      LAYER Metal3 ;
        RECT 3281.660000 3598.260000 3281.860000 3598.980000 ;
    END
  END dma_axi_araddr[12]
  PIN dma_axi_araddr[11]
    DIRECTION INPUT ;
    USE SIGNAL ;
    PORT
      LAYER Metal3 ;
        RECT 3285.020000 3598.260000 3285.220000 3598.980000 ;
    END
  END dma_axi_araddr[11]
  PIN dma_axi_araddr[10]
    DIRECTION INPUT ;
    USE SIGNAL ;
    PORT
      LAYER Metal3 ;
        RECT 3288.380000 3598.260000 3288.580000 3598.980000 ;
    END
  END dma_axi_araddr[10]
  PIN dma_axi_araddr[9]
    DIRECTION INPUT ;
    USE SIGNAL ;
    PORT
      LAYER Metal3 ;
        RECT 3291.740000 3598.260000 3291.940000 3598.980000 ;
    END
  END dma_axi_araddr[9]
  PIN dma_axi_araddr[8]
    DIRECTION INPUT ;
    USE SIGNAL ;
    PORT
      LAYER Metal3 ;
        RECT 3294.620000 3598.260000 3294.820000 3598.980000 ;
    END
  END dma_axi_araddr[8]
  PIN dma_axi_araddr[7]
    DIRECTION INPUT ;
    USE SIGNAL ;
    PORT
      LAYER Metal3 ;
        RECT 3297.980000 3598.260000 3298.180000 3598.980000 ;
    END
  END dma_axi_araddr[7]
  PIN dma_axi_araddr[6]
    DIRECTION INPUT ;
    USE SIGNAL ;
    PORT
      LAYER Metal3 ;
        RECT 3301.340000 3598.260000 3301.540000 3598.980000 ;
    END
  END dma_axi_araddr[6]
  PIN dma_axi_araddr[5]
    DIRECTION INPUT ;
    USE SIGNAL ;
    PORT
      LAYER Metal3 ;
        RECT 3304.700000 3598.260000 3304.900000 3598.980000 ;
    END
  END dma_axi_araddr[5]
  PIN dma_axi_araddr[4]
    DIRECTION INPUT ;
    USE SIGNAL ;
    PORT
      LAYER Metal3 ;
        RECT 3307.580000 3598.260000 3307.780000 3598.980000 ;
    END
  END dma_axi_araddr[4]
  PIN dma_axi_araddr[3]
    DIRECTION INPUT ;
    USE SIGNAL ;
    PORT
      LAYER Metal3 ;
        RECT 3310.940000 3598.260000 3311.140000 3598.980000 ;
    END
  END dma_axi_araddr[3]
  PIN dma_axi_araddr[2]
    DIRECTION INPUT ;
    USE SIGNAL ;
    PORT
      LAYER Metal3 ;
        RECT 3314.300000 3598.260000 3314.500000 3598.980000 ;
    END
  END dma_axi_araddr[2]
  PIN dma_axi_araddr[1]
    DIRECTION INPUT ;
    USE SIGNAL ;
    PORT
      LAYER Metal3 ;
        RECT 3317.660000 3598.260000 3317.860000 3598.980000 ;
    END
  END dma_axi_araddr[1]
  PIN dma_axi_araddr[0]
    DIRECTION INPUT ;
    USE SIGNAL ;
    PORT
      LAYER Metal3 ;
        RECT 3321.020000 3598.260000 3321.220000 3598.980000 ;
    END
  END dma_axi_araddr[0]
  PIN dma_axi_arsize[2]
    DIRECTION INPUT ;
    USE SIGNAL ;
    PORT
      LAYER Metal3 ;
        RECT 3323.900000 3598.260000 3324.100000 3598.980000 ;
    END
  END dma_axi_arsize[2]
  PIN dma_axi_arsize[1]
    DIRECTION INPUT ;
    USE SIGNAL ;
    PORT
      LAYER Metal3 ;
        RECT 3327.260000 3598.260000 3327.460000 3598.980000 ;
    END
  END dma_axi_arsize[1]
  PIN dma_axi_arsize[0]
    DIRECTION INPUT ;
    USE SIGNAL ;
    PORT
      LAYER Metal3 ;
        RECT 3330.620000 3598.260000 3330.820000 3598.980000 ;
    END
  END dma_axi_arsize[0]
  PIN dma_axi_arprot[2]
    DIRECTION INPUT ;
    USE SIGNAL ;
    PORT
      LAYER Metal3 ;
        RECT 3333.980000 3598.260000 3334.180000 3598.980000 ;
    END
  END dma_axi_arprot[2]
  PIN dma_axi_arprot[1]
    DIRECTION INPUT ;
    USE SIGNAL ;
    PORT
      LAYER Metal3 ;
        RECT 3337.340000 3598.260000 3337.540000 3598.980000 ;
    END
  END dma_axi_arprot[1]
  PIN dma_axi_arprot[0]
    DIRECTION INPUT ;
    USE SIGNAL ;
    PORT
      LAYER Metal3 ;
        RECT 3340.220000 3598.260000 3340.420000 3598.980000 ;
    END
  END dma_axi_arprot[0]
  PIN dma_axi_arlen[7]
    DIRECTION INPUT ;
    USE SIGNAL ;
    PORT
      LAYER Metal3 ;
        RECT 3343.580000 3598.260000 3343.780000 3598.980000 ;
    END
  END dma_axi_arlen[7]
  PIN dma_axi_arlen[6]
    DIRECTION INPUT ;
    USE SIGNAL ;
    PORT
      LAYER Metal3 ;
        RECT 3346.940000 3598.260000 3347.140000 3598.980000 ;
    END
  END dma_axi_arlen[6]
  PIN dma_axi_arlen[5]
    DIRECTION INPUT ;
    USE SIGNAL ;
    PORT
      LAYER Metal3 ;
        RECT 3350.300000 3598.260000 3350.500000 3598.980000 ;
    END
  END dma_axi_arlen[5]
  PIN dma_axi_arlen[4]
    DIRECTION INPUT ;
    USE SIGNAL ;
    PORT
      LAYER Metal3 ;
        RECT 3353.660000 3598.260000 3353.860000 3598.980000 ;
    END
  END dma_axi_arlen[4]
  PIN dma_axi_arlen[3]
    DIRECTION INPUT ;
    USE SIGNAL ;
    PORT
      LAYER Metal3 ;
        RECT 3356.540000 3598.260000 3356.740000 3598.980000 ;
    END
  END dma_axi_arlen[3]
  PIN dma_axi_arlen[2]
    DIRECTION INPUT ;
    USE SIGNAL ;
    PORT
      LAYER Metal3 ;
        RECT 3359.900000 3598.260000 3360.100000 3598.980000 ;
    END
  END dma_axi_arlen[2]
  PIN dma_axi_arlen[1]
    DIRECTION INPUT ;
    USE SIGNAL ;
    PORT
      LAYER Metal3 ;
        RECT 3363.260000 3598.260000 3363.460000 3598.980000 ;
    END
  END dma_axi_arlen[1]
  PIN dma_axi_arlen[0]
    DIRECTION INPUT ;
    USE SIGNAL ;
    PORT
      LAYER Metal3 ;
        RECT 3366.620000 3598.260000 3366.820000 3598.980000 ;
    END
  END dma_axi_arlen[0]
  PIN dma_axi_arburst[1]
    DIRECTION INPUT ;
    USE SIGNAL ;
    PORT
      LAYER Metal3 ;
        RECT 3369.500000 3598.260000 3369.700000 3598.980000 ;
    END
  END dma_axi_arburst[1]
  PIN dma_axi_arburst[0]
    DIRECTION INPUT ;
    USE SIGNAL ;
    PORT
      LAYER Metal3 ;
        RECT 3372.860000 3598.260000 3373.060000 3598.980000 ;
    END
  END dma_axi_arburst[0]
  PIN dma_axi_rvalid
    DIRECTION OUTPUT ;
    USE SIGNAL ;
    PORT
      LAYER Metal3 ;
        RECT 3376.220000 3598.260000 3376.420000 3598.980000 ;
    END
  END dma_axi_rvalid
  PIN dma_axi_rready
    DIRECTION INPUT ;
    USE SIGNAL ;
    PORT
      LAYER Metal3 ;
        RECT 3379.580000 3598.260000 3379.780000 3598.980000 ;
    END
  END dma_axi_rready
  PIN dma_axi_rid[0]
    DIRECTION OUTPUT ;
    USE SIGNAL ;
    PORT
      LAYER Metal3 ;
        RECT 3382.940000 3598.260000 3383.140000 3598.980000 ;
    END
  END dma_axi_rid[0]
  PIN dma_axi_rdata[63]
    DIRECTION OUTPUT ;
    USE SIGNAL ;
    PORT
      LAYER Metal3 ;
        RECT 3385.820000 3598.260000 3386.020000 3598.980000 ;
    END
  END dma_axi_rdata[63]
  PIN dma_axi_rdata[62]
    DIRECTION OUTPUT ;
    USE SIGNAL ;
    PORT
      LAYER Metal3 ;
        RECT 3389.180000 3598.260000 3389.380000 3598.980000 ;
    END
  END dma_axi_rdata[62]
  PIN dma_axi_rdata[61]
    DIRECTION OUTPUT ;
    USE SIGNAL ;
    PORT
      LAYER Metal3 ;
        RECT 3392.540000 3598.260000 3392.740000 3598.980000 ;
    END
  END dma_axi_rdata[61]
  PIN dma_axi_rdata[60]
    DIRECTION OUTPUT ;
    USE SIGNAL ;
    PORT
      LAYER Metal3 ;
        RECT 3395.900000 3598.260000 3396.100000 3598.980000 ;
    END
  END dma_axi_rdata[60]
  PIN dma_axi_rdata[59]
    DIRECTION OUTPUT ;
    USE SIGNAL ;
    PORT
      LAYER Metal3 ;
        RECT 3399.260000 3598.260000 3399.460000 3598.980000 ;
    END
  END dma_axi_rdata[59]
  PIN dma_axi_rdata[58]
    DIRECTION OUTPUT ;
    USE SIGNAL ;
    PORT
      LAYER Metal3 ;
        RECT 3402.140000 3598.260000 3402.340000 3598.980000 ;
    END
  END dma_axi_rdata[58]
  PIN dma_axi_rdata[57]
    DIRECTION OUTPUT ;
    USE SIGNAL ;
    PORT
      LAYER Metal3 ;
        RECT 3405.500000 3598.260000 3405.700000 3598.980000 ;
    END
  END dma_axi_rdata[57]
  PIN dma_axi_rdata[56]
    DIRECTION OUTPUT ;
    USE SIGNAL ;
    PORT
      LAYER Metal3 ;
        RECT 3408.860000 3598.260000 3409.060000 3598.980000 ;
    END
  END dma_axi_rdata[56]
  PIN dma_axi_rdata[55]
    DIRECTION OUTPUT ;
    USE SIGNAL ;
    PORT
      LAYER Metal3 ;
        RECT 3412.220000 3598.260000 3412.420000 3598.980000 ;
    END
  END dma_axi_rdata[55]
  PIN dma_axi_rdata[54]
    DIRECTION OUTPUT ;
    USE SIGNAL ;
    PORT
      LAYER Metal3 ;
        RECT 3415.580000 3598.260000 3415.780000 3598.980000 ;
    END
  END dma_axi_rdata[54]
  PIN dma_axi_rdata[53]
    DIRECTION OUTPUT ;
    USE SIGNAL ;
    PORT
      LAYER Metal3 ;
        RECT 3418.460000 3598.260000 3418.660000 3598.980000 ;
    END
  END dma_axi_rdata[53]
  PIN dma_axi_rdata[52]
    DIRECTION OUTPUT ;
    USE SIGNAL ;
    PORT
      LAYER Metal3 ;
        RECT 3421.820000 3598.260000 3422.020000 3598.980000 ;
    END
  END dma_axi_rdata[52]
  PIN dma_axi_rdata[51]
    DIRECTION OUTPUT ;
    USE SIGNAL ;
    PORT
      LAYER Metal3 ;
        RECT 3425.180000 3598.260000 3425.380000 3598.980000 ;
    END
  END dma_axi_rdata[51]
  PIN dma_axi_rdata[50]
    DIRECTION OUTPUT ;
    USE SIGNAL ;
    PORT
      LAYER Metal3 ;
        RECT 3428.540000 3598.260000 3428.740000 3598.980000 ;
    END
  END dma_axi_rdata[50]
  PIN dma_axi_rdata[49]
    DIRECTION OUTPUT ;
    USE SIGNAL ;
    PORT
      LAYER Metal3 ;
        RECT 3431.420000 3598.260000 3431.620000 3598.980000 ;
    END
  END dma_axi_rdata[49]
  PIN dma_axi_rdata[48]
    DIRECTION OUTPUT ;
    USE SIGNAL ;
    PORT
      LAYER Metal3 ;
        RECT 3434.780000 3598.260000 3434.980000 3598.980000 ;
    END
  END dma_axi_rdata[48]
  PIN dma_axi_rdata[47]
    DIRECTION OUTPUT ;
    USE SIGNAL ;
    PORT
      LAYER Metal3 ;
        RECT 3438.140000 3598.260000 3438.340000 3598.980000 ;
    END
  END dma_axi_rdata[47]
  PIN dma_axi_rdata[46]
    DIRECTION OUTPUT ;
    USE SIGNAL ;
    PORT
      LAYER Metal3 ;
        RECT 3441.500000 3598.260000 3441.700000 3598.980000 ;
    END
  END dma_axi_rdata[46]
  PIN dma_axi_rdata[45]
    DIRECTION OUTPUT ;
    USE SIGNAL ;
    PORT
      LAYER Metal3 ;
        RECT 3444.860000 3598.260000 3445.060000 3598.980000 ;
    END
  END dma_axi_rdata[45]
  PIN dma_axi_rdata[44]
    DIRECTION OUTPUT ;
    USE SIGNAL ;
    PORT
      LAYER Metal3 ;
        RECT 3447.740000 3598.260000 3447.940000 3598.980000 ;
    END
  END dma_axi_rdata[44]
  PIN dma_axi_rdata[43]
    DIRECTION OUTPUT ;
    USE SIGNAL ;
    PORT
      LAYER Metal3 ;
        RECT 3451.100000 3598.260000 3451.300000 3598.980000 ;
    END
  END dma_axi_rdata[43]
  PIN dma_axi_rdata[42]
    DIRECTION OUTPUT ;
    USE SIGNAL ;
    PORT
      LAYER Metal3 ;
        RECT 3454.460000 3598.260000 3454.660000 3598.980000 ;
    END
  END dma_axi_rdata[42]
  PIN dma_axi_rdata[41]
    DIRECTION OUTPUT ;
    USE SIGNAL ;
    PORT
      LAYER Metal3 ;
        RECT 3457.820000 3598.260000 3458.020000 3598.980000 ;
    END
  END dma_axi_rdata[41]
  PIN dma_axi_rdata[40]
    DIRECTION OUTPUT ;
    USE SIGNAL ;
    PORT
      LAYER Metal3 ;
        RECT 3461.180000 3598.260000 3461.380000 3598.980000 ;
    END
  END dma_axi_rdata[40]
  PIN dma_axi_rdata[39]
    DIRECTION OUTPUT ;
    USE SIGNAL ;
    PORT
      LAYER Metal3 ;
        RECT 3464.060000 3598.260000 3464.260000 3598.980000 ;
    END
  END dma_axi_rdata[39]
  PIN dma_axi_rdata[38]
    DIRECTION OUTPUT ;
    USE SIGNAL ;
    PORT
      LAYER Metal3 ;
        RECT 3467.420000 3598.260000 3467.620000 3598.980000 ;
    END
  END dma_axi_rdata[38]
  PIN dma_axi_rdata[37]
    DIRECTION OUTPUT ;
    USE SIGNAL ;
    PORT
      LAYER Metal3 ;
        RECT 3470.780000 3598.260000 3470.980000 3598.980000 ;
    END
  END dma_axi_rdata[37]
  PIN dma_axi_rdata[36]
    DIRECTION OUTPUT ;
    USE SIGNAL ;
    PORT
      LAYER Metal3 ;
        RECT 3474.140000 3598.260000 3474.340000 3598.980000 ;
    END
  END dma_axi_rdata[36]
  PIN dma_axi_rdata[35]
    DIRECTION OUTPUT ;
    USE SIGNAL ;
    PORT
      LAYER Metal3 ;
        RECT 3477.500000 3598.260000 3477.700000 3598.980000 ;
    END
  END dma_axi_rdata[35]
  PIN dma_axi_rdata[34]
    DIRECTION OUTPUT ;
    USE SIGNAL ;
    PORT
      LAYER Metal3 ;
        RECT 3480.380000 3598.260000 3480.580000 3598.980000 ;
    END
  END dma_axi_rdata[34]
  PIN dma_axi_rdata[33]
    DIRECTION OUTPUT ;
    USE SIGNAL ;
    PORT
      LAYER Metal3 ;
        RECT 3483.740000 3598.260000 3483.940000 3598.980000 ;
    END
  END dma_axi_rdata[33]
  PIN dma_axi_rdata[32]
    DIRECTION OUTPUT ;
    USE SIGNAL ;
    PORT
      LAYER Metal3 ;
        RECT 3487.100000 3598.260000 3487.300000 3598.980000 ;
    END
  END dma_axi_rdata[32]
  PIN dma_axi_rdata[31]
    DIRECTION OUTPUT ;
    USE SIGNAL ;
    PORT
      LAYER Metal3 ;
        RECT 3490.460000 3598.260000 3490.660000 3598.980000 ;
    END
  END dma_axi_rdata[31]
  PIN dma_axi_rdata[30]
    DIRECTION OUTPUT ;
    USE SIGNAL ;
    PORT
      LAYER Metal3 ;
        RECT 3493.340000 3598.260000 3493.540000 3598.980000 ;
    END
  END dma_axi_rdata[30]
  PIN dma_axi_rdata[29]
    DIRECTION OUTPUT ;
    USE SIGNAL ;
    PORT
      LAYER Metal3 ;
        RECT 3496.700000 3598.260000 3496.900000 3598.980000 ;
    END
  END dma_axi_rdata[29]
  PIN dma_axi_rdata[28]
    DIRECTION OUTPUT ;
    USE SIGNAL ;
    PORT
      LAYER Metal3 ;
        RECT 3500.060000 3598.260000 3500.260000 3598.980000 ;
    END
  END dma_axi_rdata[28]
  PIN dma_axi_rdata[27]
    DIRECTION OUTPUT ;
    USE SIGNAL ;
    PORT
      LAYER Metal3 ;
        RECT 3503.420000 3598.260000 3503.620000 3598.980000 ;
    END
  END dma_axi_rdata[27]
  PIN dma_axi_rdata[26]
    DIRECTION OUTPUT ;
    USE SIGNAL ;
    PORT
      LAYER Metal3 ;
        RECT 3506.780000 3598.260000 3506.980000 3598.980000 ;
    END
  END dma_axi_rdata[26]
  PIN dma_axi_rdata[25]
    DIRECTION OUTPUT ;
    USE SIGNAL ;
    PORT
      LAYER Metal3 ;
        RECT 3509.660000 3598.260000 3509.860000 3598.980000 ;
    END
  END dma_axi_rdata[25]
  PIN dma_axi_rdata[24]
    DIRECTION OUTPUT ;
    USE SIGNAL ;
    PORT
      LAYER Metal3 ;
        RECT 3513.020000 3598.260000 3513.220000 3598.980000 ;
    END
  END dma_axi_rdata[24]
  PIN dma_axi_rdata[23]
    DIRECTION OUTPUT ;
    USE SIGNAL ;
    PORT
      LAYER Metal3 ;
        RECT 3516.380000 3598.260000 3516.580000 3598.980000 ;
    END
  END dma_axi_rdata[23]
  PIN dma_axi_rdata[22]
    DIRECTION OUTPUT ;
    USE SIGNAL ;
    PORT
      LAYER Metal3 ;
        RECT 3519.740000 3598.260000 3519.940000 3598.980000 ;
    END
  END dma_axi_rdata[22]
  PIN dma_axi_rdata[21]
    DIRECTION OUTPUT ;
    USE SIGNAL ;
    PORT
      LAYER Metal3 ;
        RECT 3523.100000 3598.260000 3523.300000 3598.980000 ;
    END
  END dma_axi_rdata[21]
  PIN dma_axi_rdata[20]
    DIRECTION OUTPUT ;
    USE SIGNAL ;
    PORT
      LAYER Metal3 ;
        RECT 3525.980000 3598.260000 3526.180000 3598.980000 ;
    END
  END dma_axi_rdata[20]
  PIN dma_axi_rdata[19]
    DIRECTION OUTPUT ;
    USE SIGNAL ;
    PORT
      LAYER Metal3 ;
        RECT 3529.340000 3598.260000 3529.540000 3598.980000 ;
    END
  END dma_axi_rdata[19]
  PIN dma_axi_rdata[18]
    DIRECTION OUTPUT ;
    USE SIGNAL ;
    PORT
      LAYER Metal3 ;
        RECT 3532.700000 3598.260000 3532.900000 3598.980000 ;
    END
  END dma_axi_rdata[18]
  PIN dma_axi_rdata[17]
    DIRECTION OUTPUT ;
    USE SIGNAL ;
    PORT
      LAYER Metal3 ;
        RECT 3536.060000 3598.260000 3536.260000 3598.980000 ;
    END
  END dma_axi_rdata[17]
  PIN dma_axi_rdata[16]
    DIRECTION OUTPUT ;
    USE SIGNAL ;
    PORT
      LAYER Metal3 ;
        RECT 3539.420000 3598.260000 3539.620000 3598.980000 ;
    END
  END dma_axi_rdata[16]
  PIN dma_axi_rdata[15]
    DIRECTION OUTPUT ;
    USE SIGNAL ;
    PORT
      LAYER Metal3 ;
        RECT 3542.300000 3598.260000 3542.500000 3598.980000 ;
    END
  END dma_axi_rdata[15]
  PIN dma_axi_rdata[14]
    DIRECTION OUTPUT ;
    USE SIGNAL ;
    PORT
      LAYER Metal3 ;
        RECT 3545.660000 3598.260000 3545.860000 3598.980000 ;
    END
  END dma_axi_rdata[14]
  PIN dma_axi_rdata[13]
    DIRECTION OUTPUT ;
    USE SIGNAL ;
    PORT
      LAYER Metal3 ;
        RECT 3549.020000 3598.260000 3549.220000 3598.980000 ;
    END
  END dma_axi_rdata[13]
  PIN dma_axi_rdata[12]
    DIRECTION OUTPUT ;
    USE SIGNAL ;
    PORT
      LAYER Metal3 ;
        RECT 3552.380000 3598.260000 3552.580000 3598.980000 ;
    END
  END dma_axi_rdata[12]
  PIN dma_axi_rdata[11]
    DIRECTION OUTPUT ;
    USE SIGNAL ;
    PORT
      LAYER Metal3 ;
        RECT 3555.260000 3598.260000 3555.460000 3598.980000 ;
    END
  END dma_axi_rdata[11]
  PIN dma_axi_rdata[10]
    DIRECTION OUTPUT ;
    USE SIGNAL ;
    PORT
      LAYER Metal3 ;
        RECT 3558.620000 3598.260000 3558.820000 3598.980000 ;
    END
  END dma_axi_rdata[10]
  PIN dma_axi_rdata[9]
    DIRECTION OUTPUT ;
    USE SIGNAL ;
    PORT
      LAYER Metal3 ;
        RECT 3561.980000 3598.260000 3562.180000 3598.980000 ;
    END
  END dma_axi_rdata[9]
  PIN dma_axi_rdata[8]
    DIRECTION OUTPUT ;
    USE SIGNAL ;
    PORT
      LAYER Metal3 ;
        RECT 3565.340000 3598.260000 3565.540000 3598.980000 ;
    END
  END dma_axi_rdata[8]
  PIN dma_axi_rdata[7]
    DIRECTION OUTPUT ;
    USE SIGNAL ;
    PORT
      LAYER Metal3 ;
        RECT 3568.700000 3598.260000 3568.900000 3598.980000 ;
    END
  END dma_axi_rdata[7]
  PIN dma_axi_rdata[6]
    DIRECTION OUTPUT ;
    USE SIGNAL ;
    PORT
      LAYER Metal3 ;
        RECT 3571.580000 3598.260000 3571.780000 3598.980000 ;
    END
  END dma_axi_rdata[6]
  PIN dma_axi_rdata[5]
    DIRECTION OUTPUT ;
    USE SIGNAL ;
    PORT
      LAYER Metal3 ;
        RECT 3574.940000 3598.260000 3575.140000 3598.980000 ;
    END
  END dma_axi_rdata[5]
  PIN dma_axi_rdata[4]
    DIRECTION OUTPUT ;
    USE SIGNAL ;
    PORT
      LAYER Metal3 ;
        RECT 3576.860000 3598.260000 3577.060000 3598.980000 ;
    END
  END dma_axi_rdata[4]
  PIN dma_axi_rdata[3]
    DIRECTION OUTPUT ;
    USE SIGNAL ;
    PORT
      LAYER Metal3 ;
        RECT 3580.220000 3598.260000 3580.420000 3598.980000 ;
    END
  END dma_axi_rdata[3]
  PIN dma_axi_rdata[2]
    DIRECTION OUTPUT ;
    USE SIGNAL ;
    PORT
      LAYER Metal3 ;
        RECT 3583.100000 3598.260000 3583.300000 3598.980000 ;
    END
  END dma_axi_rdata[2]
  PIN dma_axi_rdata[1]
    DIRECTION OUTPUT ;
    USE SIGNAL ;
    PORT
      LAYER Metal3 ;
        RECT 3586.460000 3598.260000 3586.660000 3598.980000 ;
    END
  END dma_axi_rdata[1]
  PIN dma_axi_rdata[0]
    DIRECTION OUTPUT ;
    USE SIGNAL ;
    PORT
      LAYER Metal3 ;
        RECT 3589.340000 3598.260000 3589.540000 3598.980000 ;
    END
  END dma_axi_rdata[0]
  PIN dma_axi_rresp[1]
    DIRECTION OUTPUT ;
    USE SIGNAL ;
    PORT
      LAYER Metal3 ;
        RECT 3592.700000 3598.260000 3592.900000 3598.980000 ;
    END
  END dma_axi_rresp[1]
  PIN dma_axi_rresp[0]
    DIRECTION OUTPUT ;
    USE SIGNAL ;
    PORT
      LAYER Metal3 ;
        RECT 3595.100000 3598.260000 3595.300000 3598.980000 ;
    END
  END dma_axi_rresp[0]
  PIN dma_axi_rlast
    DIRECTION OUTPUT ;
    USE SIGNAL ;
    PORT
      LAYER Metal3 ;
        RECT 3597.980000 3598.260000 3598.180000 3598.980000 ;
    END
  END dma_axi_rlast
  PIN lsu_bus_clk_en
    DIRECTION INPUT ;
    USE SIGNAL ;
    PORT
      LAYER Metal2 ;
        RECT 0.000000 1871.420000 0.720000 1871.620000 ;
    END
  END lsu_bus_clk_en
  PIN ifu_bus_clk_en
    DIRECTION INPUT ;
    USE SIGNAL ;
    PORT
      LAYER Metal4 ;
        RECT 0.000000 1871.420000 0.720000 1871.620000 ;
    END
  END ifu_bus_clk_en
  PIN dbg_bus_clk_en
    DIRECTION INPUT ;
    USE SIGNAL ;
    PORT
      LAYER Metal2 ;
        RECT 3601.200000 1871.420000 3601.920000 1871.620000 ;
    END
  END dbg_bus_clk_en
  PIN dma_bus_clk_en
    DIRECTION INPUT ;
    USE SIGNAL ;
    PORT
      LAYER Metal4 ;
        RECT 3601.200000 1871.420000 3601.920000 1871.620000 ;
    END
  END dma_bus_clk_en
  PIN timer_int
    DIRECTION INPUT ;
    USE SIGNAL ;
    PORT
      LAYER Metal2 ;
        RECT 0.000000 1726.940000 0.720000 1727.140000 ;
    END
  END timer_int
  PIN extintsrc_req[8]
    DIRECTION INPUT ;
    USE SIGNAL ;
    PORT
      LAYER Metal4 ;
        RECT 3601.200000 1821.020000 3601.920000 1821.220000 ;
    END
  END extintsrc_req[8]
  PIN extintsrc_req[7]
    DIRECTION INPUT ;
    USE SIGNAL ;
    PORT
      LAYER Metal2 ;
        RECT 0.000000 1777.340000 0.720000 1777.540000 ;
    END
  END extintsrc_req[7]
  PIN extintsrc_req[6]
    DIRECTION INPUT ;
    USE SIGNAL ;
    PORT
      LAYER Metal4 ;
        RECT 0.000000 1777.340000 0.720000 1777.540000 ;
    END
  END extintsrc_req[6]
  PIN extintsrc_req[5]
    DIRECTION INPUT ;
    USE SIGNAL ;
    PORT
      LAYER Metal2 ;
        RECT 3601.200000 1777.340000 3601.920000 1777.540000 ;
    END
  END extintsrc_req[5]
  PIN extintsrc_req[4]
    DIRECTION INPUT ;
    USE SIGNAL ;
    PORT
      LAYER Metal4 ;
        RECT 3601.200000 1777.340000 3601.920000 1777.540000 ;
    END
  END extintsrc_req[4]
  PIN extintsrc_req[3]
    DIRECTION INPUT ;
    USE SIGNAL ;
    PORT
      LAYER Metal2 ;
        RECT 0.000000 1821.860000 0.720000 1822.060000 ;
    END
  END extintsrc_req[3]
  PIN extintsrc_req[2]
    DIRECTION INPUT ;
    USE SIGNAL ;
    PORT
      LAYER Metal4 ;
        RECT 0.000000 1821.860000 0.720000 1822.060000 ;
    END
  END extintsrc_req[2]
  PIN extintsrc_req[1]
    DIRECTION INPUT ;
    USE SIGNAL ;
    PORT
      LAYER Metal2 ;
        RECT 3601.200000 1821.860000 3601.920000 1822.060000 ;
    END
  END extintsrc_req[1]
  PIN dec_tlu_perfcnt0[1]
    DIRECTION OUTPUT ;
    USE SIGNAL ;
    PORT
      LAYER Metal4 ;
        RECT 3601.200000 3593.420000 3601.920000 3593.620000 ;
    END
  END dec_tlu_perfcnt0[1]
  PIN dec_tlu_perfcnt0[0]
    DIRECTION OUTPUT ;
    USE SIGNAL ;
    PORT
      LAYER Metal4 ;
        RECT 3601.200000 3084.800000 3601.920000 3085.000000 ;
    END
  END dec_tlu_perfcnt0[0]
  PIN dec_tlu_perfcnt1[1]
    DIRECTION OUTPUT ;
    USE SIGNAL ;
    PORT
      LAYER Metal4 ;
        RECT 3601.200000 2570.720000 3601.920000 2570.920000 ;
    END
  END dec_tlu_perfcnt1[1]
  PIN dec_tlu_perfcnt1[0]
    DIRECTION OUTPUT ;
    USE SIGNAL ;
    PORT
      LAYER Metal4 ;
        RECT 3601.200000 2056.640000 3601.920000 2056.840000 ;
    END
  END dec_tlu_perfcnt1[0]
  PIN dec_tlu_perfcnt2[1]
    DIRECTION OUTPUT ;
    USE SIGNAL ;
    PORT
      LAYER Metal4 ;
        RECT 3601.200000 1542.560000 3601.920000 1542.760000 ;
    END
  END dec_tlu_perfcnt2[1]
  PIN dec_tlu_perfcnt2[0]
    DIRECTION OUTPUT ;
    USE SIGNAL ;
    PORT
      LAYER Metal4 ;
        RECT 3601.200000 1028.480000 3601.920000 1028.680000 ;
    END
  END dec_tlu_perfcnt2[0]
  PIN dec_tlu_perfcnt3[1]
    DIRECTION OUTPUT ;
    USE SIGNAL ;
    PORT
      LAYER Metal4 ;
        RECT 3601.200000 514.400000 3601.920000 514.600000 ;
    END
  END dec_tlu_perfcnt3[1]
  PIN dec_tlu_perfcnt3[0]
    DIRECTION OUTPUT ;
    USE SIGNAL ;
    PORT
      LAYER Metal4 ;
        RECT 3601.200000 7.880000 3601.920000 8.080000 ;
    END
  END dec_tlu_perfcnt3[0]
  PIN jtag_tck
    DIRECTION INPUT ;
    USE SIGNAL ;
    PORT
      LAYER Metal2 ;
        RECT 3601.200000 411.920000 3601.920000 412.120000 ;
    END
  END jtag_tck
  PIN jtag_tms
    DIRECTION INPUT ;
    USE SIGNAL ;
    PORT
      LAYER Metal2 ;
        RECT 3601.200000 309.020000 3601.920000 309.220000 ;
    END
  END jtag_tms
  PIN jtag_tdi
    DIRECTION INPUT ;
    USE SIGNAL ;
    PORT
      LAYER Metal2 ;
        RECT 3601.200000 206.120000 3601.920000 206.320000 ;
    END
  END jtag_tdi
  PIN jtag_trst_n
    DIRECTION INPUT ;
    USE SIGNAL ;
    PORT
      LAYER Metal2 ;
        RECT 3601.200000 103.220000 3601.920000 103.420000 ;
    END
  END jtag_trst_n
  PIN jtag_tdo
    DIRECTION OUTPUT ;
    USE SIGNAL ;
    PORT
      LAYER Metal2 ;
        RECT 3601.200000 16.700000 3601.920000 16.900000 ;
    END
  END jtag_tdo
  PIN mpc_debug_halt_req
    DIRECTION INPUT ;
    USE SIGNAL ;
    PORT
      LAYER Metal3 ;
        RECT 3585.020000 0.000000 3585.220000 0.720000 ;
    END
  END mpc_debug_halt_req
  PIN mpc_debug_run_req
    DIRECTION INPUT ;
    USE SIGNAL ;
    PORT
      LAYER Metal3 ;
        RECT 2700.860000 0.000000 2701.060000 0.720000 ;
    END
  END mpc_debug_run_req
  PIN mpc_reset_run_req
    DIRECTION INPUT ;
    USE SIGNAL ;
    PORT
      LAYER Metal3 ;
        RECT 1800.860000 0.000000 1801.060000 0.720000 ;
    END
  END mpc_reset_run_req
  PIN mpc_debug_halt_ack
    DIRECTION OUTPUT ;
    USE SIGNAL ;
    PORT
      LAYER Metal3 ;
        RECT 900.860000 0.000000 901.060000 0.720000 ;
    END
  END mpc_debug_halt_ack
  PIN mpc_debug_run_ack
    DIRECTION OUTPUT ;
    USE SIGNAL ;
    PORT
      LAYER Metal3 ;
        RECT 12.380000 0.000000 12.580000 0.720000 ;
    END
  END mpc_debug_run_ack
  PIN debug_brkpt_status
    DIRECTION OUTPUT ;
    USE SIGNAL ;
    PORT
      LAYER Metal5 ;
        RECT 1874.780000 0.000000 1874.980000 0.720000 ;
    END
  END debug_brkpt_status
  PIN i_cpu_halt_req
    DIRECTION INPUT ;
    USE SIGNAL ;
    PORT
      LAYER Metal2 ;
        RECT 0.000000 1873.100000 0.720000 1873.300000 ;
    END
  END i_cpu_halt_req
  PIN o_cpu_halt_ack
    DIRECTION OUTPUT ;
    USE SIGNAL ;
    PORT
      LAYER Metal4 ;
        RECT 0.000000 1872.260000 0.720000 1872.460000 ;
    END
  END o_cpu_halt_ack
  PIN o_cpu_halt_status
    DIRECTION OUTPUT ;
    USE SIGNAL ;
    PORT
      LAYER Metal2 ;
        RECT 3601.200000 1872.260000 3601.920000 1872.460000 ;
    END
  END o_cpu_halt_status
  PIN o_debug_mode_status
    DIRECTION OUTPUT ;
    USE SIGNAL ;
    PORT
      LAYER Metal4 ;
        RECT 3601.200000 1872.260000 3601.920000 1872.460000 ;
    END
  END o_debug_mode_status
  PIN i_cpu_run_req
    DIRECTION INPUT ;
    USE SIGNAL ;
    PORT
      LAYER Metal2 ;
        RECT 0.000000 1725.260000 0.720000 1725.460000 ;
    END
  END i_cpu_run_req
  PIN o_cpu_run_ack
    DIRECTION OUTPUT ;
    USE SIGNAL ;
    PORT
      LAYER Metal4 ;
        RECT 0.000000 1726.100000 0.720000 1726.300000 ;
    END
  END o_cpu_run_ack
  PIN scan_mode
    DIRECTION INPUT ;
    USE SIGNAL ;
    PORT
      LAYER Metal2 ;
        RECT 3601.200000 1726.100000 3601.920000 1726.300000 ;
    END
  END scan_mode
  PIN mbist_mode
    DIRECTION INPUT ;
    USE SIGNAL ;
    PORT
      LAYER Metal4 ;
        RECT 3601.200000 1726.100000 3601.920000 1726.300000 ;
    END
  END mbist_mode
  OBS
    LAYER Metal1 ;
      RECT 0.000000 0.000000 3601.920000 3598.980000 ;
    LAYER Metal2 ;
      RECT 0.000000 3591.310000 3601.920000 3598.980000 ;
      RECT 0.000000 3590.690000 3600.990000 3591.310000 ;
      RECT 0.000000 3496.390000 3601.920000 3590.690000 ;
      RECT 0.000000 3495.770000 3600.990000 3496.390000 ;
      RECT 0.000000 3393.490000 3601.920000 3495.770000 ;
      RECT 0.000000 3392.870000 3600.990000 3393.490000 ;
      RECT 0.000000 3290.590000 3601.920000 3392.870000 ;
      RECT 0.000000 3289.970000 3600.990000 3290.590000 ;
      RECT 0.000000 3187.690000 3601.920000 3289.970000 ;
      RECT 0.000000 3187.070000 3600.990000 3187.690000 ;
      RECT 0.000000 3085.210000 3601.920000 3187.070000 ;
      RECT 0.000000 3084.590000 3600.990000 3085.210000 ;
      RECT 0.000000 2982.310000 3601.920000 3084.590000 ;
      RECT 0.000000 2981.690000 3600.990000 2982.310000 ;
      RECT 0.000000 2879.410000 3601.920000 2981.690000 ;
      RECT 0.000000 2878.790000 3600.990000 2879.410000 ;
      RECT 0.000000 2776.510000 3601.920000 2878.790000 ;
      RECT 0.000000 2775.890000 3600.990000 2776.510000 ;
      RECT 0.000000 2674.030000 3601.920000 2775.890000 ;
      RECT 0.000000 2673.410000 3600.990000 2674.030000 ;
      RECT 0.000000 2571.130000 3601.920000 2673.410000 ;
      RECT 0.000000 2570.510000 3600.990000 2571.130000 ;
      RECT 0.000000 2468.230000 3601.920000 2570.510000 ;
      RECT 0.000000 2467.610000 3600.990000 2468.230000 ;
      RECT 0.000000 2365.330000 3601.920000 2467.610000 ;
      RECT 0.000000 2364.710000 3600.990000 2365.330000 ;
      RECT 0.000000 2262.430000 3601.920000 2364.710000 ;
      RECT 0.000000 2261.810000 3600.990000 2262.430000 ;
      RECT 0.000000 2159.950000 3601.920000 2261.810000 ;
      RECT 0.000000 2159.330000 3600.990000 2159.950000 ;
      RECT 0.000000 2057.050000 3601.920000 2159.330000 ;
      RECT 0.000000 2056.430000 3600.990000 2057.050000 ;
      RECT 0.000000 1954.150000 3601.920000 2056.430000 ;
      RECT 0.000000 1953.530000 3600.990000 1954.150000 ;
      RECT 0.000000 1873.510000 3601.920000 1953.530000 ;
      RECT 0.930000 1872.890000 3601.920000 1873.510000 ;
      RECT 0.000000 1872.670000 3601.920000 1872.890000 ;
      RECT 0.000000 1872.050000 3600.990000 1872.670000 ;
      RECT 0.000000 1871.830000 3601.920000 1872.050000 ;
      RECT 0.930000 1871.210000 3600.990000 1871.830000 ;
      RECT 0.000000 1851.250000 3601.920000 1871.210000 ;
      RECT 0.000000 1850.630000 3600.990000 1851.250000 ;
      RECT 0.000000 1822.270000 3601.920000 1850.630000 ;
      RECT 0.930000 1821.650000 3600.990000 1822.270000 ;
      RECT 0.000000 1777.750000 3601.920000 1821.650000 ;
      RECT 0.930000 1777.130000 3600.990000 1777.750000 ;
      RECT 0.000000 1748.770000 3601.920000 1777.130000 ;
      RECT 0.000000 1748.150000 3600.990000 1748.770000 ;
      RECT 0.000000 1727.350000 3601.920000 1748.150000 ;
      RECT 0.930000 1726.730000 3601.920000 1727.350000 ;
      RECT 0.000000 1726.510000 3601.920000 1726.730000 ;
      RECT 0.000000 1725.890000 3600.990000 1726.510000 ;
      RECT 0.000000 1725.670000 3601.920000 1725.890000 ;
      RECT 0.930000 1725.050000 3601.920000 1725.670000 ;
      RECT 0.000000 1645.870000 3601.920000 1725.050000 ;
      RECT 0.000000 1645.250000 3600.990000 1645.870000 ;
      RECT 0.000000 1542.970000 3601.920000 1645.250000 ;
      RECT 0.000000 1542.350000 3600.990000 1542.970000 ;
      RECT 0.000000 1440.070000 3601.920000 1542.350000 ;
      RECT 0.000000 1439.450000 3600.990000 1440.070000 ;
      RECT 0.000000 1337.590000 3601.920000 1439.450000 ;
      RECT 0.000000 1336.970000 3600.990000 1337.590000 ;
      RECT 0.000000 1234.690000 3601.920000 1336.970000 ;
      RECT 0.000000 1234.070000 3600.990000 1234.690000 ;
      RECT 0.000000 1131.790000 3601.920000 1234.070000 ;
      RECT 0.000000 1131.170000 3600.990000 1131.790000 ;
      RECT 0.000000 1028.890000 3601.920000 1131.170000 ;
      RECT 0.000000 1028.270000 3600.990000 1028.890000 ;
      RECT 0.000000 925.990000 3601.920000 1028.270000 ;
      RECT 0.000000 925.370000 3600.990000 925.990000 ;
      RECT 0.000000 823.510000 3601.920000 925.370000 ;
      RECT 0.000000 822.890000 3600.990000 823.510000 ;
      RECT 0.000000 720.610000 3601.920000 822.890000 ;
      RECT 0.000000 719.990000 3600.990000 720.610000 ;
      RECT 0.000000 617.710000 3601.920000 719.990000 ;
      RECT 0.000000 617.090000 3600.990000 617.710000 ;
      RECT 0.000000 514.810000 3601.920000 617.090000 ;
      RECT 0.000000 514.190000 3600.990000 514.810000 ;
      RECT 0.000000 412.330000 3601.920000 514.190000 ;
      RECT 0.000000 411.710000 3600.990000 412.330000 ;
      RECT 0.000000 309.430000 3601.920000 411.710000 ;
      RECT 0.000000 308.810000 3600.990000 309.430000 ;
      RECT 0.000000 206.530000 3601.920000 308.810000 ;
      RECT 0.000000 205.910000 3600.990000 206.530000 ;
      RECT 0.000000 103.630000 3601.920000 205.910000 ;
      RECT 0.000000 103.010000 3600.990000 103.630000 ;
      RECT 0.000000 17.110000 3601.920000 103.010000 ;
      RECT 0.000000 16.490000 3600.990000 17.110000 ;
      RECT 0.000000 0.000000 3601.920000 16.490000 ;
    LAYER Metal3 ;
      RECT 3598.390000 3598.050000 3601.920000 3598.980000 ;
      RECT 3595.510000 3598.050000 3597.770000 3598.980000 ;
      RECT 3593.110000 3598.050000 3594.890000 3598.980000 ;
      RECT 3589.750000 3598.050000 3592.490000 3598.980000 ;
      RECT 3586.870000 3598.050000 3589.130000 3598.980000 ;
      RECT 3583.510000 3598.050000 3586.250000 3598.980000 ;
      RECT 3580.630000 3598.050000 3582.890000 3598.980000 ;
      RECT 3577.270000 3598.050000 3580.010000 3598.980000 ;
      RECT 3575.350000 3598.050000 3576.650000 3598.980000 ;
      RECT 3571.990000 3598.050000 3574.730000 3598.980000 ;
      RECT 3569.110000 3598.050000 3571.370000 3598.980000 ;
      RECT 3565.750000 3598.050000 3568.490000 3598.980000 ;
      RECT 3562.390000 3598.050000 3565.130000 3598.980000 ;
      RECT 3559.030000 3598.050000 3561.770000 3598.980000 ;
      RECT 3555.670000 3598.050000 3558.410000 3598.980000 ;
      RECT 3552.790000 3598.050000 3555.050000 3598.980000 ;
      RECT 3549.430000 3598.050000 3552.170000 3598.980000 ;
      RECT 3546.070000 3598.050000 3548.810000 3598.980000 ;
      RECT 3542.710000 3598.050000 3545.450000 3598.980000 ;
      RECT 3539.830000 3598.050000 3542.090000 3598.980000 ;
      RECT 3536.470000 3598.050000 3539.210000 3598.980000 ;
      RECT 3533.110000 3598.050000 3535.850000 3598.980000 ;
      RECT 3529.750000 3598.050000 3532.490000 3598.980000 ;
      RECT 3526.390000 3598.050000 3529.130000 3598.980000 ;
      RECT 3523.510000 3598.050000 3525.770000 3598.980000 ;
      RECT 3520.150000 3598.050000 3522.890000 3598.980000 ;
      RECT 3516.790000 3598.050000 3519.530000 3598.980000 ;
      RECT 3513.430000 3598.050000 3516.170000 3598.980000 ;
      RECT 3510.070000 3598.050000 3512.810000 3598.980000 ;
      RECT 3507.190000 3598.050000 3509.450000 3598.980000 ;
      RECT 3503.830000 3598.050000 3506.570000 3598.980000 ;
      RECT 3500.470000 3598.050000 3503.210000 3598.980000 ;
      RECT 3497.110000 3598.050000 3499.850000 3598.980000 ;
      RECT 3493.750000 3598.050000 3496.490000 3598.980000 ;
      RECT 3490.870000 3598.050000 3493.130000 3598.980000 ;
      RECT 3487.510000 3598.050000 3490.250000 3598.980000 ;
      RECT 3484.150000 3598.050000 3486.890000 3598.980000 ;
      RECT 3480.790000 3598.050000 3483.530000 3598.980000 ;
      RECT 3477.910000 3598.050000 3480.170000 3598.980000 ;
      RECT 3474.550000 3598.050000 3477.290000 3598.980000 ;
      RECT 3471.190000 3598.050000 3473.930000 3598.980000 ;
      RECT 3467.830000 3598.050000 3470.570000 3598.980000 ;
      RECT 3464.470000 3598.050000 3467.210000 3598.980000 ;
      RECT 3461.590000 3598.050000 3463.850000 3598.980000 ;
      RECT 3458.230000 3598.050000 3460.970000 3598.980000 ;
      RECT 3454.870000 3598.050000 3457.610000 3598.980000 ;
      RECT 3451.510000 3598.050000 3454.250000 3598.980000 ;
      RECT 3448.150000 3598.050000 3450.890000 3598.980000 ;
      RECT 3445.270000 3598.050000 3447.530000 3598.980000 ;
      RECT 3441.910000 3598.050000 3444.650000 3598.980000 ;
      RECT 3438.550000 3598.050000 3441.290000 3598.980000 ;
      RECT 3435.190000 3598.050000 3437.930000 3598.980000 ;
      RECT 3431.830000 3598.050000 3434.570000 3598.980000 ;
      RECT 3428.950000 3598.050000 3431.210000 3598.980000 ;
      RECT 3425.590000 3598.050000 3428.330000 3598.980000 ;
      RECT 3422.230000 3598.050000 3424.970000 3598.980000 ;
      RECT 3418.870000 3598.050000 3421.610000 3598.980000 ;
      RECT 3415.990000 3598.050000 3418.250000 3598.980000 ;
      RECT 3412.630000 3598.050000 3415.370000 3598.980000 ;
      RECT 3409.270000 3598.050000 3412.010000 3598.980000 ;
      RECT 3405.910000 3598.050000 3408.650000 3598.980000 ;
      RECT 3402.550000 3598.050000 3405.290000 3598.980000 ;
      RECT 3399.670000 3598.050000 3401.930000 3598.980000 ;
      RECT 3396.310000 3598.050000 3399.050000 3598.980000 ;
      RECT 3392.950000 3598.050000 3395.690000 3598.980000 ;
      RECT 3389.590000 3598.050000 3392.330000 3598.980000 ;
      RECT 3386.230000 3598.050000 3388.970000 3598.980000 ;
      RECT 3383.350000 3598.050000 3385.610000 3598.980000 ;
      RECT 3379.990000 3598.050000 3382.730000 3598.980000 ;
      RECT 3376.630000 3598.050000 3379.370000 3598.980000 ;
      RECT 3373.270000 3598.050000 3376.010000 3598.980000 ;
      RECT 3369.910000 3598.050000 3372.650000 3598.980000 ;
      RECT 3367.030000 3598.050000 3369.290000 3598.980000 ;
      RECT 3363.670000 3598.050000 3366.410000 3598.980000 ;
      RECT 3360.310000 3598.050000 3363.050000 3598.980000 ;
      RECT 3356.950000 3598.050000 3359.690000 3598.980000 ;
      RECT 3354.070000 3598.050000 3356.330000 3598.980000 ;
      RECT 3350.710000 3598.050000 3353.450000 3598.980000 ;
      RECT 3347.350000 3598.050000 3350.090000 3598.980000 ;
      RECT 3343.990000 3598.050000 3346.730000 3598.980000 ;
      RECT 3340.630000 3598.050000 3343.370000 3598.980000 ;
      RECT 3337.750000 3598.050000 3340.010000 3598.980000 ;
      RECT 3334.390000 3598.050000 3337.130000 3598.980000 ;
      RECT 3331.030000 3598.050000 3333.770000 3598.980000 ;
      RECT 3327.670000 3598.050000 3330.410000 3598.980000 ;
      RECT 3324.310000 3598.050000 3327.050000 3598.980000 ;
      RECT 3321.430000 3598.050000 3323.690000 3598.980000 ;
      RECT 3318.070000 3598.050000 3320.810000 3598.980000 ;
      RECT 3314.710000 3598.050000 3317.450000 3598.980000 ;
      RECT 3311.350000 3598.050000 3314.090000 3598.980000 ;
      RECT 3307.990000 3598.050000 3310.730000 3598.980000 ;
      RECT 3305.110000 3598.050000 3307.370000 3598.980000 ;
      RECT 3301.750000 3598.050000 3304.490000 3598.980000 ;
      RECT 3298.390000 3598.050000 3301.130000 3598.980000 ;
      RECT 3295.030000 3598.050000 3297.770000 3598.980000 ;
      RECT 3292.150000 3598.050000 3294.410000 3598.980000 ;
      RECT 3288.790000 3598.050000 3291.530000 3598.980000 ;
      RECT 3285.430000 3598.050000 3288.170000 3598.980000 ;
      RECT 3282.070000 3598.050000 3284.810000 3598.980000 ;
      RECT 3278.710000 3598.050000 3281.450000 3598.980000 ;
      RECT 3275.830000 3598.050000 3278.090000 3598.980000 ;
      RECT 3272.470000 3598.050000 3275.210000 3598.980000 ;
      RECT 3269.110000 3598.050000 3271.850000 3598.980000 ;
      RECT 3265.750000 3598.050000 3268.490000 3598.980000 ;
      RECT 3262.390000 3598.050000 3265.130000 3598.980000 ;
      RECT 3259.510000 3598.050000 3261.770000 3598.980000 ;
      RECT 3256.150000 3598.050000 3258.890000 3598.980000 ;
      RECT 3252.790000 3598.050000 3255.530000 3598.980000 ;
      RECT 3249.430000 3598.050000 3252.170000 3598.980000 ;
      RECT 3246.070000 3598.050000 3248.810000 3598.980000 ;
      RECT 3243.190000 3598.050000 3245.450000 3598.980000 ;
      RECT 3239.830000 3598.050000 3242.570000 3598.980000 ;
      RECT 3236.470000 3598.050000 3239.210000 3598.980000 ;
      RECT 3233.110000 3598.050000 3235.850000 3598.980000 ;
      RECT 3230.230000 3598.050000 3232.490000 3598.980000 ;
      RECT 3226.870000 3598.050000 3229.610000 3598.980000 ;
      RECT 3223.510000 3598.050000 3226.250000 3598.980000 ;
      RECT 3220.150000 3598.050000 3222.890000 3598.980000 ;
      RECT 3216.790000 3598.050000 3219.530000 3598.980000 ;
      RECT 3213.910000 3598.050000 3216.170000 3598.980000 ;
      RECT 3210.550000 3598.050000 3213.290000 3598.980000 ;
      RECT 3207.190000 3598.050000 3209.930000 3598.980000 ;
      RECT 3203.830000 3598.050000 3206.570000 3598.980000 ;
      RECT 3200.470000 3598.050000 3203.210000 3598.980000 ;
      RECT 3197.590000 3598.050000 3199.850000 3598.980000 ;
      RECT 3194.230000 3598.050000 3196.970000 3598.980000 ;
      RECT 3190.870000 3598.050000 3193.610000 3598.980000 ;
      RECT 3187.510000 3598.050000 3190.250000 3598.980000 ;
      RECT 3184.150000 3598.050000 3186.890000 3598.980000 ;
      RECT 3181.270000 3598.050000 3183.530000 3598.980000 ;
      RECT 3177.910000 3598.050000 3180.650000 3598.980000 ;
      RECT 3174.550000 3598.050000 3177.290000 3598.980000 ;
      RECT 3171.190000 3598.050000 3173.930000 3598.980000 ;
      RECT 3168.310000 3598.050000 3170.570000 3598.980000 ;
      RECT 3164.950000 3598.050000 3167.690000 3598.980000 ;
      RECT 3161.590000 3598.050000 3164.330000 3598.980000 ;
      RECT 3158.230000 3598.050000 3160.970000 3598.980000 ;
      RECT 3154.870000 3598.050000 3157.610000 3598.980000 ;
      RECT 3151.990000 3598.050000 3154.250000 3598.980000 ;
      RECT 3148.630000 3598.050000 3151.370000 3598.980000 ;
      RECT 3145.270000 3598.050000 3148.010000 3598.980000 ;
      RECT 3141.910000 3598.050000 3144.650000 3598.980000 ;
      RECT 3138.550000 3598.050000 3141.290000 3598.980000 ;
      RECT 3135.670000 3598.050000 3137.930000 3598.980000 ;
      RECT 3132.310000 3598.050000 3135.050000 3598.980000 ;
      RECT 3128.950000 3598.050000 3131.690000 3598.980000 ;
      RECT 3125.590000 3598.050000 3128.330000 3598.980000 ;
      RECT 3122.230000 3598.050000 3124.970000 3598.980000 ;
      RECT 3119.350000 3598.050000 3121.610000 3598.980000 ;
      RECT 3115.990000 3598.050000 3118.730000 3598.980000 ;
      RECT 3112.630000 3598.050000 3115.370000 3598.980000 ;
      RECT 3109.270000 3598.050000 3112.010000 3598.980000 ;
      RECT 3106.390000 3598.050000 3108.650000 3598.980000 ;
      RECT 3103.990000 3598.050000 3105.770000 3598.980000 ;
      RECT 3103.030000 3598.050000 3103.370000 3598.980000 ;
      RECT 3099.670000 3598.050000 3102.410000 3598.980000 ;
      RECT 3096.310000 3598.050000 3099.050000 3598.980000 ;
      RECT 3092.950000 3598.050000 3095.690000 3598.980000 ;
      RECT 3090.070000 3598.050000 3092.330000 3598.980000 ;
      RECT 3086.710000 3598.050000 3089.450000 3598.980000 ;
      RECT 3083.350000 3598.050000 3086.090000 3598.980000 ;
      RECT 3079.990000 3598.050000 3082.730000 3598.980000 ;
      RECT 3076.630000 3598.050000 3079.370000 3598.980000 ;
      RECT 3073.750000 3598.050000 3076.010000 3598.980000 ;
      RECT 3070.390000 3598.050000 3073.130000 3598.980000 ;
      RECT 3067.030000 3598.050000 3069.770000 3598.980000 ;
      RECT 3063.670000 3598.050000 3066.410000 3598.980000 ;
      RECT 3060.790000 3598.050000 3063.050000 3598.980000 ;
      RECT 3057.430000 3598.050000 3060.170000 3598.980000 ;
      RECT 3054.070000 3598.050000 3056.810000 3598.980000 ;
      RECT 3050.710000 3598.050000 3053.450000 3598.980000 ;
      RECT 3047.350000 3598.050000 3050.090000 3598.980000 ;
      RECT 3044.470000 3598.050000 3046.730000 3598.980000 ;
      RECT 3041.110000 3598.050000 3043.850000 3598.980000 ;
      RECT 3037.750000 3598.050000 3040.490000 3598.980000 ;
      RECT 3034.390000 3598.050000 3037.130000 3598.980000 ;
      RECT 3031.030000 3598.050000 3033.770000 3598.980000 ;
      RECT 3028.150000 3598.050000 3030.410000 3598.980000 ;
      RECT 3024.790000 3598.050000 3027.530000 3598.980000 ;
      RECT 3021.430000 3598.050000 3024.170000 3598.980000 ;
      RECT 3018.070000 3598.050000 3020.810000 3598.980000 ;
      RECT 3014.710000 3598.050000 3017.450000 3598.980000 ;
      RECT 3011.830000 3598.050000 3014.090000 3598.980000 ;
      RECT 3008.470000 3598.050000 3011.210000 3598.980000 ;
      RECT 3005.110000 3598.050000 3007.850000 3598.980000 ;
      RECT 3001.750000 3598.050000 3004.490000 3598.980000 ;
      RECT 2998.870000 3598.050000 3001.130000 3598.980000 ;
      RECT 2995.510000 3598.050000 2998.250000 3598.980000 ;
      RECT 2992.150000 3598.050000 2994.890000 3598.980000 ;
      RECT 2988.790000 3598.050000 2991.530000 3598.980000 ;
      RECT 2985.430000 3598.050000 2988.170000 3598.980000 ;
      RECT 2982.550000 3598.050000 2984.810000 3598.980000 ;
      RECT 2979.190000 3598.050000 2981.930000 3598.980000 ;
      RECT 2975.830000 3598.050000 2978.570000 3598.980000 ;
      RECT 2972.470000 3598.050000 2975.210000 3598.980000 ;
      RECT 2969.110000 3598.050000 2971.850000 3598.980000 ;
      RECT 2966.230000 3598.050000 2968.490000 3598.980000 ;
      RECT 2962.870000 3598.050000 2965.610000 3598.980000 ;
      RECT 2959.510000 3598.050000 2962.250000 3598.980000 ;
      RECT 2956.150000 3598.050000 2958.890000 3598.980000 ;
      RECT 2952.790000 3598.050000 2955.530000 3598.980000 ;
      RECT 2949.910000 3598.050000 2952.170000 3598.980000 ;
      RECT 2946.550000 3598.050000 2949.290000 3598.980000 ;
      RECT 2943.190000 3598.050000 2945.930000 3598.980000 ;
      RECT 2939.830000 3598.050000 2942.570000 3598.980000 ;
      RECT 2936.950000 3598.050000 2939.210000 3598.980000 ;
      RECT 2933.590000 3598.050000 2936.330000 3598.980000 ;
      RECT 2930.230000 3598.050000 2932.970000 3598.980000 ;
      RECT 2926.870000 3598.050000 2929.610000 3598.980000 ;
      RECT 2923.510000 3598.050000 2926.250000 3598.980000 ;
      RECT 2920.630000 3598.050000 2922.890000 3598.980000 ;
      RECT 2917.270000 3598.050000 2920.010000 3598.980000 ;
      RECT 2913.910000 3598.050000 2916.650000 3598.980000 ;
      RECT 2910.550000 3598.050000 2913.290000 3598.980000 ;
      RECT 2907.190000 3598.050000 2909.930000 3598.980000 ;
      RECT 2904.310000 3598.050000 2906.570000 3598.980000 ;
      RECT 2900.950000 3598.050000 2903.690000 3598.980000 ;
      RECT 2897.590000 3598.050000 2900.330000 3598.980000 ;
      RECT 2894.230000 3598.050000 2896.970000 3598.980000 ;
      RECT 2890.870000 3598.050000 2893.610000 3598.980000 ;
      RECT 2887.990000 3598.050000 2890.250000 3598.980000 ;
      RECT 2884.630000 3598.050000 2887.370000 3598.980000 ;
      RECT 2881.270000 3598.050000 2884.010000 3598.980000 ;
      RECT 2877.910000 3598.050000 2880.650000 3598.980000 ;
      RECT 2875.030000 3598.050000 2877.290000 3598.980000 ;
      RECT 2871.670000 3598.050000 2874.410000 3598.980000 ;
      RECT 2868.310000 3598.050000 2871.050000 3598.980000 ;
      RECT 2864.950000 3598.050000 2867.690000 3598.980000 ;
      RECT 2861.590000 3598.050000 2864.330000 3598.980000 ;
      RECT 2858.710000 3598.050000 2860.970000 3598.980000 ;
      RECT 2855.350000 3598.050000 2858.090000 3598.980000 ;
      RECT 2851.990000 3598.050000 2854.730000 3598.980000 ;
      RECT 2848.630000 3598.050000 2851.370000 3598.980000 ;
      RECT 2845.270000 3598.050000 2848.010000 3598.980000 ;
      RECT 2842.390000 3598.050000 2844.650000 3598.980000 ;
      RECT 2839.030000 3598.050000 2841.770000 3598.980000 ;
      RECT 2835.670000 3598.050000 2838.410000 3598.980000 ;
      RECT 2832.310000 3598.050000 2835.050000 3598.980000 ;
      RECT 2828.950000 3598.050000 2831.690000 3598.980000 ;
      RECT 2826.070000 3598.050000 2828.330000 3598.980000 ;
      RECT 2822.710000 3598.050000 2825.450000 3598.980000 ;
      RECT 2819.350000 3598.050000 2822.090000 3598.980000 ;
      RECT 2815.990000 3598.050000 2818.730000 3598.980000 ;
      RECT 2813.110000 3598.050000 2815.370000 3598.980000 ;
      RECT 2809.750000 3598.050000 2812.490000 3598.980000 ;
      RECT 2806.390000 3598.050000 2809.130000 3598.980000 ;
      RECT 2803.030000 3598.050000 2805.770000 3598.980000 ;
      RECT 2799.670000 3598.050000 2802.410000 3598.980000 ;
      RECT 2796.790000 3598.050000 2799.050000 3598.980000 ;
      RECT 2793.430000 3598.050000 2796.170000 3598.980000 ;
      RECT 2790.070000 3598.050000 2792.810000 3598.980000 ;
      RECT 2786.710000 3598.050000 2789.450000 3598.980000 ;
      RECT 2783.350000 3598.050000 2786.090000 3598.980000 ;
      RECT 2780.470000 3598.050000 2782.730000 3598.980000 ;
      RECT 2777.110000 3598.050000 2779.850000 3598.980000 ;
      RECT 2773.750000 3598.050000 2776.490000 3598.980000 ;
      RECT 2770.390000 3598.050000 2773.130000 3598.980000 ;
      RECT 2767.030000 3598.050000 2769.770000 3598.980000 ;
      RECT 2764.150000 3598.050000 2766.410000 3598.980000 ;
      RECT 2760.790000 3598.050000 2763.530000 3598.980000 ;
      RECT 2757.430000 3598.050000 2760.170000 3598.980000 ;
      RECT 2754.070000 3598.050000 2756.810000 3598.980000 ;
      RECT 2751.190000 3598.050000 2753.450000 3598.980000 ;
      RECT 2747.830000 3598.050000 2750.570000 3598.980000 ;
      RECT 2744.470000 3598.050000 2747.210000 3598.980000 ;
      RECT 2741.110000 3598.050000 2743.850000 3598.980000 ;
      RECT 2737.750000 3598.050000 2740.490000 3598.980000 ;
      RECT 2734.870000 3598.050000 2737.130000 3598.980000 ;
      RECT 2731.510000 3598.050000 2734.250000 3598.980000 ;
      RECT 2728.150000 3598.050000 2730.890000 3598.980000 ;
      RECT 2724.790000 3598.050000 2727.530000 3598.980000 ;
      RECT 2721.430000 3598.050000 2724.170000 3598.980000 ;
      RECT 2718.550000 3598.050000 2720.810000 3598.980000 ;
      RECT 2715.190000 3598.050000 2717.930000 3598.980000 ;
      RECT 2711.830000 3598.050000 2714.570000 3598.980000 ;
      RECT 2708.470000 3598.050000 2711.210000 3598.980000 ;
      RECT 2705.110000 3598.050000 2707.850000 3598.980000 ;
      RECT 2702.230000 3598.050000 2704.490000 3598.980000 ;
      RECT 2698.870000 3598.050000 2701.610000 3598.980000 ;
      RECT 2695.510000 3598.050000 2698.250000 3598.980000 ;
      RECT 2692.150000 3598.050000 2694.890000 3598.980000 ;
      RECT 2689.270000 3598.050000 2691.530000 3598.980000 ;
      RECT 2685.910000 3598.050000 2688.650000 3598.980000 ;
      RECT 2682.550000 3598.050000 2685.290000 3598.980000 ;
      RECT 2679.190000 3598.050000 2681.930000 3598.980000 ;
      RECT 2675.830000 3598.050000 2678.570000 3598.980000 ;
      RECT 2672.950000 3598.050000 2675.210000 3598.980000 ;
      RECT 2669.590000 3598.050000 2672.330000 3598.980000 ;
      RECT 2666.230000 3598.050000 2668.970000 3598.980000 ;
      RECT 2662.870000 3598.050000 2665.610000 3598.980000 ;
      RECT 2659.510000 3598.050000 2662.250000 3598.980000 ;
      RECT 2656.630000 3598.050000 2658.890000 3598.980000 ;
      RECT 2653.270000 3598.050000 2656.010000 3598.980000 ;
      RECT 2649.910000 3598.050000 2652.650000 3598.980000 ;
      RECT 2646.550000 3598.050000 2649.290000 3598.980000 ;
      RECT 2643.190000 3598.050000 2645.930000 3598.980000 ;
      RECT 2640.310000 3598.050000 2642.570000 3598.980000 ;
      RECT 2636.950000 3598.050000 2639.690000 3598.980000 ;
      RECT 2633.590000 3598.050000 2636.330000 3598.980000 ;
      RECT 2630.230000 3598.050000 2632.970000 3598.980000 ;
      RECT 2627.350000 3598.050000 2629.610000 3598.980000 ;
      RECT 2623.990000 3598.050000 2626.730000 3598.980000 ;
      RECT 2620.630000 3598.050000 2623.370000 3598.980000 ;
      RECT 2617.270000 3598.050000 2620.010000 3598.980000 ;
      RECT 2613.910000 3598.050000 2616.650000 3598.980000 ;
      RECT 2611.030000 3598.050000 2613.290000 3598.980000 ;
      RECT 2607.670000 3598.050000 2610.410000 3598.980000 ;
      RECT 2604.310000 3598.050000 2607.050000 3598.980000 ;
      RECT 2600.950000 3598.050000 2603.690000 3598.980000 ;
      RECT 2597.590000 3598.050000 2600.330000 3598.980000 ;
      RECT 2594.710000 3598.050000 2596.970000 3598.980000 ;
      RECT 2591.350000 3598.050000 2594.090000 3598.980000 ;
      RECT 2587.990000 3598.050000 2590.730000 3598.980000 ;
      RECT 2584.630000 3598.050000 2587.370000 3598.980000 ;
      RECT 2581.270000 3598.050000 2584.010000 3598.980000 ;
      RECT 2578.390000 3598.050000 2580.650000 3598.980000 ;
      RECT 2575.030000 3598.050000 2577.770000 3598.980000 ;
      RECT 2571.670000 3598.050000 2574.410000 3598.980000 ;
      RECT 2568.310000 3598.050000 2571.050000 3598.980000 ;
      RECT 2565.430000 3598.050000 2567.690000 3598.980000 ;
      RECT 2562.070000 3598.050000 2564.810000 3598.980000 ;
      RECT 2558.710000 3598.050000 2561.450000 3598.980000 ;
      RECT 2555.350000 3598.050000 2558.090000 3598.980000 ;
      RECT 2551.990000 3598.050000 2554.730000 3598.980000 ;
      RECT 2549.110000 3598.050000 2551.370000 3598.980000 ;
      RECT 2545.750000 3598.050000 2548.490000 3598.980000 ;
      RECT 2542.390000 3598.050000 2545.130000 3598.980000 ;
      RECT 2539.030000 3598.050000 2541.770000 3598.980000 ;
      RECT 2535.670000 3598.050000 2538.410000 3598.980000 ;
      RECT 2532.790000 3598.050000 2535.050000 3598.980000 ;
      RECT 2529.430000 3598.050000 2532.170000 3598.980000 ;
      RECT 2526.070000 3598.050000 2528.810000 3598.980000 ;
      RECT 2522.710000 3598.050000 2525.450000 3598.980000 ;
      RECT 2519.830000 3598.050000 2522.090000 3598.980000 ;
      RECT 2516.470000 3598.050000 2519.210000 3598.980000 ;
      RECT 2513.110000 3598.050000 2515.850000 3598.980000 ;
      RECT 2509.750000 3598.050000 2512.490000 3598.980000 ;
      RECT 2506.390000 3598.050000 2509.130000 3598.980000 ;
      RECT 2503.510000 3598.050000 2505.770000 3598.980000 ;
      RECT 2500.150000 3598.050000 2502.890000 3598.980000 ;
      RECT 2496.790000 3598.050000 2499.530000 3598.980000 ;
      RECT 2493.430000 3598.050000 2496.170000 3598.980000 ;
      RECT 2490.070000 3598.050000 2492.810000 3598.980000 ;
      RECT 2487.190000 3598.050000 2489.450000 3598.980000 ;
      RECT 2483.830000 3598.050000 2486.570000 3598.980000 ;
      RECT 2480.470000 3598.050000 2483.210000 3598.980000 ;
      RECT 2477.110000 3598.050000 2479.850000 3598.980000 ;
      RECT 2473.750000 3598.050000 2476.490000 3598.980000 ;
      RECT 2470.870000 3598.050000 2473.130000 3598.980000 ;
      RECT 2467.510000 3598.050000 2470.250000 3598.980000 ;
      RECT 2464.150000 3598.050000 2466.890000 3598.980000 ;
      RECT 2460.790000 3598.050000 2463.530000 3598.980000 ;
      RECT 2457.910000 3598.050000 2460.170000 3598.980000 ;
      RECT 2454.550000 3598.050000 2457.290000 3598.980000 ;
      RECT 2451.190000 3598.050000 2453.930000 3598.980000 ;
      RECT 2447.830000 3598.050000 2450.570000 3598.980000 ;
      RECT 2444.470000 3598.050000 2447.210000 3598.980000 ;
      RECT 2441.590000 3598.050000 2443.850000 3598.980000 ;
      RECT 2438.230000 3598.050000 2440.970000 3598.980000 ;
      RECT 2434.870000 3598.050000 2437.610000 3598.980000 ;
      RECT 2431.510000 3598.050000 2434.250000 3598.980000 ;
      RECT 2428.150000 3598.050000 2430.890000 3598.980000 ;
      RECT 2425.270000 3598.050000 2427.530000 3598.980000 ;
      RECT 2421.910000 3598.050000 2424.650000 3598.980000 ;
      RECT 2418.550000 3598.050000 2421.290000 3598.980000 ;
      RECT 2415.190000 3598.050000 2417.930000 3598.980000 ;
      RECT 2411.830000 3598.050000 2414.570000 3598.980000 ;
      RECT 2408.950000 3598.050000 2411.210000 3598.980000 ;
      RECT 2405.590000 3598.050000 2408.330000 3598.980000 ;
      RECT 2402.230000 3598.050000 2404.970000 3598.980000 ;
      RECT 2398.870000 3598.050000 2401.610000 3598.980000 ;
      RECT 2395.990000 3598.050000 2398.250000 3598.980000 ;
      RECT 2392.630000 3598.050000 2395.370000 3598.980000 ;
      RECT 2389.270000 3598.050000 2392.010000 3598.980000 ;
      RECT 2385.910000 3598.050000 2388.650000 3598.980000 ;
      RECT 2382.550000 3598.050000 2385.290000 3598.980000 ;
      RECT 2379.670000 3598.050000 2381.930000 3598.980000 ;
      RECT 2376.310000 3598.050000 2379.050000 3598.980000 ;
      RECT 2372.950000 3598.050000 2375.690000 3598.980000 ;
      RECT 2369.590000 3598.050000 2372.330000 3598.980000 ;
      RECT 2366.230000 3598.050000 2368.970000 3598.980000 ;
      RECT 2363.350000 3598.050000 2365.610000 3598.980000 ;
      RECT 2359.990000 3598.050000 2362.730000 3598.980000 ;
      RECT 2356.630000 3598.050000 2359.370000 3598.980000 ;
      RECT 2353.270000 3598.050000 2356.010000 3598.980000 ;
      RECT 2349.910000 3598.050000 2352.650000 3598.980000 ;
      RECT 2347.030000 3598.050000 2349.290000 3598.980000 ;
      RECT 2343.670000 3598.050000 2346.410000 3598.980000 ;
      RECT 2340.310000 3598.050000 2343.050000 3598.980000 ;
      RECT 2336.950000 3598.050000 2339.690000 3598.980000 ;
      RECT 2334.070000 3598.050000 2336.330000 3598.980000 ;
      RECT 2330.710000 3598.050000 2333.450000 3598.980000 ;
      RECT 2327.350000 3598.050000 2330.090000 3598.980000 ;
      RECT 2323.990000 3598.050000 2326.730000 3598.980000 ;
      RECT 2320.630000 3598.050000 2323.370000 3598.980000 ;
      RECT 2317.750000 3598.050000 2320.010000 3598.980000 ;
      RECT 2314.390000 3598.050000 2317.130000 3598.980000 ;
      RECT 2311.030000 3598.050000 2313.770000 3598.980000 ;
      RECT 2307.670000 3598.050000 2310.410000 3598.980000 ;
      RECT 2304.310000 3598.050000 2307.050000 3598.980000 ;
      RECT 2301.430000 3598.050000 2303.690000 3598.980000 ;
      RECT 2298.070000 3598.050000 2300.810000 3598.980000 ;
      RECT 2294.710000 3598.050000 2297.450000 3598.980000 ;
      RECT 2291.350000 3598.050000 2294.090000 3598.980000 ;
      RECT 2287.990000 3598.050000 2290.730000 3598.980000 ;
      RECT 2285.110000 3598.050000 2287.370000 3598.980000 ;
      RECT 2281.750000 3598.050000 2284.490000 3598.980000 ;
      RECT 2278.390000 3598.050000 2281.130000 3598.980000 ;
      RECT 2275.030000 3598.050000 2277.770000 3598.980000 ;
      RECT 2272.150000 3598.050000 2274.410000 3598.980000 ;
      RECT 2268.790000 3598.050000 2271.530000 3598.980000 ;
      RECT 2265.430000 3598.050000 2268.170000 3598.980000 ;
      RECT 2262.070000 3598.050000 2264.810000 3598.980000 ;
      RECT 2258.710000 3598.050000 2261.450000 3598.980000 ;
      RECT 2255.830000 3598.050000 2258.090000 3598.980000 ;
      RECT 2252.470000 3598.050000 2255.210000 3598.980000 ;
      RECT 2249.110000 3598.050000 2251.850000 3598.980000 ;
      RECT 2245.750000 3598.050000 2248.490000 3598.980000 ;
      RECT 2242.390000 3598.050000 2245.130000 3598.980000 ;
      RECT 2239.510000 3598.050000 2241.770000 3598.980000 ;
      RECT 2236.150000 3598.050000 2238.890000 3598.980000 ;
      RECT 2232.790000 3598.050000 2235.530000 3598.980000 ;
      RECT 2229.430000 3598.050000 2232.170000 3598.980000 ;
      RECT 2226.070000 3598.050000 2228.810000 3598.980000 ;
      RECT 2223.190000 3598.050000 2225.450000 3598.980000 ;
      RECT 2219.830000 3598.050000 2222.570000 3598.980000 ;
      RECT 2216.470000 3598.050000 2219.210000 3598.980000 ;
      RECT 2213.110000 3598.050000 2215.850000 3598.980000 ;
      RECT 2210.230000 3598.050000 2212.490000 3598.980000 ;
      RECT 2206.870000 3598.050000 2209.610000 3598.980000 ;
      RECT 2203.510000 3598.050000 2206.250000 3598.980000 ;
      RECT 2200.150000 3598.050000 2202.890000 3598.980000 ;
      RECT 2196.790000 3598.050000 2199.530000 3598.980000 ;
      RECT 2193.910000 3598.050000 2196.170000 3598.980000 ;
      RECT 2190.550000 3598.050000 2193.290000 3598.980000 ;
      RECT 2187.190000 3598.050000 2189.930000 3598.980000 ;
      RECT 2183.830000 3598.050000 2186.570000 3598.980000 ;
      RECT 2180.470000 3598.050000 2183.210000 3598.980000 ;
      RECT 2177.590000 3598.050000 2179.850000 3598.980000 ;
      RECT 2174.230000 3598.050000 2176.970000 3598.980000 ;
      RECT 2170.870000 3598.050000 2173.610000 3598.980000 ;
      RECT 2167.510000 3598.050000 2170.250000 3598.980000 ;
      RECT 2164.150000 3598.050000 2166.890000 3598.980000 ;
      RECT 2161.270000 3598.050000 2163.530000 3598.980000 ;
      RECT 2157.910000 3598.050000 2160.650000 3598.980000 ;
      RECT 2154.550000 3598.050000 2157.290000 3598.980000 ;
      RECT 2151.190000 3598.050000 2153.930000 3598.980000 ;
      RECT 2148.310000 3598.050000 2150.570000 3598.980000 ;
      RECT 2144.950000 3598.050000 2147.690000 3598.980000 ;
      RECT 2141.590000 3598.050000 2144.330000 3598.980000 ;
      RECT 2138.230000 3598.050000 2140.970000 3598.980000 ;
      RECT 2134.870000 3598.050000 2137.610000 3598.980000 ;
      RECT 2131.990000 3598.050000 2134.250000 3598.980000 ;
      RECT 2128.630000 3598.050000 2131.370000 3598.980000 ;
      RECT 2125.270000 3598.050000 2128.010000 3598.980000 ;
      RECT 2121.910000 3598.050000 2124.650000 3598.980000 ;
      RECT 2118.550000 3598.050000 2121.290000 3598.980000 ;
      RECT 2115.670000 3598.050000 2117.930000 3598.980000 ;
      RECT 2112.310000 3598.050000 2115.050000 3598.980000 ;
      RECT 2108.950000 3598.050000 2111.690000 3598.980000 ;
      RECT 2105.590000 3598.050000 2108.330000 3598.980000 ;
      RECT 2102.230000 3598.050000 2104.970000 3598.980000 ;
      RECT 2099.350000 3598.050000 2101.610000 3598.980000 ;
      RECT 2095.990000 3598.050000 2098.730000 3598.980000 ;
      RECT 2092.630000 3598.050000 2095.370000 3598.980000 ;
      RECT 2089.270000 3598.050000 2092.010000 3598.980000 ;
      RECT 2086.390000 3598.050000 2088.650000 3598.980000 ;
      RECT 2083.030000 3598.050000 2085.770000 3598.980000 ;
      RECT 2079.670000 3598.050000 2082.410000 3598.980000 ;
      RECT 2076.310000 3598.050000 2079.050000 3598.980000 ;
      RECT 2072.950000 3598.050000 2075.690000 3598.980000 ;
      RECT 2070.070000 3598.050000 2072.330000 3598.980000 ;
      RECT 2066.710000 3598.050000 2069.450000 3598.980000 ;
      RECT 2063.350000 3598.050000 2066.090000 3598.980000 ;
      RECT 2059.990000 3598.050000 2062.730000 3598.980000 ;
      RECT 2056.630000 3598.050000 2059.370000 3598.980000 ;
      RECT 2053.750000 3598.050000 2056.010000 3598.980000 ;
      RECT 2050.390000 3598.050000 2053.130000 3598.980000 ;
      RECT 2047.030000 3598.050000 2049.770000 3598.980000 ;
      RECT 2043.670000 3598.050000 2046.410000 3598.980000 ;
      RECT 2040.790000 3598.050000 2043.050000 3598.980000 ;
      RECT 2037.430000 3598.050000 2040.170000 3598.980000 ;
      RECT 2034.070000 3598.050000 2036.810000 3598.980000 ;
      RECT 2030.710000 3598.050000 2033.450000 3598.980000 ;
      RECT 2027.350000 3598.050000 2030.090000 3598.980000 ;
      RECT 2024.470000 3598.050000 2026.730000 3598.980000 ;
      RECT 2021.110000 3598.050000 2023.850000 3598.980000 ;
      RECT 2017.750000 3598.050000 2020.490000 3598.980000 ;
      RECT 2014.390000 3598.050000 2017.130000 3598.980000 ;
      RECT 2011.030000 3598.050000 2013.770000 3598.980000 ;
      RECT 2008.150000 3598.050000 2010.410000 3598.980000 ;
      RECT 2004.790000 3598.050000 2007.530000 3598.980000 ;
      RECT 2001.430000 3598.050000 2004.170000 3598.980000 ;
      RECT 1998.070000 3598.050000 2000.810000 3598.980000 ;
      RECT 1994.710000 3598.050000 1997.450000 3598.980000 ;
      RECT 1991.830000 3598.050000 1994.090000 3598.980000 ;
      RECT 1988.470000 3598.050000 1991.210000 3598.980000 ;
      RECT 1985.110000 3598.050000 1987.850000 3598.980000 ;
      RECT 1981.750000 3598.050000 1984.490000 3598.980000 ;
      RECT 1978.870000 3598.050000 1981.130000 3598.980000 ;
      RECT 1975.510000 3598.050000 1978.250000 3598.980000 ;
      RECT 1972.150000 3598.050000 1974.890000 3598.980000 ;
      RECT 1968.790000 3598.050000 1971.530000 3598.980000 ;
      RECT 1965.430000 3598.050000 1968.170000 3598.980000 ;
      RECT 1962.550000 3598.050000 1964.810000 3598.980000 ;
      RECT 1959.190000 3598.050000 1961.930000 3598.980000 ;
      RECT 1955.830000 3598.050000 1958.570000 3598.980000 ;
      RECT 1952.470000 3598.050000 1955.210000 3598.980000 ;
      RECT 1949.110000 3598.050000 1951.850000 3598.980000 ;
      RECT 1946.230000 3598.050000 1948.490000 3598.980000 ;
      RECT 1942.870000 3598.050000 1945.610000 3598.980000 ;
      RECT 1939.510000 3598.050000 1942.250000 3598.980000 ;
      RECT 1936.150000 3598.050000 1938.890000 3598.980000 ;
      RECT 1932.790000 3598.050000 1935.530000 3598.980000 ;
      RECT 1929.910000 3598.050000 1932.170000 3598.980000 ;
      RECT 1926.550000 3598.050000 1929.290000 3598.980000 ;
      RECT 1923.190000 3598.050000 1925.930000 3598.980000 ;
      RECT 1919.830000 3598.050000 1922.570000 3598.980000 ;
      RECT 1916.950000 3598.050000 1919.210000 3598.980000 ;
      RECT 1913.590000 3598.050000 1916.330000 3598.980000 ;
      RECT 1910.230000 3598.050000 1912.970000 3598.980000 ;
      RECT 1906.870000 3598.050000 1909.610000 3598.980000 ;
      RECT 1903.510000 3598.050000 1906.250000 3598.980000 ;
      RECT 1900.630000 3598.050000 1902.890000 3598.980000 ;
      RECT 1897.270000 3598.050000 1900.010000 3598.980000 ;
      RECT 1893.910000 3598.050000 1896.650000 3598.980000 ;
      RECT 1890.550000 3598.050000 1893.290000 3598.980000 ;
      RECT 1887.190000 3598.050000 1889.930000 3598.980000 ;
      RECT 1884.310000 3598.050000 1886.570000 3598.980000 ;
      RECT 1880.950000 3598.050000 1883.690000 3598.980000 ;
      RECT 1877.590000 3598.050000 1880.330000 3598.980000 ;
      RECT 1874.230000 3598.050000 1876.970000 3598.980000 ;
      RECT 1870.870000 3598.050000 1873.610000 3598.980000 ;
      RECT 1867.990000 3598.050000 1870.250000 3598.980000 ;
      RECT 1864.630000 3598.050000 1867.370000 3598.980000 ;
      RECT 1861.270000 3598.050000 1864.010000 3598.980000 ;
      RECT 1857.430000 3598.050000 1860.650000 3598.980000 ;
      RECT 1854.550000 3598.050000 1856.810000 3598.980000 ;
      RECT 1851.670000 3598.050000 1853.930000 3598.980000 ;
      RECT 1848.310000 3598.050000 1851.050000 3598.980000 ;
      RECT 1844.950000 3598.050000 1847.690000 3598.980000 ;
      RECT 1841.110000 3598.050000 1844.330000 3598.980000 ;
      RECT 1838.710000 3598.050000 1840.490000 3598.980000 ;
      RECT 1835.350000 3598.050000 1838.090000 3598.980000 ;
      RECT 1831.990000 3598.050000 1834.730000 3598.980000 ;
      RECT 1828.630000 3598.050000 1831.370000 3598.980000 ;
      RECT 1825.270000 3598.050000 1828.010000 3598.980000 ;
      RECT 1822.390000 3598.050000 1824.650000 3598.980000 ;
      RECT 1819.030000 3598.050000 1821.770000 3598.980000 ;
      RECT 1815.670000 3598.050000 1818.410000 3598.980000 ;
      RECT 1812.310000 3598.050000 1815.050000 3598.980000 ;
      RECT 1808.950000 3598.050000 1811.690000 3598.980000 ;
      RECT 1806.070000 3598.050000 1808.330000 3598.980000 ;
      RECT 1802.710000 3598.050000 1805.450000 3598.980000 ;
      RECT 1799.350000 3598.050000 1802.090000 3598.980000 ;
      RECT 1795.990000 3598.050000 1798.730000 3598.980000 ;
      RECT 1793.110000 3598.050000 1795.370000 3598.980000 ;
      RECT 1789.750000 3598.050000 1792.490000 3598.980000 ;
      RECT 1786.390000 3598.050000 1789.130000 3598.980000 ;
      RECT 1783.030000 3598.050000 1785.770000 3598.980000 ;
      RECT 1779.670000 3598.050000 1782.410000 3598.980000 ;
      RECT 1776.790000 3598.050000 1779.050000 3598.980000 ;
      RECT 1773.430000 3598.050000 1776.170000 3598.980000 ;
      RECT 1770.070000 3598.050000 1772.810000 3598.980000 ;
      RECT 1766.710000 3598.050000 1769.450000 3598.980000 ;
      RECT 1763.350000 3598.050000 1766.090000 3598.980000 ;
      RECT 1760.470000 3598.050000 1762.730000 3598.980000 ;
      RECT 1757.110000 3598.050000 1759.850000 3598.980000 ;
      RECT 1753.750000 3598.050000 1756.490000 3598.980000 ;
      RECT 1749.910000 3598.050000 1753.130000 3598.980000 ;
      RECT 1747.030000 3598.050000 1749.290000 3598.980000 ;
      RECT 1744.150000 3598.050000 1746.410000 3598.980000 ;
      RECT 1740.790000 3598.050000 1743.530000 3598.980000 ;
      RECT 1737.430000 3598.050000 1740.170000 3598.980000 ;
      RECT 1734.070000 3598.050000 1736.810000 3598.980000 ;
      RECT 1731.190000 3598.050000 1733.450000 3598.980000 ;
      RECT 1727.830000 3598.050000 1730.570000 3598.980000 ;
      RECT 1724.470000 3598.050000 1727.210000 3598.980000 ;
      RECT 1721.110000 3598.050000 1723.850000 3598.980000 ;
      RECT 1717.750000 3598.050000 1720.490000 3598.980000 ;
      RECT 1714.870000 3598.050000 1717.130000 3598.980000 ;
      RECT 1711.510000 3598.050000 1714.250000 3598.980000 ;
      RECT 1708.150000 3598.050000 1710.890000 3598.980000 ;
      RECT 1704.790000 3598.050000 1707.530000 3598.980000 ;
      RECT 1701.430000 3598.050000 1704.170000 3598.980000 ;
      RECT 1698.550000 3598.050000 1700.810000 3598.980000 ;
      RECT 1695.190000 3598.050000 1697.930000 3598.980000 ;
      RECT 1691.830000 3598.050000 1694.570000 3598.980000 ;
      RECT 1688.470000 3598.050000 1691.210000 3598.980000 ;
      RECT 1685.110000 3598.050000 1687.850000 3598.980000 ;
      RECT 1682.230000 3598.050000 1684.490000 3598.980000 ;
      RECT 1678.870000 3598.050000 1681.610000 3598.980000 ;
      RECT 1675.510000 3598.050000 1678.250000 3598.980000 ;
      RECT 1672.150000 3598.050000 1674.890000 3598.980000 ;
      RECT 1669.270000 3598.050000 1671.530000 3598.980000 ;
      RECT 1665.910000 3598.050000 1668.650000 3598.980000 ;
      RECT 1662.550000 3598.050000 1665.290000 3598.980000 ;
      RECT 1659.190000 3598.050000 1661.930000 3598.980000 ;
      RECT 1655.830000 3598.050000 1658.570000 3598.980000 ;
      RECT 1652.950000 3598.050000 1655.210000 3598.980000 ;
      RECT 1649.590000 3598.050000 1652.330000 3598.980000 ;
      RECT 1646.230000 3598.050000 1648.970000 3598.980000 ;
      RECT 1642.870000 3598.050000 1645.610000 3598.980000 ;
      RECT 1639.510000 3598.050000 1642.250000 3598.980000 ;
      RECT 1636.630000 3598.050000 1638.890000 3598.980000 ;
      RECT 1633.270000 3598.050000 1636.010000 3598.980000 ;
      RECT 1629.910000 3598.050000 1632.650000 3598.980000 ;
      RECT 1626.550000 3598.050000 1629.290000 3598.980000 ;
      RECT 1623.190000 3598.050000 1625.930000 3598.980000 ;
      RECT 1620.310000 3598.050000 1622.570000 3598.980000 ;
      RECT 1616.950000 3598.050000 1619.690000 3598.980000 ;
      RECT 1613.590000 3598.050000 1616.330000 3598.980000 ;
      RECT 1610.230000 3598.050000 1612.970000 3598.980000 ;
      RECT 1607.350000 3598.050000 1609.610000 3598.980000 ;
      RECT 1603.990000 3598.050000 1606.730000 3598.980000 ;
      RECT 1600.630000 3598.050000 1603.370000 3598.980000 ;
      RECT 1597.270000 3598.050000 1600.010000 3598.980000 ;
      RECT 1593.910000 3598.050000 1596.650000 3598.980000 ;
      RECT 1591.030000 3598.050000 1593.290000 3598.980000 ;
      RECT 1587.670000 3598.050000 1590.410000 3598.980000 ;
      RECT 1584.310000 3598.050000 1587.050000 3598.980000 ;
      RECT 1580.950000 3598.050000 1583.690000 3598.980000 ;
      RECT 1577.590000 3598.050000 1580.330000 3598.980000 ;
      RECT 1574.710000 3598.050000 1576.970000 3598.980000 ;
      RECT 1571.350000 3598.050000 1574.090000 3598.980000 ;
      RECT 1567.990000 3598.050000 1570.730000 3598.980000 ;
      RECT 1564.630000 3598.050000 1567.370000 3598.980000 ;
      RECT 1561.270000 3598.050000 1564.010000 3598.980000 ;
      RECT 1558.390000 3598.050000 1560.650000 3598.980000 ;
      RECT 1555.030000 3598.050000 1557.770000 3598.980000 ;
      RECT 1551.670000 3598.050000 1554.410000 3598.980000 ;
      RECT 1548.310000 3598.050000 1551.050000 3598.980000 ;
      RECT 1545.430000 3598.050000 1547.690000 3598.980000 ;
      RECT 1542.070000 3598.050000 1544.810000 3598.980000 ;
      RECT 1538.710000 3598.050000 1541.450000 3598.980000 ;
      RECT 1535.350000 3598.050000 1538.090000 3598.980000 ;
      RECT 1531.990000 3598.050000 1534.730000 3598.980000 ;
      RECT 1529.110000 3598.050000 1531.370000 3598.980000 ;
      RECT 1525.750000 3598.050000 1528.490000 3598.980000 ;
      RECT 1522.390000 3598.050000 1525.130000 3598.980000 ;
      RECT 1519.030000 3598.050000 1521.770000 3598.980000 ;
      RECT 1515.670000 3598.050000 1518.410000 3598.980000 ;
      RECT 1512.790000 3598.050000 1515.050000 3598.980000 ;
      RECT 1509.430000 3598.050000 1512.170000 3598.980000 ;
      RECT 1506.070000 3598.050000 1508.810000 3598.980000 ;
      RECT 1502.710000 3598.050000 1505.450000 3598.980000 ;
      RECT 1499.830000 3598.050000 1502.090000 3598.980000 ;
      RECT 1496.470000 3598.050000 1499.210000 3598.980000 ;
      RECT 1493.110000 3598.050000 1495.850000 3598.980000 ;
      RECT 1489.750000 3598.050000 1492.490000 3598.980000 ;
      RECT 1486.390000 3598.050000 1489.130000 3598.980000 ;
      RECT 1483.510000 3598.050000 1485.770000 3598.980000 ;
      RECT 1480.150000 3598.050000 1482.890000 3598.980000 ;
      RECT 1476.790000 3598.050000 1479.530000 3598.980000 ;
      RECT 1473.430000 3598.050000 1476.170000 3598.980000 ;
      RECT 1470.070000 3598.050000 1472.810000 3598.980000 ;
      RECT 1467.190000 3598.050000 1469.450000 3598.980000 ;
      RECT 1463.830000 3598.050000 1466.570000 3598.980000 ;
      RECT 1460.470000 3598.050000 1463.210000 3598.980000 ;
      RECT 1457.110000 3598.050000 1459.850000 3598.980000 ;
      RECT 1453.750000 3598.050000 1456.490000 3598.980000 ;
      RECT 1450.870000 3598.050000 1453.130000 3598.980000 ;
      RECT 1447.510000 3598.050000 1450.250000 3598.980000 ;
      RECT 1444.150000 3598.050000 1446.890000 3598.980000 ;
      RECT 1440.790000 3598.050000 1443.530000 3598.980000 ;
      RECT 1437.910000 3598.050000 1440.170000 3598.980000 ;
      RECT 1434.550000 3598.050000 1437.290000 3598.980000 ;
      RECT 1431.190000 3598.050000 1433.930000 3598.980000 ;
      RECT 1427.830000 3598.050000 1430.570000 3598.980000 ;
      RECT 1424.470000 3598.050000 1427.210000 3598.980000 ;
      RECT 1421.590000 3598.050000 1423.850000 3598.980000 ;
      RECT 1418.230000 3598.050000 1420.970000 3598.980000 ;
      RECT 1414.870000 3598.050000 1417.610000 3598.980000 ;
      RECT 1411.510000 3598.050000 1414.250000 3598.980000 ;
      RECT 1408.150000 3598.050000 1410.890000 3598.980000 ;
      RECT 1405.270000 3598.050000 1407.530000 3598.980000 ;
      RECT 1401.910000 3598.050000 1404.650000 3598.980000 ;
      RECT 1398.550000 3598.050000 1401.290000 3598.980000 ;
      RECT 1395.190000 3598.050000 1397.930000 3598.980000 ;
      RECT 1391.830000 3598.050000 1394.570000 3598.980000 ;
      RECT 1388.950000 3598.050000 1391.210000 3598.980000 ;
      RECT 1385.590000 3598.050000 1388.330000 3598.980000 ;
      RECT 1382.230000 3598.050000 1384.970000 3598.980000 ;
      RECT 1378.870000 3598.050000 1381.610000 3598.980000 ;
      RECT 1375.990000 3598.050000 1378.250000 3598.980000 ;
      RECT 1372.630000 3598.050000 1375.370000 3598.980000 ;
      RECT 1369.270000 3598.050000 1372.010000 3598.980000 ;
      RECT 1365.910000 3598.050000 1368.650000 3598.980000 ;
      RECT 1362.550000 3598.050000 1365.290000 3598.980000 ;
      RECT 1359.670000 3598.050000 1361.930000 3598.980000 ;
      RECT 1356.310000 3598.050000 1359.050000 3598.980000 ;
      RECT 1352.950000 3598.050000 1355.690000 3598.980000 ;
      RECT 1349.590000 3598.050000 1352.330000 3598.980000 ;
      RECT 1346.230000 3598.050000 1348.970000 3598.980000 ;
      RECT 1343.350000 3598.050000 1345.610000 3598.980000 ;
      RECT 1339.990000 3598.050000 1342.730000 3598.980000 ;
      RECT 1336.630000 3598.050000 1339.370000 3598.980000 ;
      RECT 1333.270000 3598.050000 1336.010000 3598.980000 ;
      RECT 1329.910000 3598.050000 1332.650000 3598.980000 ;
      RECT 1327.030000 3598.050000 1329.290000 3598.980000 ;
      RECT 1323.670000 3598.050000 1326.410000 3598.980000 ;
      RECT 1320.310000 3598.050000 1323.050000 3598.980000 ;
      RECT 1316.950000 3598.050000 1319.690000 3598.980000 ;
      RECT 1314.070000 3598.050000 1316.330000 3598.980000 ;
      RECT 1310.710000 3598.050000 1313.450000 3598.980000 ;
      RECT 1307.350000 3598.050000 1310.090000 3598.980000 ;
      RECT 1303.990000 3598.050000 1306.730000 3598.980000 ;
      RECT 1300.630000 3598.050000 1303.370000 3598.980000 ;
      RECT 1297.750000 3598.050000 1300.010000 3598.980000 ;
      RECT 1294.390000 3598.050000 1297.130000 3598.980000 ;
      RECT 1291.030000 3598.050000 1293.770000 3598.980000 ;
      RECT 1287.670000 3598.050000 1290.410000 3598.980000 ;
      RECT 1284.310000 3598.050000 1287.050000 3598.980000 ;
      RECT 1281.430000 3598.050000 1283.690000 3598.980000 ;
      RECT 1278.070000 3598.050000 1280.810000 3598.980000 ;
      RECT 1274.710000 3598.050000 1277.450000 3598.980000 ;
      RECT 1271.350000 3598.050000 1274.090000 3598.980000 ;
      RECT 1267.990000 3598.050000 1270.730000 3598.980000 ;
      RECT 1265.110000 3598.050000 1267.370000 3598.980000 ;
      RECT 1261.750000 3598.050000 1264.490000 3598.980000 ;
      RECT 1258.390000 3598.050000 1261.130000 3598.980000 ;
      RECT 1255.030000 3598.050000 1257.770000 3598.980000 ;
      RECT 1252.150000 3598.050000 1254.410000 3598.980000 ;
      RECT 1248.790000 3598.050000 1251.530000 3598.980000 ;
      RECT 1245.430000 3598.050000 1248.170000 3598.980000 ;
      RECT 1242.070000 3598.050000 1244.810000 3598.980000 ;
      RECT 1238.710000 3598.050000 1241.450000 3598.980000 ;
      RECT 1235.830000 3598.050000 1238.090000 3598.980000 ;
      RECT 1232.470000 3598.050000 1235.210000 3598.980000 ;
      RECT 1229.110000 3598.050000 1231.850000 3598.980000 ;
      RECT 1225.750000 3598.050000 1228.490000 3598.980000 ;
      RECT 1222.390000 3598.050000 1225.130000 3598.980000 ;
      RECT 1219.510000 3598.050000 1221.770000 3598.980000 ;
      RECT 1216.150000 3598.050000 1218.890000 3598.980000 ;
      RECT 1212.790000 3598.050000 1215.530000 3598.980000 ;
      RECT 1209.430000 3598.050000 1212.170000 3598.980000 ;
      RECT 1206.070000 3598.050000 1208.810000 3598.980000 ;
      RECT 1203.190000 3598.050000 1205.450000 3598.980000 ;
      RECT 1199.830000 3598.050000 1202.570000 3598.980000 ;
      RECT 1196.470000 3598.050000 1199.210000 3598.980000 ;
      RECT 1193.110000 3598.050000 1195.850000 3598.980000 ;
      RECT 1190.230000 3598.050000 1192.490000 3598.980000 ;
      RECT 1186.870000 3598.050000 1189.610000 3598.980000 ;
      RECT 1183.510000 3598.050000 1186.250000 3598.980000 ;
      RECT 1180.150000 3598.050000 1182.890000 3598.980000 ;
      RECT 1176.790000 3598.050000 1179.530000 3598.980000 ;
      RECT 1173.910000 3598.050000 1176.170000 3598.980000 ;
      RECT 1170.550000 3598.050000 1173.290000 3598.980000 ;
      RECT 1167.190000 3598.050000 1169.930000 3598.980000 ;
      RECT 1163.830000 3598.050000 1166.570000 3598.980000 ;
      RECT 1160.470000 3598.050000 1163.210000 3598.980000 ;
      RECT 1157.590000 3598.050000 1159.850000 3598.980000 ;
      RECT 1154.230000 3598.050000 1156.970000 3598.980000 ;
      RECT 1150.870000 3598.050000 1153.610000 3598.980000 ;
      RECT 1147.510000 3598.050000 1150.250000 3598.980000 ;
      RECT 1144.150000 3598.050000 1146.890000 3598.980000 ;
      RECT 1141.270000 3598.050000 1143.530000 3598.980000 ;
      RECT 1137.910000 3598.050000 1140.650000 3598.980000 ;
      RECT 1134.550000 3598.050000 1137.290000 3598.980000 ;
      RECT 1131.190000 3598.050000 1133.930000 3598.980000 ;
      RECT 1128.310000 3598.050000 1130.570000 3598.980000 ;
      RECT 1124.950000 3598.050000 1127.690000 3598.980000 ;
      RECT 1121.590000 3598.050000 1124.330000 3598.980000 ;
      RECT 1118.230000 3598.050000 1120.970000 3598.980000 ;
      RECT 1114.870000 3598.050000 1117.610000 3598.980000 ;
      RECT 1111.990000 3598.050000 1114.250000 3598.980000 ;
      RECT 1108.630000 3598.050000 1111.370000 3598.980000 ;
      RECT 1105.270000 3598.050000 1108.010000 3598.980000 ;
      RECT 1101.910000 3598.050000 1104.650000 3598.980000 ;
      RECT 1098.550000 3598.050000 1101.290000 3598.980000 ;
      RECT 1095.670000 3598.050000 1097.930000 3598.980000 ;
      RECT 1092.310000 3598.050000 1095.050000 3598.980000 ;
      RECT 1088.950000 3598.050000 1091.690000 3598.980000 ;
      RECT 1085.590000 3598.050000 1088.330000 3598.980000 ;
      RECT 1082.230000 3598.050000 1084.970000 3598.980000 ;
      RECT 1079.350000 3598.050000 1081.610000 3598.980000 ;
      RECT 1075.990000 3598.050000 1078.730000 3598.980000 ;
      RECT 1072.630000 3598.050000 1075.370000 3598.980000 ;
      RECT 1069.270000 3598.050000 1072.010000 3598.980000 ;
      RECT 1066.390000 3598.050000 1068.650000 3598.980000 ;
      RECT 1063.030000 3598.050000 1065.770000 3598.980000 ;
      RECT 1059.670000 3598.050000 1062.410000 3598.980000 ;
      RECT 1056.310000 3598.050000 1059.050000 3598.980000 ;
      RECT 1052.950000 3598.050000 1055.690000 3598.980000 ;
      RECT 1050.070000 3598.050000 1052.330000 3598.980000 ;
      RECT 1046.710000 3598.050000 1049.450000 3598.980000 ;
      RECT 1043.350000 3598.050000 1046.090000 3598.980000 ;
      RECT 1039.990000 3598.050000 1042.730000 3598.980000 ;
      RECT 1036.630000 3598.050000 1039.370000 3598.980000 ;
      RECT 1033.750000 3598.050000 1036.010000 3598.980000 ;
      RECT 1030.390000 3598.050000 1033.130000 3598.980000 ;
      RECT 1027.030000 3598.050000 1029.770000 3598.980000 ;
      RECT 1023.670000 3598.050000 1026.410000 3598.980000 ;
      RECT 1020.790000 3598.050000 1023.050000 3598.980000 ;
      RECT 1017.430000 3598.050000 1020.170000 3598.980000 ;
      RECT 1014.070000 3598.050000 1016.810000 3598.980000 ;
      RECT 1010.710000 3598.050000 1013.450000 3598.980000 ;
      RECT 1007.350000 3598.050000 1010.090000 3598.980000 ;
      RECT 1004.470000 3598.050000 1006.730000 3598.980000 ;
      RECT 1001.110000 3598.050000 1003.850000 3598.980000 ;
      RECT 997.750000 3598.050000 1000.490000 3598.980000 ;
      RECT 994.390000 3598.050000 997.130000 3598.980000 ;
      RECT 991.030000 3598.050000 993.770000 3598.980000 ;
      RECT 988.150000 3598.050000 990.410000 3598.980000 ;
      RECT 984.790000 3598.050000 987.530000 3598.980000 ;
      RECT 981.430000 3598.050000 984.170000 3598.980000 ;
      RECT 978.070000 3598.050000 980.810000 3598.980000 ;
      RECT 974.710000 3598.050000 977.450000 3598.980000 ;
      RECT 971.830000 3598.050000 974.090000 3598.980000 ;
      RECT 968.470000 3598.050000 971.210000 3598.980000 ;
      RECT 965.110000 3598.050000 967.850000 3598.980000 ;
      RECT 961.750000 3598.050000 964.490000 3598.980000 ;
      RECT 958.870000 3598.050000 961.130000 3598.980000 ;
      RECT 955.510000 3598.050000 958.250000 3598.980000 ;
      RECT 952.150000 3598.050000 954.890000 3598.980000 ;
      RECT 948.790000 3598.050000 951.530000 3598.980000 ;
      RECT 945.430000 3598.050000 948.170000 3598.980000 ;
      RECT 942.550000 3598.050000 944.810000 3598.980000 ;
      RECT 939.190000 3598.050000 941.930000 3598.980000 ;
      RECT 935.830000 3598.050000 938.570000 3598.980000 ;
      RECT 932.470000 3598.050000 935.210000 3598.980000 ;
      RECT 929.110000 3598.050000 931.850000 3598.980000 ;
      RECT 926.230000 3598.050000 928.490000 3598.980000 ;
      RECT 922.870000 3598.050000 925.610000 3598.980000 ;
      RECT 919.510000 3598.050000 922.250000 3598.980000 ;
      RECT 916.150000 3598.050000 918.890000 3598.980000 ;
      RECT 912.790000 3598.050000 915.530000 3598.980000 ;
      RECT 909.910000 3598.050000 912.170000 3598.980000 ;
      RECT 906.550000 3598.050000 909.290000 3598.980000 ;
      RECT 903.190000 3598.050000 905.930000 3598.980000 ;
      RECT 899.830000 3598.050000 902.570000 3598.980000 ;
      RECT 896.950000 3598.050000 899.210000 3598.980000 ;
      RECT 893.590000 3598.050000 896.330000 3598.980000 ;
      RECT 890.230000 3598.050000 892.970000 3598.980000 ;
      RECT 886.870000 3598.050000 889.610000 3598.980000 ;
      RECT 883.510000 3598.050000 886.250000 3598.980000 ;
      RECT 880.630000 3598.050000 882.890000 3598.980000 ;
      RECT 877.270000 3598.050000 880.010000 3598.980000 ;
      RECT 873.910000 3598.050000 876.650000 3598.980000 ;
      RECT 870.550000 3598.050000 873.290000 3598.980000 ;
      RECT 867.190000 3598.050000 869.930000 3598.980000 ;
      RECT 864.310000 3598.050000 866.570000 3598.980000 ;
      RECT 860.950000 3598.050000 863.690000 3598.980000 ;
      RECT 857.590000 3598.050000 860.330000 3598.980000 ;
      RECT 854.230000 3598.050000 856.970000 3598.980000 ;
      RECT 850.870000 3598.050000 853.610000 3598.980000 ;
      RECT 847.990000 3598.050000 850.250000 3598.980000 ;
      RECT 844.630000 3598.050000 847.370000 3598.980000 ;
      RECT 841.270000 3598.050000 844.010000 3598.980000 ;
      RECT 837.910000 3598.050000 840.650000 3598.980000 ;
      RECT 835.030000 3598.050000 837.290000 3598.980000 ;
      RECT 831.670000 3598.050000 834.410000 3598.980000 ;
      RECT 828.310000 3598.050000 831.050000 3598.980000 ;
      RECT 824.950000 3598.050000 827.690000 3598.980000 ;
      RECT 821.590000 3598.050000 824.330000 3598.980000 ;
      RECT 818.710000 3598.050000 820.970000 3598.980000 ;
      RECT 815.350000 3598.050000 818.090000 3598.980000 ;
      RECT 811.990000 3598.050000 814.730000 3598.980000 ;
      RECT 808.630000 3598.050000 811.370000 3598.980000 ;
      RECT 805.270000 3598.050000 808.010000 3598.980000 ;
      RECT 802.390000 3598.050000 804.650000 3598.980000 ;
      RECT 799.030000 3598.050000 801.770000 3598.980000 ;
      RECT 795.670000 3598.050000 798.410000 3598.980000 ;
      RECT 792.310000 3598.050000 795.050000 3598.980000 ;
      RECT 788.950000 3598.050000 791.690000 3598.980000 ;
      RECT 786.070000 3598.050000 788.330000 3598.980000 ;
      RECT 782.710000 3598.050000 785.450000 3598.980000 ;
      RECT 779.350000 3598.050000 782.090000 3598.980000 ;
      RECT 775.990000 3598.050000 778.730000 3598.980000 ;
      RECT 773.110000 3598.050000 775.370000 3598.980000 ;
      RECT 769.750000 3598.050000 772.490000 3598.980000 ;
      RECT 766.390000 3598.050000 769.130000 3598.980000 ;
      RECT 763.030000 3598.050000 765.770000 3598.980000 ;
      RECT 759.670000 3598.050000 762.410000 3598.980000 ;
      RECT 756.790000 3598.050000 759.050000 3598.980000 ;
      RECT 753.430000 3598.050000 756.170000 3598.980000 ;
      RECT 750.070000 3598.050000 752.810000 3598.980000 ;
      RECT 746.710000 3598.050000 749.450000 3598.980000 ;
      RECT 743.350000 3598.050000 746.090000 3598.980000 ;
      RECT 740.470000 3598.050000 742.730000 3598.980000 ;
      RECT 737.110000 3598.050000 739.850000 3598.980000 ;
      RECT 733.750000 3598.050000 736.490000 3598.980000 ;
      RECT 730.390000 3598.050000 733.130000 3598.980000 ;
      RECT 727.030000 3598.050000 729.770000 3598.980000 ;
      RECT 724.150000 3598.050000 726.410000 3598.980000 ;
      RECT 720.790000 3598.050000 723.530000 3598.980000 ;
      RECT 717.430000 3598.050000 720.170000 3598.980000 ;
      RECT 714.070000 3598.050000 716.810000 3598.980000 ;
      RECT 711.190000 3598.050000 713.450000 3598.980000 ;
      RECT 707.830000 3598.050000 710.570000 3598.980000 ;
      RECT 704.470000 3598.050000 707.210000 3598.980000 ;
      RECT 701.110000 3598.050000 703.850000 3598.980000 ;
      RECT 697.750000 3598.050000 700.490000 3598.980000 ;
      RECT 694.870000 3598.050000 697.130000 3598.980000 ;
      RECT 691.510000 3598.050000 694.250000 3598.980000 ;
      RECT 688.150000 3598.050000 690.890000 3598.980000 ;
      RECT 684.790000 3598.050000 687.530000 3598.980000 ;
      RECT 681.430000 3598.050000 684.170000 3598.980000 ;
      RECT 678.550000 3598.050000 680.810000 3598.980000 ;
      RECT 675.190000 3598.050000 677.930000 3598.980000 ;
      RECT 671.830000 3598.050000 674.570000 3598.980000 ;
      RECT 668.470000 3598.050000 671.210000 3598.980000 ;
      RECT 665.110000 3598.050000 667.850000 3598.980000 ;
      RECT 662.230000 3598.050000 664.490000 3598.980000 ;
      RECT 658.870000 3598.050000 661.610000 3598.980000 ;
      RECT 655.510000 3598.050000 658.250000 3598.980000 ;
      RECT 652.150000 3598.050000 654.890000 3598.980000 ;
      RECT 649.270000 3598.050000 651.530000 3598.980000 ;
      RECT 645.910000 3598.050000 648.650000 3598.980000 ;
      RECT 642.550000 3598.050000 645.290000 3598.980000 ;
      RECT 639.190000 3598.050000 641.930000 3598.980000 ;
      RECT 635.830000 3598.050000 638.570000 3598.980000 ;
      RECT 632.950000 3598.050000 635.210000 3598.980000 ;
      RECT 629.590000 3598.050000 632.330000 3598.980000 ;
      RECT 626.230000 3598.050000 628.970000 3598.980000 ;
      RECT 622.870000 3598.050000 625.610000 3598.980000 ;
      RECT 619.510000 3598.050000 622.250000 3598.980000 ;
      RECT 616.630000 3598.050000 618.890000 3598.980000 ;
      RECT 613.270000 3598.050000 616.010000 3598.980000 ;
      RECT 609.910000 3598.050000 612.650000 3598.980000 ;
      RECT 606.550000 3598.050000 609.290000 3598.980000 ;
      RECT 603.190000 3598.050000 605.930000 3598.980000 ;
      RECT 600.310000 3598.050000 602.570000 3598.980000 ;
      RECT 596.950000 3598.050000 599.690000 3598.980000 ;
      RECT 593.590000 3598.050000 596.330000 3598.980000 ;
      RECT 590.230000 3598.050000 592.970000 3598.980000 ;
      RECT 587.350000 3598.050000 589.610000 3598.980000 ;
      RECT 583.990000 3598.050000 586.730000 3598.980000 ;
      RECT 580.630000 3598.050000 583.370000 3598.980000 ;
      RECT 577.270000 3598.050000 580.010000 3598.980000 ;
      RECT 573.910000 3598.050000 576.650000 3598.980000 ;
      RECT 571.030000 3598.050000 573.290000 3598.980000 ;
      RECT 567.670000 3598.050000 570.410000 3598.980000 ;
      RECT 564.310000 3598.050000 567.050000 3598.980000 ;
      RECT 560.950000 3598.050000 563.690000 3598.980000 ;
      RECT 557.590000 3598.050000 560.330000 3598.980000 ;
      RECT 554.710000 3598.050000 556.970000 3598.980000 ;
      RECT 551.350000 3598.050000 554.090000 3598.980000 ;
      RECT 547.990000 3598.050000 550.730000 3598.980000 ;
      RECT 544.630000 3598.050000 547.370000 3598.980000 ;
      RECT 541.270000 3598.050000 544.010000 3598.980000 ;
      RECT 538.390000 3598.050000 540.650000 3598.980000 ;
      RECT 535.030000 3598.050000 537.770000 3598.980000 ;
      RECT 531.670000 3598.050000 534.410000 3598.980000 ;
      RECT 528.310000 3598.050000 531.050000 3598.980000 ;
      RECT 525.430000 3598.050000 527.690000 3598.980000 ;
      RECT 522.070000 3598.050000 524.810000 3598.980000 ;
      RECT 518.710000 3598.050000 521.450000 3598.980000 ;
      RECT 515.350000 3598.050000 518.090000 3598.980000 ;
      RECT 511.990000 3598.050000 514.730000 3598.980000 ;
      RECT 509.110000 3598.050000 511.370000 3598.980000 ;
      RECT 505.750000 3598.050000 508.490000 3598.980000 ;
      RECT 502.390000 3598.050000 505.130000 3598.980000 ;
      RECT 499.030000 3598.050000 501.770000 3598.980000 ;
      RECT 495.670000 3598.050000 498.410000 3598.980000 ;
      RECT 492.790000 3598.050000 495.050000 3598.980000 ;
      RECT 489.430000 3598.050000 492.170000 3598.980000 ;
      RECT 486.070000 3598.050000 488.810000 3598.980000 ;
      RECT 482.710000 3598.050000 485.450000 3598.980000 ;
      RECT 479.830000 3598.050000 482.090000 3598.980000 ;
      RECT 476.470000 3598.050000 479.210000 3598.980000 ;
      RECT 473.110000 3598.050000 475.850000 3598.980000 ;
      RECT 469.750000 3598.050000 472.490000 3598.980000 ;
      RECT 466.390000 3598.050000 469.130000 3598.980000 ;
      RECT 463.510000 3598.050000 465.770000 3598.980000 ;
      RECT 460.150000 3598.050000 462.890000 3598.980000 ;
      RECT 456.790000 3598.050000 459.530000 3598.980000 ;
      RECT 453.430000 3598.050000 456.170000 3598.980000 ;
      RECT 450.070000 3598.050000 452.810000 3598.980000 ;
      RECT 447.190000 3598.050000 449.450000 3598.980000 ;
      RECT 443.830000 3598.050000 446.570000 3598.980000 ;
      RECT 440.470000 3598.050000 443.210000 3598.980000 ;
      RECT 437.110000 3598.050000 439.850000 3598.980000 ;
      RECT 433.750000 3598.050000 436.490000 3598.980000 ;
      RECT 430.870000 3598.050000 433.130000 3598.980000 ;
      RECT 427.510000 3598.050000 430.250000 3598.980000 ;
      RECT 424.150000 3598.050000 426.890000 3598.980000 ;
      RECT 420.790000 3598.050000 423.530000 3598.980000 ;
      RECT 417.910000 3598.050000 420.170000 3598.980000 ;
      RECT 414.550000 3598.050000 417.290000 3598.980000 ;
      RECT 411.190000 3598.050000 413.930000 3598.980000 ;
      RECT 407.830000 3598.050000 410.570000 3598.980000 ;
      RECT 404.470000 3598.050000 407.210000 3598.980000 ;
      RECT 401.590000 3598.050000 403.850000 3598.980000 ;
      RECT 398.230000 3598.050000 400.970000 3598.980000 ;
      RECT 394.870000 3598.050000 397.610000 3598.980000 ;
      RECT 391.510000 3598.050000 394.250000 3598.980000 ;
      RECT 388.150000 3598.050000 390.890000 3598.980000 ;
      RECT 385.270000 3598.050000 387.530000 3598.980000 ;
      RECT 381.910000 3598.050000 384.650000 3598.980000 ;
      RECT 378.550000 3598.050000 381.290000 3598.980000 ;
      RECT 375.190000 3598.050000 377.930000 3598.980000 ;
      RECT 371.830000 3598.050000 374.570000 3598.980000 ;
      RECT 368.950000 3598.050000 371.210000 3598.980000 ;
      RECT 365.590000 3598.050000 368.330000 3598.980000 ;
      RECT 362.230000 3598.050000 364.970000 3598.980000 ;
      RECT 358.870000 3598.050000 361.610000 3598.980000 ;
      RECT 355.990000 3598.050000 358.250000 3598.980000 ;
      RECT 352.630000 3598.050000 355.370000 3598.980000 ;
      RECT 349.270000 3598.050000 352.010000 3598.980000 ;
      RECT 345.910000 3598.050000 348.650000 3598.980000 ;
      RECT 342.550000 3598.050000 345.290000 3598.980000 ;
      RECT 339.670000 3598.050000 341.930000 3598.980000 ;
      RECT 336.310000 3598.050000 339.050000 3598.980000 ;
      RECT 332.950000 3598.050000 335.690000 3598.980000 ;
      RECT 329.590000 3598.050000 332.330000 3598.980000 ;
      RECT 326.230000 3598.050000 328.970000 3598.980000 ;
      RECT 323.350000 3598.050000 325.610000 3598.980000 ;
      RECT 319.990000 3598.050000 322.730000 3598.980000 ;
      RECT 316.630000 3598.050000 319.370000 3598.980000 ;
      RECT 313.270000 3598.050000 316.010000 3598.980000 ;
      RECT 309.910000 3598.050000 312.650000 3598.980000 ;
      RECT 307.030000 3598.050000 309.290000 3598.980000 ;
      RECT 303.670000 3598.050000 306.410000 3598.980000 ;
      RECT 300.310000 3598.050000 303.050000 3598.980000 ;
      RECT 296.950000 3598.050000 299.690000 3598.980000 ;
      RECT 294.070000 3598.050000 296.330000 3598.980000 ;
      RECT 290.710000 3598.050000 293.450000 3598.980000 ;
      RECT 287.350000 3598.050000 290.090000 3598.980000 ;
      RECT 283.990000 3598.050000 286.730000 3598.980000 ;
      RECT 280.630000 3598.050000 283.370000 3598.980000 ;
      RECT 277.750000 3598.050000 280.010000 3598.980000 ;
      RECT 274.390000 3598.050000 277.130000 3598.980000 ;
      RECT 271.030000 3598.050000 273.770000 3598.980000 ;
      RECT 267.670000 3598.050000 270.410000 3598.980000 ;
      RECT 264.310000 3598.050000 267.050000 3598.980000 ;
      RECT 261.430000 3598.050000 263.690000 3598.980000 ;
      RECT 258.070000 3598.050000 260.810000 3598.980000 ;
      RECT 254.710000 3598.050000 257.450000 3598.980000 ;
      RECT 251.350000 3598.050000 254.090000 3598.980000 ;
      RECT 247.990000 3598.050000 250.730000 3598.980000 ;
      RECT 245.110000 3598.050000 247.370000 3598.980000 ;
      RECT 241.750000 3598.050000 244.490000 3598.980000 ;
      RECT 238.390000 3598.050000 241.130000 3598.980000 ;
      RECT 235.030000 3598.050000 237.770000 3598.980000 ;
      RECT 232.150000 3598.050000 234.410000 3598.980000 ;
      RECT 228.790000 3598.050000 231.530000 3598.980000 ;
      RECT 225.430000 3598.050000 228.170000 3598.980000 ;
      RECT 222.070000 3598.050000 224.810000 3598.980000 ;
      RECT 218.710000 3598.050000 221.450000 3598.980000 ;
      RECT 215.830000 3598.050000 218.090000 3598.980000 ;
      RECT 212.470000 3598.050000 215.210000 3598.980000 ;
      RECT 209.110000 3598.050000 211.850000 3598.980000 ;
      RECT 205.750000 3598.050000 208.490000 3598.980000 ;
      RECT 202.390000 3598.050000 205.130000 3598.980000 ;
      RECT 199.510000 3598.050000 201.770000 3598.980000 ;
      RECT 196.150000 3598.050000 198.890000 3598.980000 ;
      RECT 192.790000 3598.050000 195.530000 3598.980000 ;
      RECT 189.430000 3598.050000 192.170000 3598.980000 ;
      RECT 186.070000 3598.050000 188.810000 3598.980000 ;
      RECT 183.190000 3598.050000 185.450000 3598.980000 ;
      RECT 179.830000 3598.050000 182.570000 3598.980000 ;
      RECT 176.470000 3598.050000 179.210000 3598.980000 ;
      RECT 173.110000 3598.050000 175.850000 3598.980000 ;
      RECT 170.230000 3598.050000 172.490000 3598.980000 ;
      RECT 166.870000 3598.050000 169.610000 3598.980000 ;
      RECT 163.510000 3598.050000 166.250000 3598.980000 ;
      RECT 160.150000 3598.050000 162.890000 3598.980000 ;
      RECT 156.790000 3598.050000 159.530000 3598.980000 ;
      RECT 153.910000 3598.050000 156.170000 3598.980000 ;
      RECT 150.550000 3598.050000 153.290000 3598.980000 ;
      RECT 147.190000 3598.050000 149.930000 3598.980000 ;
      RECT 143.830000 3598.050000 146.570000 3598.980000 ;
      RECT 140.470000 3598.050000 143.210000 3598.980000 ;
      RECT 137.590000 3598.050000 139.850000 3598.980000 ;
      RECT 134.230000 3598.050000 136.970000 3598.980000 ;
      RECT 130.870000 3598.050000 133.610000 3598.980000 ;
      RECT 127.510000 3598.050000 130.250000 3598.980000 ;
      RECT 124.150000 3598.050000 126.890000 3598.980000 ;
      RECT 121.270000 3598.050000 123.530000 3598.980000 ;
      RECT 117.910000 3598.050000 120.650000 3598.980000 ;
      RECT 114.550000 3598.050000 117.290000 3598.980000 ;
      RECT 111.190000 3598.050000 113.930000 3598.980000 ;
      RECT 108.310000 3598.050000 110.570000 3598.980000 ;
      RECT 104.950000 3598.050000 107.690000 3598.980000 ;
      RECT 101.590000 3598.050000 104.330000 3598.980000 ;
      RECT 98.230000 3598.050000 100.970000 3598.980000 ;
      RECT 94.870000 3598.050000 97.610000 3598.980000 ;
      RECT 91.990000 3598.050000 94.250000 3598.980000 ;
      RECT 88.630000 3598.050000 91.370000 3598.980000 ;
      RECT 85.270000 3598.050000 88.010000 3598.980000 ;
      RECT 81.910000 3598.050000 84.650000 3598.980000 ;
      RECT 78.550000 3598.050000 81.290000 3598.980000 ;
      RECT 75.670000 3598.050000 77.930000 3598.980000 ;
      RECT 72.310000 3598.050000 75.050000 3598.980000 ;
      RECT 68.950000 3598.050000 71.690000 3598.980000 ;
      RECT 65.590000 3598.050000 68.330000 3598.980000 ;
      RECT 62.230000 3598.050000 64.970000 3598.980000 ;
      RECT 59.350000 3598.050000 61.610000 3598.980000 ;
      RECT 55.990000 3598.050000 58.730000 3598.980000 ;
      RECT 52.630000 3598.050000 55.370000 3598.980000 ;
      RECT 49.270000 3598.050000 52.010000 3598.980000 ;
      RECT 46.390000 3598.050000 48.650000 3598.980000 ;
      RECT 43.030000 3598.050000 45.770000 3598.980000 ;
      RECT 39.670000 3598.050000 42.410000 3598.980000 ;
      RECT 36.310000 3598.050000 39.050000 3598.980000 ;
      RECT 32.950000 3598.050000 35.690000 3598.980000 ;
      RECT 30.070000 3598.050000 32.330000 3598.980000 ;
      RECT 26.710000 3598.050000 29.450000 3598.980000 ;
      RECT 23.350000 3598.050000 26.090000 3598.980000 ;
      RECT 19.990000 3598.050000 22.730000 3598.980000 ;
      RECT 18.070000 3598.050000 19.370000 3598.980000 ;
      RECT 14.710000 3598.050000 17.450000 3598.980000 ;
      RECT 12.790000 3598.050000 14.090000 3598.980000 ;
      RECT 9.910000 3598.050000 12.170000 3598.980000 ;
      RECT 7.030000 3598.050000 9.290000 3598.980000 ;
      RECT 4.150000 3598.050000 6.410000 3598.980000 ;
      RECT 0.000000 3598.050000 3.530000 3598.980000 ;
      RECT 0.000000 0.930000 3601.920000 3598.050000 ;
      RECT 3592.150000 0.000000 3601.920000 0.930000 ;
      RECT 3585.430000 0.000000 3591.530000 0.930000 ;
      RECT 3485.590000 0.000000 3584.810000 0.930000 ;
      RECT 3369.430000 0.000000 3484.970000 0.930000 ;
      RECT 3253.270000 0.000000 3368.810000 0.930000 ;
      RECT 3137.110000 0.000000 3252.650000 0.930000 ;
      RECT 3020.950000 0.000000 3136.490000 0.930000 ;
      RECT 2904.790000 0.000000 3020.330000 0.930000 ;
      RECT 2788.630000 0.000000 2904.170000 0.930000 ;
      RECT 2701.270000 0.000000 2788.010000 0.930000 ;
      RECT 2672.470000 0.000000 2700.650000 0.930000 ;
      RECT 2556.310000 0.000000 2671.850000 0.930000 ;
      RECT 2440.150000 0.000000 2555.690000 0.930000 ;
      RECT 2323.990000 0.000000 2439.530000 0.930000 ;
      RECT 2207.830000 0.000000 2323.370000 0.930000 ;
      RECT 2091.670000 0.000000 2207.210000 0.930000 ;
      RECT 1975.510000 0.000000 2091.050000 0.930000 ;
      RECT 1859.350000 0.000000 1974.890000 0.930000 ;
      RECT 1801.270000 0.000000 1858.730000 0.930000 ;
      RECT 1743.190000 0.000000 1800.650000 0.930000 ;
      RECT 1627.030000 0.000000 1742.570000 0.930000 ;
      RECT 1510.870000 0.000000 1626.410000 0.930000 ;
      RECT 1394.710000 0.000000 1510.250000 0.930000 ;
      RECT 1278.550000 0.000000 1394.090000 0.930000 ;
      RECT 1162.390000 0.000000 1277.930000 0.930000 ;
      RECT 1046.230000 0.000000 1161.770000 0.930000 ;
      RECT 930.070000 0.000000 1045.610000 0.930000 ;
      RECT 901.270000 0.000000 929.450000 0.930000 ;
      RECT 813.910000 0.000000 900.650000 0.930000 ;
      RECT 697.750000 0.000000 813.290000 0.930000 ;
      RECT 581.590000 0.000000 697.130000 0.930000 ;
      RECT 465.430000 0.000000 580.970000 0.930000 ;
      RECT 349.270000 0.000000 464.810000 0.930000 ;
      RECT 233.110000 0.000000 348.650000 0.930000 ;
      RECT 116.950000 0.000000 232.490000 0.930000 ;
      RECT 12.790000 0.000000 116.330000 0.930000 ;
      RECT 7.510000 0.000000 12.170000 0.930000 ;
      RECT 0.000000 0.000000 6.890000 0.930000 ;
    LAYER Metal4 ;
      RECT 0.000000 3593.830000 3601.920000 3598.980000 ;
      RECT 0.000000 3593.210000 3600.990000 3593.830000 ;
      RECT 0.000000 3592.150000 3601.920000 3593.210000 ;
      RECT 0.930000 3591.530000 3601.920000 3592.150000 ;
      RECT 0.000000 3577.870000 3601.920000 3591.530000 ;
      RECT 0.930000 3577.250000 3601.920000 3577.870000 ;
      RECT 0.000000 3556.870000 3601.920000 3577.250000 ;
      RECT 0.930000 3556.250000 3601.920000 3556.870000 ;
      RECT 0.000000 3536.290000 3601.920000 3556.250000 ;
      RECT 0.930000 3535.670000 3601.920000 3536.290000 ;
      RECT 0.000000 3515.290000 3601.920000 3535.670000 ;
      RECT 0.930000 3514.670000 3601.920000 3515.290000 ;
      RECT 0.000000 3494.710000 3601.920000 3514.670000 ;
      RECT 0.930000 3494.090000 3601.920000 3494.710000 ;
      RECT 0.000000 3473.710000 3601.920000 3494.090000 ;
      RECT 0.930000 3473.090000 3601.920000 3473.710000 ;
      RECT 0.000000 3453.130000 3601.920000 3473.090000 ;
      RECT 0.930000 3452.510000 3601.920000 3453.130000 ;
      RECT 0.000000 3432.130000 3601.920000 3452.510000 ;
      RECT 0.930000 3431.510000 3601.920000 3432.130000 ;
      RECT 0.000000 3411.550000 3601.920000 3431.510000 ;
      RECT 0.930000 3410.930000 3601.920000 3411.550000 ;
      RECT 0.000000 3390.550000 3601.920000 3410.930000 ;
      RECT 0.930000 3389.930000 3601.920000 3390.550000 ;
      RECT 0.000000 3369.970000 3601.920000 3389.930000 ;
      RECT 0.930000 3369.350000 3601.920000 3369.970000 ;
      RECT 0.000000 3348.970000 3601.920000 3369.350000 ;
      RECT 0.930000 3348.350000 3601.920000 3348.970000 ;
      RECT 0.000000 3328.390000 3601.920000 3348.350000 ;
      RECT 0.930000 3327.770000 3601.920000 3328.390000 ;
      RECT 0.000000 3307.390000 3601.920000 3327.770000 ;
      RECT 0.930000 3306.770000 3601.920000 3307.390000 ;
      RECT 0.000000 3286.810000 3601.920000 3306.770000 ;
      RECT 0.930000 3286.190000 3601.920000 3286.810000 ;
      RECT 0.000000 3265.810000 3601.920000 3286.190000 ;
      RECT 0.930000 3265.190000 3601.920000 3265.810000 ;
      RECT 0.000000 3245.230000 3601.920000 3265.190000 ;
      RECT 0.930000 3244.610000 3601.920000 3245.230000 ;
      RECT 0.000000 3224.230000 3601.920000 3244.610000 ;
      RECT 0.930000 3223.610000 3601.920000 3224.230000 ;
      RECT 0.000000 3203.650000 3601.920000 3223.610000 ;
      RECT 0.930000 3203.030000 3601.920000 3203.650000 ;
      RECT 0.000000 3182.650000 3601.920000 3203.030000 ;
      RECT 0.930000 3182.030000 3601.920000 3182.650000 ;
      RECT 0.000000 3162.070000 3601.920000 3182.030000 ;
      RECT 0.930000 3161.450000 3601.920000 3162.070000 ;
      RECT 0.000000 3141.070000 3601.920000 3161.450000 ;
      RECT 0.930000 3140.450000 3601.920000 3141.070000 ;
      RECT 0.000000 3120.490000 3601.920000 3140.450000 ;
      RECT 0.930000 3119.870000 3601.920000 3120.490000 ;
      RECT 0.000000 3099.490000 3601.920000 3119.870000 ;
      RECT 0.930000 3098.870000 3601.920000 3099.490000 ;
      RECT 0.000000 3085.210000 3601.920000 3098.870000 ;
      RECT 0.000000 3084.590000 3600.990000 3085.210000 ;
      RECT 0.000000 3078.490000 3601.920000 3084.590000 ;
      RECT 0.930000 3077.870000 3601.920000 3078.490000 ;
      RECT 0.000000 3057.910000 3601.920000 3077.870000 ;
      RECT 0.930000 3057.290000 3601.920000 3057.910000 ;
      RECT 0.000000 3036.910000 3601.920000 3057.290000 ;
      RECT 0.930000 3036.290000 3601.920000 3036.910000 ;
      RECT 0.000000 3016.330000 3601.920000 3036.290000 ;
      RECT 0.930000 3015.710000 3601.920000 3016.330000 ;
      RECT 0.000000 2995.330000 3601.920000 3015.710000 ;
      RECT 0.930000 2994.710000 3601.920000 2995.330000 ;
      RECT 0.000000 2974.750000 3601.920000 2994.710000 ;
      RECT 0.930000 2974.130000 3601.920000 2974.750000 ;
      RECT 0.000000 2953.750000 3601.920000 2974.130000 ;
      RECT 0.930000 2953.130000 3601.920000 2953.750000 ;
      RECT 0.000000 2933.170000 3601.920000 2953.130000 ;
      RECT 0.930000 2932.550000 3601.920000 2933.170000 ;
      RECT 0.000000 2912.170000 3601.920000 2932.550000 ;
      RECT 0.930000 2911.550000 3601.920000 2912.170000 ;
      RECT 0.000000 2891.590000 3601.920000 2911.550000 ;
      RECT 0.930000 2890.970000 3601.920000 2891.590000 ;
      RECT 0.000000 2870.590000 3601.920000 2890.970000 ;
      RECT 0.930000 2869.970000 3601.920000 2870.590000 ;
      RECT 0.000000 2850.010000 3601.920000 2869.970000 ;
      RECT 0.930000 2849.390000 3601.920000 2850.010000 ;
      RECT 0.000000 2829.010000 3601.920000 2849.390000 ;
      RECT 0.930000 2828.390000 3601.920000 2829.010000 ;
      RECT 0.000000 2808.430000 3601.920000 2828.390000 ;
      RECT 0.930000 2807.810000 3601.920000 2808.430000 ;
      RECT 0.000000 2787.430000 3601.920000 2807.810000 ;
      RECT 0.930000 2786.810000 3601.920000 2787.430000 ;
      RECT 0.000000 2766.850000 3601.920000 2786.810000 ;
      RECT 0.930000 2766.230000 3601.920000 2766.850000 ;
      RECT 0.000000 2745.850000 3601.920000 2766.230000 ;
      RECT 0.930000 2745.230000 3601.920000 2745.850000 ;
      RECT 0.000000 2725.270000 3601.920000 2745.230000 ;
      RECT 0.930000 2724.650000 3601.920000 2725.270000 ;
      RECT 0.000000 2704.270000 3601.920000 2724.650000 ;
      RECT 0.930000 2703.650000 3601.920000 2704.270000 ;
      RECT 0.000000 2683.690000 3601.920000 2703.650000 ;
      RECT 0.930000 2683.070000 3601.920000 2683.690000 ;
      RECT 0.000000 2662.690000 3601.920000 2683.070000 ;
      RECT 0.930000 2662.070000 3601.920000 2662.690000 ;
      RECT 0.000000 2642.110000 3601.920000 2662.070000 ;
      RECT 0.930000 2641.490000 3601.920000 2642.110000 ;
      RECT 0.000000 2621.110000 3601.920000 2641.490000 ;
      RECT 0.930000 2620.490000 3601.920000 2621.110000 ;
      RECT 0.000000 2600.530000 3601.920000 2620.490000 ;
      RECT 0.930000 2599.910000 3601.920000 2600.530000 ;
      RECT 0.000000 2579.530000 3601.920000 2599.910000 ;
      RECT 0.930000 2578.910000 3601.920000 2579.530000 ;
      RECT 0.000000 2571.130000 3601.920000 2578.910000 ;
      RECT 0.000000 2570.510000 3600.990000 2571.130000 ;
      RECT 0.000000 2558.530000 3601.920000 2570.510000 ;
      RECT 0.930000 2557.910000 3601.920000 2558.530000 ;
      RECT 0.000000 2537.950000 3601.920000 2557.910000 ;
      RECT 0.930000 2537.330000 3601.920000 2537.950000 ;
      RECT 0.000000 2516.950000 3601.920000 2537.330000 ;
      RECT 0.930000 2516.330000 3601.920000 2516.950000 ;
      RECT 0.000000 2496.370000 3601.920000 2516.330000 ;
      RECT 0.930000 2495.750000 3601.920000 2496.370000 ;
      RECT 0.000000 2475.370000 3601.920000 2495.750000 ;
      RECT 0.930000 2474.750000 3601.920000 2475.370000 ;
      RECT 0.000000 2454.790000 3601.920000 2474.750000 ;
      RECT 0.930000 2454.170000 3601.920000 2454.790000 ;
      RECT 0.000000 2433.790000 3601.920000 2454.170000 ;
      RECT 0.930000 2433.170000 3601.920000 2433.790000 ;
      RECT 0.000000 2413.210000 3601.920000 2433.170000 ;
      RECT 0.930000 2412.590000 3601.920000 2413.210000 ;
      RECT 0.000000 2392.210000 3601.920000 2412.590000 ;
      RECT 0.930000 2391.590000 3601.920000 2392.210000 ;
      RECT 0.000000 2371.630000 3601.920000 2391.590000 ;
      RECT 0.930000 2371.010000 3601.920000 2371.630000 ;
      RECT 0.000000 2350.630000 3601.920000 2371.010000 ;
      RECT 0.930000 2350.010000 3601.920000 2350.630000 ;
      RECT 0.000000 2330.050000 3601.920000 2350.010000 ;
      RECT 0.930000 2329.430000 3601.920000 2330.050000 ;
      RECT 0.000000 2309.050000 3601.920000 2329.430000 ;
      RECT 0.930000 2308.430000 3601.920000 2309.050000 ;
      RECT 0.000000 2288.470000 3601.920000 2308.430000 ;
      RECT 0.930000 2287.850000 3601.920000 2288.470000 ;
      RECT 0.000000 2267.470000 3601.920000 2287.850000 ;
      RECT 0.930000 2266.850000 3601.920000 2267.470000 ;
      RECT 0.000000 2246.890000 3601.920000 2266.850000 ;
      RECT 0.930000 2246.270000 3601.920000 2246.890000 ;
      RECT 0.000000 2225.890000 3601.920000 2246.270000 ;
      RECT 0.930000 2225.270000 3601.920000 2225.890000 ;
      RECT 0.000000 2205.310000 3601.920000 2225.270000 ;
      RECT 0.930000 2204.690000 3601.920000 2205.310000 ;
      RECT 0.000000 2184.310000 3601.920000 2204.690000 ;
      RECT 0.930000 2183.690000 3601.920000 2184.310000 ;
      RECT 0.000000 2163.730000 3601.920000 2183.690000 ;
      RECT 0.930000 2163.110000 3601.920000 2163.730000 ;
      RECT 0.000000 2142.730000 3601.920000 2163.110000 ;
      RECT 0.930000 2142.110000 3601.920000 2142.730000 ;
      RECT 0.000000 2122.150000 3601.920000 2142.110000 ;
      RECT 0.930000 2121.530000 3601.920000 2122.150000 ;
      RECT 0.000000 2101.150000 3601.920000 2121.530000 ;
      RECT 0.930000 2100.530000 3601.920000 2101.150000 ;
      RECT 0.000000 2080.570000 3601.920000 2100.530000 ;
      RECT 0.930000 2079.950000 3601.920000 2080.570000 ;
      RECT 0.000000 2059.570000 3601.920000 2079.950000 ;
      RECT 0.930000 2058.950000 3601.920000 2059.570000 ;
      RECT 0.000000 2057.050000 3601.920000 2058.950000 ;
      RECT 0.000000 2056.430000 3600.990000 2057.050000 ;
      RECT 0.000000 2038.570000 3601.920000 2056.430000 ;
      RECT 0.930000 2037.950000 3601.920000 2038.570000 ;
      RECT 0.000000 2017.990000 3601.920000 2037.950000 ;
      RECT 0.930000 2017.370000 3601.920000 2017.990000 ;
      RECT 0.000000 1996.990000 3601.920000 2017.370000 ;
      RECT 0.930000 1996.370000 3601.920000 1996.990000 ;
      RECT 0.000000 1976.410000 3601.920000 1996.370000 ;
      RECT 0.930000 1975.790000 3601.920000 1976.410000 ;
      RECT 0.000000 1955.410000 3601.920000 1975.790000 ;
      RECT 0.930000 1954.790000 3601.920000 1955.410000 ;
      RECT 0.000000 1934.830000 3601.920000 1954.790000 ;
      RECT 0.930000 1934.210000 3601.920000 1934.830000 ;
      RECT 0.000000 1913.830000 3601.920000 1934.210000 ;
      RECT 0.930000 1913.210000 3601.920000 1913.830000 ;
      RECT 0.000000 1893.250000 3601.920000 1913.210000 ;
      RECT 0.930000 1892.630000 3601.920000 1893.250000 ;
      RECT 0.000000 1872.670000 3601.920000 1892.630000 ;
      RECT 0.930000 1872.050000 3600.990000 1872.670000 ;
      RECT 0.000000 1871.830000 3601.920000 1872.050000 ;
      RECT 0.930000 1871.210000 3600.990000 1871.830000 ;
      RECT 0.000000 1870.990000 3601.920000 1871.210000 ;
      RECT 0.930000 1870.370000 3601.920000 1870.990000 ;
      RECT 0.000000 1851.670000 3601.920000 1870.370000 ;
      RECT 0.930000 1851.050000 3601.920000 1851.670000 ;
      RECT 0.000000 1830.670000 3601.920000 1851.050000 ;
      RECT 0.930000 1830.050000 3601.920000 1830.670000 ;
      RECT 0.000000 1822.270000 3601.920000 1830.050000 ;
      RECT 0.930000 1821.650000 3601.920000 1822.270000 ;
      RECT 0.000000 1821.430000 3601.920000 1821.650000 ;
      RECT 0.000000 1820.810000 3600.990000 1821.430000 ;
      RECT 0.000000 1810.090000 3601.920000 1820.810000 ;
      RECT 0.930000 1809.470000 3601.920000 1810.090000 ;
      RECT 0.000000 1789.090000 3601.920000 1809.470000 ;
      RECT 0.930000 1788.470000 3601.920000 1789.090000 ;
      RECT 0.000000 1777.750000 3601.920000 1788.470000 ;
      RECT 0.930000 1777.130000 3600.990000 1777.750000 ;
      RECT 0.000000 1768.510000 3601.920000 1777.130000 ;
      RECT 0.930000 1767.890000 3601.920000 1768.510000 ;
      RECT 0.000000 1747.510000 3601.920000 1767.890000 ;
      RECT 0.930000 1746.890000 3601.920000 1747.510000 ;
      RECT 0.000000 1728.190000 3601.920000 1746.890000 ;
      RECT 0.930000 1727.570000 3601.920000 1728.190000 ;
      RECT 0.000000 1726.510000 3601.920000 1727.570000 ;
      RECT 0.930000 1725.890000 3600.990000 1726.510000 ;
      RECT 0.000000 1705.930000 3601.920000 1725.890000 ;
      RECT 0.930000 1705.310000 3601.920000 1705.930000 ;
      RECT 0.000000 1685.350000 3601.920000 1705.310000 ;
      RECT 0.930000 1684.730000 3601.920000 1685.350000 ;
      RECT 0.000000 1664.350000 3601.920000 1684.730000 ;
      RECT 0.930000 1663.730000 3601.920000 1664.350000 ;
      RECT 0.000000 1643.770000 3601.920000 1663.730000 ;
      RECT 0.930000 1643.150000 3601.920000 1643.770000 ;
      RECT 0.000000 1622.770000 3601.920000 1643.150000 ;
      RECT 0.930000 1622.150000 3601.920000 1622.770000 ;
      RECT 0.000000 1602.190000 3601.920000 1622.150000 ;
      RECT 0.930000 1601.570000 3601.920000 1602.190000 ;
      RECT 0.000000 1581.190000 3601.920000 1601.570000 ;
      RECT 0.930000 1580.570000 3601.920000 1581.190000 ;
      RECT 0.000000 1560.610000 3601.920000 1580.570000 ;
      RECT 0.930000 1559.990000 3601.920000 1560.610000 ;
      RECT 0.000000 1542.970000 3601.920000 1559.990000 ;
      RECT 0.000000 1542.350000 3600.990000 1542.970000 ;
      RECT 0.000000 1539.610000 3601.920000 1542.350000 ;
      RECT 0.930000 1538.990000 3601.920000 1539.610000 ;
      RECT 0.000000 1518.610000 3601.920000 1538.990000 ;
      RECT 0.930000 1517.990000 3601.920000 1518.610000 ;
      RECT 0.000000 1498.030000 3601.920000 1517.990000 ;
      RECT 0.930000 1497.410000 3601.920000 1498.030000 ;
      RECT 0.000000 1477.030000 3601.920000 1497.410000 ;
      RECT 0.930000 1476.410000 3601.920000 1477.030000 ;
      RECT 0.000000 1456.450000 3601.920000 1476.410000 ;
      RECT 0.930000 1455.830000 3601.920000 1456.450000 ;
      RECT 0.000000 1435.450000 3601.920000 1455.830000 ;
      RECT 0.930000 1434.830000 3601.920000 1435.450000 ;
      RECT 0.000000 1414.870000 3601.920000 1434.830000 ;
      RECT 0.930000 1414.250000 3601.920000 1414.870000 ;
      RECT 0.000000 1393.870000 3601.920000 1414.250000 ;
      RECT 0.930000 1393.250000 3601.920000 1393.870000 ;
      RECT 0.000000 1373.290000 3601.920000 1393.250000 ;
      RECT 0.930000 1372.670000 3601.920000 1373.290000 ;
      RECT 0.000000 1352.290000 3601.920000 1372.670000 ;
      RECT 0.930000 1351.670000 3601.920000 1352.290000 ;
      RECT 0.000000 1331.710000 3601.920000 1351.670000 ;
      RECT 0.930000 1331.090000 3601.920000 1331.710000 ;
      RECT 0.000000 1310.710000 3601.920000 1331.090000 ;
      RECT 0.930000 1310.090000 3601.920000 1310.710000 ;
      RECT 0.000000 1290.130000 3601.920000 1310.090000 ;
      RECT 0.930000 1289.510000 3601.920000 1290.130000 ;
      RECT 0.000000 1269.130000 3601.920000 1289.510000 ;
      RECT 0.930000 1268.510000 3601.920000 1269.130000 ;
      RECT 0.000000 1248.550000 3601.920000 1268.510000 ;
      RECT 0.930000 1247.930000 3601.920000 1248.550000 ;
      RECT 0.000000 1227.550000 3601.920000 1247.930000 ;
      RECT 0.930000 1226.930000 3601.920000 1227.550000 ;
      RECT 0.000000 1206.970000 3601.920000 1226.930000 ;
      RECT 0.930000 1206.350000 3601.920000 1206.970000 ;
      RECT 0.000000 1185.970000 3601.920000 1206.350000 ;
      RECT 0.930000 1185.350000 3601.920000 1185.970000 ;
      RECT 0.000000 1165.390000 3601.920000 1185.350000 ;
      RECT 0.930000 1164.770000 3601.920000 1165.390000 ;
      RECT 0.000000 1144.390000 3601.920000 1164.770000 ;
      RECT 0.930000 1143.770000 3601.920000 1144.390000 ;
      RECT 0.000000 1123.810000 3601.920000 1143.770000 ;
      RECT 0.930000 1123.190000 3601.920000 1123.810000 ;
      RECT 0.000000 1102.810000 3601.920000 1123.190000 ;
      RECT 0.930000 1102.190000 3601.920000 1102.810000 ;
      RECT 0.000000 1082.230000 3601.920000 1102.190000 ;
      RECT 0.930000 1081.610000 3601.920000 1082.230000 ;
      RECT 0.000000 1061.230000 3601.920000 1081.610000 ;
      RECT 0.930000 1060.610000 3601.920000 1061.230000 ;
      RECT 0.000000 1040.650000 3601.920000 1060.610000 ;
      RECT 0.930000 1040.030000 3601.920000 1040.650000 ;
      RECT 0.000000 1028.890000 3601.920000 1040.030000 ;
      RECT 0.000000 1028.270000 3600.990000 1028.890000 ;
      RECT 0.000000 1019.650000 3601.920000 1028.270000 ;
      RECT 0.930000 1019.030000 3601.920000 1019.650000 ;
      RECT 0.000000 998.650000 3601.920000 1019.030000 ;
      RECT 0.930000 998.030000 3601.920000 998.650000 ;
      RECT 0.000000 978.070000 3601.920000 998.030000 ;
      RECT 0.930000 977.450000 3601.920000 978.070000 ;
      RECT 0.000000 957.070000 3601.920000 977.450000 ;
      RECT 0.930000 956.450000 3601.920000 957.070000 ;
      RECT 0.000000 936.490000 3601.920000 956.450000 ;
      RECT 0.930000 935.870000 3601.920000 936.490000 ;
      RECT 0.000000 915.490000 3601.920000 935.870000 ;
      RECT 0.930000 914.870000 3601.920000 915.490000 ;
      RECT 0.000000 894.910000 3601.920000 914.870000 ;
      RECT 0.930000 894.290000 3601.920000 894.910000 ;
      RECT 0.000000 873.910000 3601.920000 894.290000 ;
      RECT 0.930000 873.290000 3601.920000 873.910000 ;
      RECT 0.000000 853.330000 3601.920000 873.290000 ;
      RECT 0.930000 852.710000 3601.920000 853.330000 ;
      RECT 0.000000 832.330000 3601.920000 852.710000 ;
      RECT 0.930000 831.710000 3601.920000 832.330000 ;
      RECT 0.000000 811.750000 3601.920000 831.710000 ;
      RECT 0.930000 811.130000 3601.920000 811.750000 ;
      RECT 0.000000 790.750000 3601.920000 811.130000 ;
      RECT 0.930000 790.130000 3601.920000 790.750000 ;
      RECT 0.000000 770.170000 3601.920000 790.130000 ;
      RECT 0.930000 769.550000 3601.920000 770.170000 ;
      RECT 0.000000 749.170000 3601.920000 769.550000 ;
      RECT 0.930000 748.550000 3601.920000 749.170000 ;
      RECT 0.000000 728.590000 3601.920000 748.550000 ;
      RECT 0.930000 727.970000 3601.920000 728.590000 ;
      RECT 0.000000 707.590000 3601.920000 727.970000 ;
      RECT 0.930000 706.970000 3601.920000 707.590000 ;
      RECT 0.000000 687.010000 3601.920000 706.970000 ;
      RECT 0.930000 686.390000 3601.920000 687.010000 ;
      RECT 0.000000 666.010000 3601.920000 686.390000 ;
      RECT 0.930000 665.390000 3601.920000 666.010000 ;
      RECT 0.000000 645.430000 3601.920000 665.390000 ;
      RECT 0.930000 644.810000 3601.920000 645.430000 ;
      RECT 0.000000 624.430000 3601.920000 644.810000 ;
      RECT 0.930000 623.810000 3601.920000 624.430000 ;
      RECT 0.000000 603.850000 3601.920000 623.810000 ;
      RECT 0.930000 603.230000 3601.920000 603.850000 ;
      RECT 0.000000 582.850000 3601.920000 603.230000 ;
      RECT 0.930000 582.230000 3601.920000 582.850000 ;
      RECT 0.000000 562.270000 3601.920000 582.230000 ;
      RECT 0.930000 561.650000 3601.920000 562.270000 ;
      RECT 0.000000 541.270000 3601.920000 561.650000 ;
      RECT 0.930000 540.650000 3601.920000 541.270000 ;
      RECT 0.000000 520.690000 3601.920000 540.650000 ;
      RECT 0.930000 520.070000 3601.920000 520.690000 ;
      RECT 0.000000 514.810000 3601.920000 520.070000 ;
      RECT 0.000000 514.190000 3600.990000 514.810000 ;
      RECT 0.000000 499.690000 3601.920000 514.190000 ;
      RECT 0.930000 499.070000 3601.920000 499.690000 ;
      RECT 0.000000 478.690000 3601.920000 499.070000 ;
      RECT 0.930000 478.070000 3601.920000 478.690000 ;
      RECT 0.000000 458.110000 3601.920000 478.070000 ;
      RECT 0.930000 457.490000 3601.920000 458.110000 ;
      RECT 0.000000 437.110000 3601.920000 457.490000 ;
      RECT 0.930000 436.490000 3601.920000 437.110000 ;
      RECT 0.000000 416.530000 3601.920000 436.490000 ;
      RECT 0.930000 415.910000 3601.920000 416.530000 ;
      RECT 0.000000 395.530000 3601.920000 415.910000 ;
      RECT 0.930000 394.910000 3601.920000 395.530000 ;
      RECT 0.000000 374.950000 3601.920000 394.910000 ;
      RECT 0.930000 374.330000 3601.920000 374.950000 ;
      RECT 0.000000 353.950000 3601.920000 374.330000 ;
      RECT 0.930000 353.330000 3601.920000 353.950000 ;
      RECT 0.000000 333.370000 3601.920000 353.330000 ;
      RECT 0.930000 332.750000 3601.920000 333.370000 ;
      RECT 0.000000 312.370000 3601.920000 332.750000 ;
      RECT 0.930000 311.750000 3601.920000 312.370000 ;
      RECT 0.000000 291.790000 3601.920000 311.750000 ;
      RECT 0.930000 291.170000 3601.920000 291.790000 ;
      RECT 0.000000 270.790000 3601.920000 291.170000 ;
      RECT 0.930000 270.170000 3601.920000 270.790000 ;
      RECT 0.000000 250.210000 3601.920000 270.170000 ;
      RECT 0.930000 249.590000 3601.920000 250.210000 ;
      RECT 0.000000 229.210000 3601.920000 249.590000 ;
      RECT 0.930000 228.590000 3601.920000 229.210000 ;
      RECT 0.000000 208.630000 3601.920000 228.590000 ;
      RECT 0.930000 208.010000 3601.920000 208.630000 ;
      RECT 0.000000 187.630000 3601.920000 208.010000 ;
      RECT 0.930000 187.010000 3601.920000 187.630000 ;
      RECT 0.000000 167.050000 3601.920000 187.010000 ;
      RECT 0.930000 166.430000 3601.920000 167.050000 ;
      RECT 0.000000 146.050000 3601.920000 166.430000 ;
      RECT 0.930000 145.430000 3601.920000 146.050000 ;
      RECT 0.000000 125.470000 3601.920000 145.430000 ;
      RECT 0.930000 124.850000 3601.920000 125.470000 ;
      RECT 0.000000 104.470000 3601.920000 124.850000 ;
      RECT 0.930000 103.850000 3601.920000 104.470000 ;
      RECT 0.000000 83.890000 3601.920000 103.850000 ;
      RECT 0.930000 83.270000 3601.920000 83.890000 ;
      RECT 0.000000 62.890000 3601.920000 83.270000 ;
      RECT 0.930000 62.270000 3601.920000 62.890000 ;
      RECT 0.000000 42.310000 3601.920000 62.270000 ;
      RECT 0.930000 41.690000 3601.920000 42.310000 ;
      RECT 0.000000 21.310000 3601.920000 41.690000 ;
      RECT 0.930000 20.690000 3601.920000 21.310000 ;
      RECT 0.000000 8.290000 3601.920000 20.690000 ;
      RECT 0.930000 7.670000 3600.990000 8.290000 ;
      RECT 0.000000 0.000000 3601.920000 7.670000 ;
    LAYER Metal5 ;
      RECT 0.000000 0.930000 3601.920000 3598.980000 ;
      RECT 3597.910000 0.000000 3601.920000 0.930000 ;
      RECT 3485.590000 0.000000 3597.290000 0.930000 ;
      RECT 3369.430000 0.000000 3484.970000 0.930000 ;
      RECT 3253.270000 0.000000 3368.810000 0.930000 ;
      RECT 3137.110000 0.000000 3252.650000 0.930000 ;
      RECT 3020.950000 0.000000 3136.490000 0.930000 ;
      RECT 2904.790000 0.000000 3020.330000 0.930000 ;
      RECT 2788.630000 0.000000 2904.170000 0.930000 ;
      RECT 2672.470000 0.000000 2788.010000 0.930000 ;
      RECT 2556.310000 0.000000 2671.850000 0.930000 ;
      RECT 2440.150000 0.000000 2555.690000 0.930000 ;
      RECT 2323.990000 0.000000 2439.530000 0.930000 ;
      RECT 2207.830000 0.000000 2323.370000 0.930000 ;
      RECT 2091.670000 0.000000 2207.210000 0.930000 ;
      RECT 1975.510000 0.000000 2091.050000 0.930000 ;
      RECT 1875.190000 0.000000 1974.890000 0.930000 ;
      RECT 1859.350000 0.000000 1874.570000 0.930000 ;
      RECT 1743.190000 0.000000 1858.730000 0.930000 ;
      RECT 1627.030000 0.000000 1742.570000 0.930000 ;
      RECT 1510.870000 0.000000 1626.410000 0.930000 ;
      RECT 1394.710000 0.000000 1510.250000 0.930000 ;
      RECT 1278.550000 0.000000 1394.090000 0.930000 ;
      RECT 1162.390000 0.000000 1277.930000 0.930000 ;
      RECT 1046.230000 0.000000 1161.770000 0.930000 ;
      RECT 930.070000 0.000000 1045.610000 0.930000 ;
      RECT 813.910000 0.000000 929.450000 0.930000 ;
      RECT 697.750000 0.000000 813.290000 0.930000 ;
      RECT 581.590000 0.000000 697.130000 0.930000 ;
      RECT 465.430000 0.000000 580.970000 0.930000 ;
      RECT 349.270000 0.000000 464.810000 0.930000 ;
      RECT 233.110000 0.000000 348.650000 0.930000 ;
      RECT 116.950000 0.000000 232.490000 0.930000 ;
      RECT 4.150000 0.000000 116.330000 0.930000 ;
      RECT 0.000000 0.000000 3.530000 0.930000 ;
    LAYER TopMetal1 ;
      RECT 0.000000 1745.880000 3601.920000 3598.980000 ;
      RECT 3.280000 1740.960000 3601.920000 1745.880000 ;
      RECT 0.000000 0.000000 3601.920000 1740.960000 ;
    LAYER TopMetal2 ;
      RECT 0.000000 0.000000 3601.920000 3598.980000 ;
  END
END veer_wrapper

END LIBRARY
